# Generated deterministically by seda-macro-lef-normalizer-v1; recipe orfs-ng45-fakeram-metal3-coupledl2-pg-v1.
VERSION 5.8 ;
BUSBITCHARS "[]" ;
DIVIDERCHAR "/" ;

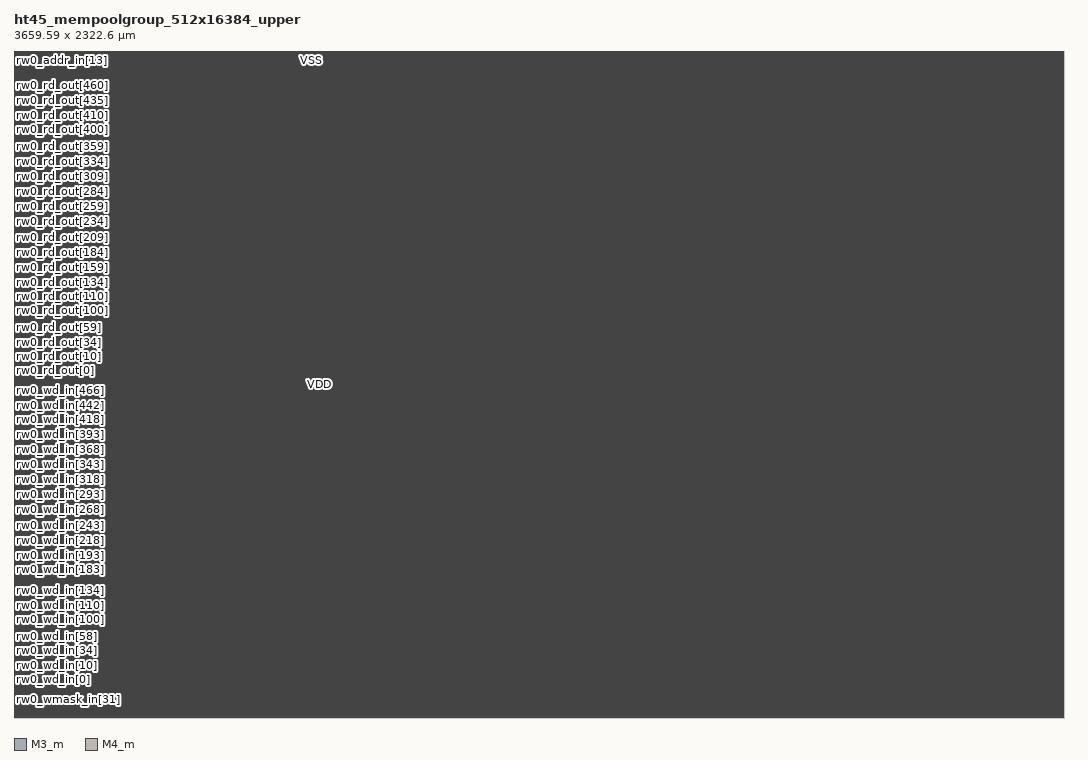
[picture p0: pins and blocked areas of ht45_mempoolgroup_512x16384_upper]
MACRO ht45_mempoolgroup_512x16384_upper
  FOREIGN ht45_mempoolgroup_512x16384_upper 0 0 ;
  CLASS COVER ;
  ORIGIN 0 0 ;
  SIZE 3659.59 BY 2322.6 ;
  SYMMETRY X Y R90 ;
  PIN rw0_wmask_in[0]
    DIRECTION INPUT ;
    USE SIGNAL ;
    SHAPE ABUTMENT ;
    PORT
      LAYER M3_m ;
      RECT 0 0.035 0.07 0.105 ;
    END
  END rw0_wmask_in[0]
  PIN rw0_wmask_in[1]
    DIRECTION INPUT ;
    USE SIGNAL ;
    SHAPE ABUTMENT ;
    PORT
      LAYER M3_m ;
      RECT 0 2.135 0.07 2.205 ;
    END
  END rw0_wmask_in[1]
  PIN rw0_wmask_in[2]
    DIRECTION INPUT ;
    USE SIGNAL ;
    SHAPE ABUTMENT ;
    PORT
      LAYER M3_m ;
      RECT 0 4.235 0.07 4.305 ;
    END
  END rw0_wmask_in[2]
  PIN rw0_wmask_in[3]
    DIRECTION INPUT ;
    USE SIGNAL ;
    SHAPE ABUTMENT ;
    PORT
      LAYER M3_m ;
      RECT 0 6.335 0.07 6.405 ;
    END
  END rw0_wmask_in[3]
  PIN rw0_wmask_in[4]
    DIRECTION INPUT ;
    USE SIGNAL ;
    SHAPE ABUTMENT ;
    PORT
      LAYER M3_m ;
      RECT 0 8.435 0.07 8.505 ;
    END
  END rw0_wmask_in[4]
  PIN rw0_wmask_in[5]
    DIRECTION INPUT ;
    USE SIGNAL ;
    SHAPE ABUTMENT ;
    PORT
      LAYER M3_m ;
      RECT 0 10.535 0.07 10.605 ;
    END
  END rw0_wmask_in[5]
  PIN rw0_wmask_in[6]
    DIRECTION INPUT ;
    USE SIGNAL ;
    SHAPE ABUTMENT ;
    PORT
      LAYER M3_m ;
      RECT 0 12.635 0.07 12.705 ;
    END
  END rw0_wmask_in[6]
  PIN rw0_wmask_in[7]
    DIRECTION INPUT ;
    USE SIGNAL ;
    SHAPE ABUTMENT ;
    PORT
      LAYER M3_m ;
      RECT 0 14.735 0.07 14.805 ;
    END
  END rw0_wmask_in[7]
  PIN rw0_wmask_in[8]
    DIRECTION INPUT ;
    USE SIGNAL ;
    SHAPE ABUTMENT ;
    PORT
      LAYER M3_m ;
      RECT 0 16.835 0.07 16.905 ;
    END
  END rw0_wmask_in[8]
  PIN rw0_wmask_in[9]
    DIRECTION INPUT ;
    USE SIGNAL ;
    SHAPE ABUTMENT ;
    PORT
      LAYER M3_m ;
      RECT 0 18.935 0.07 19.005 ;
    END
  END rw0_wmask_in[9]
  PIN rw0_wmask_in[10]
    DIRECTION INPUT ;
    USE SIGNAL ;
    SHAPE ABUTMENT ;
    PORT
      LAYER M3_m ;
      RECT 0 21.035 0.07 21.105 ;
    END
  END rw0_wmask_in[10]
  PIN rw0_wmask_in[11]
    DIRECTION INPUT ;
    USE SIGNAL ;
    SHAPE ABUTMENT ;
    PORT
      LAYER M3_m ;
      RECT 0 23.135 0.07 23.205 ;
    END
  END rw0_wmask_in[11]
  PIN rw0_wmask_in[12]
    DIRECTION INPUT ;
    USE SIGNAL ;
    SHAPE ABUTMENT ;
    PORT
      LAYER M3_m ;
      RECT 0 25.235 0.07 25.305 ;
    END
  END rw0_wmask_in[12]
  PIN rw0_wmask_in[13]
    DIRECTION INPUT ;
    USE SIGNAL ;
    SHAPE ABUTMENT ;
    PORT
      LAYER M3_m ;
      RECT 0 27.335 0.07 27.405 ;
    END
  END rw0_wmask_in[13]
  PIN rw0_wmask_in[14]
    DIRECTION INPUT ;
    USE SIGNAL ;
    SHAPE ABUTMENT ;
    PORT
      LAYER M3_m ;
      RECT 0 29.435 0.07 29.505 ;
    END
  END rw0_wmask_in[14]
  PIN rw0_wmask_in[15]
    DIRECTION INPUT ;
    USE SIGNAL ;
    SHAPE ABUTMENT ;
    PORT
      LAYER M3_m ;
      RECT 0 31.535 0.07 31.605 ;
    END
  END rw0_wmask_in[15]
  PIN rw0_wmask_in[16]
    DIRECTION INPUT ;
    USE SIGNAL ;
    SHAPE ABUTMENT ;
    PORT
      LAYER M3_m ;
      RECT 0 33.635 0.07 33.705 ;
    END
  END rw0_wmask_in[16]
  PIN rw0_wmask_in[17]
    DIRECTION INPUT ;
    USE SIGNAL ;
    SHAPE ABUTMENT ;
    PORT
      LAYER M3_m ;
      RECT 0 35.735 0.07 35.805 ;
    END
  END rw0_wmask_in[17]
  PIN rw0_wmask_in[18]
    DIRECTION INPUT ;
    USE SIGNAL ;
    SHAPE ABUTMENT ;
    PORT
      LAYER M3_m ;
      RECT 0 37.835 0.07 37.905 ;
    END
  END rw0_wmask_in[18]
  PIN rw0_wmask_in[19]
    DIRECTION INPUT ;
    USE SIGNAL ;
    SHAPE ABUTMENT ;
    PORT
      LAYER M3_m ;
      RECT 0 39.935 0.07 40.005 ;
    END
  END rw0_wmask_in[19]
  PIN rw0_wmask_in[20]
    DIRECTION INPUT ;
    USE SIGNAL ;
    SHAPE ABUTMENT ;
    PORT
      LAYER M3_m ;
      RECT 0 42.035 0.07 42.105 ;
    END
  END rw0_wmask_in[20]
  PIN rw0_wmask_in[21]
    DIRECTION INPUT ;
    USE SIGNAL ;
    SHAPE ABUTMENT ;
    PORT
      LAYER M3_m ;
      RECT 0 44.135 0.07 44.205 ;
    END
  END rw0_wmask_in[21]
  PIN rw0_wmask_in[22]
    DIRECTION INPUT ;
    USE SIGNAL ;
    SHAPE ABUTMENT ;
    PORT
      LAYER M3_m ;
      RECT 0 46.235 0.07 46.305 ;
    END
  END rw0_wmask_in[22]
  PIN rw0_wmask_in[23]
    DIRECTION INPUT ;
    USE SIGNAL ;
    SHAPE ABUTMENT ;
    PORT
      LAYER M3_m ;
      RECT 0 48.335 0.07 48.405 ;
    END
  END rw0_wmask_in[23]
  PIN rw0_wmask_in[24]
    DIRECTION INPUT ;
    USE SIGNAL ;
    SHAPE ABUTMENT ;
    PORT
      LAYER M3_m ;
      RECT 0 50.435 0.07 50.505 ;
    END
  END rw0_wmask_in[24]
  PIN rw0_wmask_in[25]
    DIRECTION INPUT ;
    USE SIGNAL ;
    SHAPE ABUTMENT ;
    PORT
      LAYER M3_m ;
      RECT 0 52.535 0.07 52.605 ;
    END
  END rw0_wmask_in[25]
  PIN rw0_wmask_in[26]
    DIRECTION INPUT ;
    USE SIGNAL ;
    SHAPE ABUTMENT ;
    PORT
      LAYER M3_m ;
      RECT 0 54.635 0.07 54.705 ;
    END
  END rw0_wmask_in[26]
  PIN rw0_wmask_in[27]
    DIRECTION INPUT ;
    USE SIGNAL ;
    SHAPE ABUTMENT ;
    PORT
      LAYER M3_m ;
      RECT 0 56.735 0.07 56.805 ;
    END
  END rw0_wmask_in[27]
  PIN rw0_wmask_in[28]
    DIRECTION INPUT ;
    USE SIGNAL ;
    SHAPE ABUTMENT ;
    PORT
      LAYER M3_m ;
      RECT 0 58.835 0.07 58.905 ;
    END
  END rw0_wmask_in[28]
  PIN rw0_wmask_in[29]
    DIRECTION INPUT ;
    USE SIGNAL ;
    SHAPE ABUTMENT ;
    PORT
      LAYER M3_m ;
      RECT 0 60.935 0.07 61.005 ;
    END
  END rw0_wmask_in[29]
  PIN rw0_wmask_in[30]
    DIRECTION INPUT ;
    USE SIGNAL ;
    SHAPE ABUTMENT ;
    PORT
      LAYER M3_m ;
      RECT 0 63.035 0.07 63.105 ;
    END
  END rw0_wmask_in[30]
  PIN rw0_wmask_in[31]
    DIRECTION INPUT ;
    USE SIGNAL ;
    SHAPE ABUTMENT ;
    PORT
      LAYER M3_m ;
      RECT 0 65.135 0.07 65.205 ;
    END
  END rw0_wmask_in[31]
  PIN rw0_wmask_in[32]
    DIRECTION INPUT ;
    USE SIGNAL ;
    SHAPE ABUTMENT ;
    PORT
      LAYER M3_m ;
      RECT 0 67.235 0.07 67.305 ;
    END
  END rw0_wmask_in[32]
  PIN rw0_wmask_in[33]
    DIRECTION INPUT ;
    USE SIGNAL ;
    SHAPE ABUTMENT ;
    PORT
      LAYER M3_m ;
      RECT 0 69.335 0.07 69.405 ;
    END
  END rw0_wmask_in[33]
  PIN rw0_wmask_in[34]
    DIRECTION INPUT ;
    USE SIGNAL ;
    SHAPE ABUTMENT ;
    PORT
      LAYER M3_m ;
      RECT 0 71.435 0.07 71.505 ;
    END
  END rw0_wmask_in[34]
  PIN rw0_wmask_in[35]
    DIRECTION INPUT ;
    USE SIGNAL ;
    SHAPE ABUTMENT ;
    PORT
      LAYER M3_m ;
      RECT 0 73.535 0.07 73.605 ;
    END
  END rw0_wmask_in[35]
  PIN rw0_wmask_in[36]
    DIRECTION INPUT ;
    USE SIGNAL ;
    SHAPE ABUTMENT ;
    PORT
      LAYER M3_m ;
      RECT 0 75.635 0.07 75.705 ;
    END
  END rw0_wmask_in[36]
  PIN rw0_wmask_in[37]
    DIRECTION INPUT ;
    USE SIGNAL ;
    SHAPE ABUTMENT ;
    PORT
      LAYER M3_m ;
      RECT 0 77.735 0.07 77.805 ;
    END
  END rw0_wmask_in[37]
  PIN rw0_wmask_in[38]
    DIRECTION INPUT ;
    USE SIGNAL ;
    SHAPE ABUTMENT ;
    PORT
      LAYER M3_m ;
      RECT 0 79.835 0.07 79.905 ;
    END
  END rw0_wmask_in[38]
  PIN rw0_wmask_in[39]
    DIRECTION INPUT ;
    USE SIGNAL ;
    SHAPE ABUTMENT ;
    PORT
      LAYER M3_m ;
      RECT 0 81.935 0.07 82.005 ;
    END
  END rw0_wmask_in[39]
  PIN rw0_wmask_in[40]
    DIRECTION INPUT ;
    USE SIGNAL ;
    SHAPE ABUTMENT ;
    PORT
      LAYER M3_m ;
      RECT 0 84.035 0.07 84.105 ;
    END
  END rw0_wmask_in[40]
  PIN rw0_wmask_in[41]
    DIRECTION INPUT ;
    USE SIGNAL ;
    SHAPE ABUTMENT ;
    PORT
      LAYER M3_m ;
      RECT 0 86.135 0.07 86.205 ;
    END
  END rw0_wmask_in[41]
  PIN rw0_wmask_in[42]
    DIRECTION INPUT ;
    USE SIGNAL ;
    SHAPE ABUTMENT ;
    PORT
      LAYER M3_m ;
      RECT 0 88.235 0.07 88.305 ;
    END
  END rw0_wmask_in[42]
  PIN rw0_wmask_in[43]
    DIRECTION INPUT ;
    USE SIGNAL ;
    SHAPE ABUTMENT ;
    PORT
      LAYER M3_m ;
      RECT 0 90.335 0.07 90.405 ;
    END
  END rw0_wmask_in[43]
  PIN rw0_wmask_in[44]
    DIRECTION INPUT ;
    USE SIGNAL ;
    SHAPE ABUTMENT ;
    PORT
      LAYER M3_m ;
      RECT 0 92.435 0.07 92.505 ;
    END
  END rw0_wmask_in[44]
  PIN rw0_wmask_in[45]
    DIRECTION INPUT ;
    USE SIGNAL ;
    SHAPE ABUTMENT ;
    PORT
      LAYER M3_m ;
      RECT 0 94.535 0.07 94.605 ;
    END
  END rw0_wmask_in[45]
  PIN rw0_wmask_in[46]
    DIRECTION INPUT ;
    USE SIGNAL ;
    SHAPE ABUTMENT ;
    PORT
      LAYER M3_m ;
      RECT 0 96.635 0.07 96.705 ;
    END
  END rw0_wmask_in[46]
  PIN rw0_wmask_in[47]
    DIRECTION INPUT ;
    USE SIGNAL ;
    SHAPE ABUTMENT ;
    PORT
      LAYER M3_m ;
      RECT 0 98.735 0.07 98.805 ;
    END
  END rw0_wmask_in[47]
  PIN rw0_wmask_in[48]
    DIRECTION INPUT ;
    USE SIGNAL ;
    SHAPE ABUTMENT ;
    PORT
      LAYER M3_m ;
      RECT 0 100.835 0.07 100.905 ;
    END
  END rw0_wmask_in[48]
  PIN rw0_wmask_in[49]
    DIRECTION INPUT ;
    USE SIGNAL ;
    SHAPE ABUTMENT ;
    PORT
      LAYER M3_m ;
      RECT 0 102.935 0.07 103.005 ;
    END
  END rw0_wmask_in[49]
  PIN rw0_wmask_in[50]
    DIRECTION INPUT ;
    USE SIGNAL ;
    SHAPE ABUTMENT ;
    PORT
      LAYER M3_m ;
      RECT 0 105.035 0.07 105.105 ;
    END
  END rw0_wmask_in[50]
  PIN rw0_wmask_in[51]
    DIRECTION INPUT ;
    USE SIGNAL ;
    SHAPE ABUTMENT ;
    PORT
      LAYER M3_m ;
      RECT 0 107.135 0.07 107.205 ;
    END
  END rw0_wmask_in[51]
  PIN rw0_wmask_in[52]
    DIRECTION INPUT ;
    USE SIGNAL ;
    SHAPE ABUTMENT ;
    PORT
      LAYER M3_m ;
      RECT 0 109.235 0.07 109.305 ;
    END
  END rw0_wmask_in[52]
  PIN rw0_wmask_in[53]
    DIRECTION INPUT ;
    USE SIGNAL ;
    SHAPE ABUTMENT ;
    PORT
      LAYER M3_m ;
      RECT 0 111.335 0.07 111.405 ;
    END
  END rw0_wmask_in[53]
  PIN rw0_wmask_in[54]
    DIRECTION INPUT ;
    USE SIGNAL ;
    SHAPE ABUTMENT ;
    PORT
      LAYER M3_m ;
      RECT 0 113.435 0.07 113.505 ;
    END
  END rw0_wmask_in[54]
  PIN rw0_wmask_in[55]
    DIRECTION INPUT ;
    USE SIGNAL ;
    SHAPE ABUTMENT ;
    PORT
      LAYER M3_m ;
      RECT 0 115.535 0.07 115.605 ;
    END
  END rw0_wmask_in[55]
  PIN rw0_wmask_in[56]
    DIRECTION INPUT ;
    USE SIGNAL ;
    SHAPE ABUTMENT ;
    PORT
      LAYER M3_m ;
      RECT 0 117.635 0.07 117.705 ;
    END
  END rw0_wmask_in[56]
  PIN rw0_wmask_in[57]
    DIRECTION INPUT ;
    USE SIGNAL ;
    SHAPE ABUTMENT ;
    PORT
      LAYER M3_m ;
      RECT 0 119.735 0.07 119.805 ;
    END
  END rw0_wmask_in[57]
  PIN rw0_wmask_in[58]
    DIRECTION INPUT ;
    USE SIGNAL ;
    SHAPE ABUTMENT ;
    PORT
      LAYER M3_m ;
      RECT 0 121.835 0.07 121.905 ;
    END
  END rw0_wmask_in[58]
  PIN rw0_wmask_in[59]
    DIRECTION INPUT ;
    USE SIGNAL ;
    SHAPE ABUTMENT ;
    PORT
      LAYER M3_m ;
      RECT 0 123.935 0.07 124.005 ;
    END
  END rw0_wmask_in[59]
  PIN rw0_wmask_in[60]
    DIRECTION INPUT ;
    USE SIGNAL ;
    SHAPE ABUTMENT ;
    PORT
      LAYER M3_m ;
      RECT 0 126.035 0.07 126.105 ;
    END
  END rw0_wmask_in[60]
  PIN rw0_wmask_in[61]
    DIRECTION INPUT ;
    USE SIGNAL ;
    SHAPE ABUTMENT ;
    PORT
      LAYER M3_m ;
      RECT 0 128.135 0.07 128.205 ;
    END
  END rw0_wmask_in[61]
  PIN rw0_wmask_in[62]
    DIRECTION INPUT ;
    USE SIGNAL ;
    SHAPE ABUTMENT ;
    PORT
      LAYER M3_m ;
      RECT 0 130.235 0.07 130.305 ;
    END
  END rw0_wmask_in[62]
  PIN rw0_wmask_in[63]
    DIRECTION INPUT ;
    USE SIGNAL ;
    SHAPE ABUTMENT ;
    PORT
      LAYER M3_m ;
      RECT 0 132.335 0.07 132.405 ;
    END
  END rw0_wmask_in[63]
  PIN rw0_wd_in[0]
    DIRECTION INPUT ;
    USE SIGNAL ;
    SHAPE ABUTMENT ;
    PORT
      LAYER M3_m ;
      RECT 0 134.435 0.07 134.505 ;
    END
  END rw0_wd_in[0]
  PIN rw0_wd_in[1]
    DIRECTION INPUT ;
    USE SIGNAL ;
    SHAPE ABUTMENT ;
    PORT
      LAYER M3_m ;
      RECT 0 136.535 0.07 136.605 ;
    END
  END rw0_wd_in[1]
  PIN rw0_wd_in[2]
    DIRECTION INPUT ;
    USE SIGNAL ;
    SHAPE ABUTMENT ;
    PORT
      LAYER M3_m ;
      RECT 0 138.635 0.07 138.705 ;
    END
  END rw0_wd_in[2]
  PIN rw0_wd_in[3]
    DIRECTION INPUT ;
    USE SIGNAL ;
    SHAPE ABUTMENT ;
    PORT
      LAYER M3_m ;
      RECT 0 140.735 0.07 140.805 ;
    END
  END rw0_wd_in[3]
  PIN rw0_wd_in[4]
    DIRECTION INPUT ;
    USE SIGNAL ;
    SHAPE ABUTMENT ;
    PORT
      LAYER M3_m ;
      RECT 0 142.835 0.07 142.905 ;
    END
  END rw0_wd_in[4]
  PIN rw0_wd_in[5]
    DIRECTION INPUT ;
    USE SIGNAL ;
    SHAPE ABUTMENT ;
    PORT
      LAYER M3_m ;
      RECT 0 144.935 0.07 145.005 ;
    END
  END rw0_wd_in[5]
  PIN rw0_wd_in[6]
    DIRECTION INPUT ;
    USE SIGNAL ;
    SHAPE ABUTMENT ;
    PORT
      LAYER M3_m ;
      RECT 0 147.035 0.07 147.105 ;
    END
  END rw0_wd_in[6]
  PIN rw0_wd_in[7]
    DIRECTION INPUT ;
    USE SIGNAL ;
    SHAPE ABUTMENT ;
    PORT
      LAYER M3_m ;
      RECT 0 149.135 0.07 149.205 ;
    END
  END rw0_wd_in[7]
  PIN rw0_wd_in[8]
    DIRECTION INPUT ;
    USE SIGNAL ;
    SHAPE ABUTMENT ;
    PORT
      LAYER M3_m ;
      RECT 0 151.235 0.07 151.305 ;
    END
  END rw0_wd_in[8]
  PIN rw0_wd_in[9]
    DIRECTION INPUT ;
    USE SIGNAL ;
    SHAPE ABUTMENT ;
    PORT
      LAYER M3_m ;
      RECT 0 153.335 0.07 153.405 ;
    END
  END rw0_wd_in[9]
  PIN rw0_wd_in[10]
    DIRECTION INPUT ;
    USE SIGNAL ;
    SHAPE ABUTMENT ;
    PORT
      LAYER M3_m ;
      RECT 0 155.435 0.07 155.505 ;
    END
  END rw0_wd_in[10]
  PIN rw0_wd_in[11]
    DIRECTION INPUT ;
    USE SIGNAL ;
    SHAPE ABUTMENT ;
    PORT
      LAYER M3_m ;
      RECT 0 157.535 0.07 157.605 ;
    END
  END rw0_wd_in[11]
  PIN rw0_wd_in[12]
    DIRECTION INPUT ;
    USE SIGNAL ;
    SHAPE ABUTMENT ;
    PORT
      LAYER M3_m ;
      RECT 0 159.635 0.07 159.705 ;
    END
  END rw0_wd_in[12]
  PIN rw0_wd_in[13]
    DIRECTION INPUT ;
    USE SIGNAL ;
    SHAPE ABUTMENT ;
    PORT
      LAYER M3_m ;
      RECT 0 161.735 0.07 161.805 ;
    END
  END rw0_wd_in[13]
  PIN rw0_wd_in[14]
    DIRECTION INPUT ;
    USE SIGNAL ;
    SHAPE ABUTMENT ;
    PORT
      LAYER M3_m ;
      RECT 0 163.835 0.07 163.905 ;
    END
  END rw0_wd_in[14]
  PIN rw0_wd_in[15]
    DIRECTION INPUT ;
    USE SIGNAL ;
    SHAPE ABUTMENT ;
    PORT
      LAYER M3_m ;
      RECT 0 165.935 0.07 166.005 ;
    END
  END rw0_wd_in[15]
  PIN rw0_wd_in[16]
    DIRECTION INPUT ;
    USE SIGNAL ;
    SHAPE ABUTMENT ;
    PORT
      LAYER M3_m ;
      RECT 0 168.035 0.07 168.105 ;
    END
  END rw0_wd_in[16]
  PIN rw0_wd_in[17]
    DIRECTION INPUT ;
    USE SIGNAL ;
    SHAPE ABUTMENT ;
    PORT
      LAYER M3_m ;
      RECT 0 170.135 0.07 170.205 ;
    END
  END rw0_wd_in[17]
  PIN rw0_wd_in[18]
    DIRECTION INPUT ;
    USE SIGNAL ;
    SHAPE ABUTMENT ;
    PORT
      LAYER M3_m ;
      RECT 0 172.235 0.07 172.305 ;
    END
  END rw0_wd_in[18]
  PIN rw0_wd_in[19]
    DIRECTION INPUT ;
    USE SIGNAL ;
    SHAPE ABUTMENT ;
    PORT
      LAYER M3_m ;
      RECT 0 174.335 0.07 174.405 ;
    END
  END rw0_wd_in[19]
  PIN rw0_wd_in[20]
    DIRECTION INPUT ;
    USE SIGNAL ;
    SHAPE ABUTMENT ;
    PORT
      LAYER M3_m ;
      RECT 0 176.435 0.07 176.505 ;
    END
  END rw0_wd_in[20]
  PIN rw0_wd_in[21]
    DIRECTION INPUT ;
    USE SIGNAL ;
    SHAPE ABUTMENT ;
    PORT
      LAYER M3_m ;
      RECT 0 178.535 0.07 178.605 ;
    END
  END rw0_wd_in[21]
  PIN rw0_wd_in[22]
    DIRECTION INPUT ;
    USE SIGNAL ;
    SHAPE ABUTMENT ;
    PORT
      LAYER M3_m ;
      RECT 0 180.635 0.07 180.705 ;
    END
  END rw0_wd_in[22]
  PIN rw0_wd_in[23]
    DIRECTION INPUT ;
    USE SIGNAL ;
    SHAPE ABUTMENT ;
    PORT
      LAYER M3_m ;
      RECT 0 182.735 0.07 182.805 ;
    END
  END rw0_wd_in[23]
  PIN rw0_wd_in[24]
    DIRECTION INPUT ;
    USE SIGNAL ;
    SHAPE ABUTMENT ;
    PORT
      LAYER M3_m ;
      RECT 0 184.835 0.07 184.905 ;
    END
  END rw0_wd_in[24]
  PIN rw0_wd_in[25]
    DIRECTION INPUT ;
    USE SIGNAL ;
    SHAPE ABUTMENT ;
    PORT
      LAYER M3_m ;
      RECT 0 186.935 0.07 187.005 ;
    END
  END rw0_wd_in[25]
  PIN rw0_wd_in[26]
    DIRECTION INPUT ;
    USE SIGNAL ;
    SHAPE ABUTMENT ;
    PORT
      LAYER M3_m ;
      RECT 0 189.035 0.07 189.105 ;
    END
  END rw0_wd_in[26]
  PIN rw0_wd_in[27]
    DIRECTION INPUT ;
    USE SIGNAL ;
    SHAPE ABUTMENT ;
    PORT
      LAYER M3_m ;
      RECT 0 191.135 0.07 191.205 ;
    END
  END rw0_wd_in[27]
  PIN rw0_wd_in[28]
    DIRECTION INPUT ;
    USE SIGNAL ;
    SHAPE ABUTMENT ;
    PORT
      LAYER M3_m ;
      RECT 0 193.235 0.07 193.305 ;
    END
  END rw0_wd_in[28]
  PIN rw0_wd_in[29]
    DIRECTION INPUT ;
    USE SIGNAL ;
    SHAPE ABUTMENT ;
    PORT
      LAYER M3_m ;
      RECT 0 195.335 0.07 195.405 ;
    END
  END rw0_wd_in[29]
  PIN rw0_wd_in[30]
    DIRECTION INPUT ;
    USE SIGNAL ;
    SHAPE ABUTMENT ;
    PORT
      LAYER M3_m ;
      RECT 0 197.435 0.07 197.505 ;
    END
  END rw0_wd_in[30]
  PIN rw0_wd_in[31]
    DIRECTION INPUT ;
    USE SIGNAL ;
    SHAPE ABUTMENT ;
    PORT
      LAYER M3_m ;
      RECT 0 199.535 0.07 199.605 ;
    END
  END rw0_wd_in[31]
  PIN rw0_wd_in[32]
    DIRECTION INPUT ;
    USE SIGNAL ;
    SHAPE ABUTMENT ;
    PORT
      LAYER M3_m ;
      RECT 0 201.635 0.07 201.705 ;
    END
  END rw0_wd_in[32]
  PIN rw0_wd_in[33]
    DIRECTION INPUT ;
    USE SIGNAL ;
    SHAPE ABUTMENT ;
    PORT
      LAYER M3_m ;
      RECT 0 203.735 0.07 203.805 ;
    END
  END rw0_wd_in[33]
  PIN rw0_wd_in[34]
    DIRECTION INPUT ;
    USE SIGNAL ;
    SHAPE ABUTMENT ;
    PORT
      LAYER M3_m ;
      RECT 0 205.835 0.07 205.905 ;
    END
  END rw0_wd_in[34]
  PIN rw0_wd_in[35]
    DIRECTION INPUT ;
    USE SIGNAL ;
    SHAPE ABUTMENT ;
    PORT
      LAYER M3_m ;
      RECT 0 207.935 0.07 208.005 ;
    END
  END rw0_wd_in[35]
  PIN rw0_wd_in[36]
    DIRECTION INPUT ;
    USE SIGNAL ;
    SHAPE ABUTMENT ;
    PORT
      LAYER M3_m ;
      RECT 0 210.035 0.07 210.105 ;
    END
  END rw0_wd_in[36]
  PIN rw0_wd_in[37]
    DIRECTION INPUT ;
    USE SIGNAL ;
    SHAPE ABUTMENT ;
    PORT
      LAYER M3_m ;
      RECT 0 212.135 0.07 212.205 ;
    END
  END rw0_wd_in[37]
  PIN rw0_wd_in[38]
    DIRECTION INPUT ;
    USE SIGNAL ;
    SHAPE ABUTMENT ;
    PORT
      LAYER M3_m ;
      RECT 0 214.235 0.07 214.305 ;
    END
  END rw0_wd_in[38]
  PIN rw0_wd_in[39]
    DIRECTION INPUT ;
    USE SIGNAL ;
    SHAPE ABUTMENT ;
    PORT
      LAYER M3_m ;
      RECT 0 216.335 0.07 216.405 ;
    END
  END rw0_wd_in[39]
  PIN rw0_wd_in[40]
    DIRECTION INPUT ;
    USE SIGNAL ;
    SHAPE ABUTMENT ;
    PORT
      LAYER M3_m ;
      RECT 0 218.435 0.07 218.505 ;
    END
  END rw0_wd_in[40]
  PIN rw0_wd_in[41]
    DIRECTION INPUT ;
    USE SIGNAL ;
    SHAPE ABUTMENT ;
    PORT
      LAYER M3_m ;
      RECT 0 220.535 0.07 220.605 ;
    END
  END rw0_wd_in[41]
  PIN rw0_wd_in[42]
    DIRECTION INPUT ;
    USE SIGNAL ;
    SHAPE ABUTMENT ;
    PORT
      LAYER M3_m ;
      RECT 0 222.635 0.07 222.705 ;
    END
  END rw0_wd_in[42]
  PIN rw0_wd_in[43]
    DIRECTION INPUT ;
    USE SIGNAL ;
    SHAPE ABUTMENT ;
    PORT
      LAYER M3_m ;
      RECT 0 224.735 0.07 224.805 ;
    END
  END rw0_wd_in[43]
  PIN rw0_wd_in[44]
    DIRECTION INPUT ;
    USE SIGNAL ;
    SHAPE ABUTMENT ;
    PORT
      LAYER M3_m ;
      RECT 0 226.835 0.07 226.905 ;
    END
  END rw0_wd_in[44]
  PIN rw0_wd_in[45]
    DIRECTION INPUT ;
    USE SIGNAL ;
    SHAPE ABUTMENT ;
    PORT
      LAYER M3_m ;
      RECT 0 228.935 0.07 229.005 ;
    END
  END rw0_wd_in[45]
  PIN rw0_wd_in[46]
    DIRECTION INPUT ;
    USE SIGNAL ;
    SHAPE ABUTMENT ;
    PORT
      LAYER M3_m ;
      RECT 0 231.035 0.07 231.105 ;
    END
  END rw0_wd_in[46]
  PIN rw0_wd_in[47]
    DIRECTION INPUT ;
    USE SIGNAL ;
    SHAPE ABUTMENT ;
    PORT
      LAYER M3_m ;
      RECT 0 233.135 0.07 233.205 ;
    END
  END rw0_wd_in[47]
  PIN rw0_wd_in[48]
    DIRECTION INPUT ;
    USE SIGNAL ;
    SHAPE ABUTMENT ;
    PORT
      LAYER M3_m ;
      RECT 0 235.235 0.07 235.305 ;
    END
  END rw0_wd_in[48]
  PIN rw0_wd_in[49]
    DIRECTION INPUT ;
    USE SIGNAL ;
    SHAPE ABUTMENT ;
    PORT
      LAYER M3_m ;
      RECT 0 237.335 0.07 237.405 ;
    END
  END rw0_wd_in[49]
  PIN rw0_wd_in[50]
    DIRECTION INPUT ;
    USE SIGNAL ;
    SHAPE ABUTMENT ;
    PORT
      LAYER M3_m ;
      RECT 0 239.435 0.07 239.505 ;
    END
  END rw0_wd_in[50]
  PIN rw0_wd_in[51]
    DIRECTION INPUT ;
    USE SIGNAL ;
    SHAPE ABUTMENT ;
    PORT
      LAYER M3_m ;
      RECT 0 241.535 0.07 241.605 ;
    END
  END rw0_wd_in[51]
  PIN rw0_wd_in[52]
    DIRECTION INPUT ;
    USE SIGNAL ;
    SHAPE ABUTMENT ;
    PORT
      LAYER M3_m ;
      RECT 0 243.635 0.07 243.705 ;
    END
  END rw0_wd_in[52]
  PIN rw0_wd_in[53]
    DIRECTION INPUT ;
    USE SIGNAL ;
    SHAPE ABUTMENT ;
    PORT
      LAYER M3_m ;
      RECT 0 245.735 0.07 245.805 ;
    END
  END rw0_wd_in[53]
  PIN rw0_wd_in[54]
    DIRECTION INPUT ;
    USE SIGNAL ;
    SHAPE ABUTMENT ;
    PORT
      LAYER M3_m ;
      RECT 0 247.835 0.07 247.905 ;
    END
  END rw0_wd_in[54]
  PIN rw0_wd_in[55]
    DIRECTION INPUT ;
    USE SIGNAL ;
    SHAPE ABUTMENT ;
    PORT
      LAYER M3_m ;
      RECT 0 249.935 0.07 250.005 ;
    END
  END rw0_wd_in[55]
  PIN rw0_wd_in[56]
    DIRECTION INPUT ;
    USE SIGNAL ;
    SHAPE ABUTMENT ;
    PORT
      LAYER M3_m ;
      RECT 0 252.035 0.07 252.105 ;
    END
  END rw0_wd_in[56]
  PIN rw0_wd_in[57]
    DIRECTION INPUT ;
    USE SIGNAL ;
    SHAPE ABUTMENT ;
    PORT
      LAYER M3_m ;
      RECT 0 254.135 0.07 254.205 ;
    END
  END rw0_wd_in[57]
  PIN rw0_wd_in[58]
    DIRECTION INPUT ;
    USE SIGNAL ;
    SHAPE ABUTMENT ;
    PORT
      LAYER M3_m ;
      RECT 0 256.235 0.07 256.305 ;
    END
  END rw0_wd_in[58]
  PIN rw0_wd_in[59]
    DIRECTION INPUT ;
    USE SIGNAL ;
    SHAPE ABUTMENT ;
    PORT
      LAYER M3_m ;
      RECT 0 258.335 0.07 258.405 ;
    END
  END rw0_wd_in[59]
  PIN rw0_wd_in[60]
    DIRECTION INPUT ;
    USE SIGNAL ;
    SHAPE ABUTMENT ;
    PORT
      LAYER M3_m ;
      RECT 0 260.435 0.07 260.505 ;
    END
  END rw0_wd_in[60]
  PIN rw0_wd_in[61]
    DIRECTION INPUT ;
    USE SIGNAL ;
    SHAPE ABUTMENT ;
    PORT
      LAYER M3_m ;
      RECT 0 262.535 0.07 262.605 ;
    END
  END rw0_wd_in[61]
  PIN rw0_wd_in[62]
    DIRECTION INPUT ;
    USE SIGNAL ;
    SHAPE ABUTMENT ;
    PORT
      LAYER M3_m ;
      RECT 0 264.635 0.07 264.705 ;
    END
  END rw0_wd_in[62]
  PIN rw0_wd_in[63]
    DIRECTION INPUT ;
    USE SIGNAL ;
    SHAPE ABUTMENT ;
    PORT
      LAYER M3_m ;
      RECT 0 266.735 0.07 266.805 ;
    END
  END rw0_wd_in[63]
  PIN rw0_wd_in[64]
    DIRECTION INPUT ;
    USE SIGNAL ;
    SHAPE ABUTMENT ;
    PORT
      LAYER M3_m ;
      RECT 0 268.835 0.07 268.905 ;
    END
  END rw0_wd_in[64]
  PIN rw0_wd_in[65]
    DIRECTION INPUT ;
    USE SIGNAL ;
    SHAPE ABUTMENT ;
    PORT
      LAYER M3_m ;
      RECT 0 270.935 0.07 271.005 ;
    END
  END rw0_wd_in[65]
  PIN rw0_wd_in[66]
    DIRECTION INPUT ;
    USE SIGNAL ;
    SHAPE ABUTMENT ;
    PORT
      LAYER M3_m ;
      RECT 0 273.035 0.07 273.105 ;
    END
  END rw0_wd_in[66]
  PIN rw0_wd_in[67]
    DIRECTION INPUT ;
    USE SIGNAL ;
    SHAPE ABUTMENT ;
    PORT
      LAYER M3_m ;
      RECT 0 275.135 0.07 275.205 ;
    END
  END rw0_wd_in[67]
  PIN rw0_wd_in[68]
    DIRECTION INPUT ;
    USE SIGNAL ;
    SHAPE ABUTMENT ;
    PORT
      LAYER M3_m ;
      RECT 0 277.235 0.07 277.305 ;
    END
  END rw0_wd_in[68]
  PIN rw0_wd_in[69]
    DIRECTION INPUT ;
    USE SIGNAL ;
    SHAPE ABUTMENT ;
    PORT
      LAYER M3_m ;
      RECT 0 279.335 0.07 279.405 ;
    END
  END rw0_wd_in[69]
  PIN rw0_wd_in[70]
    DIRECTION INPUT ;
    USE SIGNAL ;
    SHAPE ABUTMENT ;
    PORT
      LAYER M3_m ;
      RECT 0 281.435 0.07 281.505 ;
    END
  END rw0_wd_in[70]
  PIN rw0_wd_in[71]
    DIRECTION INPUT ;
    USE SIGNAL ;
    SHAPE ABUTMENT ;
    PORT
      LAYER M3_m ;
      RECT 0 283.535 0.07 283.605 ;
    END
  END rw0_wd_in[71]
  PIN rw0_wd_in[72]
    DIRECTION INPUT ;
    USE SIGNAL ;
    SHAPE ABUTMENT ;
    PORT
      LAYER M3_m ;
      RECT 0 285.635 0.07 285.705 ;
    END
  END rw0_wd_in[72]
  PIN rw0_wd_in[73]
    DIRECTION INPUT ;
    USE SIGNAL ;
    SHAPE ABUTMENT ;
    PORT
      LAYER M3_m ;
      RECT 0 287.735 0.07 287.805 ;
    END
  END rw0_wd_in[73]
  PIN rw0_wd_in[74]
    DIRECTION INPUT ;
    USE SIGNAL ;
    SHAPE ABUTMENT ;
    PORT
      LAYER M3_m ;
      RECT 0 289.835 0.07 289.905 ;
    END
  END rw0_wd_in[74]
  PIN rw0_wd_in[75]
    DIRECTION INPUT ;
    USE SIGNAL ;
    SHAPE ABUTMENT ;
    PORT
      LAYER M3_m ;
      RECT 0 291.935 0.07 292.005 ;
    END
  END rw0_wd_in[75]
  PIN rw0_wd_in[76]
    DIRECTION INPUT ;
    USE SIGNAL ;
    SHAPE ABUTMENT ;
    PORT
      LAYER M3_m ;
      RECT 0 294.035 0.07 294.105 ;
    END
  END rw0_wd_in[76]
  PIN rw0_wd_in[77]
    DIRECTION INPUT ;
    USE SIGNAL ;
    SHAPE ABUTMENT ;
    PORT
      LAYER M3_m ;
      RECT 0 296.135 0.07 296.205 ;
    END
  END rw0_wd_in[77]
  PIN rw0_wd_in[78]
    DIRECTION INPUT ;
    USE SIGNAL ;
    SHAPE ABUTMENT ;
    PORT
      LAYER M3_m ;
      RECT 0 298.235 0.07 298.305 ;
    END
  END rw0_wd_in[78]
  PIN rw0_wd_in[79]
    DIRECTION INPUT ;
    USE SIGNAL ;
    SHAPE ABUTMENT ;
    PORT
      LAYER M3_m ;
      RECT 0 300.335 0.07 300.405 ;
    END
  END rw0_wd_in[79]
  PIN rw0_wd_in[80]
    DIRECTION INPUT ;
    USE SIGNAL ;
    SHAPE ABUTMENT ;
    PORT
      LAYER M3_m ;
      RECT 0 302.435 0.07 302.505 ;
    END
  END rw0_wd_in[80]
  PIN rw0_wd_in[81]
    DIRECTION INPUT ;
    USE SIGNAL ;
    SHAPE ABUTMENT ;
    PORT
      LAYER M3_m ;
      RECT 0 304.535 0.07 304.605 ;
    END
  END rw0_wd_in[81]
  PIN rw0_wd_in[82]
    DIRECTION INPUT ;
    USE SIGNAL ;
    SHAPE ABUTMENT ;
    PORT
      LAYER M3_m ;
      RECT 0 306.635 0.07 306.705 ;
    END
  END rw0_wd_in[82]
  PIN rw0_wd_in[83]
    DIRECTION INPUT ;
    USE SIGNAL ;
    SHAPE ABUTMENT ;
    PORT
      LAYER M3_m ;
      RECT 0 308.735 0.07 308.805 ;
    END
  END rw0_wd_in[83]
  PIN rw0_wd_in[84]
    DIRECTION INPUT ;
    USE SIGNAL ;
    SHAPE ABUTMENT ;
    PORT
      LAYER M3_m ;
      RECT 0 310.835 0.07 310.905 ;
    END
  END rw0_wd_in[84]
  PIN rw0_wd_in[85]
    DIRECTION INPUT ;
    USE SIGNAL ;
    SHAPE ABUTMENT ;
    PORT
      LAYER M3_m ;
      RECT 0 312.935 0.07 313.005 ;
    END
  END rw0_wd_in[85]
  PIN rw0_wd_in[86]
    DIRECTION INPUT ;
    USE SIGNAL ;
    SHAPE ABUTMENT ;
    PORT
      LAYER M3_m ;
      RECT 0 315.035 0.07 315.105 ;
    END
  END rw0_wd_in[86]
  PIN rw0_wd_in[87]
    DIRECTION INPUT ;
    USE SIGNAL ;
    SHAPE ABUTMENT ;
    PORT
      LAYER M3_m ;
      RECT 0 317.135 0.07 317.205 ;
    END
  END rw0_wd_in[87]
  PIN rw0_wd_in[88]
    DIRECTION INPUT ;
    USE SIGNAL ;
    SHAPE ABUTMENT ;
    PORT
      LAYER M3_m ;
      RECT 0 319.235 0.07 319.305 ;
    END
  END rw0_wd_in[88]
  PIN rw0_wd_in[89]
    DIRECTION INPUT ;
    USE SIGNAL ;
    SHAPE ABUTMENT ;
    PORT
      LAYER M3_m ;
      RECT 0 321.335 0.07 321.405 ;
    END
  END rw0_wd_in[89]
  PIN rw0_wd_in[90]
    DIRECTION INPUT ;
    USE SIGNAL ;
    SHAPE ABUTMENT ;
    PORT
      LAYER M3_m ;
      RECT 0 323.435 0.07 323.505 ;
    END
  END rw0_wd_in[90]
  PIN rw0_wd_in[91]
    DIRECTION INPUT ;
    USE SIGNAL ;
    SHAPE ABUTMENT ;
    PORT
      LAYER M3_m ;
      RECT 0 325.535 0.07 325.605 ;
    END
  END rw0_wd_in[91]
  PIN rw0_wd_in[92]
    DIRECTION INPUT ;
    USE SIGNAL ;
    SHAPE ABUTMENT ;
    PORT
      LAYER M3_m ;
      RECT 0 327.635 0.07 327.705 ;
    END
  END rw0_wd_in[92]
  PIN rw0_wd_in[93]
    DIRECTION INPUT ;
    USE SIGNAL ;
    SHAPE ABUTMENT ;
    PORT
      LAYER M3_m ;
      RECT 0 329.735 0.07 329.805 ;
    END
  END rw0_wd_in[93]
  PIN rw0_wd_in[94]
    DIRECTION INPUT ;
    USE SIGNAL ;
    SHAPE ABUTMENT ;
    PORT
      LAYER M3_m ;
      RECT 0 331.835 0.07 331.905 ;
    END
  END rw0_wd_in[94]
  PIN rw0_wd_in[95]
    DIRECTION INPUT ;
    USE SIGNAL ;
    SHAPE ABUTMENT ;
    PORT
      LAYER M3_m ;
      RECT 0 333.935 0.07 334.005 ;
    END
  END rw0_wd_in[95]
  PIN rw0_wd_in[96]
    DIRECTION INPUT ;
    USE SIGNAL ;
    SHAPE ABUTMENT ;
    PORT
      LAYER M3_m ;
      RECT 0 336.035 0.07 336.105 ;
    END
  END rw0_wd_in[96]
  PIN rw0_wd_in[97]
    DIRECTION INPUT ;
    USE SIGNAL ;
    SHAPE ABUTMENT ;
    PORT
      LAYER M3_m ;
      RECT 0 338.135 0.07 338.205 ;
    END
  END rw0_wd_in[97]
  PIN rw0_wd_in[98]
    DIRECTION INPUT ;
    USE SIGNAL ;
    SHAPE ABUTMENT ;
    PORT
      LAYER M3_m ;
      RECT 0 340.235 0.07 340.305 ;
    END
  END rw0_wd_in[98]
  PIN rw0_wd_in[99]
    DIRECTION INPUT ;
    USE SIGNAL ;
    SHAPE ABUTMENT ;
    PORT
      LAYER M3_m ;
      RECT 0 342.335 0.07 342.405 ;
    END
  END rw0_wd_in[99]
  PIN rw0_wd_in[100]
    DIRECTION INPUT ;
    USE SIGNAL ;
    SHAPE ABUTMENT ;
    PORT
      LAYER M3_m ;
      RECT 0 344.435 0.07 344.505 ;
    END
  END rw0_wd_in[100]
  PIN rw0_wd_in[101]
    DIRECTION INPUT ;
    USE SIGNAL ;
    SHAPE ABUTMENT ;
    PORT
      LAYER M3_m ;
      RECT 0 346.535 0.07 346.605 ;
    END
  END rw0_wd_in[101]
  PIN rw0_wd_in[102]
    DIRECTION INPUT ;
    USE SIGNAL ;
    SHAPE ABUTMENT ;
    PORT
      LAYER M3_m ;
      RECT 0 348.635 0.07 348.705 ;
    END
  END rw0_wd_in[102]
  PIN rw0_wd_in[103]
    DIRECTION INPUT ;
    USE SIGNAL ;
    SHAPE ABUTMENT ;
    PORT
      LAYER M3_m ;
      RECT 0 350.735 0.07 350.805 ;
    END
  END rw0_wd_in[103]
  PIN rw0_wd_in[104]
    DIRECTION INPUT ;
    USE SIGNAL ;
    SHAPE ABUTMENT ;
    PORT
      LAYER M3_m ;
      RECT 0 352.835 0.07 352.905 ;
    END
  END rw0_wd_in[104]
  PIN rw0_wd_in[105]
    DIRECTION INPUT ;
    USE SIGNAL ;
    SHAPE ABUTMENT ;
    PORT
      LAYER M3_m ;
      RECT 0 354.935 0.07 355.005 ;
    END
  END rw0_wd_in[105]
  PIN rw0_wd_in[106]
    DIRECTION INPUT ;
    USE SIGNAL ;
    SHAPE ABUTMENT ;
    PORT
      LAYER M3_m ;
      RECT 0 357.035 0.07 357.105 ;
    END
  END rw0_wd_in[106]
  PIN rw0_wd_in[107]
    DIRECTION INPUT ;
    USE SIGNAL ;
    SHAPE ABUTMENT ;
    PORT
      LAYER M3_m ;
      RECT 0 359.135 0.07 359.205 ;
    END
  END rw0_wd_in[107]
  PIN rw0_wd_in[108]
    DIRECTION INPUT ;
    USE SIGNAL ;
    SHAPE ABUTMENT ;
    PORT
      LAYER M3_m ;
      RECT 0 361.235 0.07 361.305 ;
    END
  END rw0_wd_in[108]
  PIN rw0_wd_in[109]
    DIRECTION INPUT ;
    USE SIGNAL ;
    SHAPE ABUTMENT ;
    PORT
      LAYER M3_m ;
      RECT 0 363.335 0.07 363.405 ;
    END
  END rw0_wd_in[109]
  PIN rw0_wd_in[110]
    DIRECTION INPUT ;
    USE SIGNAL ;
    SHAPE ABUTMENT ;
    PORT
      LAYER M3_m ;
      RECT 0 365.435 0.07 365.505 ;
    END
  END rw0_wd_in[110]
  PIN rw0_wd_in[111]
    DIRECTION INPUT ;
    USE SIGNAL ;
    SHAPE ABUTMENT ;
    PORT
      LAYER M3_m ;
      RECT 0 367.535 0.07 367.605 ;
    END
  END rw0_wd_in[111]
  PIN rw0_wd_in[112]
    DIRECTION INPUT ;
    USE SIGNAL ;
    SHAPE ABUTMENT ;
    PORT
      LAYER M3_m ;
      RECT 0 369.635 0.07 369.705 ;
    END
  END rw0_wd_in[112]
  PIN rw0_wd_in[113]
    DIRECTION INPUT ;
    USE SIGNAL ;
    SHAPE ABUTMENT ;
    PORT
      LAYER M3_m ;
      RECT 0 371.735 0.07 371.805 ;
    END
  END rw0_wd_in[113]
  PIN rw0_wd_in[114]
    DIRECTION INPUT ;
    USE SIGNAL ;
    SHAPE ABUTMENT ;
    PORT
      LAYER M3_m ;
      RECT 0 373.835 0.07 373.905 ;
    END
  END rw0_wd_in[114]
  PIN rw0_wd_in[115]
    DIRECTION INPUT ;
    USE SIGNAL ;
    SHAPE ABUTMENT ;
    PORT
      LAYER M3_m ;
      RECT 0 375.935 0.07 376.005 ;
    END
  END rw0_wd_in[115]
  PIN rw0_wd_in[116]
    DIRECTION INPUT ;
    USE SIGNAL ;
    SHAPE ABUTMENT ;
    PORT
      LAYER M3_m ;
      RECT 0 378.035 0.07 378.105 ;
    END
  END rw0_wd_in[116]
  PIN rw0_wd_in[117]
    DIRECTION INPUT ;
    USE SIGNAL ;
    SHAPE ABUTMENT ;
    PORT
      LAYER M3_m ;
      RECT 0 380.135 0.07 380.205 ;
    END
  END rw0_wd_in[117]
  PIN rw0_wd_in[118]
    DIRECTION INPUT ;
    USE SIGNAL ;
    SHAPE ABUTMENT ;
    PORT
      LAYER M3_m ;
      RECT 0 382.235 0.07 382.305 ;
    END
  END rw0_wd_in[118]
  PIN rw0_wd_in[119]
    DIRECTION INPUT ;
    USE SIGNAL ;
    SHAPE ABUTMENT ;
    PORT
      LAYER M3_m ;
      RECT 0 384.335 0.07 384.405 ;
    END
  END rw0_wd_in[119]
  PIN rw0_wd_in[120]
    DIRECTION INPUT ;
    USE SIGNAL ;
    SHAPE ABUTMENT ;
    PORT
      LAYER M3_m ;
      RECT 0 386.435 0.07 386.505 ;
    END
  END rw0_wd_in[120]
  PIN rw0_wd_in[121]
    DIRECTION INPUT ;
    USE SIGNAL ;
    SHAPE ABUTMENT ;
    PORT
      LAYER M3_m ;
      RECT 0 388.535 0.07 388.605 ;
    END
  END rw0_wd_in[121]
  PIN rw0_wd_in[122]
    DIRECTION INPUT ;
    USE SIGNAL ;
    SHAPE ABUTMENT ;
    PORT
      LAYER M3_m ;
      RECT 0 390.635 0.07 390.705 ;
    END
  END rw0_wd_in[122]
  PIN rw0_wd_in[123]
    DIRECTION INPUT ;
    USE SIGNAL ;
    SHAPE ABUTMENT ;
    PORT
      LAYER M3_m ;
      RECT 0 392.735 0.07 392.805 ;
    END
  END rw0_wd_in[123]
  PIN rw0_wd_in[124]
    DIRECTION INPUT ;
    USE SIGNAL ;
    SHAPE ABUTMENT ;
    PORT
      LAYER M3_m ;
      RECT 0 394.835 0.07 394.905 ;
    END
  END rw0_wd_in[124]
  PIN rw0_wd_in[125]
    DIRECTION INPUT ;
    USE SIGNAL ;
    SHAPE ABUTMENT ;
    PORT
      LAYER M3_m ;
      RECT 0 396.935 0.07 397.005 ;
    END
  END rw0_wd_in[125]
  PIN rw0_wd_in[126]
    DIRECTION INPUT ;
    USE SIGNAL ;
    SHAPE ABUTMENT ;
    PORT
      LAYER M3_m ;
      RECT 0 399.035 0.07 399.105 ;
    END
  END rw0_wd_in[126]
  PIN rw0_wd_in[127]
    DIRECTION INPUT ;
    USE SIGNAL ;
    SHAPE ABUTMENT ;
    PORT
      LAYER M3_m ;
      RECT 0 401.135 0.07 401.205 ;
    END
  END rw0_wd_in[127]
  PIN rw0_wd_in[128]
    DIRECTION INPUT ;
    USE SIGNAL ;
    SHAPE ABUTMENT ;
    PORT
      LAYER M3_m ;
      RECT 0 403.235 0.07 403.305 ;
    END
  END rw0_wd_in[128]
  PIN rw0_wd_in[129]
    DIRECTION INPUT ;
    USE SIGNAL ;
    SHAPE ABUTMENT ;
    PORT
      LAYER M3_m ;
      RECT 0 405.335 0.07 405.405 ;
    END
  END rw0_wd_in[129]
  PIN rw0_wd_in[130]
    DIRECTION INPUT ;
    USE SIGNAL ;
    SHAPE ABUTMENT ;
    PORT
      LAYER M3_m ;
      RECT 0 407.435 0.07 407.505 ;
    END
  END rw0_wd_in[130]
  PIN rw0_wd_in[131]
    DIRECTION INPUT ;
    USE SIGNAL ;
    SHAPE ABUTMENT ;
    PORT
      LAYER M3_m ;
      RECT 0 409.535 0.07 409.605 ;
    END
  END rw0_wd_in[131]
  PIN rw0_wd_in[132]
    DIRECTION INPUT ;
    USE SIGNAL ;
    SHAPE ABUTMENT ;
    PORT
      LAYER M3_m ;
      RECT 0 411.635 0.07 411.705 ;
    END
  END rw0_wd_in[132]
  PIN rw0_wd_in[133]
    DIRECTION INPUT ;
    USE SIGNAL ;
    SHAPE ABUTMENT ;
    PORT
      LAYER M3_m ;
      RECT 0 413.735 0.07 413.805 ;
    END
  END rw0_wd_in[133]
  PIN rw0_wd_in[134]
    DIRECTION INPUT ;
    USE SIGNAL ;
    SHAPE ABUTMENT ;
    PORT
      LAYER M3_m ;
      RECT 0 415.835 0.07 415.905 ;
    END
  END rw0_wd_in[134]
  PIN rw0_wd_in[135]
    DIRECTION INPUT ;
    USE SIGNAL ;
    SHAPE ABUTMENT ;
    PORT
      LAYER M3_m ;
      RECT 0 417.935 0.07 418.005 ;
    END
  END rw0_wd_in[135]
  PIN rw0_wd_in[136]
    DIRECTION INPUT ;
    USE SIGNAL ;
    SHAPE ABUTMENT ;
    PORT
      LAYER M3_m ;
      RECT 0 420.035 0.07 420.105 ;
    END
  END rw0_wd_in[136]
  PIN rw0_wd_in[137]
    DIRECTION INPUT ;
    USE SIGNAL ;
    SHAPE ABUTMENT ;
    PORT
      LAYER M3_m ;
      RECT 0 422.135 0.07 422.205 ;
    END
  END rw0_wd_in[137]
  PIN rw0_wd_in[138]
    DIRECTION INPUT ;
    USE SIGNAL ;
    SHAPE ABUTMENT ;
    PORT
      LAYER M3_m ;
      RECT 0 424.235 0.07 424.305 ;
    END
  END rw0_wd_in[138]
  PIN rw0_wd_in[139]
    DIRECTION INPUT ;
    USE SIGNAL ;
    SHAPE ABUTMENT ;
    PORT
      LAYER M3_m ;
      RECT 0 426.335 0.07 426.405 ;
    END
  END rw0_wd_in[139]
  PIN rw0_wd_in[140]
    DIRECTION INPUT ;
    USE SIGNAL ;
    SHAPE ABUTMENT ;
    PORT
      LAYER M3_m ;
      RECT 0 428.435 0.07 428.505 ;
    END
  END rw0_wd_in[140]
  PIN rw0_wd_in[141]
    DIRECTION INPUT ;
    USE SIGNAL ;
    SHAPE ABUTMENT ;
    PORT
      LAYER M3_m ;
      RECT 0 430.535 0.07 430.605 ;
    END
  END rw0_wd_in[141]
  PIN rw0_wd_in[142]
    DIRECTION INPUT ;
    USE SIGNAL ;
    SHAPE ABUTMENT ;
    PORT
      LAYER M3_m ;
      RECT 0 432.635 0.07 432.705 ;
    END
  END rw0_wd_in[142]
  PIN rw0_wd_in[143]
    DIRECTION INPUT ;
    USE SIGNAL ;
    SHAPE ABUTMENT ;
    PORT
      LAYER M3_m ;
      RECT 0 434.735 0.07 434.805 ;
    END
  END rw0_wd_in[143]
  PIN rw0_wd_in[144]
    DIRECTION INPUT ;
    USE SIGNAL ;
    SHAPE ABUTMENT ;
    PORT
      LAYER M3_m ;
      RECT 0 436.835 0.07 436.905 ;
    END
  END rw0_wd_in[144]
  PIN rw0_wd_in[145]
    DIRECTION INPUT ;
    USE SIGNAL ;
    SHAPE ABUTMENT ;
    PORT
      LAYER M3_m ;
      RECT 0 438.935 0.07 439.005 ;
    END
  END rw0_wd_in[145]
  PIN rw0_wd_in[146]
    DIRECTION INPUT ;
    USE SIGNAL ;
    SHAPE ABUTMENT ;
    PORT
      LAYER M3_m ;
      RECT 0 441.035 0.07 441.105 ;
    END
  END rw0_wd_in[146]
  PIN rw0_wd_in[147]
    DIRECTION INPUT ;
    USE SIGNAL ;
    SHAPE ABUTMENT ;
    PORT
      LAYER M3_m ;
      RECT 0 443.135 0.07 443.205 ;
    END
  END rw0_wd_in[147]
  PIN rw0_wd_in[148]
    DIRECTION INPUT ;
    USE SIGNAL ;
    SHAPE ABUTMENT ;
    PORT
      LAYER M3_m ;
      RECT 0 445.235 0.07 445.305 ;
    END
  END rw0_wd_in[148]
  PIN rw0_wd_in[149]
    DIRECTION INPUT ;
    USE SIGNAL ;
    SHAPE ABUTMENT ;
    PORT
      LAYER M3_m ;
      RECT 0 447.335 0.07 447.405 ;
    END
  END rw0_wd_in[149]
  PIN rw0_wd_in[150]
    DIRECTION INPUT ;
    USE SIGNAL ;
    SHAPE ABUTMENT ;
    PORT
      LAYER M3_m ;
      RECT 0 449.435 0.07 449.505 ;
    END
  END rw0_wd_in[150]
  PIN rw0_wd_in[151]
    DIRECTION INPUT ;
    USE SIGNAL ;
    SHAPE ABUTMENT ;
    PORT
      LAYER M3_m ;
      RECT 0 451.535 0.07 451.605 ;
    END
  END rw0_wd_in[151]
  PIN rw0_wd_in[152]
    DIRECTION INPUT ;
    USE SIGNAL ;
    SHAPE ABUTMENT ;
    PORT
      LAYER M3_m ;
      RECT 0 453.635 0.07 453.705 ;
    END
  END rw0_wd_in[152]
  PIN rw0_wd_in[153]
    DIRECTION INPUT ;
    USE SIGNAL ;
    SHAPE ABUTMENT ;
    PORT
      LAYER M3_m ;
      RECT 0 455.735 0.07 455.805 ;
    END
  END rw0_wd_in[153]
  PIN rw0_wd_in[154]
    DIRECTION INPUT ;
    USE SIGNAL ;
    SHAPE ABUTMENT ;
    PORT
      LAYER M3_m ;
      RECT 0 457.835 0.07 457.905 ;
    END
  END rw0_wd_in[154]
  PIN rw0_wd_in[155]
    DIRECTION INPUT ;
    USE SIGNAL ;
    SHAPE ABUTMENT ;
    PORT
      LAYER M3_m ;
      RECT 0 459.935 0.07 460.005 ;
    END
  END rw0_wd_in[155]
  PIN rw0_wd_in[156]
    DIRECTION INPUT ;
    USE SIGNAL ;
    SHAPE ABUTMENT ;
    PORT
      LAYER M3_m ;
      RECT 0 462.035 0.07 462.105 ;
    END
  END rw0_wd_in[156]
  PIN rw0_wd_in[157]
    DIRECTION INPUT ;
    USE SIGNAL ;
    SHAPE ABUTMENT ;
    PORT
      LAYER M3_m ;
      RECT 0 464.135 0.07 464.205 ;
    END
  END rw0_wd_in[157]
  PIN rw0_wd_in[158]
    DIRECTION INPUT ;
    USE SIGNAL ;
    SHAPE ABUTMENT ;
    PORT
      LAYER M3_m ;
      RECT 0 466.235 0.07 466.305 ;
    END
  END rw0_wd_in[158]
  PIN rw0_wd_in[159]
    DIRECTION INPUT ;
    USE SIGNAL ;
    SHAPE ABUTMENT ;
    PORT
      LAYER M3_m ;
      RECT 0 468.335 0.07 468.405 ;
    END
  END rw0_wd_in[159]
  PIN rw0_wd_in[160]
    DIRECTION INPUT ;
    USE SIGNAL ;
    SHAPE ABUTMENT ;
    PORT
      LAYER M3_m ;
      RECT 0 470.435 0.07 470.505 ;
    END
  END rw0_wd_in[160]
  PIN rw0_wd_in[161]
    DIRECTION INPUT ;
    USE SIGNAL ;
    SHAPE ABUTMENT ;
    PORT
      LAYER M3_m ;
      RECT 0 472.535 0.07 472.605 ;
    END
  END rw0_wd_in[161]
  PIN rw0_wd_in[162]
    DIRECTION INPUT ;
    USE SIGNAL ;
    SHAPE ABUTMENT ;
    PORT
      LAYER M3_m ;
      RECT 0 474.635 0.07 474.705 ;
    END
  END rw0_wd_in[162]
  PIN rw0_wd_in[163]
    DIRECTION INPUT ;
    USE SIGNAL ;
    SHAPE ABUTMENT ;
    PORT
      LAYER M3_m ;
      RECT 0 476.735 0.07 476.805 ;
    END
  END rw0_wd_in[163]
  PIN rw0_wd_in[164]
    DIRECTION INPUT ;
    USE SIGNAL ;
    SHAPE ABUTMENT ;
    PORT
      LAYER M3_m ;
      RECT 0 478.835 0.07 478.905 ;
    END
  END rw0_wd_in[164]
  PIN rw0_wd_in[165]
    DIRECTION INPUT ;
    USE SIGNAL ;
    SHAPE ABUTMENT ;
    PORT
      LAYER M3_m ;
      RECT 0 480.935 0.07 481.005 ;
    END
  END rw0_wd_in[165]
  PIN rw0_wd_in[166]
    DIRECTION INPUT ;
    USE SIGNAL ;
    SHAPE ABUTMENT ;
    PORT
      LAYER M3_m ;
      RECT 0 483.035 0.07 483.105 ;
    END
  END rw0_wd_in[166]
  PIN rw0_wd_in[167]
    DIRECTION INPUT ;
    USE SIGNAL ;
    SHAPE ABUTMENT ;
    PORT
      LAYER M3_m ;
      RECT 0 485.135 0.07 485.205 ;
    END
  END rw0_wd_in[167]
  PIN rw0_wd_in[168]
    DIRECTION INPUT ;
    USE SIGNAL ;
    SHAPE ABUTMENT ;
    PORT
      LAYER M3_m ;
      RECT 0 487.235 0.07 487.305 ;
    END
  END rw0_wd_in[168]
  PIN rw0_wd_in[169]
    DIRECTION INPUT ;
    USE SIGNAL ;
    SHAPE ABUTMENT ;
    PORT
      LAYER M3_m ;
      RECT 0 489.335 0.07 489.405 ;
    END
  END rw0_wd_in[169]
  PIN rw0_wd_in[170]
    DIRECTION INPUT ;
    USE SIGNAL ;
    SHAPE ABUTMENT ;
    PORT
      LAYER M3_m ;
      RECT 0 491.435 0.07 491.505 ;
    END
  END rw0_wd_in[170]
  PIN rw0_wd_in[171]
    DIRECTION INPUT ;
    USE SIGNAL ;
    SHAPE ABUTMENT ;
    PORT
      LAYER M3_m ;
      RECT 0 493.535 0.07 493.605 ;
    END
  END rw0_wd_in[171]
  PIN rw0_wd_in[172]
    DIRECTION INPUT ;
    USE SIGNAL ;
    SHAPE ABUTMENT ;
    PORT
      LAYER M3_m ;
      RECT 0 495.635 0.07 495.705 ;
    END
  END rw0_wd_in[172]
  PIN rw0_wd_in[173]
    DIRECTION INPUT ;
    USE SIGNAL ;
    SHAPE ABUTMENT ;
    PORT
      LAYER M3_m ;
      RECT 0 497.735 0.07 497.805 ;
    END
  END rw0_wd_in[173]
  PIN rw0_wd_in[174]
    DIRECTION INPUT ;
    USE SIGNAL ;
    SHAPE ABUTMENT ;
    PORT
      LAYER M3_m ;
      RECT 0 499.835 0.07 499.905 ;
    END
  END rw0_wd_in[174]
  PIN rw0_wd_in[175]
    DIRECTION INPUT ;
    USE SIGNAL ;
    SHAPE ABUTMENT ;
    PORT
      LAYER M3_m ;
      RECT 0 501.935 0.07 502.005 ;
    END
  END rw0_wd_in[175]
  PIN rw0_wd_in[176]
    DIRECTION INPUT ;
    USE SIGNAL ;
    SHAPE ABUTMENT ;
    PORT
      LAYER M3_m ;
      RECT 0 504.035 0.07 504.105 ;
    END
  END rw0_wd_in[176]
  PIN rw0_wd_in[177]
    DIRECTION INPUT ;
    USE SIGNAL ;
    SHAPE ABUTMENT ;
    PORT
      LAYER M3_m ;
      RECT 0 506.135 0.07 506.205 ;
    END
  END rw0_wd_in[177]
  PIN rw0_wd_in[178]
    DIRECTION INPUT ;
    USE SIGNAL ;
    SHAPE ABUTMENT ;
    PORT
      LAYER M3_m ;
      RECT 0 508.235 0.07 508.305 ;
    END
  END rw0_wd_in[178]
  PIN rw0_wd_in[179]
    DIRECTION INPUT ;
    USE SIGNAL ;
    SHAPE ABUTMENT ;
    PORT
      LAYER M3_m ;
      RECT 0 510.335 0.07 510.405 ;
    END
  END rw0_wd_in[179]
  PIN rw0_wd_in[180]
    DIRECTION INPUT ;
    USE SIGNAL ;
    SHAPE ABUTMENT ;
    PORT
      LAYER M3_m ;
      RECT 0 512.435 0.07 512.505 ;
    END
  END rw0_wd_in[180]
  PIN rw0_wd_in[181]
    DIRECTION INPUT ;
    USE SIGNAL ;
    SHAPE ABUTMENT ;
    PORT
      LAYER M3_m ;
      RECT 0 514.535 0.07 514.605 ;
    END
  END rw0_wd_in[181]
  PIN rw0_wd_in[182]
    DIRECTION INPUT ;
    USE SIGNAL ;
    SHAPE ABUTMENT ;
    PORT
      LAYER M3_m ;
      RECT 0 516.635 0.07 516.705 ;
    END
  END rw0_wd_in[182]
  PIN rw0_wd_in[183]
    DIRECTION INPUT ;
    USE SIGNAL ;
    SHAPE ABUTMENT ;
    PORT
      LAYER M3_m ;
      RECT 0 518.735 0.07 518.805 ;
    END
  END rw0_wd_in[183]
  PIN rw0_wd_in[184]
    DIRECTION INPUT ;
    USE SIGNAL ;
    SHAPE ABUTMENT ;
    PORT
      LAYER M3_m ;
      RECT 0 520.835 0.07 520.905 ;
    END
  END rw0_wd_in[184]
  PIN rw0_wd_in[185]
    DIRECTION INPUT ;
    USE SIGNAL ;
    SHAPE ABUTMENT ;
    PORT
      LAYER M3_m ;
      RECT 0 522.935 0.07 523.005 ;
    END
  END rw0_wd_in[185]
  PIN rw0_wd_in[186]
    DIRECTION INPUT ;
    USE SIGNAL ;
    SHAPE ABUTMENT ;
    PORT
      LAYER M3_m ;
      RECT 0 525.035 0.07 525.105 ;
    END
  END rw0_wd_in[186]
  PIN rw0_wd_in[187]
    DIRECTION INPUT ;
    USE SIGNAL ;
    SHAPE ABUTMENT ;
    PORT
      LAYER M3_m ;
      RECT 0 527.135 0.07 527.205 ;
    END
  END rw0_wd_in[187]
  PIN rw0_wd_in[188]
    DIRECTION INPUT ;
    USE SIGNAL ;
    SHAPE ABUTMENT ;
    PORT
      LAYER M3_m ;
      RECT 0 529.235 0.07 529.305 ;
    END
  END rw0_wd_in[188]
  PIN rw0_wd_in[189]
    DIRECTION INPUT ;
    USE SIGNAL ;
    SHAPE ABUTMENT ;
    PORT
      LAYER M3_m ;
      RECT 0 531.335 0.07 531.405 ;
    END
  END rw0_wd_in[189]
  PIN rw0_wd_in[190]
    DIRECTION INPUT ;
    USE SIGNAL ;
    SHAPE ABUTMENT ;
    PORT
      LAYER M3_m ;
      RECT 0 533.435 0.07 533.505 ;
    END
  END rw0_wd_in[190]
  PIN rw0_wd_in[191]
    DIRECTION INPUT ;
    USE SIGNAL ;
    SHAPE ABUTMENT ;
    PORT
      LAYER M3_m ;
      RECT 0 535.535 0.07 535.605 ;
    END
  END rw0_wd_in[191]
  PIN rw0_wd_in[192]
    DIRECTION INPUT ;
    USE SIGNAL ;
    SHAPE ABUTMENT ;
    PORT
      LAYER M3_m ;
      RECT 0 537.635 0.07 537.705 ;
    END
  END rw0_wd_in[192]
  PIN rw0_wd_in[193]
    DIRECTION INPUT ;
    USE SIGNAL ;
    SHAPE ABUTMENT ;
    PORT
      LAYER M3_m ;
      RECT 0 539.735 0.07 539.805 ;
    END
  END rw0_wd_in[193]
  PIN rw0_wd_in[194]
    DIRECTION INPUT ;
    USE SIGNAL ;
    SHAPE ABUTMENT ;
    PORT
      LAYER M3_m ;
      RECT 0 541.835 0.07 541.905 ;
    END
  END rw0_wd_in[194]
  PIN rw0_wd_in[195]
    DIRECTION INPUT ;
    USE SIGNAL ;
    SHAPE ABUTMENT ;
    PORT
      LAYER M3_m ;
      RECT 0 543.935 0.07 544.005 ;
    END
  END rw0_wd_in[195]
  PIN rw0_wd_in[196]
    DIRECTION INPUT ;
    USE SIGNAL ;
    SHAPE ABUTMENT ;
    PORT
      LAYER M3_m ;
      RECT 0 546.035 0.07 546.105 ;
    END
  END rw0_wd_in[196]
  PIN rw0_wd_in[197]
    DIRECTION INPUT ;
    USE SIGNAL ;
    SHAPE ABUTMENT ;
    PORT
      LAYER M3_m ;
      RECT 0 548.135 0.07 548.205 ;
    END
  END rw0_wd_in[197]
  PIN rw0_wd_in[198]
    DIRECTION INPUT ;
    USE SIGNAL ;
    SHAPE ABUTMENT ;
    PORT
      LAYER M3_m ;
      RECT 0 550.235 0.07 550.305 ;
    END
  END rw0_wd_in[198]
  PIN rw0_wd_in[199]
    DIRECTION INPUT ;
    USE SIGNAL ;
    SHAPE ABUTMENT ;
    PORT
      LAYER M3_m ;
      RECT 0 552.335 0.07 552.405 ;
    END
  END rw0_wd_in[199]
  PIN rw0_wd_in[200]
    DIRECTION INPUT ;
    USE SIGNAL ;
    SHAPE ABUTMENT ;
    PORT
      LAYER M3_m ;
      RECT 0 554.435 0.07 554.505 ;
    END
  END rw0_wd_in[200]
  PIN rw0_wd_in[201]
    DIRECTION INPUT ;
    USE SIGNAL ;
    SHAPE ABUTMENT ;
    PORT
      LAYER M3_m ;
      RECT 0 556.535 0.07 556.605 ;
    END
  END rw0_wd_in[201]
  PIN rw0_wd_in[202]
    DIRECTION INPUT ;
    USE SIGNAL ;
    SHAPE ABUTMENT ;
    PORT
      LAYER M3_m ;
      RECT 0 558.635 0.07 558.705 ;
    END
  END rw0_wd_in[202]
  PIN rw0_wd_in[203]
    DIRECTION INPUT ;
    USE SIGNAL ;
    SHAPE ABUTMENT ;
    PORT
      LAYER M3_m ;
      RECT 0 560.735 0.07 560.805 ;
    END
  END rw0_wd_in[203]
  PIN rw0_wd_in[204]
    DIRECTION INPUT ;
    USE SIGNAL ;
    SHAPE ABUTMENT ;
    PORT
      LAYER M3_m ;
      RECT 0 562.835 0.07 562.905 ;
    END
  END rw0_wd_in[204]
  PIN rw0_wd_in[205]
    DIRECTION INPUT ;
    USE SIGNAL ;
    SHAPE ABUTMENT ;
    PORT
      LAYER M3_m ;
      RECT 0 564.935 0.07 565.005 ;
    END
  END rw0_wd_in[205]
  PIN rw0_wd_in[206]
    DIRECTION INPUT ;
    USE SIGNAL ;
    SHAPE ABUTMENT ;
    PORT
      LAYER M3_m ;
      RECT 0 567.035 0.07 567.105 ;
    END
  END rw0_wd_in[206]
  PIN rw0_wd_in[207]
    DIRECTION INPUT ;
    USE SIGNAL ;
    SHAPE ABUTMENT ;
    PORT
      LAYER M3_m ;
      RECT 0 569.135 0.07 569.205 ;
    END
  END rw0_wd_in[207]
  PIN rw0_wd_in[208]
    DIRECTION INPUT ;
    USE SIGNAL ;
    SHAPE ABUTMENT ;
    PORT
      LAYER M3_m ;
      RECT 0 571.235 0.07 571.305 ;
    END
  END rw0_wd_in[208]
  PIN rw0_wd_in[209]
    DIRECTION INPUT ;
    USE SIGNAL ;
    SHAPE ABUTMENT ;
    PORT
      LAYER M3_m ;
      RECT 0 573.335 0.07 573.405 ;
    END
  END rw0_wd_in[209]
  PIN rw0_wd_in[210]
    DIRECTION INPUT ;
    USE SIGNAL ;
    SHAPE ABUTMENT ;
    PORT
      LAYER M3_m ;
      RECT 0 575.435 0.07 575.505 ;
    END
  END rw0_wd_in[210]
  PIN rw0_wd_in[211]
    DIRECTION INPUT ;
    USE SIGNAL ;
    SHAPE ABUTMENT ;
    PORT
      LAYER M3_m ;
      RECT 0 577.535 0.07 577.605 ;
    END
  END rw0_wd_in[211]
  PIN rw0_wd_in[212]
    DIRECTION INPUT ;
    USE SIGNAL ;
    SHAPE ABUTMENT ;
    PORT
      LAYER M3_m ;
      RECT 0 579.635 0.07 579.705 ;
    END
  END rw0_wd_in[212]
  PIN rw0_wd_in[213]
    DIRECTION INPUT ;
    USE SIGNAL ;
    SHAPE ABUTMENT ;
    PORT
      LAYER M3_m ;
      RECT 0 581.735 0.07 581.805 ;
    END
  END rw0_wd_in[213]
  PIN rw0_wd_in[214]
    DIRECTION INPUT ;
    USE SIGNAL ;
    SHAPE ABUTMENT ;
    PORT
      LAYER M3_m ;
      RECT 0 583.835 0.07 583.905 ;
    END
  END rw0_wd_in[214]
  PIN rw0_wd_in[215]
    DIRECTION INPUT ;
    USE SIGNAL ;
    SHAPE ABUTMENT ;
    PORT
      LAYER M3_m ;
      RECT 0 585.935 0.07 586.005 ;
    END
  END rw0_wd_in[215]
  PIN rw0_wd_in[216]
    DIRECTION INPUT ;
    USE SIGNAL ;
    SHAPE ABUTMENT ;
    PORT
      LAYER M3_m ;
      RECT 0 588.035 0.07 588.105 ;
    END
  END rw0_wd_in[216]
  PIN rw0_wd_in[217]
    DIRECTION INPUT ;
    USE SIGNAL ;
    SHAPE ABUTMENT ;
    PORT
      LAYER M3_m ;
      RECT 0 590.135 0.07 590.205 ;
    END
  END rw0_wd_in[217]
  PIN rw0_wd_in[218]
    DIRECTION INPUT ;
    USE SIGNAL ;
    SHAPE ABUTMENT ;
    PORT
      LAYER M3_m ;
      RECT 0 592.235 0.07 592.305 ;
    END
  END rw0_wd_in[218]
  PIN rw0_wd_in[219]
    DIRECTION INPUT ;
    USE SIGNAL ;
    SHAPE ABUTMENT ;
    PORT
      LAYER M3_m ;
      RECT 0 594.335 0.07 594.405 ;
    END
  END rw0_wd_in[219]
  PIN rw0_wd_in[220]
    DIRECTION INPUT ;
    USE SIGNAL ;
    SHAPE ABUTMENT ;
    PORT
      LAYER M3_m ;
      RECT 0 596.435 0.07 596.505 ;
    END
  END rw0_wd_in[220]
  PIN rw0_wd_in[221]
    DIRECTION INPUT ;
    USE SIGNAL ;
    SHAPE ABUTMENT ;
    PORT
      LAYER M3_m ;
      RECT 0 598.535 0.07 598.605 ;
    END
  END rw0_wd_in[221]
  PIN rw0_wd_in[222]
    DIRECTION INPUT ;
    USE SIGNAL ;
    SHAPE ABUTMENT ;
    PORT
      LAYER M3_m ;
      RECT 0 600.635 0.07 600.705 ;
    END
  END rw0_wd_in[222]
  PIN rw0_wd_in[223]
    DIRECTION INPUT ;
    USE SIGNAL ;
    SHAPE ABUTMENT ;
    PORT
      LAYER M3_m ;
      RECT 0 602.735 0.07 602.805 ;
    END
  END rw0_wd_in[223]
  PIN rw0_wd_in[224]
    DIRECTION INPUT ;
    USE SIGNAL ;
    SHAPE ABUTMENT ;
    PORT
      LAYER M3_m ;
      RECT 0 604.835 0.07 604.905 ;
    END
  END rw0_wd_in[224]
  PIN rw0_wd_in[225]
    DIRECTION INPUT ;
    USE SIGNAL ;
    SHAPE ABUTMENT ;
    PORT
      LAYER M3_m ;
      RECT 0 606.935 0.07 607.005 ;
    END
  END rw0_wd_in[225]
  PIN rw0_wd_in[226]
    DIRECTION INPUT ;
    USE SIGNAL ;
    SHAPE ABUTMENT ;
    PORT
      LAYER M3_m ;
      RECT 0 609.035 0.07 609.105 ;
    END
  END rw0_wd_in[226]
  PIN rw0_wd_in[227]
    DIRECTION INPUT ;
    USE SIGNAL ;
    SHAPE ABUTMENT ;
    PORT
      LAYER M3_m ;
      RECT 0 611.135 0.07 611.205 ;
    END
  END rw0_wd_in[227]
  PIN rw0_wd_in[228]
    DIRECTION INPUT ;
    USE SIGNAL ;
    SHAPE ABUTMENT ;
    PORT
      LAYER M3_m ;
      RECT 0 613.235 0.07 613.305 ;
    END
  END rw0_wd_in[228]
  PIN rw0_wd_in[229]
    DIRECTION INPUT ;
    USE SIGNAL ;
    SHAPE ABUTMENT ;
    PORT
      LAYER M3_m ;
      RECT 0 615.335 0.07 615.405 ;
    END
  END rw0_wd_in[229]
  PIN rw0_wd_in[230]
    DIRECTION INPUT ;
    USE SIGNAL ;
    SHAPE ABUTMENT ;
    PORT
      LAYER M3_m ;
      RECT 0 617.435 0.07 617.505 ;
    END
  END rw0_wd_in[230]
  PIN rw0_wd_in[231]
    DIRECTION INPUT ;
    USE SIGNAL ;
    SHAPE ABUTMENT ;
    PORT
      LAYER M3_m ;
      RECT 0 619.535 0.07 619.605 ;
    END
  END rw0_wd_in[231]
  PIN rw0_wd_in[232]
    DIRECTION INPUT ;
    USE SIGNAL ;
    SHAPE ABUTMENT ;
    PORT
      LAYER M3_m ;
      RECT 0 621.635 0.07 621.705 ;
    END
  END rw0_wd_in[232]
  PIN rw0_wd_in[233]
    DIRECTION INPUT ;
    USE SIGNAL ;
    SHAPE ABUTMENT ;
    PORT
      LAYER M3_m ;
      RECT 0 623.735 0.07 623.805 ;
    END
  END rw0_wd_in[233]
  PIN rw0_wd_in[234]
    DIRECTION INPUT ;
    USE SIGNAL ;
    SHAPE ABUTMENT ;
    PORT
      LAYER M3_m ;
      RECT 0 625.835 0.07 625.905 ;
    END
  END rw0_wd_in[234]
  PIN rw0_wd_in[235]
    DIRECTION INPUT ;
    USE SIGNAL ;
    SHAPE ABUTMENT ;
    PORT
      LAYER M3_m ;
      RECT 0 627.935 0.07 628.005 ;
    END
  END rw0_wd_in[235]
  PIN rw0_wd_in[236]
    DIRECTION INPUT ;
    USE SIGNAL ;
    SHAPE ABUTMENT ;
    PORT
      LAYER M3_m ;
      RECT 0 630.035 0.07 630.105 ;
    END
  END rw0_wd_in[236]
  PIN rw0_wd_in[237]
    DIRECTION INPUT ;
    USE SIGNAL ;
    SHAPE ABUTMENT ;
    PORT
      LAYER M3_m ;
      RECT 0 632.135 0.07 632.205 ;
    END
  END rw0_wd_in[237]
  PIN rw0_wd_in[238]
    DIRECTION INPUT ;
    USE SIGNAL ;
    SHAPE ABUTMENT ;
    PORT
      LAYER M3_m ;
      RECT 0 634.235 0.07 634.305 ;
    END
  END rw0_wd_in[238]
  PIN rw0_wd_in[239]
    DIRECTION INPUT ;
    USE SIGNAL ;
    SHAPE ABUTMENT ;
    PORT
      LAYER M3_m ;
      RECT 0 636.335 0.07 636.405 ;
    END
  END rw0_wd_in[239]
  PIN rw0_wd_in[240]
    DIRECTION INPUT ;
    USE SIGNAL ;
    SHAPE ABUTMENT ;
    PORT
      LAYER M3_m ;
      RECT 0 638.435 0.07 638.505 ;
    END
  END rw0_wd_in[240]
  PIN rw0_wd_in[241]
    DIRECTION INPUT ;
    USE SIGNAL ;
    SHAPE ABUTMENT ;
    PORT
      LAYER M3_m ;
      RECT 0 640.535 0.07 640.605 ;
    END
  END rw0_wd_in[241]
  PIN rw0_wd_in[242]
    DIRECTION INPUT ;
    USE SIGNAL ;
    SHAPE ABUTMENT ;
    PORT
      LAYER M3_m ;
      RECT 0 642.635 0.07 642.705 ;
    END
  END rw0_wd_in[242]
  PIN rw0_wd_in[243]
    DIRECTION INPUT ;
    USE SIGNAL ;
    SHAPE ABUTMENT ;
    PORT
      LAYER M3_m ;
      RECT 0 644.735 0.07 644.805 ;
    END
  END rw0_wd_in[243]
  PIN rw0_wd_in[244]
    DIRECTION INPUT ;
    USE SIGNAL ;
    SHAPE ABUTMENT ;
    PORT
      LAYER M3_m ;
      RECT 0 646.835 0.07 646.905 ;
    END
  END rw0_wd_in[244]
  PIN rw0_wd_in[245]
    DIRECTION INPUT ;
    USE SIGNAL ;
    SHAPE ABUTMENT ;
    PORT
      LAYER M3_m ;
      RECT 0 648.935 0.07 649.005 ;
    END
  END rw0_wd_in[245]
  PIN rw0_wd_in[246]
    DIRECTION INPUT ;
    USE SIGNAL ;
    SHAPE ABUTMENT ;
    PORT
      LAYER M3_m ;
      RECT 0 651.035 0.07 651.105 ;
    END
  END rw0_wd_in[246]
  PIN rw0_wd_in[247]
    DIRECTION INPUT ;
    USE SIGNAL ;
    SHAPE ABUTMENT ;
    PORT
      LAYER M3_m ;
      RECT 0 653.135 0.07 653.205 ;
    END
  END rw0_wd_in[247]
  PIN rw0_wd_in[248]
    DIRECTION INPUT ;
    USE SIGNAL ;
    SHAPE ABUTMENT ;
    PORT
      LAYER M3_m ;
      RECT 0 655.235 0.07 655.305 ;
    END
  END rw0_wd_in[248]
  PIN rw0_wd_in[249]
    DIRECTION INPUT ;
    USE SIGNAL ;
    SHAPE ABUTMENT ;
    PORT
      LAYER M3_m ;
      RECT 0 657.335 0.07 657.405 ;
    END
  END rw0_wd_in[249]
  PIN rw0_wd_in[250]
    DIRECTION INPUT ;
    USE SIGNAL ;
    SHAPE ABUTMENT ;
    PORT
      LAYER M3_m ;
      RECT 0 659.435 0.07 659.505 ;
    END
  END rw0_wd_in[250]
  PIN rw0_wd_in[251]
    DIRECTION INPUT ;
    USE SIGNAL ;
    SHAPE ABUTMENT ;
    PORT
      LAYER M3_m ;
      RECT 0 661.535 0.07 661.605 ;
    END
  END rw0_wd_in[251]
  PIN rw0_wd_in[252]
    DIRECTION INPUT ;
    USE SIGNAL ;
    SHAPE ABUTMENT ;
    PORT
      LAYER M3_m ;
      RECT 0 663.635 0.07 663.705 ;
    END
  END rw0_wd_in[252]
  PIN rw0_wd_in[253]
    DIRECTION INPUT ;
    USE SIGNAL ;
    SHAPE ABUTMENT ;
    PORT
      LAYER M3_m ;
      RECT 0 665.735 0.07 665.805 ;
    END
  END rw0_wd_in[253]
  PIN rw0_wd_in[254]
    DIRECTION INPUT ;
    USE SIGNAL ;
    SHAPE ABUTMENT ;
    PORT
      LAYER M3_m ;
      RECT 0 667.835 0.07 667.905 ;
    END
  END rw0_wd_in[254]
  PIN rw0_wd_in[255]
    DIRECTION INPUT ;
    USE SIGNAL ;
    SHAPE ABUTMENT ;
    PORT
      LAYER M3_m ;
      RECT 0 669.935 0.07 670.005 ;
    END
  END rw0_wd_in[255]
  PIN rw0_wd_in[256]
    DIRECTION INPUT ;
    USE SIGNAL ;
    SHAPE ABUTMENT ;
    PORT
      LAYER M3_m ;
      RECT 0 672.035 0.07 672.105 ;
    END
  END rw0_wd_in[256]
  PIN rw0_wd_in[257]
    DIRECTION INPUT ;
    USE SIGNAL ;
    SHAPE ABUTMENT ;
    PORT
      LAYER M3_m ;
      RECT 0 674.135 0.07 674.205 ;
    END
  END rw0_wd_in[257]
  PIN rw0_wd_in[258]
    DIRECTION INPUT ;
    USE SIGNAL ;
    SHAPE ABUTMENT ;
    PORT
      LAYER M3_m ;
      RECT 0 676.235 0.07 676.305 ;
    END
  END rw0_wd_in[258]
  PIN rw0_wd_in[259]
    DIRECTION INPUT ;
    USE SIGNAL ;
    SHAPE ABUTMENT ;
    PORT
      LAYER M3_m ;
      RECT 0 678.335 0.07 678.405 ;
    END
  END rw0_wd_in[259]
  PIN rw0_wd_in[260]
    DIRECTION INPUT ;
    USE SIGNAL ;
    SHAPE ABUTMENT ;
    PORT
      LAYER M3_m ;
      RECT 0 680.435 0.07 680.505 ;
    END
  END rw0_wd_in[260]
  PIN rw0_wd_in[261]
    DIRECTION INPUT ;
    USE SIGNAL ;
    SHAPE ABUTMENT ;
    PORT
      LAYER M3_m ;
      RECT 0 682.535 0.07 682.605 ;
    END
  END rw0_wd_in[261]
  PIN rw0_wd_in[262]
    DIRECTION INPUT ;
    USE SIGNAL ;
    SHAPE ABUTMENT ;
    PORT
      LAYER M3_m ;
      RECT 0 684.635 0.07 684.705 ;
    END
  END rw0_wd_in[262]
  PIN rw0_wd_in[263]
    DIRECTION INPUT ;
    USE SIGNAL ;
    SHAPE ABUTMENT ;
    PORT
      LAYER M3_m ;
      RECT 0 686.735 0.07 686.805 ;
    END
  END rw0_wd_in[263]
  PIN rw0_wd_in[264]
    DIRECTION INPUT ;
    USE SIGNAL ;
    SHAPE ABUTMENT ;
    PORT
      LAYER M3_m ;
      RECT 0 688.835 0.07 688.905 ;
    END
  END rw0_wd_in[264]
  PIN rw0_wd_in[265]
    DIRECTION INPUT ;
    USE SIGNAL ;
    SHAPE ABUTMENT ;
    PORT
      LAYER M3_m ;
      RECT 0 690.935 0.07 691.005 ;
    END
  END rw0_wd_in[265]
  PIN rw0_wd_in[266]
    DIRECTION INPUT ;
    USE SIGNAL ;
    SHAPE ABUTMENT ;
    PORT
      LAYER M3_m ;
      RECT 0 693.035 0.07 693.105 ;
    END
  END rw0_wd_in[266]
  PIN rw0_wd_in[267]
    DIRECTION INPUT ;
    USE SIGNAL ;
    SHAPE ABUTMENT ;
    PORT
      LAYER M3_m ;
      RECT 0 695.135 0.07 695.205 ;
    END
  END rw0_wd_in[267]
  PIN rw0_wd_in[268]
    DIRECTION INPUT ;
    USE SIGNAL ;
    SHAPE ABUTMENT ;
    PORT
      LAYER M3_m ;
      RECT 0 697.235 0.07 697.305 ;
    END
  END rw0_wd_in[268]
  PIN rw0_wd_in[269]
    DIRECTION INPUT ;
    USE SIGNAL ;
    SHAPE ABUTMENT ;
    PORT
      LAYER M3_m ;
      RECT 0 699.335 0.07 699.405 ;
    END
  END rw0_wd_in[269]
  PIN rw0_wd_in[270]
    DIRECTION INPUT ;
    USE SIGNAL ;
    SHAPE ABUTMENT ;
    PORT
      LAYER M3_m ;
      RECT 0 701.435 0.07 701.505 ;
    END
  END rw0_wd_in[270]
  PIN rw0_wd_in[271]
    DIRECTION INPUT ;
    USE SIGNAL ;
    SHAPE ABUTMENT ;
    PORT
      LAYER M3_m ;
      RECT 0 703.535 0.07 703.605 ;
    END
  END rw0_wd_in[271]
  PIN rw0_wd_in[272]
    DIRECTION INPUT ;
    USE SIGNAL ;
    SHAPE ABUTMENT ;
    PORT
      LAYER M3_m ;
      RECT 0 705.635 0.07 705.705 ;
    END
  END rw0_wd_in[272]
  PIN rw0_wd_in[273]
    DIRECTION INPUT ;
    USE SIGNAL ;
    SHAPE ABUTMENT ;
    PORT
      LAYER M3_m ;
      RECT 0 707.735 0.07 707.805 ;
    END
  END rw0_wd_in[273]
  PIN rw0_wd_in[274]
    DIRECTION INPUT ;
    USE SIGNAL ;
    SHAPE ABUTMENT ;
    PORT
      LAYER M3_m ;
      RECT 0 709.835 0.07 709.905 ;
    END
  END rw0_wd_in[274]
  PIN rw0_wd_in[275]
    DIRECTION INPUT ;
    USE SIGNAL ;
    SHAPE ABUTMENT ;
    PORT
      LAYER M3_m ;
      RECT 0 711.935 0.07 712.005 ;
    END
  END rw0_wd_in[275]
  PIN rw0_wd_in[276]
    DIRECTION INPUT ;
    USE SIGNAL ;
    SHAPE ABUTMENT ;
    PORT
      LAYER M3_m ;
      RECT 0 714.035 0.07 714.105 ;
    END
  END rw0_wd_in[276]
  PIN rw0_wd_in[277]
    DIRECTION INPUT ;
    USE SIGNAL ;
    SHAPE ABUTMENT ;
    PORT
      LAYER M3_m ;
      RECT 0 716.135 0.07 716.205 ;
    END
  END rw0_wd_in[277]
  PIN rw0_wd_in[278]
    DIRECTION INPUT ;
    USE SIGNAL ;
    SHAPE ABUTMENT ;
    PORT
      LAYER M3_m ;
      RECT 0 718.235 0.07 718.305 ;
    END
  END rw0_wd_in[278]
  PIN rw0_wd_in[279]
    DIRECTION INPUT ;
    USE SIGNAL ;
    SHAPE ABUTMENT ;
    PORT
      LAYER M3_m ;
      RECT 0 720.335 0.07 720.405 ;
    END
  END rw0_wd_in[279]
  PIN rw0_wd_in[280]
    DIRECTION INPUT ;
    USE SIGNAL ;
    SHAPE ABUTMENT ;
    PORT
      LAYER M3_m ;
      RECT 0 722.435 0.07 722.505 ;
    END
  END rw0_wd_in[280]
  PIN rw0_wd_in[281]
    DIRECTION INPUT ;
    USE SIGNAL ;
    SHAPE ABUTMENT ;
    PORT
      LAYER M3_m ;
      RECT 0 724.535 0.07 724.605 ;
    END
  END rw0_wd_in[281]
  PIN rw0_wd_in[282]
    DIRECTION INPUT ;
    USE SIGNAL ;
    SHAPE ABUTMENT ;
    PORT
      LAYER M3_m ;
      RECT 0 726.635 0.07 726.705 ;
    END
  END rw0_wd_in[282]
  PIN rw0_wd_in[283]
    DIRECTION INPUT ;
    USE SIGNAL ;
    SHAPE ABUTMENT ;
    PORT
      LAYER M3_m ;
      RECT 0 728.735 0.07 728.805 ;
    END
  END rw0_wd_in[283]
  PIN rw0_wd_in[284]
    DIRECTION INPUT ;
    USE SIGNAL ;
    SHAPE ABUTMENT ;
    PORT
      LAYER M3_m ;
      RECT 0 730.835 0.07 730.905 ;
    END
  END rw0_wd_in[284]
  PIN rw0_wd_in[285]
    DIRECTION INPUT ;
    USE SIGNAL ;
    SHAPE ABUTMENT ;
    PORT
      LAYER M3_m ;
      RECT 0 732.935 0.07 733.005 ;
    END
  END rw0_wd_in[285]
  PIN rw0_wd_in[286]
    DIRECTION INPUT ;
    USE SIGNAL ;
    SHAPE ABUTMENT ;
    PORT
      LAYER M3_m ;
      RECT 0 735.035 0.07 735.105 ;
    END
  END rw0_wd_in[286]
  PIN rw0_wd_in[287]
    DIRECTION INPUT ;
    USE SIGNAL ;
    SHAPE ABUTMENT ;
    PORT
      LAYER M3_m ;
      RECT 0 737.135 0.07 737.205 ;
    END
  END rw0_wd_in[287]
  PIN rw0_wd_in[288]
    DIRECTION INPUT ;
    USE SIGNAL ;
    SHAPE ABUTMENT ;
    PORT
      LAYER M3_m ;
      RECT 0 739.235 0.07 739.305 ;
    END
  END rw0_wd_in[288]
  PIN rw0_wd_in[289]
    DIRECTION INPUT ;
    USE SIGNAL ;
    SHAPE ABUTMENT ;
    PORT
      LAYER M3_m ;
      RECT 0 741.335 0.07 741.405 ;
    END
  END rw0_wd_in[289]
  PIN rw0_wd_in[290]
    DIRECTION INPUT ;
    USE SIGNAL ;
    SHAPE ABUTMENT ;
    PORT
      LAYER M3_m ;
      RECT 0 743.435 0.07 743.505 ;
    END
  END rw0_wd_in[290]
  PIN rw0_wd_in[291]
    DIRECTION INPUT ;
    USE SIGNAL ;
    SHAPE ABUTMENT ;
    PORT
      LAYER M3_m ;
      RECT 0 745.535 0.07 745.605 ;
    END
  END rw0_wd_in[291]
  PIN rw0_wd_in[292]
    DIRECTION INPUT ;
    USE SIGNAL ;
    SHAPE ABUTMENT ;
    PORT
      LAYER M3_m ;
      RECT 0 747.635 0.07 747.705 ;
    END
  END rw0_wd_in[292]
  PIN rw0_wd_in[293]
    DIRECTION INPUT ;
    USE SIGNAL ;
    SHAPE ABUTMENT ;
    PORT
      LAYER M3_m ;
      RECT 0 749.735 0.07 749.805 ;
    END
  END rw0_wd_in[293]
  PIN rw0_wd_in[294]
    DIRECTION INPUT ;
    USE SIGNAL ;
    SHAPE ABUTMENT ;
    PORT
      LAYER M3_m ;
      RECT 0 751.835 0.07 751.905 ;
    END
  END rw0_wd_in[294]
  PIN rw0_wd_in[295]
    DIRECTION INPUT ;
    USE SIGNAL ;
    SHAPE ABUTMENT ;
    PORT
      LAYER M3_m ;
      RECT 0 753.935 0.07 754.005 ;
    END
  END rw0_wd_in[295]
  PIN rw0_wd_in[296]
    DIRECTION INPUT ;
    USE SIGNAL ;
    SHAPE ABUTMENT ;
    PORT
      LAYER M3_m ;
      RECT 0 756.035 0.07 756.105 ;
    END
  END rw0_wd_in[296]
  PIN rw0_wd_in[297]
    DIRECTION INPUT ;
    USE SIGNAL ;
    SHAPE ABUTMENT ;
    PORT
      LAYER M3_m ;
      RECT 0 758.135 0.07 758.205 ;
    END
  END rw0_wd_in[297]
  PIN rw0_wd_in[298]
    DIRECTION INPUT ;
    USE SIGNAL ;
    SHAPE ABUTMENT ;
    PORT
      LAYER M3_m ;
      RECT 0 760.235 0.07 760.305 ;
    END
  END rw0_wd_in[298]
  PIN rw0_wd_in[299]
    DIRECTION INPUT ;
    USE SIGNAL ;
    SHAPE ABUTMENT ;
    PORT
      LAYER M3_m ;
      RECT 0 762.335 0.07 762.405 ;
    END
  END rw0_wd_in[299]
  PIN rw0_wd_in[300]
    DIRECTION INPUT ;
    USE SIGNAL ;
    SHAPE ABUTMENT ;
    PORT
      LAYER M3_m ;
      RECT 0 764.435 0.07 764.505 ;
    END
  END rw0_wd_in[300]
  PIN rw0_wd_in[301]
    DIRECTION INPUT ;
    USE SIGNAL ;
    SHAPE ABUTMENT ;
    PORT
      LAYER M3_m ;
      RECT 0 766.535 0.07 766.605 ;
    END
  END rw0_wd_in[301]
  PIN rw0_wd_in[302]
    DIRECTION INPUT ;
    USE SIGNAL ;
    SHAPE ABUTMENT ;
    PORT
      LAYER M3_m ;
      RECT 0 768.635 0.07 768.705 ;
    END
  END rw0_wd_in[302]
  PIN rw0_wd_in[303]
    DIRECTION INPUT ;
    USE SIGNAL ;
    SHAPE ABUTMENT ;
    PORT
      LAYER M3_m ;
      RECT 0 770.735 0.07 770.805 ;
    END
  END rw0_wd_in[303]
  PIN rw0_wd_in[304]
    DIRECTION INPUT ;
    USE SIGNAL ;
    SHAPE ABUTMENT ;
    PORT
      LAYER M3_m ;
      RECT 0 772.835 0.07 772.905 ;
    END
  END rw0_wd_in[304]
  PIN rw0_wd_in[305]
    DIRECTION INPUT ;
    USE SIGNAL ;
    SHAPE ABUTMENT ;
    PORT
      LAYER M3_m ;
      RECT 0 774.935 0.07 775.005 ;
    END
  END rw0_wd_in[305]
  PIN rw0_wd_in[306]
    DIRECTION INPUT ;
    USE SIGNAL ;
    SHAPE ABUTMENT ;
    PORT
      LAYER M3_m ;
      RECT 0 777.035 0.07 777.105 ;
    END
  END rw0_wd_in[306]
  PIN rw0_wd_in[307]
    DIRECTION INPUT ;
    USE SIGNAL ;
    SHAPE ABUTMENT ;
    PORT
      LAYER M3_m ;
      RECT 0 779.135 0.07 779.205 ;
    END
  END rw0_wd_in[307]
  PIN rw0_wd_in[308]
    DIRECTION INPUT ;
    USE SIGNAL ;
    SHAPE ABUTMENT ;
    PORT
      LAYER M3_m ;
      RECT 0 781.235 0.07 781.305 ;
    END
  END rw0_wd_in[308]
  PIN rw0_wd_in[309]
    DIRECTION INPUT ;
    USE SIGNAL ;
    SHAPE ABUTMENT ;
    PORT
      LAYER M3_m ;
      RECT 0 783.335 0.07 783.405 ;
    END
  END rw0_wd_in[309]
  PIN rw0_wd_in[310]
    DIRECTION INPUT ;
    USE SIGNAL ;
    SHAPE ABUTMENT ;
    PORT
      LAYER M3_m ;
      RECT 0 785.435 0.07 785.505 ;
    END
  END rw0_wd_in[310]
  PIN rw0_wd_in[311]
    DIRECTION INPUT ;
    USE SIGNAL ;
    SHAPE ABUTMENT ;
    PORT
      LAYER M3_m ;
      RECT 0 787.535 0.07 787.605 ;
    END
  END rw0_wd_in[311]
  PIN rw0_wd_in[312]
    DIRECTION INPUT ;
    USE SIGNAL ;
    SHAPE ABUTMENT ;
    PORT
      LAYER M3_m ;
      RECT 0 789.635 0.07 789.705 ;
    END
  END rw0_wd_in[312]
  PIN rw0_wd_in[313]
    DIRECTION INPUT ;
    USE SIGNAL ;
    SHAPE ABUTMENT ;
    PORT
      LAYER M3_m ;
      RECT 0 791.735 0.07 791.805 ;
    END
  END rw0_wd_in[313]
  PIN rw0_wd_in[314]
    DIRECTION INPUT ;
    USE SIGNAL ;
    SHAPE ABUTMENT ;
    PORT
      LAYER M3_m ;
      RECT 0 793.835 0.07 793.905 ;
    END
  END rw0_wd_in[314]
  PIN rw0_wd_in[315]
    DIRECTION INPUT ;
    USE SIGNAL ;
    SHAPE ABUTMENT ;
    PORT
      LAYER M3_m ;
      RECT 0 795.935 0.07 796.005 ;
    END
  END rw0_wd_in[315]
  PIN rw0_wd_in[316]
    DIRECTION INPUT ;
    USE SIGNAL ;
    SHAPE ABUTMENT ;
    PORT
      LAYER M3_m ;
      RECT 0 798.035 0.07 798.105 ;
    END
  END rw0_wd_in[316]
  PIN rw0_wd_in[317]
    DIRECTION INPUT ;
    USE SIGNAL ;
    SHAPE ABUTMENT ;
    PORT
      LAYER M3_m ;
      RECT 0 800.135 0.07 800.205 ;
    END
  END rw0_wd_in[317]
  PIN rw0_wd_in[318]
    DIRECTION INPUT ;
    USE SIGNAL ;
    SHAPE ABUTMENT ;
    PORT
      LAYER M3_m ;
      RECT 0 802.235 0.07 802.305 ;
    END
  END rw0_wd_in[318]
  PIN rw0_wd_in[319]
    DIRECTION INPUT ;
    USE SIGNAL ;
    SHAPE ABUTMENT ;
    PORT
      LAYER M3_m ;
      RECT 0 804.335 0.07 804.405 ;
    END
  END rw0_wd_in[319]
  PIN rw0_wd_in[320]
    DIRECTION INPUT ;
    USE SIGNAL ;
    SHAPE ABUTMENT ;
    PORT
      LAYER M3_m ;
      RECT 0 806.435 0.07 806.505 ;
    END
  END rw0_wd_in[320]
  PIN rw0_wd_in[321]
    DIRECTION INPUT ;
    USE SIGNAL ;
    SHAPE ABUTMENT ;
    PORT
      LAYER M3_m ;
      RECT 0 808.535 0.07 808.605 ;
    END
  END rw0_wd_in[321]
  PIN rw0_wd_in[322]
    DIRECTION INPUT ;
    USE SIGNAL ;
    SHAPE ABUTMENT ;
    PORT
      LAYER M3_m ;
      RECT 0 810.635 0.07 810.705 ;
    END
  END rw0_wd_in[322]
  PIN rw0_wd_in[323]
    DIRECTION INPUT ;
    USE SIGNAL ;
    SHAPE ABUTMENT ;
    PORT
      LAYER M3_m ;
      RECT 0 812.735 0.07 812.805 ;
    END
  END rw0_wd_in[323]
  PIN rw0_wd_in[324]
    DIRECTION INPUT ;
    USE SIGNAL ;
    SHAPE ABUTMENT ;
    PORT
      LAYER M3_m ;
      RECT 0 814.835 0.07 814.905 ;
    END
  END rw0_wd_in[324]
  PIN rw0_wd_in[325]
    DIRECTION INPUT ;
    USE SIGNAL ;
    SHAPE ABUTMENT ;
    PORT
      LAYER M3_m ;
      RECT 0 816.935 0.07 817.005 ;
    END
  END rw0_wd_in[325]
  PIN rw0_wd_in[326]
    DIRECTION INPUT ;
    USE SIGNAL ;
    SHAPE ABUTMENT ;
    PORT
      LAYER M3_m ;
      RECT 0 819.035 0.07 819.105 ;
    END
  END rw0_wd_in[326]
  PIN rw0_wd_in[327]
    DIRECTION INPUT ;
    USE SIGNAL ;
    SHAPE ABUTMENT ;
    PORT
      LAYER M3_m ;
      RECT 0 821.135 0.07 821.205 ;
    END
  END rw0_wd_in[327]
  PIN rw0_wd_in[328]
    DIRECTION INPUT ;
    USE SIGNAL ;
    SHAPE ABUTMENT ;
    PORT
      LAYER M3_m ;
      RECT 0 823.235 0.07 823.305 ;
    END
  END rw0_wd_in[328]
  PIN rw0_wd_in[329]
    DIRECTION INPUT ;
    USE SIGNAL ;
    SHAPE ABUTMENT ;
    PORT
      LAYER M3_m ;
      RECT 0 825.335 0.07 825.405 ;
    END
  END rw0_wd_in[329]
  PIN rw0_wd_in[330]
    DIRECTION INPUT ;
    USE SIGNAL ;
    SHAPE ABUTMENT ;
    PORT
      LAYER M3_m ;
      RECT 0 827.435 0.07 827.505 ;
    END
  END rw0_wd_in[330]
  PIN rw0_wd_in[331]
    DIRECTION INPUT ;
    USE SIGNAL ;
    SHAPE ABUTMENT ;
    PORT
      LAYER M3_m ;
      RECT 0 829.535 0.07 829.605 ;
    END
  END rw0_wd_in[331]
  PIN rw0_wd_in[332]
    DIRECTION INPUT ;
    USE SIGNAL ;
    SHAPE ABUTMENT ;
    PORT
      LAYER M3_m ;
      RECT 0 831.635 0.07 831.705 ;
    END
  END rw0_wd_in[332]
  PIN rw0_wd_in[333]
    DIRECTION INPUT ;
    USE SIGNAL ;
    SHAPE ABUTMENT ;
    PORT
      LAYER M3_m ;
      RECT 0 833.735 0.07 833.805 ;
    END
  END rw0_wd_in[333]
  PIN rw0_wd_in[334]
    DIRECTION INPUT ;
    USE SIGNAL ;
    SHAPE ABUTMENT ;
    PORT
      LAYER M3_m ;
      RECT 0 835.835 0.07 835.905 ;
    END
  END rw0_wd_in[334]
  PIN rw0_wd_in[335]
    DIRECTION INPUT ;
    USE SIGNAL ;
    SHAPE ABUTMENT ;
    PORT
      LAYER M3_m ;
      RECT 0 837.935 0.07 838.005 ;
    END
  END rw0_wd_in[335]
  PIN rw0_wd_in[336]
    DIRECTION INPUT ;
    USE SIGNAL ;
    SHAPE ABUTMENT ;
    PORT
      LAYER M3_m ;
      RECT 0 840.035 0.07 840.105 ;
    END
  END rw0_wd_in[336]
  PIN rw0_wd_in[337]
    DIRECTION INPUT ;
    USE SIGNAL ;
    SHAPE ABUTMENT ;
    PORT
      LAYER M3_m ;
      RECT 0 842.135 0.07 842.205 ;
    END
  END rw0_wd_in[337]
  PIN rw0_wd_in[338]
    DIRECTION INPUT ;
    USE SIGNAL ;
    SHAPE ABUTMENT ;
    PORT
      LAYER M3_m ;
      RECT 0 844.235 0.07 844.305 ;
    END
  END rw0_wd_in[338]
  PIN rw0_wd_in[339]
    DIRECTION INPUT ;
    USE SIGNAL ;
    SHAPE ABUTMENT ;
    PORT
      LAYER M3_m ;
      RECT 0 846.335 0.07 846.405 ;
    END
  END rw0_wd_in[339]
  PIN rw0_wd_in[340]
    DIRECTION INPUT ;
    USE SIGNAL ;
    SHAPE ABUTMENT ;
    PORT
      LAYER M3_m ;
      RECT 0 848.435 0.07 848.505 ;
    END
  END rw0_wd_in[340]
  PIN rw0_wd_in[341]
    DIRECTION INPUT ;
    USE SIGNAL ;
    SHAPE ABUTMENT ;
    PORT
      LAYER M3_m ;
      RECT 0 850.535 0.07 850.605 ;
    END
  END rw0_wd_in[341]
  PIN rw0_wd_in[342]
    DIRECTION INPUT ;
    USE SIGNAL ;
    SHAPE ABUTMENT ;
    PORT
      LAYER M3_m ;
      RECT 0 852.635 0.07 852.705 ;
    END
  END rw0_wd_in[342]
  PIN rw0_wd_in[343]
    DIRECTION INPUT ;
    USE SIGNAL ;
    SHAPE ABUTMENT ;
    PORT
      LAYER M3_m ;
      RECT 0 854.735 0.07 854.805 ;
    END
  END rw0_wd_in[343]
  PIN rw0_wd_in[344]
    DIRECTION INPUT ;
    USE SIGNAL ;
    SHAPE ABUTMENT ;
    PORT
      LAYER M3_m ;
      RECT 0 856.835 0.07 856.905 ;
    END
  END rw0_wd_in[344]
  PIN rw0_wd_in[345]
    DIRECTION INPUT ;
    USE SIGNAL ;
    SHAPE ABUTMENT ;
    PORT
      LAYER M3_m ;
      RECT 0 858.935 0.07 859.005 ;
    END
  END rw0_wd_in[345]
  PIN rw0_wd_in[346]
    DIRECTION INPUT ;
    USE SIGNAL ;
    SHAPE ABUTMENT ;
    PORT
      LAYER M3_m ;
      RECT 0 861.035 0.07 861.105 ;
    END
  END rw0_wd_in[346]
  PIN rw0_wd_in[347]
    DIRECTION INPUT ;
    USE SIGNAL ;
    SHAPE ABUTMENT ;
    PORT
      LAYER M3_m ;
      RECT 0 863.135 0.07 863.205 ;
    END
  END rw0_wd_in[347]
  PIN rw0_wd_in[348]
    DIRECTION INPUT ;
    USE SIGNAL ;
    SHAPE ABUTMENT ;
    PORT
      LAYER M3_m ;
      RECT 0 865.235 0.07 865.305 ;
    END
  END rw0_wd_in[348]
  PIN rw0_wd_in[349]
    DIRECTION INPUT ;
    USE SIGNAL ;
    SHAPE ABUTMENT ;
    PORT
      LAYER M3_m ;
      RECT 0 867.335 0.07 867.405 ;
    END
  END rw0_wd_in[349]
  PIN rw0_wd_in[350]
    DIRECTION INPUT ;
    USE SIGNAL ;
    SHAPE ABUTMENT ;
    PORT
      LAYER M3_m ;
      RECT 0 869.435 0.07 869.505 ;
    END
  END rw0_wd_in[350]
  PIN rw0_wd_in[351]
    DIRECTION INPUT ;
    USE SIGNAL ;
    SHAPE ABUTMENT ;
    PORT
      LAYER M3_m ;
      RECT 0 871.535 0.07 871.605 ;
    END
  END rw0_wd_in[351]
  PIN rw0_wd_in[352]
    DIRECTION INPUT ;
    USE SIGNAL ;
    SHAPE ABUTMENT ;
    PORT
      LAYER M3_m ;
      RECT 0 873.635 0.07 873.705 ;
    END
  END rw0_wd_in[352]
  PIN rw0_wd_in[353]
    DIRECTION INPUT ;
    USE SIGNAL ;
    SHAPE ABUTMENT ;
    PORT
      LAYER M3_m ;
      RECT 0 875.735 0.07 875.805 ;
    END
  END rw0_wd_in[353]
  PIN rw0_wd_in[354]
    DIRECTION INPUT ;
    USE SIGNAL ;
    SHAPE ABUTMENT ;
    PORT
      LAYER M3_m ;
      RECT 0 877.835 0.07 877.905 ;
    END
  END rw0_wd_in[354]
  PIN rw0_wd_in[355]
    DIRECTION INPUT ;
    USE SIGNAL ;
    SHAPE ABUTMENT ;
    PORT
      LAYER M3_m ;
      RECT 0 879.935 0.07 880.005 ;
    END
  END rw0_wd_in[355]
  PIN rw0_wd_in[356]
    DIRECTION INPUT ;
    USE SIGNAL ;
    SHAPE ABUTMENT ;
    PORT
      LAYER M3_m ;
      RECT 0 882.035 0.07 882.105 ;
    END
  END rw0_wd_in[356]
  PIN rw0_wd_in[357]
    DIRECTION INPUT ;
    USE SIGNAL ;
    SHAPE ABUTMENT ;
    PORT
      LAYER M3_m ;
      RECT 0 884.135 0.07 884.205 ;
    END
  END rw0_wd_in[357]
  PIN rw0_wd_in[358]
    DIRECTION INPUT ;
    USE SIGNAL ;
    SHAPE ABUTMENT ;
    PORT
      LAYER M3_m ;
      RECT 0 886.235 0.07 886.305 ;
    END
  END rw0_wd_in[358]
  PIN rw0_wd_in[359]
    DIRECTION INPUT ;
    USE SIGNAL ;
    SHAPE ABUTMENT ;
    PORT
      LAYER M3_m ;
      RECT 0 888.335 0.07 888.405 ;
    END
  END rw0_wd_in[359]
  PIN rw0_wd_in[360]
    DIRECTION INPUT ;
    USE SIGNAL ;
    SHAPE ABUTMENT ;
    PORT
      LAYER M3_m ;
      RECT 0 890.435 0.07 890.505 ;
    END
  END rw0_wd_in[360]
  PIN rw0_wd_in[361]
    DIRECTION INPUT ;
    USE SIGNAL ;
    SHAPE ABUTMENT ;
    PORT
      LAYER M3_m ;
      RECT 0 892.535 0.07 892.605 ;
    END
  END rw0_wd_in[361]
  PIN rw0_wd_in[362]
    DIRECTION INPUT ;
    USE SIGNAL ;
    SHAPE ABUTMENT ;
    PORT
      LAYER M3_m ;
      RECT 0 894.635 0.07 894.705 ;
    END
  END rw0_wd_in[362]
  PIN rw0_wd_in[363]
    DIRECTION INPUT ;
    USE SIGNAL ;
    SHAPE ABUTMENT ;
    PORT
      LAYER M3_m ;
      RECT 0 896.735 0.07 896.805 ;
    END
  END rw0_wd_in[363]
  PIN rw0_wd_in[364]
    DIRECTION INPUT ;
    USE SIGNAL ;
    SHAPE ABUTMENT ;
    PORT
      LAYER M3_m ;
      RECT 0 898.835 0.07 898.905 ;
    END
  END rw0_wd_in[364]
  PIN rw0_wd_in[365]
    DIRECTION INPUT ;
    USE SIGNAL ;
    SHAPE ABUTMENT ;
    PORT
      LAYER M3_m ;
      RECT 0 900.935 0.07 901.005 ;
    END
  END rw0_wd_in[365]
  PIN rw0_wd_in[366]
    DIRECTION INPUT ;
    USE SIGNAL ;
    SHAPE ABUTMENT ;
    PORT
      LAYER M3_m ;
      RECT 0 903.035 0.07 903.105 ;
    END
  END rw0_wd_in[366]
  PIN rw0_wd_in[367]
    DIRECTION INPUT ;
    USE SIGNAL ;
    SHAPE ABUTMENT ;
    PORT
      LAYER M3_m ;
      RECT 0 905.135 0.07 905.205 ;
    END
  END rw0_wd_in[367]
  PIN rw0_wd_in[368]
    DIRECTION INPUT ;
    USE SIGNAL ;
    SHAPE ABUTMENT ;
    PORT
      LAYER M3_m ;
      RECT 0 907.235 0.07 907.305 ;
    END
  END rw0_wd_in[368]
  PIN rw0_wd_in[369]
    DIRECTION INPUT ;
    USE SIGNAL ;
    SHAPE ABUTMENT ;
    PORT
      LAYER M3_m ;
      RECT 0 909.335 0.07 909.405 ;
    END
  END rw0_wd_in[369]
  PIN rw0_wd_in[370]
    DIRECTION INPUT ;
    USE SIGNAL ;
    SHAPE ABUTMENT ;
    PORT
      LAYER M3_m ;
      RECT 0 911.435 0.07 911.505 ;
    END
  END rw0_wd_in[370]
  PIN rw0_wd_in[371]
    DIRECTION INPUT ;
    USE SIGNAL ;
    SHAPE ABUTMENT ;
    PORT
      LAYER M3_m ;
      RECT 0 913.535 0.07 913.605 ;
    END
  END rw0_wd_in[371]
  PIN rw0_wd_in[372]
    DIRECTION INPUT ;
    USE SIGNAL ;
    SHAPE ABUTMENT ;
    PORT
      LAYER M3_m ;
      RECT 0 915.635 0.07 915.705 ;
    END
  END rw0_wd_in[372]
  PIN rw0_wd_in[373]
    DIRECTION INPUT ;
    USE SIGNAL ;
    SHAPE ABUTMENT ;
    PORT
      LAYER M3_m ;
      RECT 0 917.735 0.07 917.805 ;
    END
  END rw0_wd_in[373]
  PIN rw0_wd_in[374]
    DIRECTION INPUT ;
    USE SIGNAL ;
    SHAPE ABUTMENT ;
    PORT
      LAYER M3_m ;
      RECT 0 919.835 0.07 919.905 ;
    END
  END rw0_wd_in[374]
  PIN rw0_wd_in[375]
    DIRECTION INPUT ;
    USE SIGNAL ;
    SHAPE ABUTMENT ;
    PORT
      LAYER M3_m ;
      RECT 0 921.935 0.07 922.005 ;
    END
  END rw0_wd_in[375]
  PIN rw0_wd_in[376]
    DIRECTION INPUT ;
    USE SIGNAL ;
    SHAPE ABUTMENT ;
    PORT
      LAYER M3_m ;
      RECT 0 924.035 0.07 924.105 ;
    END
  END rw0_wd_in[376]
  PIN rw0_wd_in[377]
    DIRECTION INPUT ;
    USE SIGNAL ;
    SHAPE ABUTMENT ;
    PORT
      LAYER M3_m ;
      RECT 0 926.135 0.07 926.205 ;
    END
  END rw0_wd_in[377]
  PIN rw0_wd_in[378]
    DIRECTION INPUT ;
    USE SIGNAL ;
    SHAPE ABUTMENT ;
    PORT
      LAYER M3_m ;
      RECT 0 928.235 0.07 928.305 ;
    END
  END rw0_wd_in[378]
  PIN rw0_wd_in[379]
    DIRECTION INPUT ;
    USE SIGNAL ;
    SHAPE ABUTMENT ;
    PORT
      LAYER M3_m ;
      RECT 0 930.335 0.07 930.405 ;
    END
  END rw0_wd_in[379]
  PIN rw0_wd_in[380]
    DIRECTION INPUT ;
    USE SIGNAL ;
    SHAPE ABUTMENT ;
    PORT
      LAYER M3_m ;
      RECT 0 932.435 0.07 932.505 ;
    END
  END rw0_wd_in[380]
  PIN rw0_wd_in[381]
    DIRECTION INPUT ;
    USE SIGNAL ;
    SHAPE ABUTMENT ;
    PORT
      LAYER M3_m ;
      RECT 0 934.535 0.07 934.605 ;
    END
  END rw0_wd_in[381]
  PIN rw0_wd_in[382]
    DIRECTION INPUT ;
    USE SIGNAL ;
    SHAPE ABUTMENT ;
    PORT
      LAYER M3_m ;
      RECT 0 936.635 0.07 936.705 ;
    END
  END rw0_wd_in[382]
  PIN rw0_wd_in[383]
    DIRECTION INPUT ;
    USE SIGNAL ;
    SHAPE ABUTMENT ;
    PORT
      LAYER M3_m ;
      RECT 0 938.735 0.07 938.805 ;
    END
  END rw0_wd_in[383]
  PIN rw0_wd_in[384]
    DIRECTION INPUT ;
    USE SIGNAL ;
    SHAPE ABUTMENT ;
    PORT
      LAYER M3_m ;
      RECT 0 940.835 0.07 940.905 ;
    END
  END rw0_wd_in[384]
  PIN rw0_wd_in[385]
    DIRECTION INPUT ;
    USE SIGNAL ;
    SHAPE ABUTMENT ;
    PORT
      LAYER M3_m ;
      RECT 0 942.935 0.07 943.005 ;
    END
  END rw0_wd_in[385]
  PIN rw0_wd_in[386]
    DIRECTION INPUT ;
    USE SIGNAL ;
    SHAPE ABUTMENT ;
    PORT
      LAYER M3_m ;
      RECT 0 945.035 0.07 945.105 ;
    END
  END rw0_wd_in[386]
  PIN rw0_wd_in[387]
    DIRECTION INPUT ;
    USE SIGNAL ;
    SHAPE ABUTMENT ;
    PORT
      LAYER M3_m ;
      RECT 0 947.135 0.07 947.205 ;
    END
  END rw0_wd_in[387]
  PIN rw0_wd_in[388]
    DIRECTION INPUT ;
    USE SIGNAL ;
    SHAPE ABUTMENT ;
    PORT
      LAYER M3_m ;
      RECT 0 949.235 0.07 949.305 ;
    END
  END rw0_wd_in[388]
  PIN rw0_wd_in[389]
    DIRECTION INPUT ;
    USE SIGNAL ;
    SHAPE ABUTMENT ;
    PORT
      LAYER M3_m ;
      RECT 0 951.335 0.07 951.405 ;
    END
  END rw0_wd_in[389]
  PIN rw0_wd_in[390]
    DIRECTION INPUT ;
    USE SIGNAL ;
    SHAPE ABUTMENT ;
    PORT
      LAYER M3_m ;
      RECT 0 953.435 0.07 953.505 ;
    END
  END rw0_wd_in[390]
  PIN rw0_wd_in[391]
    DIRECTION INPUT ;
    USE SIGNAL ;
    SHAPE ABUTMENT ;
    PORT
      LAYER M3_m ;
      RECT 0 955.535 0.07 955.605 ;
    END
  END rw0_wd_in[391]
  PIN rw0_wd_in[392]
    DIRECTION INPUT ;
    USE SIGNAL ;
    SHAPE ABUTMENT ;
    PORT
      LAYER M3_m ;
      RECT 0 957.635 0.07 957.705 ;
    END
  END rw0_wd_in[392]
  PIN rw0_wd_in[393]
    DIRECTION INPUT ;
    USE SIGNAL ;
    SHAPE ABUTMENT ;
    PORT
      LAYER M3_m ;
      RECT 0 959.735 0.07 959.805 ;
    END
  END rw0_wd_in[393]
  PIN rw0_wd_in[394]
    DIRECTION INPUT ;
    USE SIGNAL ;
    SHAPE ABUTMENT ;
    PORT
      LAYER M3_m ;
      RECT 0 961.835 0.07 961.905 ;
    END
  END rw0_wd_in[394]
  PIN rw0_wd_in[395]
    DIRECTION INPUT ;
    USE SIGNAL ;
    SHAPE ABUTMENT ;
    PORT
      LAYER M3_m ;
      RECT 0 963.935 0.07 964.005 ;
    END
  END rw0_wd_in[395]
  PIN rw0_wd_in[396]
    DIRECTION INPUT ;
    USE SIGNAL ;
    SHAPE ABUTMENT ;
    PORT
      LAYER M3_m ;
      RECT 0 966.035 0.07 966.105 ;
    END
  END rw0_wd_in[396]
  PIN rw0_wd_in[397]
    DIRECTION INPUT ;
    USE SIGNAL ;
    SHAPE ABUTMENT ;
    PORT
      LAYER M3_m ;
      RECT 0 968.135 0.07 968.205 ;
    END
  END rw0_wd_in[397]
  PIN rw0_wd_in[398]
    DIRECTION INPUT ;
    USE SIGNAL ;
    SHAPE ABUTMENT ;
    PORT
      LAYER M3_m ;
      RECT 0 970.235 0.07 970.305 ;
    END
  END rw0_wd_in[398]
  PIN rw0_wd_in[399]
    DIRECTION INPUT ;
    USE SIGNAL ;
    SHAPE ABUTMENT ;
    PORT
      LAYER M3_m ;
      RECT 0 972.335 0.07 972.405 ;
    END
  END rw0_wd_in[399]
  PIN rw0_wd_in[400]
    DIRECTION INPUT ;
    USE SIGNAL ;
    SHAPE ABUTMENT ;
    PORT
      LAYER M3_m ;
      RECT 0 974.435 0.07 974.505 ;
    END
  END rw0_wd_in[400]
  PIN rw0_wd_in[401]
    DIRECTION INPUT ;
    USE SIGNAL ;
    SHAPE ABUTMENT ;
    PORT
      LAYER M3_m ;
      RECT 0 976.535 0.07 976.605 ;
    END
  END rw0_wd_in[401]
  PIN rw0_wd_in[402]
    DIRECTION INPUT ;
    USE SIGNAL ;
    SHAPE ABUTMENT ;
    PORT
      LAYER M3_m ;
      RECT 0 978.635 0.07 978.705 ;
    END
  END rw0_wd_in[402]
  PIN rw0_wd_in[403]
    DIRECTION INPUT ;
    USE SIGNAL ;
    SHAPE ABUTMENT ;
    PORT
      LAYER M3_m ;
      RECT 0 980.735 0.07 980.805 ;
    END
  END rw0_wd_in[403]
  PIN rw0_wd_in[404]
    DIRECTION INPUT ;
    USE SIGNAL ;
    SHAPE ABUTMENT ;
    PORT
      LAYER M3_m ;
      RECT 0 982.835 0.07 982.905 ;
    END
  END rw0_wd_in[404]
  PIN rw0_wd_in[405]
    DIRECTION INPUT ;
    USE SIGNAL ;
    SHAPE ABUTMENT ;
    PORT
      LAYER M3_m ;
      RECT 0 984.935 0.07 985.005 ;
    END
  END rw0_wd_in[405]
  PIN rw0_wd_in[406]
    DIRECTION INPUT ;
    USE SIGNAL ;
    SHAPE ABUTMENT ;
    PORT
      LAYER M3_m ;
      RECT 0 987.035 0.07 987.105 ;
    END
  END rw0_wd_in[406]
  PIN rw0_wd_in[407]
    DIRECTION INPUT ;
    USE SIGNAL ;
    SHAPE ABUTMENT ;
    PORT
      LAYER M3_m ;
      RECT 0 989.135 0.07 989.205 ;
    END
  END rw0_wd_in[407]
  PIN rw0_wd_in[408]
    DIRECTION INPUT ;
    USE SIGNAL ;
    SHAPE ABUTMENT ;
    PORT
      LAYER M3_m ;
      RECT 0 991.235 0.07 991.305 ;
    END
  END rw0_wd_in[408]
  PIN rw0_wd_in[409]
    DIRECTION INPUT ;
    USE SIGNAL ;
    SHAPE ABUTMENT ;
    PORT
      LAYER M3_m ;
      RECT 0 993.335 0.07 993.405 ;
    END
  END rw0_wd_in[409]
  PIN rw0_wd_in[410]
    DIRECTION INPUT ;
    USE SIGNAL ;
    SHAPE ABUTMENT ;
    PORT
      LAYER M3_m ;
      RECT 0 995.435 0.07 995.505 ;
    END
  END rw0_wd_in[410]
  PIN rw0_wd_in[411]
    DIRECTION INPUT ;
    USE SIGNAL ;
    SHAPE ABUTMENT ;
    PORT
      LAYER M3_m ;
      RECT 0 997.535 0.07 997.605 ;
    END
  END rw0_wd_in[411]
  PIN rw0_wd_in[412]
    DIRECTION INPUT ;
    USE SIGNAL ;
    SHAPE ABUTMENT ;
    PORT
      LAYER M3_m ;
      RECT 0 999.635 0.07 999.705 ;
    END
  END rw0_wd_in[412]
  PIN rw0_wd_in[413]
    DIRECTION INPUT ;
    USE SIGNAL ;
    SHAPE ABUTMENT ;
    PORT
      LAYER M3_m ;
      RECT 0 1001.735 0.07 1001.805 ;
    END
  END rw0_wd_in[413]
  PIN rw0_wd_in[414]
    DIRECTION INPUT ;
    USE SIGNAL ;
    SHAPE ABUTMENT ;
    PORT
      LAYER M3_m ;
      RECT 0 1003.835 0.07 1003.905 ;
    END
  END rw0_wd_in[414]
  PIN rw0_wd_in[415]
    DIRECTION INPUT ;
    USE SIGNAL ;
    SHAPE ABUTMENT ;
    PORT
      LAYER M3_m ;
      RECT 0 1005.935 0.07 1006.005 ;
    END
  END rw0_wd_in[415]
  PIN rw0_wd_in[416]
    DIRECTION INPUT ;
    USE SIGNAL ;
    SHAPE ABUTMENT ;
    PORT
      LAYER M3_m ;
      RECT 0 1008.035 0.07 1008.105 ;
    END
  END rw0_wd_in[416]
  PIN rw0_wd_in[417]
    DIRECTION INPUT ;
    USE SIGNAL ;
    SHAPE ABUTMENT ;
    PORT
      LAYER M3_m ;
      RECT 0 1010.135 0.07 1010.205 ;
    END
  END rw0_wd_in[417]
  PIN rw0_wd_in[418]
    DIRECTION INPUT ;
    USE SIGNAL ;
    SHAPE ABUTMENT ;
    PORT
      LAYER M3_m ;
      RECT 0 1012.235 0.07 1012.305 ;
    END
  END rw0_wd_in[418]
  PIN rw0_wd_in[419]
    DIRECTION INPUT ;
    USE SIGNAL ;
    SHAPE ABUTMENT ;
    PORT
      LAYER M3_m ;
      RECT 0 1014.335 0.07 1014.405 ;
    END
  END rw0_wd_in[419]
  PIN rw0_wd_in[420]
    DIRECTION INPUT ;
    USE SIGNAL ;
    SHAPE ABUTMENT ;
    PORT
      LAYER M3_m ;
      RECT 0 1016.435 0.07 1016.505 ;
    END
  END rw0_wd_in[420]
  PIN rw0_wd_in[421]
    DIRECTION INPUT ;
    USE SIGNAL ;
    SHAPE ABUTMENT ;
    PORT
      LAYER M3_m ;
      RECT 0 1018.535 0.07 1018.605 ;
    END
  END rw0_wd_in[421]
  PIN rw0_wd_in[422]
    DIRECTION INPUT ;
    USE SIGNAL ;
    SHAPE ABUTMENT ;
    PORT
      LAYER M3_m ;
      RECT 0 1020.635 0.07 1020.705 ;
    END
  END rw0_wd_in[422]
  PIN rw0_wd_in[423]
    DIRECTION INPUT ;
    USE SIGNAL ;
    SHAPE ABUTMENT ;
    PORT
      LAYER M3_m ;
      RECT 0 1022.735 0.07 1022.805 ;
    END
  END rw0_wd_in[423]
  PIN rw0_wd_in[424]
    DIRECTION INPUT ;
    USE SIGNAL ;
    SHAPE ABUTMENT ;
    PORT
      LAYER M3_m ;
      RECT 0 1024.835 0.07 1024.905 ;
    END
  END rw0_wd_in[424]
  PIN rw0_wd_in[425]
    DIRECTION INPUT ;
    USE SIGNAL ;
    SHAPE ABUTMENT ;
    PORT
      LAYER M3_m ;
      RECT 0 1026.935 0.07 1027.005 ;
    END
  END rw0_wd_in[425]
  PIN rw0_wd_in[426]
    DIRECTION INPUT ;
    USE SIGNAL ;
    SHAPE ABUTMENT ;
    PORT
      LAYER M3_m ;
      RECT 0 1029.035 0.07 1029.105 ;
    END
  END rw0_wd_in[426]
  PIN rw0_wd_in[427]
    DIRECTION INPUT ;
    USE SIGNAL ;
    SHAPE ABUTMENT ;
    PORT
      LAYER M3_m ;
      RECT 0 1031.135 0.07 1031.205 ;
    END
  END rw0_wd_in[427]
  PIN rw0_wd_in[428]
    DIRECTION INPUT ;
    USE SIGNAL ;
    SHAPE ABUTMENT ;
    PORT
      LAYER M3_m ;
      RECT 0 1033.235 0.07 1033.305 ;
    END
  END rw0_wd_in[428]
  PIN rw0_wd_in[429]
    DIRECTION INPUT ;
    USE SIGNAL ;
    SHAPE ABUTMENT ;
    PORT
      LAYER M3_m ;
      RECT 0 1035.335 0.07 1035.405 ;
    END
  END rw0_wd_in[429]
  PIN rw0_wd_in[430]
    DIRECTION INPUT ;
    USE SIGNAL ;
    SHAPE ABUTMENT ;
    PORT
      LAYER M3_m ;
      RECT 0 1037.435 0.07 1037.505 ;
    END
  END rw0_wd_in[430]
  PIN rw0_wd_in[431]
    DIRECTION INPUT ;
    USE SIGNAL ;
    SHAPE ABUTMENT ;
    PORT
      LAYER M3_m ;
      RECT 0 1039.535 0.07 1039.605 ;
    END
  END rw0_wd_in[431]
  PIN rw0_wd_in[432]
    DIRECTION INPUT ;
    USE SIGNAL ;
    SHAPE ABUTMENT ;
    PORT
      LAYER M3_m ;
      RECT 0 1041.635 0.07 1041.705 ;
    END
  END rw0_wd_in[432]
  PIN rw0_wd_in[433]
    DIRECTION INPUT ;
    USE SIGNAL ;
    SHAPE ABUTMENT ;
    PORT
      LAYER M3_m ;
      RECT 0 1043.735 0.07 1043.805 ;
    END
  END rw0_wd_in[433]
  PIN rw0_wd_in[434]
    DIRECTION INPUT ;
    USE SIGNAL ;
    SHAPE ABUTMENT ;
    PORT
      LAYER M3_m ;
      RECT 0 1045.835 0.07 1045.905 ;
    END
  END rw0_wd_in[434]
  PIN rw0_wd_in[435]
    DIRECTION INPUT ;
    USE SIGNAL ;
    SHAPE ABUTMENT ;
    PORT
      LAYER M3_m ;
      RECT 0 1047.935 0.07 1048.005 ;
    END
  END rw0_wd_in[435]
  PIN rw0_wd_in[436]
    DIRECTION INPUT ;
    USE SIGNAL ;
    SHAPE ABUTMENT ;
    PORT
      LAYER M3_m ;
      RECT 0 1050.035 0.07 1050.105 ;
    END
  END rw0_wd_in[436]
  PIN rw0_wd_in[437]
    DIRECTION INPUT ;
    USE SIGNAL ;
    SHAPE ABUTMENT ;
    PORT
      LAYER M3_m ;
      RECT 0 1052.135 0.07 1052.205 ;
    END
  END rw0_wd_in[437]
  PIN rw0_wd_in[438]
    DIRECTION INPUT ;
    USE SIGNAL ;
    SHAPE ABUTMENT ;
    PORT
      LAYER M3_m ;
      RECT 0 1054.235 0.07 1054.305 ;
    END
  END rw0_wd_in[438]
  PIN rw0_wd_in[439]
    DIRECTION INPUT ;
    USE SIGNAL ;
    SHAPE ABUTMENT ;
    PORT
      LAYER M3_m ;
      RECT 0 1056.335 0.07 1056.405 ;
    END
  END rw0_wd_in[439]
  PIN rw0_wd_in[440]
    DIRECTION INPUT ;
    USE SIGNAL ;
    SHAPE ABUTMENT ;
    PORT
      LAYER M3_m ;
      RECT 0 1058.435 0.07 1058.505 ;
    END
  END rw0_wd_in[440]
  PIN rw0_wd_in[441]
    DIRECTION INPUT ;
    USE SIGNAL ;
    SHAPE ABUTMENT ;
    PORT
      LAYER M3_m ;
      RECT 0 1060.535 0.07 1060.605 ;
    END
  END rw0_wd_in[441]
  PIN rw0_wd_in[442]
    DIRECTION INPUT ;
    USE SIGNAL ;
    SHAPE ABUTMENT ;
    PORT
      LAYER M3_m ;
      RECT 0 1062.635 0.07 1062.705 ;
    END
  END rw0_wd_in[442]
  PIN rw0_wd_in[443]
    DIRECTION INPUT ;
    USE SIGNAL ;
    SHAPE ABUTMENT ;
    PORT
      LAYER M3_m ;
      RECT 0 1064.735 0.07 1064.805 ;
    END
  END rw0_wd_in[443]
  PIN rw0_wd_in[444]
    DIRECTION INPUT ;
    USE SIGNAL ;
    SHAPE ABUTMENT ;
    PORT
      LAYER M3_m ;
      RECT 0 1066.835 0.07 1066.905 ;
    END
  END rw0_wd_in[444]
  PIN rw0_wd_in[445]
    DIRECTION INPUT ;
    USE SIGNAL ;
    SHAPE ABUTMENT ;
    PORT
      LAYER M3_m ;
      RECT 0 1068.935 0.07 1069.005 ;
    END
  END rw0_wd_in[445]
  PIN rw0_wd_in[446]
    DIRECTION INPUT ;
    USE SIGNAL ;
    SHAPE ABUTMENT ;
    PORT
      LAYER M3_m ;
      RECT 0 1071.035 0.07 1071.105 ;
    END
  END rw0_wd_in[446]
  PIN rw0_wd_in[447]
    DIRECTION INPUT ;
    USE SIGNAL ;
    SHAPE ABUTMENT ;
    PORT
      LAYER M3_m ;
      RECT 0 1073.135 0.07 1073.205 ;
    END
  END rw0_wd_in[447]
  PIN rw0_wd_in[448]
    DIRECTION INPUT ;
    USE SIGNAL ;
    SHAPE ABUTMENT ;
    PORT
      LAYER M3_m ;
      RECT 0 1075.235 0.07 1075.305 ;
    END
  END rw0_wd_in[448]
  PIN rw0_wd_in[449]
    DIRECTION INPUT ;
    USE SIGNAL ;
    SHAPE ABUTMENT ;
    PORT
      LAYER M3_m ;
      RECT 0 1077.335 0.07 1077.405 ;
    END
  END rw0_wd_in[449]
  PIN rw0_wd_in[450]
    DIRECTION INPUT ;
    USE SIGNAL ;
    SHAPE ABUTMENT ;
    PORT
      LAYER M3_m ;
      RECT 0 1079.435 0.07 1079.505 ;
    END
  END rw0_wd_in[450]
  PIN rw0_wd_in[451]
    DIRECTION INPUT ;
    USE SIGNAL ;
    SHAPE ABUTMENT ;
    PORT
      LAYER M3_m ;
      RECT 0 1081.535 0.07 1081.605 ;
    END
  END rw0_wd_in[451]
  PIN rw0_wd_in[452]
    DIRECTION INPUT ;
    USE SIGNAL ;
    SHAPE ABUTMENT ;
    PORT
      LAYER M3_m ;
      RECT 0 1083.635 0.07 1083.705 ;
    END
  END rw0_wd_in[452]
  PIN rw0_wd_in[453]
    DIRECTION INPUT ;
    USE SIGNAL ;
    SHAPE ABUTMENT ;
    PORT
      LAYER M3_m ;
      RECT 0 1085.735 0.07 1085.805 ;
    END
  END rw0_wd_in[453]
  PIN rw0_wd_in[454]
    DIRECTION INPUT ;
    USE SIGNAL ;
    SHAPE ABUTMENT ;
    PORT
      LAYER M3_m ;
      RECT 0 1087.835 0.07 1087.905 ;
    END
  END rw0_wd_in[454]
  PIN rw0_wd_in[455]
    DIRECTION INPUT ;
    USE SIGNAL ;
    SHAPE ABUTMENT ;
    PORT
      LAYER M3_m ;
      RECT 0 1089.935 0.07 1090.005 ;
    END
  END rw0_wd_in[455]
  PIN rw0_wd_in[456]
    DIRECTION INPUT ;
    USE SIGNAL ;
    SHAPE ABUTMENT ;
    PORT
      LAYER M3_m ;
      RECT 0 1092.035 0.07 1092.105 ;
    END
  END rw0_wd_in[456]
  PIN rw0_wd_in[457]
    DIRECTION INPUT ;
    USE SIGNAL ;
    SHAPE ABUTMENT ;
    PORT
      LAYER M3_m ;
      RECT 0 1094.135 0.07 1094.205 ;
    END
  END rw0_wd_in[457]
  PIN rw0_wd_in[458]
    DIRECTION INPUT ;
    USE SIGNAL ;
    SHAPE ABUTMENT ;
    PORT
      LAYER M3_m ;
      RECT 0 1096.235 0.07 1096.305 ;
    END
  END rw0_wd_in[458]
  PIN rw0_wd_in[459]
    DIRECTION INPUT ;
    USE SIGNAL ;
    SHAPE ABUTMENT ;
    PORT
      LAYER M3_m ;
      RECT 0 1098.335 0.07 1098.405 ;
    END
  END rw0_wd_in[459]
  PIN rw0_wd_in[460]
    DIRECTION INPUT ;
    USE SIGNAL ;
    SHAPE ABUTMENT ;
    PORT
      LAYER M3_m ;
      RECT 0 1100.435 0.07 1100.505 ;
    END
  END rw0_wd_in[460]
  PIN rw0_wd_in[461]
    DIRECTION INPUT ;
    USE SIGNAL ;
    SHAPE ABUTMENT ;
    PORT
      LAYER M3_m ;
      RECT 0 1102.535 0.07 1102.605 ;
    END
  END rw0_wd_in[461]
  PIN rw0_wd_in[462]
    DIRECTION INPUT ;
    USE SIGNAL ;
    SHAPE ABUTMENT ;
    PORT
      LAYER M3_m ;
      RECT 0 1104.635 0.07 1104.705 ;
    END
  END rw0_wd_in[462]
  PIN rw0_wd_in[463]
    DIRECTION INPUT ;
    USE SIGNAL ;
    SHAPE ABUTMENT ;
    PORT
      LAYER M3_m ;
      RECT 0 1106.735 0.07 1106.805 ;
    END
  END rw0_wd_in[463]
  PIN rw0_wd_in[464]
    DIRECTION INPUT ;
    USE SIGNAL ;
    SHAPE ABUTMENT ;
    PORT
      LAYER M3_m ;
      RECT 0 1108.835 0.07 1108.905 ;
    END
  END rw0_wd_in[464]
  PIN rw0_wd_in[465]
    DIRECTION INPUT ;
    USE SIGNAL ;
    SHAPE ABUTMENT ;
    PORT
      LAYER M3_m ;
      RECT 0 1110.935 0.07 1111.005 ;
    END
  END rw0_wd_in[465]
  PIN rw0_wd_in[466]
    DIRECTION INPUT ;
    USE SIGNAL ;
    SHAPE ABUTMENT ;
    PORT
      LAYER M3_m ;
      RECT 0 1113.035 0.07 1113.105 ;
    END
  END rw0_wd_in[466]
  PIN rw0_wd_in[467]
    DIRECTION INPUT ;
    USE SIGNAL ;
    SHAPE ABUTMENT ;
    PORT
      LAYER M3_m ;
      RECT 0 1115.135 0.07 1115.205 ;
    END
  END rw0_wd_in[467]
  PIN rw0_wd_in[468]
    DIRECTION INPUT ;
    USE SIGNAL ;
    SHAPE ABUTMENT ;
    PORT
      LAYER M3_m ;
      RECT 0 1117.235 0.07 1117.305 ;
    END
  END rw0_wd_in[468]
  PIN rw0_wd_in[469]
    DIRECTION INPUT ;
    USE SIGNAL ;
    SHAPE ABUTMENT ;
    PORT
      LAYER M3_m ;
      RECT 0 1119.335 0.07 1119.405 ;
    END
  END rw0_wd_in[469]
  PIN rw0_wd_in[470]
    DIRECTION INPUT ;
    USE SIGNAL ;
    SHAPE ABUTMENT ;
    PORT
      LAYER M3_m ;
      RECT 0 1121.435 0.07 1121.505 ;
    END
  END rw0_wd_in[470]
  PIN rw0_wd_in[471]
    DIRECTION INPUT ;
    USE SIGNAL ;
    SHAPE ABUTMENT ;
    PORT
      LAYER M3_m ;
      RECT 0 1123.535 0.07 1123.605 ;
    END
  END rw0_wd_in[471]
  PIN rw0_wd_in[472]
    DIRECTION INPUT ;
    USE SIGNAL ;
    SHAPE ABUTMENT ;
    PORT
      LAYER M3_m ;
      RECT 0 1125.635 0.07 1125.705 ;
    END
  END rw0_wd_in[472]
  PIN rw0_wd_in[473]
    DIRECTION INPUT ;
    USE SIGNAL ;
    SHAPE ABUTMENT ;
    PORT
      LAYER M3_m ;
      RECT 0 1127.735 0.07 1127.805 ;
    END
  END rw0_wd_in[473]
  PIN rw0_wd_in[474]
    DIRECTION INPUT ;
    USE SIGNAL ;
    SHAPE ABUTMENT ;
    PORT
      LAYER M3_m ;
      RECT 0 1129.835 0.07 1129.905 ;
    END
  END rw0_wd_in[474]
  PIN rw0_wd_in[475]
    DIRECTION INPUT ;
    USE SIGNAL ;
    SHAPE ABUTMENT ;
    PORT
      LAYER M3_m ;
      RECT 0 1131.935 0.07 1132.005 ;
    END
  END rw0_wd_in[475]
  PIN rw0_wd_in[476]
    DIRECTION INPUT ;
    USE SIGNAL ;
    SHAPE ABUTMENT ;
    PORT
      LAYER M3_m ;
      RECT 0 1134.035 0.07 1134.105 ;
    END
  END rw0_wd_in[476]
  PIN rw0_wd_in[477]
    DIRECTION INPUT ;
    USE SIGNAL ;
    SHAPE ABUTMENT ;
    PORT
      LAYER M3_m ;
      RECT 0 1136.135 0.07 1136.205 ;
    END
  END rw0_wd_in[477]
  PIN rw0_wd_in[478]
    DIRECTION INPUT ;
    USE SIGNAL ;
    SHAPE ABUTMENT ;
    PORT
      LAYER M3_m ;
      RECT 0 1138.235 0.07 1138.305 ;
    END
  END rw0_wd_in[478]
  PIN rw0_wd_in[479]
    DIRECTION INPUT ;
    USE SIGNAL ;
    SHAPE ABUTMENT ;
    PORT
      LAYER M3_m ;
      RECT 0 1140.335 0.07 1140.405 ;
    END
  END rw0_wd_in[479]
  PIN rw0_wd_in[480]
    DIRECTION INPUT ;
    USE SIGNAL ;
    SHAPE ABUTMENT ;
    PORT
      LAYER M3_m ;
      RECT 0 1142.435 0.07 1142.505 ;
    END
  END rw0_wd_in[480]
  PIN rw0_wd_in[481]
    DIRECTION INPUT ;
    USE SIGNAL ;
    SHAPE ABUTMENT ;
    PORT
      LAYER M3_m ;
      RECT 0 1144.535 0.07 1144.605 ;
    END
  END rw0_wd_in[481]
  PIN rw0_wd_in[482]
    DIRECTION INPUT ;
    USE SIGNAL ;
    SHAPE ABUTMENT ;
    PORT
      LAYER M3_m ;
      RECT 0 1146.635 0.07 1146.705 ;
    END
  END rw0_wd_in[482]
  PIN rw0_wd_in[483]
    DIRECTION INPUT ;
    USE SIGNAL ;
    SHAPE ABUTMENT ;
    PORT
      LAYER M3_m ;
      RECT 0 1148.735 0.07 1148.805 ;
    END
  END rw0_wd_in[483]
  PIN rw0_wd_in[484]
    DIRECTION INPUT ;
    USE SIGNAL ;
    SHAPE ABUTMENT ;
    PORT
      LAYER M3_m ;
      RECT 0 1150.835 0.07 1150.905 ;
    END
  END rw0_wd_in[484]
  PIN rw0_wd_in[485]
    DIRECTION INPUT ;
    USE SIGNAL ;
    SHAPE ABUTMENT ;
    PORT
      LAYER M3_m ;
      RECT 0 1152.935 0.07 1153.005 ;
    END
  END rw0_wd_in[485]
  PIN rw0_wd_in[486]
    DIRECTION INPUT ;
    USE SIGNAL ;
    SHAPE ABUTMENT ;
    PORT
      LAYER M3_m ;
      RECT 0 1155.035 0.07 1155.105 ;
    END
  END rw0_wd_in[486]
  PIN rw0_wd_in[487]
    DIRECTION INPUT ;
    USE SIGNAL ;
    SHAPE ABUTMENT ;
    PORT
      LAYER M3_m ;
      RECT 0 1157.135 0.07 1157.205 ;
    END
  END rw0_wd_in[487]
  PIN rw0_wd_in[488]
    DIRECTION INPUT ;
    USE SIGNAL ;
    SHAPE ABUTMENT ;
    PORT
      LAYER M3_m ;
      RECT 0 1159.235 0.07 1159.305 ;
    END
  END rw0_wd_in[488]
  PIN rw0_wd_in[489]
    DIRECTION INPUT ;
    USE SIGNAL ;
    SHAPE ABUTMENT ;
    PORT
      LAYER M3_m ;
      RECT 0 1161.335 0.07 1161.405 ;
    END
  END rw0_wd_in[489]
  PIN rw0_wd_in[490]
    DIRECTION INPUT ;
    USE SIGNAL ;
    SHAPE ABUTMENT ;
    PORT
      LAYER M3_m ;
      RECT 0 1163.435 0.07 1163.505 ;
    END
  END rw0_wd_in[490]
  PIN rw0_wd_in[491]
    DIRECTION INPUT ;
    USE SIGNAL ;
    SHAPE ABUTMENT ;
    PORT
      LAYER M3_m ;
      RECT 0 1165.535 0.07 1165.605 ;
    END
  END rw0_wd_in[491]
  PIN rw0_wd_in[492]
    DIRECTION INPUT ;
    USE SIGNAL ;
    SHAPE ABUTMENT ;
    PORT
      LAYER M3_m ;
      RECT 0 1167.635 0.07 1167.705 ;
    END
  END rw0_wd_in[492]
  PIN rw0_wd_in[493]
    DIRECTION INPUT ;
    USE SIGNAL ;
    SHAPE ABUTMENT ;
    PORT
      LAYER M3_m ;
      RECT 0 1169.735 0.07 1169.805 ;
    END
  END rw0_wd_in[493]
  PIN rw0_wd_in[494]
    DIRECTION INPUT ;
    USE SIGNAL ;
    SHAPE ABUTMENT ;
    PORT
      LAYER M3_m ;
      RECT 0 1171.835 0.07 1171.905 ;
    END
  END rw0_wd_in[494]
  PIN rw0_wd_in[495]
    DIRECTION INPUT ;
    USE SIGNAL ;
    SHAPE ABUTMENT ;
    PORT
      LAYER M3_m ;
      RECT 0 1173.935 0.07 1174.005 ;
    END
  END rw0_wd_in[495]
  PIN rw0_wd_in[496]
    DIRECTION INPUT ;
    USE SIGNAL ;
    SHAPE ABUTMENT ;
    PORT
      LAYER M3_m ;
      RECT 0 1176.035 0.07 1176.105 ;
    END
  END rw0_wd_in[496]
  PIN rw0_wd_in[497]
    DIRECTION INPUT ;
    USE SIGNAL ;
    SHAPE ABUTMENT ;
    PORT
      LAYER M3_m ;
      RECT 0 1178.135 0.07 1178.205 ;
    END
  END rw0_wd_in[497]
  PIN rw0_wd_in[498]
    DIRECTION INPUT ;
    USE SIGNAL ;
    SHAPE ABUTMENT ;
    PORT
      LAYER M3_m ;
      RECT 0 1180.235 0.07 1180.305 ;
    END
  END rw0_wd_in[498]
  PIN rw0_wd_in[499]
    DIRECTION INPUT ;
    USE SIGNAL ;
    SHAPE ABUTMENT ;
    PORT
      LAYER M3_m ;
      RECT 0 1182.335 0.07 1182.405 ;
    END
  END rw0_wd_in[499]
  PIN rw0_wd_in[500]
    DIRECTION INPUT ;
    USE SIGNAL ;
    SHAPE ABUTMENT ;
    PORT
      LAYER M3_m ;
      RECT 0 1184.435 0.07 1184.505 ;
    END
  END rw0_wd_in[500]
  PIN rw0_wd_in[501]
    DIRECTION INPUT ;
    USE SIGNAL ;
    SHAPE ABUTMENT ;
    PORT
      LAYER M3_m ;
      RECT 0 1186.535 0.07 1186.605 ;
    END
  END rw0_wd_in[501]
  PIN rw0_wd_in[502]
    DIRECTION INPUT ;
    USE SIGNAL ;
    SHAPE ABUTMENT ;
    PORT
      LAYER M3_m ;
      RECT 0 1188.635 0.07 1188.705 ;
    END
  END rw0_wd_in[502]
  PIN rw0_wd_in[503]
    DIRECTION INPUT ;
    USE SIGNAL ;
    SHAPE ABUTMENT ;
    PORT
      LAYER M3_m ;
      RECT 0 1190.735 0.07 1190.805 ;
    END
  END rw0_wd_in[503]
  PIN rw0_wd_in[504]
    DIRECTION INPUT ;
    USE SIGNAL ;
    SHAPE ABUTMENT ;
    PORT
      LAYER M3_m ;
      RECT 0 1192.835 0.07 1192.905 ;
    END
  END rw0_wd_in[504]
  PIN rw0_wd_in[505]
    DIRECTION INPUT ;
    USE SIGNAL ;
    SHAPE ABUTMENT ;
    PORT
      LAYER M3_m ;
      RECT 0 1194.935 0.07 1195.005 ;
    END
  END rw0_wd_in[505]
  PIN rw0_wd_in[506]
    DIRECTION INPUT ;
    USE SIGNAL ;
    SHAPE ABUTMENT ;
    PORT
      LAYER M3_m ;
      RECT 0 1197.035 0.07 1197.105 ;
    END
  END rw0_wd_in[506]
  PIN rw0_wd_in[507]
    DIRECTION INPUT ;
    USE SIGNAL ;
    SHAPE ABUTMENT ;
    PORT
      LAYER M3_m ;
      RECT 0 1199.135 0.07 1199.205 ;
    END
  END rw0_wd_in[507]
  PIN rw0_wd_in[508]
    DIRECTION INPUT ;
    USE SIGNAL ;
    SHAPE ABUTMENT ;
    PORT
      LAYER M3_m ;
      RECT 0 1201.235 0.07 1201.305 ;
    END
  END rw0_wd_in[508]
  PIN rw0_wd_in[509]
    DIRECTION INPUT ;
    USE SIGNAL ;
    SHAPE ABUTMENT ;
    PORT
      LAYER M3_m ;
      RECT 0 1203.335 0.07 1203.405 ;
    END
  END rw0_wd_in[509]
  PIN rw0_wd_in[510]
    DIRECTION INPUT ;
    USE SIGNAL ;
    SHAPE ABUTMENT ;
    PORT
      LAYER M3_m ;
      RECT 0 1205.435 0.07 1205.505 ;
    END
  END rw0_wd_in[510]
  PIN rw0_wd_in[511]
    DIRECTION INPUT ;
    USE SIGNAL ;
    SHAPE ABUTMENT ;
    PORT
      LAYER M3_m ;
      RECT 0 1207.535 0.07 1207.605 ;
    END
  END rw0_wd_in[511]
  PIN rw0_rd_out[0]
    DIRECTION OUTPUT ;
    USE SIGNAL ;
    SHAPE ABUTMENT ;
    PORT
      LAYER M3_m ;
      RECT 0 1209.635 0.07 1209.705 ;
    END
  END rw0_rd_out[0]
  PIN rw0_rd_out[1]
    DIRECTION OUTPUT ;
    USE SIGNAL ;
    SHAPE ABUTMENT ;
    PORT
      LAYER M3_m ;
      RECT 0 1211.735 0.07 1211.805 ;
    END
  END rw0_rd_out[1]
  PIN rw0_rd_out[2]
    DIRECTION OUTPUT ;
    USE SIGNAL ;
    SHAPE ABUTMENT ;
    PORT
      LAYER M3_m ;
      RECT 0 1213.835 0.07 1213.905 ;
    END
  END rw0_rd_out[2]
  PIN rw0_rd_out[3]
    DIRECTION OUTPUT ;
    USE SIGNAL ;
    SHAPE ABUTMENT ;
    PORT
      LAYER M3_m ;
      RECT 0 1215.935 0.07 1216.005 ;
    END
  END rw0_rd_out[3]
  PIN rw0_rd_out[4]
    DIRECTION OUTPUT ;
    USE SIGNAL ;
    SHAPE ABUTMENT ;
    PORT
      LAYER M3_m ;
      RECT 0 1218.035 0.07 1218.105 ;
    END
  END rw0_rd_out[4]
  PIN rw0_rd_out[5]
    DIRECTION OUTPUT ;
    USE SIGNAL ;
    SHAPE ABUTMENT ;
    PORT
      LAYER M3_m ;
      RECT 0 1220.135 0.07 1220.205 ;
    END
  END rw0_rd_out[5]
  PIN rw0_rd_out[6]
    DIRECTION OUTPUT ;
    USE SIGNAL ;
    SHAPE ABUTMENT ;
    PORT
      LAYER M3_m ;
      RECT 0 1222.235 0.07 1222.305 ;
    END
  END rw0_rd_out[6]
  PIN rw0_rd_out[7]
    DIRECTION OUTPUT ;
    USE SIGNAL ;
    SHAPE ABUTMENT ;
    PORT
      LAYER M3_m ;
      RECT 0 1224.335 0.07 1224.405 ;
    END
  END rw0_rd_out[7]
  PIN rw0_rd_out[8]
    DIRECTION OUTPUT ;
    USE SIGNAL ;
    SHAPE ABUTMENT ;
    PORT
      LAYER M3_m ;
      RECT 0 1226.435 0.07 1226.505 ;
    END
  END rw0_rd_out[8]
  PIN rw0_rd_out[9]
    DIRECTION OUTPUT ;
    USE SIGNAL ;
    SHAPE ABUTMENT ;
    PORT
      LAYER M3_m ;
      RECT 0 1228.535 0.07 1228.605 ;
    END
  END rw0_rd_out[9]
  PIN rw0_rd_out[10]
    DIRECTION OUTPUT ;
    USE SIGNAL ;
    SHAPE ABUTMENT ;
    PORT
      LAYER M3_m ;
      RECT 0 1230.635 0.07 1230.705 ;
    END
  END rw0_rd_out[10]
  PIN rw0_rd_out[11]
    DIRECTION OUTPUT ;
    USE SIGNAL ;
    SHAPE ABUTMENT ;
    PORT
      LAYER M3_m ;
      RECT 0 1232.735 0.07 1232.805 ;
    END
  END rw0_rd_out[11]
  PIN rw0_rd_out[12]
    DIRECTION OUTPUT ;
    USE SIGNAL ;
    SHAPE ABUTMENT ;
    PORT
      LAYER M3_m ;
      RECT 0 1234.835 0.07 1234.905 ;
    END
  END rw0_rd_out[12]
  PIN rw0_rd_out[13]
    DIRECTION OUTPUT ;
    USE SIGNAL ;
    SHAPE ABUTMENT ;
    PORT
      LAYER M3_m ;
      RECT 0 1236.935 0.07 1237.005 ;
    END
  END rw0_rd_out[13]
  PIN rw0_rd_out[14]
    DIRECTION OUTPUT ;
    USE SIGNAL ;
    SHAPE ABUTMENT ;
    PORT
      LAYER M3_m ;
      RECT 0 1239.035 0.07 1239.105 ;
    END
  END rw0_rd_out[14]
  PIN rw0_rd_out[15]
    DIRECTION OUTPUT ;
    USE SIGNAL ;
    SHAPE ABUTMENT ;
    PORT
      LAYER M3_m ;
      RECT 0 1241.135 0.07 1241.205 ;
    END
  END rw0_rd_out[15]
  PIN rw0_rd_out[16]
    DIRECTION OUTPUT ;
    USE SIGNAL ;
    SHAPE ABUTMENT ;
    PORT
      LAYER M3_m ;
      RECT 0 1243.235 0.07 1243.305 ;
    END
  END rw0_rd_out[16]
  PIN rw0_rd_out[17]
    DIRECTION OUTPUT ;
    USE SIGNAL ;
    SHAPE ABUTMENT ;
    PORT
      LAYER M3_m ;
      RECT 0 1245.335 0.07 1245.405 ;
    END
  END rw0_rd_out[17]
  PIN rw0_rd_out[18]
    DIRECTION OUTPUT ;
    USE SIGNAL ;
    SHAPE ABUTMENT ;
    PORT
      LAYER M3_m ;
      RECT 0 1247.435 0.07 1247.505 ;
    END
  END rw0_rd_out[18]
  PIN rw0_rd_out[19]
    DIRECTION OUTPUT ;
    USE SIGNAL ;
    SHAPE ABUTMENT ;
    PORT
      LAYER M3_m ;
      RECT 0 1249.535 0.07 1249.605 ;
    END
  END rw0_rd_out[19]
  PIN rw0_rd_out[20]
    DIRECTION OUTPUT ;
    USE SIGNAL ;
    SHAPE ABUTMENT ;
    PORT
      LAYER M3_m ;
      RECT 0 1251.635 0.07 1251.705 ;
    END
  END rw0_rd_out[20]
  PIN rw0_rd_out[21]
    DIRECTION OUTPUT ;
    USE SIGNAL ;
    SHAPE ABUTMENT ;
    PORT
      LAYER M3_m ;
      RECT 0 1253.735 0.07 1253.805 ;
    END
  END rw0_rd_out[21]
  PIN rw0_rd_out[22]
    DIRECTION OUTPUT ;
    USE SIGNAL ;
    SHAPE ABUTMENT ;
    PORT
      LAYER M3_m ;
      RECT 0 1255.835 0.07 1255.905 ;
    END
  END rw0_rd_out[22]
  PIN rw0_rd_out[23]
    DIRECTION OUTPUT ;
    USE SIGNAL ;
    SHAPE ABUTMENT ;
    PORT
      LAYER M3_m ;
      RECT 0 1257.935 0.07 1258.005 ;
    END
  END rw0_rd_out[23]
  PIN rw0_rd_out[24]
    DIRECTION OUTPUT ;
    USE SIGNAL ;
    SHAPE ABUTMENT ;
    PORT
      LAYER M3_m ;
      RECT 0 1260.035 0.07 1260.105 ;
    END
  END rw0_rd_out[24]
  PIN rw0_rd_out[25]
    DIRECTION OUTPUT ;
    USE SIGNAL ;
    SHAPE ABUTMENT ;
    PORT
      LAYER M3_m ;
      RECT 0 1262.135 0.07 1262.205 ;
    END
  END rw0_rd_out[25]
  PIN rw0_rd_out[26]
    DIRECTION OUTPUT ;
    USE SIGNAL ;
    SHAPE ABUTMENT ;
    PORT
      LAYER M3_m ;
      RECT 0 1264.235 0.07 1264.305 ;
    END
  END rw0_rd_out[26]
  PIN rw0_rd_out[27]
    DIRECTION OUTPUT ;
    USE SIGNAL ;
    SHAPE ABUTMENT ;
    PORT
      LAYER M3_m ;
      RECT 0 1266.335 0.07 1266.405 ;
    END
  END rw0_rd_out[27]
  PIN rw0_rd_out[28]
    DIRECTION OUTPUT ;
    USE SIGNAL ;
    SHAPE ABUTMENT ;
    PORT
      LAYER M3_m ;
      RECT 0 1268.435 0.07 1268.505 ;
    END
  END rw0_rd_out[28]
  PIN rw0_rd_out[29]
    DIRECTION OUTPUT ;
    USE SIGNAL ;
    SHAPE ABUTMENT ;
    PORT
      LAYER M3_m ;
      RECT 0 1270.535 0.07 1270.605 ;
    END
  END rw0_rd_out[29]
  PIN rw0_rd_out[30]
    DIRECTION OUTPUT ;
    USE SIGNAL ;
    SHAPE ABUTMENT ;
    PORT
      LAYER M3_m ;
      RECT 0 1272.635 0.07 1272.705 ;
    END
  END rw0_rd_out[30]
  PIN rw0_rd_out[31]
    DIRECTION OUTPUT ;
    USE SIGNAL ;
    SHAPE ABUTMENT ;
    PORT
      LAYER M3_m ;
      RECT 0 1274.735 0.07 1274.805 ;
    END
  END rw0_rd_out[31]
  PIN rw0_rd_out[32]
    DIRECTION OUTPUT ;
    USE SIGNAL ;
    SHAPE ABUTMENT ;
    PORT
      LAYER M3_m ;
      RECT 0 1276.835 0.07 1276.905 ;
    END
  END rw0_rd_out[32]
  PIN rw0_rd_out[33]
    DIRECTION OUTPUT ;
    USE SIGNAL ;
    SHAPE ABUTMENT ;
    PORT
      LAYER M3_m ;
      RECT 0 1278.935 0.07 1279.005 ;
    END
  END rw0_rd_out[33]
  PIN rw0_rd_out[34]
    DIRECTION OUTPUT ;
    USE SIGNAL ;
    SHAPE ABUTMENT ;
    PORT
      LAYER M3_m ;
      RECT 0 1281.035 0.07 1281.105 ;
    END
  END rw0_rd_out[34]
  PIN rw0_rd_out[35]
    DIRECTION OUTPUT ;
    USE SIGNAL ;
    SHAPE ABUTMENT ;
    PORT
      LAYER M3_m ;
      RECT 0 1283.135 0.07 1283.205 ;
    END
  END rw0_rd_out[35]
  PIN rw0_rd_out[36]
    DIRECTION OUTPUT ;
    USE SIGNAL ;
    SHAPE ABUTMENT ;
    PORT
      LAYER M3_m ;
      RECT 0 1285.235 0.07 1285.305 ;
    END
  END rw0_rd_out[36]
  PIN rw0_rd_out[37]
    DIRECTION OUTPUT ;
    USE SIGNAL ;
    SHAPE ABUTMENT ;
    PORT
      LAYER M3_m ;
      RECT 0 1287.335 0.07 1287.405 ;
    END
  END rw0_rd_out[37]
  PIN rw0_rd_out[38]
    DIRECTION OUTPUT ;
    USE SIGNAL ;
    SHAPE ABUTMENT ;
    PORT
      LAYER M3_m ;
      RECT 0 1289.435 0.07 1289.505 ;
    END
  END rw0_rd_out[38]
  PIN rw0_rd_out[39]
    DIRECTION OUTPUT ;
    USE SIGNAL ;
    SHAPE ABUTMENT ;
    PORT
      LAYER M3_m ;
      RECT 0 1291.535 0.07 1291.605 ;
    END
  END rw0_rd_out[39]
  PIN rw0_rd_out[40]
    DIRECTION OUTPUT ;
    USE SIGNAL ;
    SHAPE ABUTMENT ;
    PORT
      LAYER M3_m ;
      RECT 0 1293.635 0.07 1293.705 ;
    END
  END rw0_rd_out[40]
  PIN rw0_rd_out[41]
    DIRECTION OUTPUT ;
    USE SIGNAL ;
    SHAPE ABUTMENT ;
    PORT
      LAYER M3_m ;
      RECT 0 1295.735 0.07 1295.805 ;
    END
  END rw0_rd_out[41]
  PIN rw0_rd_out[42]
    DIRECTION OUTPUT ;
    USE SIGNAL ;
    SHAPE ABUTMENT ;
    PORT
      LAYER M3_m ;
      RECT 0 1297.835 0.07 1297.905 ;
    END
  END rw0_rd_out[42]
  PIN rw0_rd_out[43]
    DIRECTION OUTPUT ;
    USE SIGNAL ;
    SHAPE ABUTMENT ;
    PORT
      LAYER M3_m ;
      RECT 0 1299.935 0.07 1300.005 ;
    END
  END rw0_rd_out[43]
  PIN rw0_rd_out[44]
    DIRECTION OUTPUT ;
    USE SIGNAL ;
    SHAPE ABUTMENT ;
    PORT
      LAYER M3_m ;
      RECT 0 1302.035 0.07 1302.105 ;
    END
  END rw0_rd_out[44]
  PIN rw0_rd_out[45]
    DIRECTION OUTPUT ;
    USE SIGNAL ;
    SHAPE ABUTMENT ;
    PORT
      LAYER M3_m ;
      RECT 0 1304.135 0.07 1304.205 ;
    END
  END rw0_rd_out[45]
  PIN rw0_rd_out[46]
    DIRECTION OUTPUT ;
    USE SIGNAL ;
    SHAPE ABUTMENT ;
    PORT
      LAYER M3_m ;
      RECT 0 1306.235 0.07 1306.305 ;
    END
  END rw0_rd_out[46]
  PIN rw0_rd_out[47]
    DIRECTION OUTPUT ;
    USE SIGNAL ;
    SHAPE ABUTMENT ;
    PORT
      LAYER M3_m ;
      RECT 0 1308.335 0.07 1308.405 ;
    END
  END rw0_rd_out[47]
  PIN rw0_rd_out[48]
    DIRECTION OUTPUT ;
    USE SIGNAL ;
    SHAPE ABUTMENT ;
    PORT
      LAYER M3_m ;
      RECT 0 1310.435 0.07 1310.505 ;
    END
  END rw0_rd_out[48]
  PIN rw0_rd_out[49]
    DIRECTION OUTPUT ;
    USE SIGNAL ;
    SHAPE ABUTMENT ;
    PORT
      LAYER M3_m ;
      RECT 0 1312.535 0.07 1312.605 ;
    END
  END rw0_rd_out[49]
  PIN rw0_rd_out[50]
    DIRECTION OUTPUT ;
    USE SIGNAL ;
    SHAPE ABUTMENT ;
    PORT
      LAYER M3_m ;
      RECT 0 1314.635 0.07 1314.705 ;
    END
  END rw0_rd_out[50]
  PIN rw0_rd_out[51]
    DIRECTION OUTPUT ;
    USE SIGNAL ;
    SHAPE ABUTMENT ;
    PORT
      LAYER M3_m ;
      RECT 0 1316.735 0.07 1316.805 ;
    END
  END rw0_rd_out[51]
  PIN rw0_rd_out[52]
    DIRECTION OUTPUT ;
    USE SIGNAL ;
    SHAPE ABUTMENT ;
    PORT
      LAYER M3_m ;
      RECT 0 1318.835 0.07 1318.905 ;
    END
  END rw0_rd_out[52]
  PIN rw0_rd_out[53]
    DIRECTION OUTPUT ;
    USE SIGNAL ;
    SHAPE ABUTMENT ;
    PORT
      LAYER M3_m ;
      RECT 0 1320.935 0.07 1321.005 ;
    END
  END rw0_rd_out[53]
  PIN rw0_rd_out[54]
    DIRECTION OUTPUT ;
    USE SIGNAL ;
    SHAPE ABUTMENT ;
    PORT
      LAYER M3_m ;
      RECT 0 1323.035 0.07 1323.105 ;
    END
  END rw0_rd_out[54]
  PIN rw0_rd_out[55]
    DIRECTION OUTPUT ;
    USE SIGNAL ;
    SHAPE ABUTMENT ;
    PORT
      LAYER M3_m ;
      RECT 0 1325.135 0.07 1325.205 ;
    END
  END rw0_rd_out[55]
  PIN rw0_rd_out[56]
    DIRECTION OUTPUT ;
    USE SIGNAL ;
    SHAPE ABUTMENT ;
    PORT
      LAYER M3_m ;
      RECT 0 1327.235 0.07 1327.305 ;
    END
  END rw0_rd_out[56]
  PIN rw0_rd_out[57]
    DIRECTION OUTPUT ;
    USE SIGNAL ;
    SHAPE ABUTMENT ;
    PORT
      LAYER M3_m ;
      RECT 0 1329.335 0.07 1329.405 ;
    END
  END rw0_rd_out[57]
  PIN rw0_rd_out[58]
    DIRECTION OUTPUT ;
    USE SIGNAL ;
    SHAPE ABUTMENT ;
    PORT
      LAYER M3_m ;
      RECT 0 1331.435 0.07 1331.505 ;
    END
  END rw0_rd_out[58]
  PIN rw0_rd_out[59]
    DIRECTION OUTPUT ;
    USE SIGNAL ;
    SHAPE ABUTMENT ;
    PORT
      LAYER M3_m ;
      RECT 0 1333.535 0.07 1333.605 ;
    END
  END rw0_rd_out[59]
  PIN rw0_rd_out[60]
    DIRECTION OUTPUT ;
    USE SIGNAL ;
    SHAPE ABUTMENT ;
    PORT
      LAYER M3_m ;
      RECT 0 1335.635 0.07 1335.705 ;
    END
  END rw0_rd_out[60]
  PIN rw0_rd_out[61]
    DIRECTION OUTPUT ;
    USE SIGNAL ;
    SHAPE ABUTMENT ;
    PORT
      LAYER M3_m ;
      RECT 0 1337.735 0.07 1337.805 ;
    END
  END rw0_rd_out[61]
  PIN rw0_rd_out[62]
    DIRECTION OUTPUT ;
    USE SIGNAL ;
    SHAPE ABUTMENT ;
    PORT
      LAYER M3_m ;
      RECT 0 1339.835 0.07 1339.905 ;
    END
  END rw0_rd_out[62]
  PIN rw0_rd_out[63]
    DIRECTION OUTPUT ;
    USE SIGNAL ;
    SHAPE ABUTMENT ;
    PORT
      LAYER M3_m ;
      RECT 0 1341.935 0.07 1342.005 ;
    END
  END rw0_rd_out[63]
  PIN rw0_rd_out[64]
    DIRECTION OUTPUT ;
    USE SIGNAL ;
    SHAPE ABUTMENT ;
    PORT
      LAYER M3_m ;
      RECT 0 1344.035 0.07 1344.105 ;
    END
  END rw0_rd_out[64]
  PIN rw0_rd_out[65]
    DIRECTION OUTPUT ;
    USE SIGNAL ;
    SHAPE ABUTMENT ;
    PORT
      LAYER M3_m ;
      RECT 0 1346.135 0.07 1346.205 ;
    END
  END rw0_rd_out[65]
  PIN rw0_rd_out[66]
    DIRECTION OUTPUT ;
    USE SIGNAL ;
    SHAPE ABUTMENT ;
    PORT
      LAYER M3_m ;
      RECT 0 1348.235 0.07 1348.305 ;
    END
  END rw0_rd_out[66]
  PIN rw0_rd_out[67]
    DIRECTION OUTPUT ;
    USE SIGNAL ;
    SHAPE ABUTMENT ;
    PORT
      LAYER M3_m ;
      RECT 0 1350.335 0.07 1350.405 ;
    END
  END rw0_rd_out[67]
  PIN rw0_rd_out[68]
    DIRECTION OUTPUT ;
    USE SIGNAL ;
    SHAPE ABUTMENT ;
    PORT
      LAYER M3_m ;
      RECT 0 1352.435 0.07 1352.505 ;
    END
  END rw0_rd_out[68]
  PIN rw0_rd_out[69]
    DIRECTION OUTPUT ;
    USE SIGNAL ;
    SHAPE ABUTMENT ;
    PORT
      LAYER M3_m ;
      RECT 0 1354.535 0.07 1354.605 ;
    END
  END rw0_rd_out[69]
  PIN rw0_rd_out[70]
    DIRECTION OUTPUT ;
    USE SIGNAL ;
    SHAPE ABUTMENT ;
    PORT
      LAYER M3_m ;
      RECT 0 1356.635 0.07 1356.705 ;
    END
  END rw0_rd_out[70]
  PIN rw0_rd_out[71]
    DIRECTION OUTPUT ;
    USE SIGNAL ;
    SHAPE ABUTMENT ;
    PORT
      LAYER M3_m ;
      RECT 0 1358.735 0.07 1358.805 ;
    END
  END rw0_rd_out[71]
  PIN rw0_rd_out[72]
    DIRECTION OUTPUT ;
    USE SIGNAL ;
    SHAPE ABUTMENT ;
    PORT
      LAYER M3_m ;
      RECT 0 1360.835 0.07 1360.905 ;
    END
  END rw0_rd_out[72]
  PIN rw0_rd_out[73]
    DIRECTION OUTPUT ;
    USE SIGNAL ;
    SHAPE ABUTMENT ;
    PORT
      LAYER M3_m ;
      RECT 0 1362.935 0.07 1363.005 ;
    END
  END rw0_rd_out[73]
  PIN rw0_rd_out[74]
    DIRECTION OUTPUT ;
    USE SIGNAL ;
    SHAPE ABUTMENT ;
    PORT
      LAYER M3_m ;
      RECT 0 1365.035 0.07 1365.105 ;
    END
  END rw0_rd_out[74]
  PIN rw0_rd_out[75]
    DIRECTION OUTPUT ;
    USE SIGNAL ;
    SHAPE ABUTMENT ;
    PORT
      LAYER M3_m ;
      RECT 0 1367.135 0.07 1367.205 ;
    END
  END rw0_rd_out[75]
  PIN rw0_rd_out[76]
    DIRECTION OUTPUT ;
    USE SIGNAL ;
    SHAPE ABUTMENT ;
    PORT
      LAYER M3_m ;
      RECT 0 1369.235 0.07 1369.305 ;
    END
  END rw0_rd_out[76]
  PIN rw0_rd_out[77]
    DIRECTION OUTPUT ;
    USE SIGNAL ;
    SHAPE ABUTMENT ;
    PORT
      LAYER M3_m ;
      RECT 0 1371.335 0.07 1371.405 ;
    END
  END rw0_rd_out[77]
  PIN rw0_rd_out[78]
    DIRECTION OUTPUT ;
    USE SIGNAL ;
    SHAPE ABUTMENT ;
    PORT
      LAYER M3_m ;
      RECT 0 1373.435 0.07 1373.505 ;
    END
  END rw0_rd_out[78]
  PIN rw0_rd_out[79]
    DIRECTION OUTPUT ;
    USE SIGNAL ;
    SHAPE ABUTMENT ;
    PORT
      LAYER M3_m ;
      RECT 0 1375.535 0.07 1375.605 ;
    END
  END rw0_rd_out[79]
  PIN rw0_rd_out[80]
    DIRECTION OUTPUT ;
    USE SIGNAL ;
    SHAPE ABUTMENT ;
    PORT
      LAYER M3_m ;
      RECT 0 1377.635 0.07 1377.705 ;
    END
  END rw0_rd_out[80]
  PIN rw0_rd_out[81]
    DIRECTION OUTPUT ;
    USE SIGNAL ;
    SHAPE ABUTMENT ;
    PORT
      LAYER M3_m ;
      RECT 0 1379.735 0.07 1379.805 ;
    END
  END rw0_rd_out[81]
  PIN rw0_rd_out[82]
    DIRECTION OUTPUT ;
    USE SIGNAL ;
    SHAPE ABUTMENT ;
    PORT
      LAYER M3_m ;
      RECT 0 1381.835 0.07 1381.905 ;
    END
  END rw0_rd_out[82]
  PIN rw0_rd_out[83]
    DIRECTION OUTPUT ;
    USE SIGNAL ;
    SHAPE ABUTMENT ;
    PORT
      LAYER M3_m ;
      RECT 0 1383.935 0.07 1384.005 ;
    END
  END rw0_rd_out[83]
  PIN rw0_rd_out[84]
    DIRECTION OUTPUT ;
    USE SIGNAL ;
    SHAPE ABUTMENT ;
    PORT
      LAYER M3_m ;
      RECT 0 1386.035 0.07 1386.105 ;
    END
  END rw0_rd_out[84]
  PIN rw0_rd_out[85]
    DIRECTION OUTPUT ;
    USE SIGNAL ;
    SHAPE ABUTMENT ;
    PORT
      LAYER M3_m ;
      RECT 0 1388.135 0.07 1388.205 ;
    END
  END rw0_rd_out[85]
  PIN rw0_rd_out[86]
    DIRECTION OUTPUT ;
    USE SIGNAL ;
    SHAPE ABUTMENT ;
    PORT
      LAYER M3_m ;
      RECT 0 1390.235 0.07 1390.305 ;
    END
  END rw0_rd_out[86]
  PIN rw0_rd_out[87]
    DIRECTION OUTPUT ;
    USE SIGNAL ;
    SHAPE ABUTMENT ;
    PORT
      LAYER M3_m ;
      RECT 0 1392.335 0.07 1392.405 ;
    END
  END rw0_rd_out[87]
  PIN rw0_rd_out[88]
    DIRECTION OUTPUT ;
    USE SIGNAL ;
    SHAPE ABUTMENT ;
    PORT
      LAYER M3_m ;
      RECT 0 1394.435 0.07 1394.505 ;
    END
  END rw0_rd_out[88]
  PIN rw0_rd_out[89]
    DIRECTION OUTPUT ;
    USE SIGNAL ;
    SHAPE ABUTMENT ;
    PORT
      LAYER M3_m ;
      RECT 0 1396.535 0.07 1396.605 ;
    END
  END rw0_rd_out[89]
  PIN rw0_rd_out[90]
    DIRECTION OUTPUT ;
    USE SIGNAL ;
    SHAPE ABUTMENT ;
    PORT
      LAYER M3_m ;
      RECT 0 1398.635 0.07 1398.705 ;
    END
  END rw0_rd_out[90]
  PIN rw0_rd_out[91]
    DIRECTION OUTPUT ;
    USE SIGNAL ;
    SHAPE ABUTMENT ;
    PORT
      LAYER M3_m ;
      RECT 0 1400.735 0.07 1400.805 ;
    END
  END rw0_rd_out[91]
  PIN rw0_rd_out[92]
    DIRECTION OUTPUT ;
    USE SIGNAL ;
    SHAPE ABUTMENT ;
    PORT
      LAYER M3_m ;
      RECT 0 1402.835 0.07 1402.905 ;
    END
  END rw0_rd_out[92]
  PIN rw0_rd_out[93]
    DIRECTION OUTPUT ;
    USE SIGNAL ;
    SHAPE ABUTMENT ;
    PORT
      LAYER M3_m ;
      RECT 0 1404.935 0.07 1405.005 ;
    END
  END rw0_rd_out[93]
  PIN rw0_rd_out[94]
    DIRECTION OUTPUT ;
    USE SIGNAL ;
    SHAPE ABUTMENT ;
    PORT
      LAYER M3_m ;
      RECT 0 1407.035 0.07 1407.105 ;
    END
  END rw0_rd_out[94]
  PIN rw0_rd_out[95]
    DIRECTION OUTPUT ;
    USE SIGNAL ;
    SHAPE ABUTMENT ;
    PORT
      LAYER M3_m ;
      RECT 0 1409.135 0.07 1409.205 ;
    END
  END rw0_rd_out[95]
  PIN rw0_rd_out[96]
    DIRECTION OUTPUT ;
    USE SIGNAL ;
    SHAPE ABUTMENT ;
    PORT
      LAYER M3_m ;
      RECT 0 1411.235 0.07 1411.305 ;
    END
  END rw0_rd_out[96]
  PIN rw0_rd_out[97]
    DIRECTION OUTPUT ;
    USE SIGNAL ;
    SHAPE ABUTMENT ;
    PORT
      LAYER M3_m ;
      RECT 0 1413.335 0.07 1413.405 ;
    END
  END rw0_rd_out[97]
  PIN rw0_rd_out[98]
    DIRECTION OUTPUT ;
    USE SIGNAL ;
    SHAPE ABUTMENT ;
    PORT
      LAYER M3_m ;
      RECT 0 1415.435 0.07 1415.505 ;
    END
  END rw0_rd_out[98]
  PIN rw0_rd_out[99]
    DIRECTION OUTPUT ;
    USE SIGNAL ;
    SHAPE ABUTMENT ;
    PORT
      LAYER M3_m ;
      RECT 0 1417.535 0.07 1417.605 ;
    END
  END rw0_rd_out[99]
  PIN rw0_rd_out[100]
    DIRECTION OUTPUT ;
    USE SIGNAL ;
    SHAPE ABUTMENT ;
    PORT
      LAYER M3_m ;
      RECT 0 1419.635 0.07 1419.705 ;
    END
  END rw0_rd_out[100]
  PIN rw0_rd_out[101]
    DIRECTION OUTPUT ;
    USE SIGNAL ;
    SHAPE ABUTMENT ;
    PORT
      LAYER M3_m ;
      RECT 0 1421.735 0.07 1421.805 ;
    END
  END rw0_rd_out[101]
  PIN rw0_rd_out[102]
    DIRECTION OUTPUT ;
    USE SIGNAL ;
    SHAPE ABUTMENT ;
    PORT
      LAYER M3_m ;
      RECT 0 1423.835 0.07 1423.905 ;
    END
  END rw0_rd_out[102]
  PIN rw0_rd_out[103]
    DIRECTION OUTPUT ;
    USE SIGNAL ;
    SHAPE ABUTMENT ;
    PORT
      LAYER M3_m ;
      RECT 0 1425.935 0.07 1426.005 ;
    END
  END rw0_rd_out[103]
  PIN rw0_rd_out[104]
    DIRECTION OUTPUT ;
    USE SIGNAL ;
    SHAPE ABUTMENT ;
    PORT
      LAYER M3_m ;
      RECT 0 1428.035 0.07 1428.105 ;
    END
  END rw0_rd_out[104]
  PIN rw0_rd_out[105]
    DIRECTION OUTPUT ;
    USE SIGNAL ;
    SHAPE ABUTMENT ;
    PORT
      LAYER M3_m ;
      RECT 0 1430.135 0.07 1430.205 ;
    END
  END rw0_rd_out[105]
  PIN rw0_rd_out[106]
    DIRECTION OUTPUT ;
    USE SIGNAL ;
    SHAPE ABUTMENT ;
    PORT
      LAYER M3_m ;
      RECT 0 1432.235 0.07 1432.305 ;
    END
  END rw0_rd_out[106]
  PIN rw0_rd_out[107]
    DIRECTION OUTPUT ;
    USE SIGNAL ;
    SHAPE ABUTMENT ;
    PORT
      LAYER M3_m ;
      RECT 0 1434.335 0.07 1434.405 ;
    END
  END rw0_rd_out[107]
  PIN rw0_rd_out[108]
    DIRECTION OUTPUT ;
    USE SIGNAL ;
    SHAPE ABUTMENT ;
    PORT
      LAYER M3_m ;
      RECT 0 1436.435 0.07 1436.505 ;
    END
  END rw0_rd_out[108]
  PIN rw0_rd_out[109]
    DIRECTION OUTPUT ;
    USE SIGNAL ;
    SHAPE ABUTMENT ;
    PORT
      LAYER M3_m ;
      RECT 0 1438.535 0.07 1438.605 ;
    END
  END rw0_rd_out[109]
  PIN rw0_rd_out[110]
    DIRECTION OUTPUT ;
    USE SIGNAL ;
    SHAPE ABUTMENT ;
    PORT
      LAYER M3_m ;
      RECT 0 1440.635 0.07 1440.705 ;
    END
  END rw0_rd_out[110]
  PIN rw0_rd_out[111]
    DIRECTION OUTPUT ;
    USE SIGNAL ;
    SHAPE ABUTMENT ;
    PORT
      LAYER M3_m ;
      RECT 0 1442.735 0.07 1442.805 ;
    END
  END rw0_rd_out[111]
  PIN rw0_rd_out[112]
    DIRECTION OUTPUT ;
    USE SIGNAL ;
    SHAPE ABUTMENT ;
    PORT
      LAYER M3_m ;
      RECT 0 1444.835 0.07 1444.905 ;
    END
  END rw0_rd_out[112]
  PIN rw0_rd_out[113]
    DIRECTION OUTPUT ;
    USE SIGNAL ;
    SHAPE ABUTMENT ;
    PORT
      LAYER M3_m ;
      RECT 0 1446.935 0.07 1447.005 ;
    END
  END rw0_rd_out[113]
  PIN rw0_rd_out[114]
    DIRECTION OUTPUT ;
    USE SIGNAL ;
    SHAPE ABUTMENT ;
    PORT
      LAYER M3_m ;
      RECT 0 1449.035 0.07 1449.105 ;
    END
  END rw0_rd_out[114]
  PIN rw0_rd_out[115]
    DIRECTION OUTPUT ;
    USE SIGNAL ;
    SHAPE ABUTMENT ;
    PORT
      LAYER M3_m ;
      RECT 0 1451.135 0.07 1451.205 ;
    END
  END rw0_rd_out[115]
  PIN rw0_rd_out[116]
    DIRECTION OUTPUT ;
    USE SIGNAL ;
    SHAPE ABUTMENT ;
    PORT
      LAYER M3_m ;
      RECT 0 1453.235 0.07 1453.305 ;
    END
  END rw0_rd_out[116]
  PIN rw0_rd_out[117]
    DIRECTION OUTPUT ;
    USE SIGNAL ;
    SHAPE ABUTMENT ;
    PORT
      LAYER M3_m ;
      RECT 0 1455.335 0.07 1455.405 ;
    END
  END rw0_rd_out[117]
  PIN rw0_rd_out[118]
    DIRECTION OUTPUT ;
    USE SIGNAL ;
    SHAPE ABUTMENT ;
    PORT
      LAYER M3_m ;
      RECT 0 1457.435 0.07 1457.505 ;
    END
  END rw0_rd_out[118]
  PIN rw0_rd_out[119]
    DIRECTION OUTPUT ;
    USE SIGNAL ;
    SHAPE ABUTMENT ;
    PORT
      LAYER M3_m ;
      RECT 0 1459.535 0.07 1459.605 ;
    END
  END rw0_rd_out[119]
  PIN rw0_rd_out[120]
    DIRECTION OUTPUT ;
    USE SIGNAL ;
    SHAPE ABUTMENT ;
    PORT
      LAYER M3_m ;
      RECT 0 1461.635 0.07 1461.705 ;
    END
  END rw0_rd_out[120]
  PIN rw0_rd_out[121]
    DIRECTION OUTPUT ;
    USE SIGNAL ;
    SHAPE ABUTMENT ;
    PORT
      LAYER M3_m ;
      RECT 0 1463.735 0.07 1463.805 ;
    END
  END rw0_rd_out[121]
  PIN rw0_rd_out[122]
    DIRECTION OUTPUT ;
    USE SIGNAL ;
    SHAPE ABUTMENT ;
    PORT
      LAYER M3_m ;
      RECT 0 1465.835 0.07 1465.905 ;
    END
  END rw0_rd_out[122]
  PIN rw0_rd_out[123]
    DIRECTION OUTPUT ;
    USE SIGNAL ;
    SHAPE ABUTMENT ;
    PORT
      LAYER M3_m ;
      RECT 0 1467.935 0.07 1468.005 ;
    END
  END rw0_rd_out[123]
  PIN rw0_rd_out[124]
    DIRECTION OUTPUT ;
    USE SIGNAL ;
    SHAPE ABUTMENT ;
    PORT
      LAYER M3_m ;
      RECT 0 1470.035 0.07 1470.105 ;
    END
  END rw0_rd_out[124]
  PIN rw0_rd_out[125]
    DIRECTION OUTPUT ;
    USE SIGNAL ;
    SHAPE ABUTMENT ;
    PORT
      LAYER M3_m ;
      RECT 0 1472.135 0.07 1472.205 ;
    END
  END rw0_rd_out[125]
  PIN rw0_rd_out[126]
    DIRECTION OUTPUT ;
    USE SIGNAL ;
    SHAPE ABUTMENT ;
    PORT
      LAYER M3_m ;
      RECT 0 1474.235 0.07 1474.305 ;
    END
  END rw0_rd_out[126]
  PIN rw0_rd_out[127]
    DIRECTION OUTPUT ;
    USE SIGNAL ;
    SHAPE ABUTMENT ;
    PORT
      LAYER M3_m ;
      RECT 0 1476.335 0.07 1476.405 ;
    END
  END rw0_rd_out[127]
  PIN rw0_rd_out[128]
    DIRECTION OUTPUT ;
    USE SIGNAL ;
    SHAPE ABUTMENT ;
    PORT
      LAYER M3_m ;
      RECT 0 1478.435 0.07 1478.505 ;
    END
  END rw0_rd_out[128]
  PIN rw0_rd_out[129]
    DIRECTION OUTPUT ;
    USE SIGNAL ;
    SHAPE ABUTMENT ;
    PORT
      LAYER M3_m ;
      RECT 0 1480.535 0.07 1480.605 ;
    END
  END rw0_rd_out[129]
  PIN rw0_rd_out[130]
    DIRECTION OUTPUT ;
    USE SIGNAL ;
    SHAPE ABUTMENT ;
    PORT
      LAYER M3_m ;
      RECT 0 1482.635 0.07 1482.705 ;
    END
  END rw0_rd_out[130]
  PIN rw0_rd_out[131]
    DIRECTION OUTPUT ;
    USE SIGNAL ;
    SHAPE ABUTMENT ;
    PORT
      LAYER M3_m ;
      RECT 0 1484.735 0.07 1484.805 ;
    END
  END rw0_rd_out[131]
  PIN rw0_rd_out[132]
    DIRECTION OUTPUT ;
    USE SIGNAL ;
    SHAPE ABUTMENT ;
    PORT
      LAYER M3_m ;
      RECT 0 1486.835 0.07 1486.905 ;
    END
  END rw0_rd_out[132]
  PIN rw0_rd_out[133]
    DIRECTION OUTPUT ;
    USE SIGNAL ;
    SHAPE ABUTMENT ;
    PORT
      LAYER M3_m ;
      RECT 0 1488.935 0.07 1489.005 ;
    END
  END rw0_rd_out[133]
  PIN rw0_rd_out[134]
    DIRECTION OUTPUT ;
    USE SIGNAL ;
    SHAPE ABUTMENT ;
    PORT
      LAYER M3_m ;
      RECT 0 1491.035 0.07 1491.105 ;
    END
  END rw0_rd_out[134]
  PIN rw0_rd_out[135]
    DIRECTION OUTPUT ;
    USE SIGNAL ;
    SHAPE ABUTMENT ;
    PORT
      LAYER M3_m ;
      RECT 0 1493.135 0.07 1493.205 ;
    END
  END rw0_rd_out[135]
  PIN rw0_rd_out[136]
    DIRECTION OUTPUT ;
    USE SIGNAL ;
    SHAPE ABUTMENT ;
    PORT
      LAYER M3_m ;
      RECT 0 1495.235 0.07 1495.305 ;
    END
  END rw0_rd_out[136]
  PIN rw0_rd_out[137]
    DIRECTION OUTPUT ;
    USE SIGNAL ;
    SHAPE ABUTMENT ;
    PORT
      LAYER M3_m ;
      RECT 0 1497.335 0.07 1497.405 ;
    END
  END rw0_rd_out[137]
  PIN rw0_rd_out[138]
    DIRECTION OUTPUT ;
    USE SIGNAL ;
    SHAPE ABUTMENT ;
    PORT
      LAYER M3_m ;
      RECT 0 1499.435 0.07 1499.505 ;
    END
  END rw0_rd_out[138]
  PIN rw0_rd_out[139]
    DIRECTION OUTPUT ;
    USE SIGNAL ;
    SHAPE ABUTMENT ;
    PORT
      LAYER M3_m ;
      RECT 0 1501.535 0.07 1501.605 ;
    END
  END rw0_rd_out[139]
  PIN rw0_rd_out[140]
    DIRECTION OUTPUT ;
    USE SIGNAL ;
    SHAPE ABUTMENT ;
    PORT
      LAYER M3_m ;
      RECT 0 1503.635 0.07 1503.705 ;
    END
  END rw0_rd_out[140]
  PIN rw0_rd_out[141]
    DIRECTION OUTPUT ;
    USE SIGNAL ;
    SHAPE ABUTMENT ;
    PORT
      LAYER M3_m ;
      RECT 0 1505.735 0.07 1505.805 ;
    END
  END rw0_rd_out[141]
  PIN rw0_rd_out[142]
    DIRECTION OUTPUT ;
    USE SIGNAL ;
    SHAPE ABUTMENT ;
    PORT
      LAYER M3_m ;
      RECT 0 1507.835 0.07 1507.905 ;
    END
  END rw0_rd_out[142]
  PIN rw0_rd_out[143]
    DIRECTION OUTPUT ;
    USE SIGNAL ;
    SHAPE ABUTMENT ;
    PORT
      LAYER M3_m ;
      RECT 0 1509.935 0.07 1510.005 ;
    END
  END rw0_rd_out[143]
  PIN rw0_rd_out[144]
    DIRECTION OUTPUT ;
    USE SIGNAL ;
    SHAPE ABUTMENT ;
    PORT
      LAYER M3_m ;
      RECT 0 1512.035 0.07 1512.105 ;
    END
  END rw0_rd_out[144]
  PIN rw0_rd_out[145]
    DIRECTION OUTPUT ;
    USE SIGNAL ;
    SHAPE ABUTMENT ;
    PORT
      LAYER M3_m ;
      RECT 0 1514.135 0.07 1514.205 ;
    END
  END rw0_rd_out[145]
  PIN rw0_rd_out[146]
    DIRECTION OUTPUT ;
    USE SIGNAL ;
    SHAPE ABUTMENT ;
    PORT
      LAYER M3_m ;
      RECT 0 1516.235 0.07 1516.305 ;
    END
  END rw0_rd_out[146]
  PIN rw0_rd_out[147]
    DIRECTION OUTPUT ;
    USE SIGNAL ;
    SHAPE ABUTMENT ;
    PORT
      LAYER M3_m ;
      RECT 0 1518.335 0.07 1518.405 ;
    END
  END rw0_rd_out[147]
  PIN rw0_rd_out[148]
    DIRECTION OUTPUT ;
    USE SIGNAL ;
    SHAPE ABUTMENT ;
    PORT
      LAYER M3_m ;
      RECT 0 1520.435 0.07 1520.505 ;
    END
  END rw0_rd_out[148]
  PIN rw0_rd_out[149]
    DIRECTION OUTPUT ;
    USE SIGNAL ;
    SHAPE ABUTMENT ;
    PORT
      LAYER M3_m ;
      RECT 0 1522.535 0.07 1522.605 ;
    END
  END rw0_rd_out[149]
  PIN rw0_rd_out[150]
    DIRECTION OUTPUT ;
    USE SIGNAL ;
    SHAPE ABUTMENT ;
    PORT
      LAYER M3_m ;
      RECT 0 1524.635 0.07 1524.705 ;
    END
  END rw0_rd_out[150]
  PIN rw0_rd_out[151]
    DIRECTION OUTPUT ;
    USE SIGNAL ;
    SHAPE ABUTMENT ;
    PORT
      LAYER M3_m ;
      RECT 0 1526.735 0.07 1526.805 ;
    END
  END rw0_rd_out[151]
  PIN rw0_rd_out[152]
    DIRECTION OUTPUT ;
    USE SIGNAL ;
    SHAPE ABUTMENT ;
    PORT
      LAYER M3_m ;
      RECT 0 1528.835 0.07 1528.905 ;
    END
  END rw0_rd_out[152]
  PIN rw0_rd_out[153]
    DIRECTION OUTPUT ;
    USE SIGNAL ;
    SHAPE ABUTMENT ;
    PORT
      LAYER M3_m ;
      RECT 0 1530.935 0.07 1531.005 ;
    END
  END rw0_rd_out[153]
  PIN rw0_rd_out[154]
    DIRECTION OUTPUT ;
    USE SIGNAL ;
    SHAPE ABUTMENT ;
    PORT
      LAYER M3_m ;
      RECT 0 1533.035 0.07 1533.105 ;
    END
  END rw0_rd_out[154]
  PIN rw0_rd_out[155]
    DIRECTION OUTPUT ;
    USE SIGNAL ;
    SHAPE ABUTMENT ;
    PORT
      LAYER M3_m ;
      RECT 0 1535.135 0.07 1535.205 ;
    END
  END rw0_rd_out[155]
  PIN rw0_rd_out[156]
    DIRECTION OUTPUT ;
    USE SIGNAL ;
    SHAPE ABUTMENT ;
    PORT
      LAYER M3_m ;
      RECT 0 1537.235 0.07 1537.305 ;
    END
  END rw0_rd_out[156]
  PIN rw0_rd_out[157]
    DIRECTION OUTPUT ;
    USE SIGNAL ;
    SHAPE ABUTMENT ;
    PORT
      LAYER M3_m ;
      RECT 0 1539.335 0.07 1539.405 ;
    END
  END rw0_rd_out[157]
  PIN rw0_rd_out[158]
    DIRECTION OUTPUT ;
    USE SIGNAL ;
    SHAPE ABUTMENT ;
    PORT
      LAYER M3_m ;
      RECT 0 1541.435 0.07 1541.505 ;
    END
  END rw0_rd_out[158]
  PIN rw0_rd_out[159]
    DIRECTION OUTPUT ;
    USE SIGNAL ;
    SHAPE ABUTMENT ;
    PORT
      LAYER M3_m ;
      RECT 0 1543.535 0.07 1543.605 ;
    END
  END rw0_rd_out[159]
  PIN rw0_rd_out[160]
    DIRECTION OUTPUT ;
    USE SIGNAL ;
    SHAPE ABUTMENT ;
    PORT
      LAYER M3_m ;
      RECT 0 1545.635 0.07 1545.705 ;
    END
  END rw0_rd_out[160]
  PIN rw0_rd_out[161]
    DIRECTION OUTPUT ;
    USE SIGNAL ;
    SHAPE ABUTMENT ;
    PORT
      LAYER M3_m ;
      RECT 0 1547.735 0.07 1547.805 ;
    END
  END rw0_rd_out[161]
  PIN rw0_rd_out[162]
    DIRECTION OUTPUT ;
    USE SIGNAL ;
    SHAPE ABUTMENT ;
    PORT
      LAYER M3_m ;
      RECT 0 1549.835 0.07 1549.905 ;
    END
  END rw0_rd_out[162]
  PIN rw0_rd_out[163]
    DIRECTION OUTPUT ;
    USE SIGNAL ;
    SHAPE ABUTMENT ;
    PORT
      LAYER M3_m ;
      RECT 0 1551.935 0.07 1552.005 ;
    END
  END rw0_rd_out[163]
  PIN rw0_rd_out[164]
    DIRECTION OUTPUT ;
    USE SIGNAL ;
    SHAPE ABUTMENT ;
    PORT
      LAYER M3_m ;
      RECT 0 1554.035 0.07 1554.105 ;
    END
  END rw0_rd_out[164]
  PIN rw0_rd_out[165]
    DIRECTION OUTPUT ;
    USE SIGNAL ;
    SHAPE ABUTMENT ;
    PORT
      LAYER M3_m ;
      RECT 0 1556.135 0.07 1556.205 ;
    END
  END rw0_rd_out[165]
  PIN rw0_rd_out[166]
    DIRECTION OUTPUT ;
    USE SIGNAL ;
    SHAPE ABUTMENT ;
    PORT
      LAYER M3_m ;
      RECT 0 1558.235 0.07 1558.305 ;
    END
  END rw0_rd_out[166]
  PIN rw0_rd_out[167]
    DIRECTION OUTPUT ;
    USE SIGNAL ;
    SHAPE ABUTMENT ;
    PORT
      LAYER M3_m ;
      RECT 0 1560.335 0.07 1560.405 ;
    END
  END rw0_rd_out[167]
  PIN rw0_rd_out[168]
    DIRECTION OUTPUT ;
    USE SIGNAL ;
    SHAPE ABUTMENT ;
    PORT
      LAYER M3_m ;
      RECT 0 1562.435 0.07 1562.505 ;
    END
  END rw0_rd_out[168]
  PIN rw0_rd_out[169]
    DIRECTION OUTPUT ;
    USE SIGNAL ;
    SHAPE ABUTMENT ;
    PORT
      LAYER M3_m ;
      RECT 0 1564.535 0.07 1564.605 ;
    END
  END rw0_rd_out[169]
  PIN rw0_rd_out[170]
    DIRECTION OUTPUT ;
    USE SIGNAL ;
    SHAPE ABUTMENT ;
    PORT
      LAYER M3_m ;
      RECT 0 1566.635 0.07 1566.705 ;
    END
  END rw0_rd_out[170]
  PIN rw0_rd_out[171]
    DIRECTION OUTPUT ;
    USE SIGNAL ;
    SHAPE ABUTMENT ;
    PORT
      LAYER M3_m ;
      RECT 0 1568.735 0.07 1568.805 ;
    END
  END rw0_rd_out[171]
  PIN rw0_rd_out[172]
    DIRECTION OUTPUT ;
    USE SIGNAL ;
    SHAPE ABUTMENT ;
    PORT
      LAYER M3_m ;
      RECT 0 1570.835 0.07 1570.905 ;
    END
  END rw0_rd_out[172]
  PIN rw0_rd_out[173]
    DIRECTION OUTPUT ;
    USE SIGNAL ;
    SHAPE ABUTMENT ;
    PORT
      LAYER M3_m ;
      RECT 0 1572.935 0.07 1573.005 ;
    END
  END rw0_rd_out[173]
  PIN rw0_rd_out[174]
    DIRECTION OUTPUT ;
    USE SIGNAL ;
    SHAPE ABUTMENT ;
    PORT
      LAYER M3_m ;
      RECT 0 1575.035 0.07 1575.105 ;
    END
  END rw0_rd_out[174]
  PIN rw0_rd_out[175]
    DIRECTION OUTPUT ;
    USE SIGNAL ;
    SHAPE ABUTMENT ;
    PORT
      LAYER M3_m ;
      RECT 0 1577.135 0.07 1577.205 ;
    END
  END rw0_rd_out[175]
  PIN rw0_rd_out[176]
    DIRECTION OUTPUT ;
    USE SIGNAL ;
    SHAPE ABUTMENT ;
    PORT
      LAYER M3_m ;
      RECT 0 1579.235 0.07 1579.305 ;
    END
  END rw0_rd_out[176]
  PIN rw0_rd_out[177]
    DIRECTION OUTPUT ;
    USE SIGNAL ;
    SHAPE ABUTMENT ;
    PORT
      LAYER M3_m ;
      RECT 0 1581.335 0.07 1581.405 ;
    END
  END rw0_rd_out[177]
  PIN rw0_rd_out[178]
    DIRECTION OUTPUT ;
    USE SIGNAL ;
    SHAPE ABUTMENT ;
    PORT
      LAYER M3_m ;
      RECT 0 1583.435 0.07 1583.505 ;
    END
  END rw0_rd_out[178]
  PIN rw0_rd_out[179]
    DIRECTION OUTPUT ;
    USE SIGNAL ;
    SHAPE ABUTMENT ;
    PORT
      LAYER M3_m ;
      RECT 0 1585.535 0.07 1585.605 ;
    END
  END rw0_rd_out[179]
  PIN rw0_rd_out[180]
    DIRECTION OUTPUT ;
    USE SIGNAL ;
    SHAPE ABUTMENT ;
    PORT
      LAYER M3_m ;
      RECT 0 1587.635 0.07 1587.705 ;
    END
  END rw0_rd_out[180]
  PIN rw0_rd_out[181]
    DIRECTION OUTPUT ;
    USE SIGNAL ;
    SHAPE ABUTMENT ;
    PORT
      LAYER M3_m ;
      RECT 0 1589.735 0.07 1589.805 ;
    END
  END rw0_rd_out[181]
  PIN rw0_rd_out[182]
    DIRECTION OUTPUT ;
    USE SIGNAL ;
    SHAPE ABUTMENT ;
    PORT
      LAYER M3_m ;
      RECT 0 1591.835 0.07 1591.905 ;
    END
  END rw0_rd_out[182]
  PIN rw0_rd_out[183]
    DIRECTION OUTPUT ;
    USE SIGNAL ;
    SHAPE ABUTMENT ;
    PORT
      LAYER M3_m ;
      RECT 0 1593.935 0.07 1594.005 ;
    END
  END rw0_rd_out[183]
  PIN rw0_rd_out[184]
    DIRECTION OUTPUT ;
    USE SIGNAL ;
    SHAPE ABUTMENT ;
    PORT
      LAYER M3_m ;
      RECT 0 1596.035 0.07 1596.105 ;
    END
  END rw0_rd_out[184]
  PIN rw0_rd_out[185]
    DIRECTION OUTPUT ;
    USE SIGNAL ;
    SHAPE ABUTMENT ;
    PORT
      LAYER M3_m ;
      RECT 0 1598.135 0.07 1598.205 ;
    END
  END rw0_rd_out[185]
  PIN rw0_rd_out[186]
    DIRECTION OUTPUT ;
    USE SIGNAL ;
    SHAPE ABUTMENT ;
    PORT
      LAYER M3_m ;
      RECT 0 1600.235 0.07 1600.305 ;
    END
  END rw0_rd_out[186]
  PIN rw0_rd_out[187]
    DIRECTION OUTPUT ;
    USE SIGNAL ;
    SHAPE ABUTMENT ;
    PORT
      LAYER M3_m ;
      RECT 0 1602.335 0.07 1602.405 ;
    END
  END rw0_rd_out[187]
  PIN rw0_rd_out[188]
    DIRECTION OUTPUT ;
    USE SIGNAL ;
    SHAPE ABUTMENT ;
    PORT
      LAYER M3_m ;
      RECT 0 1604.435 0.07 1604.505 ;
    END
  END rw0_rd_out[188]
  PIN rw0_rd_out[189]
    DIRECTION OUTPUT ;
    USE SIGNAL ;
    SHAPE ABUTMENT ;
    PORT
      LAYER M3_m ;
      RECT 0 1606.535 0.07 1606.605 ;
    END
  END rw0_rd_out[189]
  PIN rw0_rd_out[190]
    DIRECTION OUTPUT ;
    USE SIGNAL ;
    SHAPE ABUTMENT ;
    PORT
      LAYER M3_m ;
      RECT 0 1608.635 0.07 1608.705 ;
    END
  END rw0_rd_out[190]
  PIN rw0_rd_out[191]
    DIRECTION OUTPUT ;
    USE SIGNAL ;
    SHAPE ABUTMENT ;
    PORT
      LAYER M3_m ;
      RECT 0 1610.735 0.07 1610.805 ;
    END
  END rw0_rd_out[191]
  PIN rw0_rd_out[192]
    DIRECTION OUTPUT ;
    USE SIGNAL ;
    SHAPE ABUTMENT ;
    PORT
      LAYER M3_m ;
      RECT 0 1612.835 0.07 1612.905 ;
    END
  END rw0_rd_out[192]
  PIN rw0_rd_out[193]
    DIRECTION OUTPUT ;
    USE SIGNAL ;
    SHAPE ABUTMENT ;
    PORT
      LAYER M3_m ;
      RECT 0 1614.935 0.07 1615.005 ;
    END
  END rw0_rd_out[193]
  PIN rw0_rd_out[194]
    DIRECTION OUTPUT ;
    USE SIGNAL ;
    SHAPE ABUTMENT ;
    PORT
      LAYER M3_m ;
      RECT 0 1617.035 0.07 1617.105 ;
    END
  END rw0_rd_out[194]
  PIN rw0_rd_out[195]
    DIRECTION OUTPUT ;
    USE SIGNAL ;
    SHAPE ABUTMENT ;
    PORT
      LAYER M3_m ;
      RECT 0 1619.135 0.07 1619.205 ;
    END
  END rw0_rd_out[195]
  PIN rw0_rd_out[196]
    DIRECTION OUTPUT ;
    USE SIGNAL ;
    SHAPE ABUTMENT ;
    PORT
      LAYER M3_m ;
      RECT 0 1621.235 0.07 1621.305 ;
    END
  END rw0_rd_out[196]
  PIN rw0_rd_out[197]
    DIRECTION OUTPUT ;
    USE SIGNAL ;
    SHAPE ABUTMENT ;
    PORT
      LAYER M3_m ;
      RECT 0 1623.335 0.07 1623.405 ;
    END
  END rw0_rd_out[197]
  PIN rw0_rd_out[198]
    DIRECTION OUTPUT ;
    USE SIGNAL ;
    SHAPE ABUTMENT ;
    PORT
      LAYER M3_m ;
      RECT 0 1625.435 0.07 1625.505 ;
    END
  END rw0_rd_out[198]
  PIN rw0_rd_out[199]
    DIRECTION OUTPUT ;
    USE SIGNAL ;
    SHAPE ABUTMENT ;
    PORT
      LAYER M3_m ;
      RECT 0 1627.535 0.07 1627.605 ;
    END
  END rw0_rd_out[199]
  PIN rw0_rd_out[200]
    DIRECTION OUTPUT ;
    USE SIGNAL ;
    SHAPE ABUTMENT ;
    PORT
      LAYER M3_m ;
      RECT 0 1629.635 0.07 1629.705 ;
    END
  END rw0_rd_out[200]
  PIN rw0_rd_out[201]
    DIRECTION OUTPUT ;
    USE SIGNAL ;
    SHAPE ABUTMENT ;
    PORT
      LAYER M3_m ;
      RECT 0 1631.735 0.07 1631.805 ;
    END
  END rw0_rd_out[201]
  PIN rw0_rd_out[202]
    DIRECTION OUTPUT ;
    USE SIGNAL ;
    SHAPE ABUTMENT ;
    PORT
      LAYER M3_m ;
      RECT 0 1633.835 0.07 1633.905 ;
    END
  END rw0_rd_out[202]
  PIN rw0_rd_out[203]
    DIRECTION OUTPUT ;
    USE SIGNAL ;
    SHAPE ABUTMENT ;
    PORT
      LAYER M3_m ;
      RECT 0 1635.935 0.07 1636.005 ;
    END
  END rw0_rd_out[203]
  PIN rw0_rd_out[204]
    DIRECTION OUTPUT ;
    USE SIGNAL ;
    SHAPE ABUTMENT ;
    PORT
      LAYER M3_m ;
      RECT 0 1638.035 0.07 1638.105 ;
    END
  END rw0_rd_out[204]
  PIN rw0_rd_out[205]
    DIRECTION OUTPUT ;
    USE SIGNAL ;
    SHAPE ABUTMENT ;
    PORT
      LAYER M3_m ;
      RECT 0 1640.135 0.07 1640.205 ;
    END
  END rw0_rd_out[205]
  PIN rw0_rd_out[206]
    DIRECTION OUTPUT ;
    USE SIGNAL ;
    SHAPE ABUTMENT ;
    PORT
      LAYER M3_m ;
      RECT 0 1642.235 0.07 1642.305 ;
    END
  END rw0_rd_out[206]
  PIN rw0_rd_out[207]
    DIRECTION OUTPUT ;
    USE SIGNAL ;
    SHAPE ABUTMENT ;
    PORT
      LAYER M3_m ;
      RECT 0 1644.335 0.07 1644.405 ;
    END
  END rw0_rd_out[207]
  PIN rw0_rd_out[208]
    DIRECTION OUTPUT ;
    USE SIGNAL ;
    SHAPE ABUTMENT ;
    PORT
      LAYER M3_m ;
      RECT 0 1646.435 0.07 1646.505 ;
    END
  END rw0_rd_out[208]
  PIN rw0_rd_out[209]
    DIRECTION OUTPUT ;
    USE SIGNAL ;
    SHAPE ABUTMENT ;
    PORT
      LAYER M3_m ;
      RECT 0 1648.535 0.07 1648.605 ;
    END
  END rw0_rd_out[209]
  PIN rw0_rd_out[210]
    DIRECTION OUTPUT ;
    USE SIGNAL ;
    SHAPE ABUTMENT ;
    PORT
      LAYER M3_m ;
      RECT 0 1650.635 0.07 1650.705 ;
    END
  END rw0_rd_out[210]
  PIN rw0_rd_out[211]
    DIRECTION OUTPUT ;
    USE SIGNAL ;
    SHAPE ABUTMENT ;
    PORT
      LAYER M3_m ;
      RECT 0 1652.735 0.07 1652.805 ;
    END
  END rw0_rd_out[211]
  PIN rw0_rd_out[212]
    DIRECTION OUTPUT ;
    USE SIGNAL ;
    SHAPE ABUTMENT ;
    PORT
      LAYER M3_m ;
      RECT 0 1654.835 0.07 1654.905 ;
    END
  END rw0_rd_out[212]
  PIN rw0_rd_out[213]
    DIRECTION OUTPUT ;
    USE SIGNAL ;
    SHAPE ABUTMENT ;
    PORT
      LAYER M3_m ;
      RECT 0 1656.935 0.07 1657.005 ;
    END
  END rw0_rd_out[213]
  PIN rw0_rd_out[214]
    DIRECTION OUTPUT ;
    USE SIGNAL ;
    SHAPE ABUTMENT ;
    PORT
      LAYER M3_m ;
      RECT 0 1659.035 0.07 1659.105 ;
    END
  END rw0_rd_out[214]
  PIN rw0_rd_out[215]
    DIRECTION OUTPUT ;
    USE SIGNAL ;
    SHAPE ABUTMENT ;
    PORT
      LAYER M3_m ;
      RECT 0 1661.135 0.07 1661.205 ;
    END
  END rw0_rd_out[215]
  PIN rw0_rd_out[216]
    DIRECTION OUTPUT ;
    USE SIGNAL ;
    SHAPE ABUTMENT ;
    PORT
      LAYER M3_m ;
      RECT 0 1663.235 0.07 1663.305 ;
    END
  END rw0_rd_out[216]
  PIN rw0_rd_out[217]
    DIRECTION OUTPUT ;
    USE SIGNAL ;
    SHAPE ABUTMENT ;
    PORT
      LAYER M3_m ;
      RECT 0 1665.335 0.07 1665.405 ;
    END
  END rw0_rd_out[217]
  PIN rw0_rd_out[218]
    DIRECTION OUTPUT ;
    USE SIGNAL ;
    SHAPE ABUTMENT ;
    PORT
      LAYER M3_m ;
      RECT 0 1667.435 0.07 1667.505 ;
    END
  END rw0_rd_out[218]
  PIN rw0_rd_out[219]
    DIRECTION OUTPUT ;
    USE SIGNAL ;
    SHAPE ABUTMENT ;
    PORT
      LAYER M3_m ;
      RECT 0 1669.535 0.07 1669.605 ;
    END
  END rw0_rd_out[219]
  PIN rw0_rd_out[220]
    DIRECTION OUTPUT ;
    USE SIGNAL ;
    SHAPE ABUTMENT ;
    PORT
      LAYER M3_m ;
      RECT 0 1671.635 0.07 1671.705 ;
    END
  END rw0_rd_out[220]
  PIN rw0_rd_out[221]
    DIRECTION OUTPUT ;
    USE SIGNAL ;
    SHAPE ABUTMENT ;
    PORT
      LAYER M3_m ;
      RECT 0 1673.735 0.07 1673.805 ;
    END
  END rw0_rd_out[221]
  PIN rw0_rd_out[222]
    DIRECTION OUTPUT ;
    USE SIGNAL ;
    SHAPE ABUTMENT ;
    PORT
      LAYER M3_m ;
      RECT 0 1675.835 0.07 1675.905 ;
    END
  END rw0_rd_out[222]
  PIN rw0_rd_out[223]
    DIRECTION OUTPUT ;
    USE SIGNAL ;
    SHAPE ABUTMENT ;
    PORT
      LAYER M3_m ;
      RECT 0 1677.935 0.07 1678.005 ;
    END
  END rw0_rd_out[223]
  PIN rw0_rd_out[224]
    DIRECTION OUTPUT ;
    USE SIGNAL ;
    SHAPE ABUTMENT ;
    PORT
      LAYER M3_m ;
      RECT 0 1680.035 0.07 1680.105 ;
    END
  END rw0_rd_out[224]
  PIN rw0_rd_out[225]
    DIRECTION OUTPUT ;
    USE SIGNAL ;
    SHAPE ABUTMENT ;
    PORT
      LAYER M3_m ;
      RECT 0 1682.135 0.07 1682.205 ;
    END
  END rw0_rd_out[225]
  PIN rw0_rd_out[226]
    DIRECTION OUTPUT ;
    USE SIGNAL ;
    SHAPE ABUTMENT ;
    PORT
      LAYER M3_m ;
      RECT 0 1684.235 0.07 1684.305 ;
    END
  END rw0_rd_out[226]
  PIN rw0_rd_out[227]
    DIRECTION OUTPUT ;
    USE SIGNAL ;
    SHAPE ABUTMENT ;
    PORT
      LAYER M3_m ;
      RECT 0 1686.335 0.07 1686.405 ;
    END
  END rw0_rd_out[227]
  PIN rw0_rd_out[228]
    DIRECTION OUTPUT ;
    USE SIGNAL ;
    SHAPE ABUTMENT ;
    PORT
      LAYER M3_m ;
      RECT 0 1688.435 0.07 1688.505 ;
    END
  END rw0_rd_out[228]
  PIN rw0_rd_out[229]
    DIRECTION OUTPUT ;
    USE SIGNAL ;
    SHAPE ABUTMENT ;
    PORT
      LAYER M3_m ;
      RECT 0 1690.535 0.07 1690.605 ;
    END
  END rw0_rd_out[229]
  PIN rw0_rd_out[230]
    DIRECTION OUTPUT ;
    USE SIGNAL ;
    SHAPE ABUTMENT ;
    PORT
      LAYER M3_m ;
      RECT 0 1692.635 0.07 1692.705 ;
    END
  END rw0_rd_out[230]
  PIN rw0_rd_out[231]
    DIRECTION OUTPUT ;
    USE SIGNAL ;
    SHAPE ABUTMENT ;
    PORT
      LAYER M3_m ;
      RECT 0 1694.735 0.07 1694.805 ;
    END
  END rw0_rd_out[231]
  PIN rw0_rd_out[232]
    DIRECTION OUTPUT ;
    USE SIGNAL ;
    SHAPE ABUTMENT ;
    PORT
      LAYER M3_m ;
      RECT 0 1696.835 0.07 1696.905 ;
    END
  END rw0_rd_out[232]
  PIN rw0_rd_out[233]
    DIRECTION OUTPUT ;
    USE SIGNAL ;
    SHAPE ABUTMENT ;
    PORT
      LAYER M3_m ;
      RECT 0 1698.935 0.07 1699.005 ;
    END
  END rw0_rd_out[233]
  PIN rw0_rd_out[234]
    DIRECTION OUTPUT ;
    USE SIGNAL ;
    SHAPE ABUTMENT ;
    PORT
      LAYER M3_m ;
      RECT 0 1701.035 0.07 1701.105 ;
    END
  END rw0_rd_out[234]
  PIN rw0_rd_out[235]
    DIRECTION OUTPUT ;
    USE SIGNAL ;
    SHAPE ABUTMENT ;
    PORT
      LAYER M3_m ;
      RECT 0 1703.135 0.07 1703.205 ;
    END
  END rw0_rd_out[235]
  PIN rw0_rd_out[236]
    DIRECTION OUTPUT ;
    USE SIGNAL ;
    SHAPE ABUTMENT ;
    PORT
      LAYER M3_m ;
      RECT 0 1705.235 0.07 1705.305 ;
    END
  END rw0_rd_out[236]
  PIN rw0_rd_out[237]
    DIRECTION OUTPUT ;
    USE SIGNAL ;
    SHAPE ABUTMENT ;
    PORT
      LAYER M3_m ;
      RECT 0 1707.335 0.07 1707.405 ;
    END
  END rw0_rd_out[237]
  PIN rw0_rd_out[238]
    DIRECTION OUTPUT ;
    USE SIGNAL ;
    SHAPE ABUTMENT ;
    PORT
      LAYER M3_m ;
      RECT 0 1709.435 0.07 1709.505 ;
    END
  END rw0_rd_out[238]
  PIN rw0_rd_out[239]
    DIRECTION OUTPUT ;
    USE SIGNAL ;
    SHAPE ABUTMENT ;
    PORT
      LAYER M3_m ;
      RECT 0 1711.535 0.07 1711.605 ;
    END
  END rw0_rd_out[239]
  PIN rw0_rd_out[240]
    DIRECTION OUTPUT ;
    USE SIGNAL ;
    SHAPE ABUTMENT ;
    PORT
      LAYER M3_m ;
      RECT 0 1713.635 0.07 1713.705 ;
    END
  END rw0_rd_out[240]
  PIN rw0_rd_out[241]
    DIRECTION OUTPUT ;
    USE SIGNAL ;
    SHAPE ABUTMENT ;
    PORT
      LAYER M3_m ;
      RECT 0 1715.735 0.07 1715.805 ;
    END
  END rw0_rd_out[241]
  PIN rw0_rd_out[242]
    DIRECTION OUTPUT ;
    USE SIGNAL ;
    SHAPE ABUTMENT ;
    PORT
      LAYER M3_m ;
      RECT 0 1717.835 0.07 1717.905 ;
    END
  END rw0_rd_out[242]
  PIN rw0_rd_out[243]
    DIRECTION OUTPUT ;
    USE SIGNAL ;
    SHAPE ABUTMENT ;
    PORT
      LAYER M3_m ;
      RECT 0 1719.935 0.07 1720.005 ;
    END
  END rw0_rd_out[243]
  PIN rw0_rd_out[244]
    DIRECTION OUTPUT ;
    USE SIGNAL ;
    SHAPE ABUTMENT ;
    PORT
      LAYER M3_m ;
      RECT 0 1722.035 0.07 1722.105 ;
    END
  END rw0_rd_out[244]
  PIN rw0_rd_out[245]
    DIRECTION OUTPUT ;
    USE SIGNAL ;
    SHAPE ABUTMENT ;
    PORT
      LAYER M3_m ;
      RECT 0 1724.135 0.07 1724.205 ;
    END
  END rw0_rd_out[245]
  PIN rw0_rd_out[246]
    DIRECTION OUTPUT ;
    USE SIGNAL ;
    SHAPE ABUTMENT ;
    PORT
      LAYER M3_m ;
      RECT 0 1726.235 0.07 1726.305 ;
    END
  END rw0_rd_out[246]
  PIN rw0_rd_out[247]
    DIRECTION OUTPUT ;
    USE SIGNAL ;
    SHAPE ABUTMENT ;
    PORT
      LAYER M3_m ;
      RECT 0 1728.335 0.07 1728.405 ;
    END
  END rw0_rd_out[247]
  PIN rw0_rd_out[248]
    DIRECTION OUTPUT ;
    USE SIGNAL ;
    SHAPE ABUTMENT ;
    PORT
      LAYER M3_m ;
      RECT 0 1730.435 0.07 1730.505 ;
    END
  END rw0_rd_out[248]
  PIN rw0_rd_out[249]
    DIRECTION OUTPUT ;
    USE SIGNAL ;
    SHAPE ABUTMENT ;
    PORT
      LAYER M3_m ;
      RECT 0 1732.535 0.07 1732.605 ;
    END
  END rw0_rd_out[249]
  PIN rw0_rd_out[250]
    DIRECTION OUTPUT ;
    USE SIGNAL ;
    SHAPE ABUTMENT ;
    PORT
      LAYER M3_m ;
      RECT 0 1734.635 0.07 1734.705 ;
    END
  END rw0_rd_out[250]
  PIN rw0_rd_out[251]
    DIRECTION OUTPUT ;
    USE SIGNAL ;
    SHAPE ABUTMENT ;
    PORT
      LAYER M3_m ;
      RECT 0 1736.735 0.07 1736.805 ;
    END
  END rw0_rd_out[251]
  PIN rw0_rd_out[252]
    DIRECTION OUTPUT ;
    USE SIGNAL ;
    SHAPE ABUTMENT ;
    PORT
      LAYER M3_m ;
      RECT 0 1738.835 0.07 1738.905 ;
    END
  END rw0_rd_out[252]
  PIN rw0_rd_out[253]
    DIRECTION OUTPUT ;
    USE SIGNAL ;
    SHAPE ABUTMENT ;
    PORT
      LAYER M3_m ;
      RECT 0 1740.935 0.07 1741.005 ;
    END
  END rw0_rd_out[253]
  PIN rw0_rd_out[254]
    DIRECTION OUTPUT ;
    USE SIGNAL ;
    SHAPE ABUTMENT ;
    PORT
      LAYER M3_m ;
      RECT 0 1743.035 0.07 1743.105 ;
    END
  END rw0_rd_out[254]
  PIN rw0_rd_out[255]
    DIRECTION OUTPUT ;
    USE SIGNAL ;
    SHAPE ABUTMENT ;
    PORT
      LAYER M3_m ;
      RECT 0 1745.135 0.07 1745.205 ;
    END
  END rw0_rd_out[255]
  PIN rw0_rd_out[256]
    DIRECTION OUTPUT ;
    USE SIGNAL ;
    SHAPE ABUTMENT ;
    PORT
      LAYER M3_m ;
      RECT 0 1747.235 0.07 1747.305 ;
    END
  END rw0_rd_out[256]
  PIN rw0_rd_out[257]
    DIRECTION OUTPUT ;
    USE SIGNAL ;
    SHAPE ABUTMENT ;
    PORT
      LAYER M3_m ;
      RECT 0 1749.335 0.07 1749.405 ;
    END
  END rw0_rd_out[257]
  PIN rw0_rd_out[258]
    DIRECTION OUTPUT ;
    USE SIGNAL ;
    SHAPE ABUTMENT ;
    PORT
      LAYER M3_m ;
      RECT 0 1751.435 0.07 1751.505 ;
    END
  END rw0_rd_out[258]
  PIN rw0_rd_out[259]
    DIRECTION OUTPUT ;
    USE SIGNAL ;
    SHAPE ABUTMENT ;
    PORT
      LAYER M3_m ;
      RECT 0 1753.535 0.07 1753.605 ;
    END
  END rw0_rd_out[259]
  PIN rw0_rd_out[260]
    DIRECTION OUTPUT ;
    USE SIGNAL ;
    SHAPE ABUTMENT ;
    PORT
      LAYER M3_m ;
      RECT 0 1755.635 0.07 1755.705 ;
    END
  END rw0_rd_out[260]
  PIN rw0_rd_out[261]
    DIRECTION OUTPUT ;
    USE SIGNAL ;
    SHAPE ABUTMENT ;
    PORT
      LAYER M3_m ;
      RECT 0 1757.735 0.07 1757.805 ;
    END
  END rw0_rd_out[261]
  PIN rw0_rd_out[262]
    DIRECTION OUTPUT ;
    USE SIGNAL ;
    SHAPE ABUTMENT ;
    PORT
      LAYER M3_m ;
      RECT 0 1759.835 0.07 1759.905 ;
    END
  END rw0_rd_out[262]
  PIN rw0_rd_out[263]
    DIRECTION OUTPUT ;
    USE SIGNAL ;
    SHAPE ABUTMENT ;
    PORT
      LAYER M3_m ;
      RECT 0 1761.935 0.07 1762.005 ;
    END
  END rw0_rd_out[263]
  PIN rw0_rd_out[264]
    DIRECTION OUTPUT ;
    USE SIGNAL ;
    SHAPE ABUTMENT ;
    PORT
      LAYER M3_m ;
      RECT 0 1764.035 0.07 1764.105 ;
    END
  END rw0_rd_out[264]
  PIN rw0_rd_out[265]
    DIRECTION OUTPUT ;
    USE SIGNAL ;
    SHAPE ABUTMENT ;
    PORT
      LAYER M3_m ;
      RECT 0 1766.135 0.07 1766.205 ;
    END
  END rw0_rd_out[265]
  PIN rw0_rd_out[266]
    DIRECTION OUTPUT ;
    USE SIGNAL ;
    SHAPE ABUTMENT ;
    PORT
      LAYER M3_m ;
      RECT 0 1768.235 0.07 1768.305 ;
    END
  END rw0_rd_out[266]
  PIN rw0_rd_out[267]
    DIRECTION OUTPUT ;
    USE SIGNAL ;
    SHAPE ABUTMENT ;
    PORT
      LAYER M3_m ;
      RECT 0 1770.335 0.07 1770.405 ;
    END
  END rw0_rd_out[267]
  PIN rw0_rd_out[268]
    DIRECTION OUTPUT ;
    USE SIGNAL ;
    SHAPE ABUTMENT ;
    PORT
      LAYER M3_m ;
      RECT 0 1772.435 0.07 1772.505 ;
    END
  END rw0_rd_out[268]
  PIN rw0_rd_out[269]
    DIRECTION OUTPUT ;
    USE SIGNAL ;
    SHAPE ABUTMENT ;
    PORT
      LAYER M3_m ;
      RECT 0 1774.535 0.07 1774.605 ;
    END
  END rw0_rd_out[269]
  PIN rw0_rd_out[270]
    DIRECTION OUTPUT ;
    USE SIGNAL ;
    SHAPE ABUTMENT ;
    PORT
      LAYER M3_m ;
      RECT 0 1776.635 0.07 1776.705 ;
    END
  END rw0_rd_out[270]
  PIN rw0_rd_out[271]
    DIRECTION OUTPUT ;
    USE SIGNAL ;
    SHAPE ABUTMENT ;
    PORT
      LAYER M3_m ;
      RECT 0 1778.735 0.07 1778.805 ;
    END
  END rw0_rd_out[271]
  PIN rw0_rd_out[272]
    DIRECTION OUTPUT ;
    USE SIGNAL ;
    SHAPE ABUTMENT ;
    PORT
      LAYER M3_m ;
      RECT 0 1780.835 0.07 1780.905 ;
    END
  END rw0_rd_out[272]
  PIN rw0_rd_out[273]
    DIRECTION OUTPUT ;
    USE SIGNAL ;
    SHAPE ABUTMENT ;
    PORT
      LAYER M3_m ;
      RECT 0 1782.935 0.07 1783.005 ;
    END
  END rw0_rd_out[273]
  PIN rw0_rd_out[274]
    DIRECTION OUTPUT ;
    USE SIGNAL ;
    SHAPE ABUTMENT ;
    PORT
      LAYER M3_m ;
      RECT 0 1785.035 0.07 1785.105 ;
    END
  END rw0_rd_out[274]
  PIN rw0_rd_out[275]
    DIRECTION OUTPUT ;
    USE SIGNAL ;
    SHAPE ABUTMENT ;
    PORT
      LAYER M3_m ;
      RECT 0 1787.135 0.07 1787.205 ;
    END
  END rw0_rd_out[275]
  PIN rw0_rd_out[276]
    DIRECTION OUTPUT ;
    USE SIGNAL ;
    SHAPE ABUTMENT ;
    PORT
      LAYER M3_m ;
      RECT 0 1789.235 0.07 1789.305 ;
    END
  END rw0_rd_out[276]
  PIN rw0_rd_out[277]
    DIRECTION OUTPUT ;
    USE SIGNAL ;
    SHAPE ABUTMENT ;
    PORT
      LAYER M3_m ;
      RECT 0 1791.335 0.07 1791.405 ;
    END
  END rw0_rd_out[277]
  PIN rw0_rd_out[278]
    DIRECTION OUTPUT ;
    USE SIGNAL ;
    SHAPE ABUTMENT ;
    PORT
      LAYER M3_m ;
      RECT 0 1793.435 0.07 1793.505 ;
    END
  END rw0_rd_out[278]
  PIN rw0_rd_out[279]
    DIRECTION OUTPUT ;
    USE SIGNAL ;
    SHAPE ABUTMENT ;
    PORT
      LAYER M3_m ;
      RECT 0 1795.535 0.07 1795.605 ;
    END
  END rw0_rd_out[279]
  PIN rw0_rd_out[280]
    DIRECTION OUTPUT ;
    USE SIGNAL ;
    SHAPE ABUTMENT ;
    PORT
      LAYER M3_m ;
      RECT 0 1797.635 0.07 1797.705 ;
    END
  END rw0_rd_out[280]
  PIN rw0_rd_out[281]
    DIRECTION OUTPUT ;
    USE SIGNAL ;
    SHAPE ABUTMENT ;
    PORT
      LAYER M3_m ;
      RECT 0 1799.735 0.07 1799.805 ;
    END
  END rw0_rd_out[281]
  PIN rw0_rd_out[282]
    DIRECTION OUTPUT ;
    USE SIGNAL ;
    SHAPE ABUTMENT ;
    PORT
      LAYER M3_m ;
      RECT 0 1801.835 0.07 1801.905 ;
    END
  END rw0_rd_out[282]
  PIN rw0_rd_out[283]
    DIRECTION OUTPUT ;
    USE SIGNAL ;
    SHAPE ABUTMENT ;
    PORT
      LAYER M3_m ;
      RECT 0 1803.935 0.07 1804.005 ;
    END
  END rw0_rd_out[283]
  PIN rw0_rd_out[284]
    DIRECTION OUTPUT ;
    USE SIGNAL ;
    SHAPE ABUTMENT ;
    PORT
      LAYER M3_m ;
      RECT 0 1806.035 0.07 1806.105 ;
    END
  END rw0_rd_out[284]
  PIN rw0_rd_out[285]
    DIRECTION OUTPUT ;
    USE SIGNAL ;
    SHAPE ABUTMENT ;
    PORT
      LAYER M3_m ;
      RECT 0 1808.135 0.07 1808.205 ;
    END
  END rw0_rd_out[285]
  PIN rw0_rd_out[286]
    DIRECTION OUTPUT ;
    USE SIGNAL ;
    SHAPE ABUTMENT ;
    PORT
      LAYER M3_m ;
      RECT 0 1810.235 0.07 1810.305 ;
    END
  END rw0_rd_out[286]
  PIN rw0_rd_out[287]
    DIRECTION OUTPUT ;
    USE SIGNAL ;
    SHAPE ABUTMENT ;
    PORT
      LAYER M3_m ;
      RECT 0 1812.335 0.07 1812.405 ;
    END
  END rw0_rd_out[287]
  PIN rw0_rd_out[288]
    DIRECTION OUTPUT ;
    USE SIGNAL ;
    SHAPE ABUTMENT ;
    PORT
      LAYER M3_m ;
      RECT 0 1814.435 0.07 1814.505 ;
    END
  END rw0_rd_out[288]
  PIN rw0_rd_out[289]
    DIRECTION OUTPUT ;
    USE SIGNAL ;
    SHAPE ABUTMENT ;
    PORT
      LAYER M3_m ;
      RECT 0 1816.535 0.07 1816.605 ;
    END
  END rw0_rd_out[289]
  PIN rw0_rd_out[290]
    DIRECTION OUTPUT ;
    USE SIGNAL ;
    SHAPE ABUTMENT ;
    PORT
      LAYER M3_m ;
      RECT 0 1818.635 0.07 1818.705 ;
    END
  END rw0_rd_out[290]
  PIN rw0_rd_out[291]
    DIRECTION OUTPUT ;
    USE SIGNAL ;
    SHAPE ABUTMENT ;
    PORT
      LAYER M3_m ;
      RECT 0 1820.735 0.07 1820.805 ;
    END
  END rw0_rd_out[291]
  PIN rw0_rd_out[292]
    DIRECTION OUTPUT ;
    USE SIGNAL ;
    SHAPE ABUTMENT ;
    PORT
      LAYER M3_m ;
      RECT 0 1822.835 0.07 1822.905 ;
    END
  END rw0_rd_out[292]
  PIN rw0_rd_out[293]
    DIRECTION OUTPUT ;
    USE SIGNAL ;
    SHAPE ABUTMENT ;
    PORT
      LAYER M3_m ;
      RECT 0 1824.935 0.07 1825.005 ;
    END
  END rw0_rd_out[293]
  PIN rw0_rd_out[294]
    DIRECTION OUTPUT ;
    USE SIGNAL ;
    SHAPE ABUTMENT ;
    PORT
      LAYER M3_m ;
      RECT 0 1827.035 0.07 1827.105 ;
    END
  END rw0_rd_out[294]
  PIN rw0_rd_out[295]
    DIRECTION OUTPUT ;
    USE SIGNAL ;
    SHAPE ABUTMENT ;
    PORT
      LAYER M3_m ;
      RECT 0 1829.135 0.07 1829.205 ;
    END
  END rw0_rd_out[295]
  PIN rw0_rd_out[296]
    DIRECTION OUTPUT ;
    USE SIGNAL ;
    SHAPE ABUTMENT ;
    PORT
      LAYER M3_m ;
      RECT 0 1831.235 0.07 1831.305 ;
    END
  END rw0_rd_out[296]
  PIN rw0_rd_out[297]
    DIRECTION OUTPUT ;
    USE SIGNAL ;
    SHAPE ABUTMENT ;
    PORT
      LAYER M3_m ;
      RECT 0 1833.335 0.07 1833.405 ;
    END
  END rw0_rd_out[297]
  PIN rw0_rd_out[298]
    DIRECTION OUTPUT ;
    USE SIGNAL ;
    SHAPE ABUTMENT ;
    PORT
      LAYER M3_m ;
      RECT 0 1835.435 0.07 1835.505 ;
    END
  END rw0_rd_out[298]
  PIN rw0_rd_out[299]
    DIRECTION OUTPUT ;
    USE SIGNAL ;
    SHAPE ABUTMENT ;
    PORT
      LAYER M3_m ;
      RECT 0 1837.535 0.07 1837.605 ;
    END
  END rw0_rd_out[299]
  PIN rw0_rd_out[300]
    DIRECTION OUTPUT ;
    USE SIGNAL ;
    SHAPE ABUTMENT ;
    PORT
      LAYER M3_m ;
      RECT 0 1839.635 0.07 1839.705 ;
    END
  END rw0_rd_out[300]
  PIN rw0_rd_out[301]
    DIRECTION OUTPUT ;
    USE SIGNAL ;
    SHAPE ABUTMENT ;
    PORT
      LAYER M3_m ;
      RECT 0 1841.735 0.07 1841.805 ;
    END
  END rw0_rd_out[301]
  PIN rw0_rd_out[302]
    DIRECTION OUTPUT ;
    USE SIGNAL ;
    SHAPE ABUTMENT ;
    PORT
      LAYER M3_m ;
      RECT 0 1843.835 0.07 1843.905 ;
    END
  END rw0_rd_out[302]
  PIN rw0_rd_out[303]
    DIRECTION OUTPUT ;
    USE SIGNAL ;
    SHAPE ABUTMENT ;
    PORT
      LAYER M3_m ;
      RECT 0 1845.935 0.07 1846.005 ;
    END
  END rw0_rd_out[303]
  PIN rw0_rd_out[304]
    DIRECTION OUTPUT ;
    USE SIGNAL ;
    SHAPE ABUTMENT ;
    PORT
      LAYER M3_m ;
      RECT 0 1848.035 0.07 1848.105 ;
    END
  END rw0_rd_out[304]
  PIN rw0_rd_out[305]
    DIRECTION OUTPUT ;
    USE SIGNAL ;
    SHAPE ABUTMENT ;
    PORT
      LAYER M3_m ;
      RECT 0 1850.135 0.07 1850.205 ;
    END
  END rw0_rd_out[305]
  PIN rw0_rd_out[306]
    DIRECTION OUTPUT ;
    USE SIGNAL ;
    SHAPE ABUTMENT ;
    PORT
      LAYER M3_m ;
      RECT 0 1852.235 0.07 1852.305 ;
    END
  END rw0_rd_out[306]
  PIN rw0_rd_out[307]
    DIRECTION OUTPUT ;
    USE SIGNAL ;
    SHAPE ABUTMENT ;
    PORT
      LAYER M3_m ;
      RECT 0 1854.335 0.07 1854.405 ;
    END
  END rw0_rd_out[307]
  PIN rw0_rd_out[308]
    DIRECTION OUTPUT ;
    USE SIGNAL ;
    SHAPE ABUTMENT ;
    PORT
      LAYER M3_m ;
      RECT 0 1856.435 0.07 1856.505 ;
    END
  END rw0_rd_out[308]
  PIN rw0_rd_out[309]
    DIRECTION OUTPUT ;
    USE SIGNAL ;
    SHAPE ABUTMENT ;
    PORT
      LAYER M3_m ;
      RECT 0 1858.535 0.07 1858.605 ;
    END
  END rw0_rd_out[309]
  PIN rw0_rd_out[310]
    DIRECTION OUTPUT ;
    USE SIGNAL ;
    SHAPE ABUTMENT ;
    PORT
      LAYER M3_m ;
      RECT 0 1860.635 0.07 1860.705 ;
    END
  END rw0_rd_out[310]
  PIN rw0_rd_out[311]
    DIRECTION OUTPUT ;
    USE SIGNAL ;
    SHAPE ABUTMENT ;
    PORT
      LAYER M3_m ;
      RECT 0 1862.735 0.07 1862.805 ;
    END
  END rw0_rd_out[311]
  PIN rw0_rd_out[312]
    DIRECTION OUTPUT ;
    USE SIGNAL ;
    SHAPE ABUTMENT ;
    PORT
      LAYER M3_m ;
      RECT 0 1864.835 0.07 1864.905 ;
    END
  END rw0_rd_out[312]
  PIN rw0_rd_out[313]
    DIRECTION OUTPUT ;
    USE SIGNAL ;
    SHAPE ABUTMENT ;
    PORT
      LAYER M3_m ;
      RECT 0 1866.935 0.07 1867.005 ;
    END
  END rw0_rd_out[313]
  PIN rw0_rd_out[314]
    DIRECTION OUTPUT ;
    USE SIGNAL ;
    SHAPE ABUTMENT ;
    PORT
      LAYER M3_m ;
      RECT 0 1869.035 0.07 1869.105 ;
    END
  END rw0_rd_out[314]
  PIN rw0_rd_out[315]
    DIRECTION OUTPUT ;
    USE SIGNAL ;
    SHAPE ABUTMENT ;
    PORT
      LAYER M3_m ;
      RECT 0 1871.135 0.07 1871.205 ;
    END
  END rw0_rd_out[315]
  PIN rw0_rd_out[316]
    DIRECTION OUTPUT ;
    USE SIGNAL ;
    SHAPE ABUTMENT ;
    PORT
      LAYER M3_m ;
      RECT 0 1873.235 0.07 1873.305 ;
    END
  END rw0_rd_out[316]
  PIN rw0_rd_out[317]
    DIRECTION OUTPUT ;
    USE SIGNAL ;
    SHAPE ABUTMENT ;
    PORT
      LAYER M3_m ;
      RECT 0 1875.335 0.07 1875.405 ;
    END
  END rw0_rd_out[317]
  PIN rw0_rd_out[318]
    DIRECTION OUTPUT ;
    USE SIGNAL ;
    SHAPE ABUTMENT ;
    PORT
      LAYER M3_m ;
      RECT 0 1877.435 0.07 1877.505 ;
    END
  END rw0_rd_out[318]
  PIN rw0_rd_out[319]
    DIRECTION OUTPUT ;
    USE SIGNAL ;
    SHAPE ABUTMENT ;
    PORT
      LAYER M3_m ;
      RECT 0 1879.535 0.07 1879.605 ;
    END
  END rw0_rd_out[319]
  PIN rw0_rd_out[320]
    DIRECTION OUTPUT ;
    USE SIGNAL ;
    SHAPE ABUTMENT ;
    PORT
      LAYER M3_m ;
      RECT 0 1881.635 0.07 1881.705 ;
    END
  END rw0_rd_out[320]
  PIN rw0_rd_out[321]
    DIRECTION OUTPUT ;
    USE SIGNAL ;
    SHAPE ABUTMENT ;
    PORT
      LAYER M3_m ;
      RECT 0 1883.735 0.07 1883.805 ;
    END
  END rw0_rd_out[321]
  PIN rw0_rd_out[322]
    DIRECTION OUTPUT ;
    USE SIGNAL ;
    SHAPE ABUTMENT ;
    PORT
      LAYER M3_m ;
      RECT 0 1885.835 0.07 1885.905 ;
    END
  END rw0_rd_out[322]
  PIN rw0_rd_out[323]
    DIRECTION OUTPUT ;
    USE SIGNAL ;
    SHAPE ABUTMENT ;
    PORT
      LAYER M3_m ;
      RECT 0 1887.935 0.07 1888.005 ;
    END
  END rw0_rd_out[323]
  PIN rw0_rd_out[324]
    DIRECTION OUTPUT ;
    USE SIGNAL ;
    SHAPE ABUTMENT ;
    PORT
      LAYER M3_m ;
      RECT 0 1890.035 0.07 1890.105 ;
    END
  END rw0_rd_out[324]
  PIN rw0_rd_out[325]
    DIRECTION OUTPUT ;
    USE SIGNAL ;
    SHAPE ABUTMENT ;
    PORT
      LAYER M3_m ;
      RECT 0 1892.135 0.07 1892.205 ;
    END
  END rw0_rd_out[325]
  PIN rw0_rd_out[326]
    DIRECTION OUTPUT ;
    USE SIGNAL ;
    SHAPE ABUTMENT ;
    PORT
      LAYER M3_m ;
      RECT 0 1894.235 0.07 1894.305 ;
    END
  END rw0_rd_out[326]
  PIN rw0_rd_out[327]
    DIRECTION OUTPUT ;
    USE SIGNAL ;
    SHAPE ABUTMENT ;
    PORT
      LAYER M3_m ;
      RECT 0 1896.335 0.07 1896.405 ;
    END
  END rw0_rd_out[327]
  PIN rw0_rd_out[328]
    DIRECTION OUTPUT ;
    USE SIGNAL ;
    SHAPE ABUTMENT ;
    PORT
      LAYER M3_m ;
      RECT 0 1898.435 0.07 1898.505 ;
    END
  END rw0_rd_out[328]
  PIN rw0_rd_out[329]
    DIRECTION OUTPUT ;
    USE SIGNAL ;
    SHAPE ABUTMENT ;
    PORT
      LAYER M3_m ;
      RECT 0 1900.535 0.07 1900.605 ;
    END
  END rw0_rd_out[329]
  PIN rw0_rd_out[330]
    DIRECTION OUTPUT ;
    USE SIGNAL ;
    SHAPE ABUTMENT ;
    PORT
      LAYER M3_m ;
      RECT 0 1902.635 0.07 1902.705 ;
    END
  END rw0_rd_out[330]
  PIN rw0_rd_out[331]
    DIRECTION OUTPUT ;
    USE SIGNAL ;
    SHAPE ABUTMENT ;
    PORT
      LAYER M3_m ;
      RECT 0 1904.735 0.07 1904.805 ;
    END
  END rw0_rd_out[331]
  PIN rw0_rd_out[332]
    DIRECTION OUTPUT ;
    USE SIGNAL ;
    SHAPE ABUTMENT ;
    PORT
      LAYER M3_m ;
      RECT 0 1906.835 0.07 1906.905 ;
    END
  END rw0_rd_out[332]
  PIN rw0_rd_out[333]
    DIRECTION OUTPUT ;
    USE SIGNAL ;
    SHAPE ABUTMENT ;
    PORT
      LAYER M3_m ;
      RECT 0 1908.935 0.07 1909.005 ;
    END
  END rw0_rd_out[333]
  PIN rw0_rd_out[334]
    DIRECTION OUTPUT ;
    USE SIGNAL ;
    SHAPE ABUTMENT ;
    PORT
      LAYER M3_m ;
      RECT 0 1911.035 0.07 1911.105 ;
    END
  END rw0_rd_out[334]
  PIN rw0_rd_out[335]
    DIRECTION OUTPUT ;
    USE SIGNAL ;
    SHAPE ABUTMENT ;
    PORT
      LAYER M3_m ;
      RECT 0 1913.135 0.07 1913.205 ;
    END
  END rw0_rd_out[335]
  PIN rw0_rd_out[336]
    DIRECTION OUTPUT ;
    USE SIGNAL ;
    SHAPE ABUTMENT ;
    PORT
      LAYER M3_m ;
      RECT 0 1915.235 0.07 1915.305 ;
    END
  END rw0_rd_out[336]
  PIN rw0_rd_out[337]
    DIRECTION OUTPUT ;
    USE SIGNAL ;
    SHAPE ABUTMENT ;
    PORT
      LAYER M3_m ;
      RECT 0 1917.335 0.07 1917.405 ;
    END
  END rw0_rd_out[337]
  PIN rw0_rd_out[338]
    DIRECTION OUTPUT ;
    USE SIGNAL ;
    SHAPE ABUTMENT ;
    PORT
      LAYER M3_m ;
      RECT 0 1919.435 0.07 1919.505 ;
    END
  END rw0_rd_out[338]
  PIN rw0_rd_out[339]
    DIRECTION OUTPUT ;
    USE SIGNAL ;
    SHAPE ABUTMENT ;
    PORT
      LAYER M3_m ;
      RECT 0 1921.535 0.07 1921.605 ;
    END
  END rw0_rd_out[339]
  PIN rw0_rd_out[340]
    DIRECTION OUTPUT ;
    USE SIGNAL ;
    SHAPE ABUTMENT ;
    PORT
      LAYER M3_m ;
      RECT 0 1923.635 0.07 1923.705 ;
    END
  END rw0_rd_out[340]
  PIN rw0_rd_out[341]
    DIRECTION OUTPUT ;
    USE SIGNAL ;
    SHAPE ABUTMENT ;
    PORT
      LAYER M3_m ;
      RECT 0 1925.735 0.07 1925.805 ;
    END
  END rw0_rd_out[341]
  PIN rw0_rd_out[342]
    DIRECTION OUTPUT ;
    USE SIGNAL ;
    SHAPE ABUTMENT ;
    PORT
      LAYER M3_m ;
      RECT 0 1927.835 0.07 1927.905 ;
    END
  END rw0_rd_out[342]
  PIN rw0_rd_out[343]
    DIRECTION OUTPUT ;
    USE SIGNAL ;
    SHAPE ABUTMENT ;
    PORT
      LAYER M3_m ;
      RECT 0 1929.935 0.07 1930.005 ;
    END
  END rw0_rd_out[343]
  PIN rw0_rd_out[344]
    DIRECTION OUTPUT ;
    USE SIGNAL ;
    SHAPE ABUTMENT ;
    PORT
      LAYER M3_m ;
      RECT 0 1932.035 0.07 1932.105 ;
    END
  END rw0_rd_out[344]
  PIN rw0_rd_out[345]
    DIRECTION OUTPUT ;
    USE SIGNAL ;
    SHAPE ABUTMENT ;
    PORT
      LAYER M3_m ;
      RECT 0 1934.135 0.07 1934.205 ;
    END
  END rw0_rd_out[345]
  PIN rw0_rd_out[346]
    DIRECTION OUTPUT ;
    USE SIGNAL ;
    SHAPE ABUTMENT ;
    PORT
      LAYER M3_m ;
      RECT 0 1936.235 0.07 1936.305 ;
    END
  END rw0_rd_out[346]
  PIN rw0_rd_out[347]
    DIRECTION OUTPUT ;
    USE SIGNAL ;
    SHAPE ABUTMENT ;
    PORT
      LAYER M3_m ;
      RECT 0 1938.335 0.07 1938.405 ;
    END
  END rw0_rd_out[347]
  PIN rw0_rd_out[348]
    DIRECTION OUTPUT ;
    USE SIGNAL ;
    SHAPE ABUTMENT ;
    PORT
      LAYER M3_m ;
      RECT 0 1940.435 0.07 1940.505 ;
    END
  END rw0_rd_out[348]
  PIN rw0_rd_out[349]
    DIRECTION OUTPUT ;
    USE SIGNAL ;
    SHAPE ABUTMENT ;
    PORT
      LAYER M3_m ;
      RECT 0 1942.535 0.07 1942.605 ;
    END
  END rw0_rd_out[349]
  PIN rw0_rd_out[350]
    DIRECTION OUTPUT ;
    USE SIGNAL ;
    SHAPE ABUTMENT ;
    PORT
      LAYER M3_m ;
      RECT 0 1944.635 0.07 1944.705 ;
    END
  END rw0_rd_out[350]
  PIN rw0_rd_out[351]
    DIRECTION OUTPUT ;
    USE SIGNAL ;
    SHAPE ABUTMENT ;
    PORT
      LAYER M3_m ;
      RECT 0 1946.735 0.07 1946.805 ;
    END
  END rw0_rd_out[351]
  PIN rw0_rd_out[352]
    DIRECTION OUTPUT ;
    USE SIGNAL ;
    SHAPE ABUTMENT ;
    PORT
      LAYER M3_m ;
      RECT 0 1948.835 0.07 1948.905 ;
    END
  END rw0_rd_out[352]
  PIN rw0_rd_out[353]
    DIRECTION OUTPUT ;
    USE SIGNAL ;
    SHAPE ABUTMENT ;
    PORT
      LAYER M3_m ;
      RECT 0 1950.935 0.07 1951.005 ;
    END
  END rw0_rd_out[353]
  PIN rw0_rd_out[354]
    DIRECTION OUTPUT ;
    USE SIGNAL ;
    SHAPE ABUTMENT ;
    PORT
      LAYER M3_m ;
      RECT 0 1953.035 0.07 1953.105 ;
    END
  END rw0_rd_out[354]
  PIN rw0_rd_out[355]
    DIRECTION OUTPUT ;
    USE SIGNAL ;
    SHAPE ABUTMENT ;
    PORT
      LAYER M3_m ;
      RECT 0 1955.135 0.07 1955.205 ;
    END
  END rw0_rd_out[355]
  PIN rw0_rd_out[356]
    DIRECTION OUTPUT ;
    USE SIGNAL ;
    SHAPE ABUTMENT ;
    PORT
      LAYER M3_m ;
      RECT 0 1957.235 0.07 1957.305 ;
    END
  END rw0_rd_out[356]
  PIN rw0_rd_out[357]
    DIRECTION OUTPUT ;
    USE SIGNAL ;
    SHAPE ABUTMENT ;
    PORT
      LAYER M3_m ;
      RECT 0 1959.335 0.07 1959.405 ;
    END
  END rw0_rd_out[357]
  PIN rw0_rd_out[358]
    DIRECTION OUTPUT ;
    USE SIGNAL ;
    SHAPE ABUTMENT ;
    PORT
      LAYER M3_m ;
      RECT 0 1961.435 0.07 1961.505 ;
    END
  END rw0_rd_out[358]
  PIN rw0_rd_out[359]
    DIRECTION OUTPUT ;
    USE SIGNAL ;
    SHAPE ABUTMENT ;
    PORT
      LAYER M3_m ;
      RECT 0 1963.535 0.07 1963.605 ;
    END
  END rw0_rd_out[359]
  PIN rw0_rd_out[360]
    DIRECTION OUTPUT ;
    USE SIGNAL ;
    SHAPE ABUTMENT ;
    PORT
      LAYER M3_m ;
      RECT 0 1965.635 0.07 1965.705 ;
    END
  END rw0_rd_out[360]
  PIN rw0_rd_out[361]
    DIRECTION OUTPUT ;
    USE SIGNAL ;
    SHAPE ABUTMENT ;
    PORT
      LAYER M3_m ;
      RECT 0 1967.735 0.07 1967.805 ;
    END
  END rw0_rd_out[361]
  PIN rw0_rd_out[362]
    DIRECTION OUTPUT ;
    USE SIGNAL ;
    SHAPE ABUTMENT ;
    PORT
      LAYER M3_m ;
      RECT 0 1969.835 0.07 1969.905 ;
    END
  END rw0_rd_out[362]
  PIN rw0_rd_out[363]
    DIRECTION OUTPUT ;
    USE SIGNAL ;
    SHAPE ABUTMENT ;
    PORT
      LAYER M3_m ;
      RECT 0 1971.935 0.07 1972.005 ;
    END
  END rw0_rd_out[363]
  PIN rw0_rd_out[364]
    DIRECTION OUTPUT ;
    USE SIGNAL ;
    SHAPE ABUTMENT ;
    PORT
      LAYER M3_m ;
      RECT 0 1974.035 0.07 1974.105 ;
    END
  END rw0_rd_out[364]
  PIN rw0_rd_out[365]
    DIRECTION OUTPUT ;
    USE SIGNAL ;
    SHAPE ABUTMENT ;
    PORT
      LAYER M3_m ;
      RECT 0 1976.135 0.07 1976.205 ;
    END
  END rw0_rd_out[365]
  PIN rw0_rd_out[366]
    DIRECTION OUTPUT ;
    USE SIGNAL ;
    SHAPE ABUTMENT ;
    PORT
      LAYER M3_m ;
      RECT 0 1978.235 0.07 1978.305 ;
    END
  END rw0_rd_out[366]
  PIN rw0_rd_out[367]
    DIRECTION OUTPUT ;
    USE SIGNAL ;
    SHAPE ABUTMENT ;
    PORT
      LAYER M3_m ;
      RECT 0 1980.335 0.07 1980.405 ;
    END
  END rw0_rd_out[367]
  PIN rw0_rd_out[368]
    DIRECTION OUTPUT ;
    USE SIGNAL ;
    SHAPE ABUTMENT ;
    PORT
      LAYER M3_m ;
      RECT 0 1982.435 0.07 1982.505 ;
    END
  END rw0_rd_out[368]
  PIN rw0_rd_out[369]
    DIRECTION OUTPUT ;
    USE SIGNAL ;
    SHAPE ABUTMENT ;
    PORT
      LAYER M3_m ;
      RECT 0 1984.535 0.07 1984.605 ;
    END
  END rw0_rd_out[369]
  PIN rw0_rd_out[370]
    DIRECTION OUTPUT ;
    USE SIGNAL ;
    SHAPE ABUTMENT ;
    PORT
      LAYER M3_m ;
      RECT 0 1986.635 0.07 1986.705 ;
    END
  END rw0_rd_out[370]
  PIN rw0_rd_out[371]
    DIRECTION OUTPUT ;
    USE SIGNAL ;
    SHAPE ABUTMENT ;
    PORT
      LAYER M3_m ;
      RECT 0 1988.735 0.07 1988.805 ;
    END
  END rw0_rd_out[371]
  PIN rw0_rd_out[372]
    DIRECTION OUTPUT ;
    USE SIGNAL ;
    SHAPE ABUTMENT ;
    PORT
      LAYER M3_m ;
      RECT 0 1990.835 0.07 1990.905 ;
    END
  END rw0_rd_out[372]
  PIN rw0_rd_out[373]
    DIRECTION OUTPUT ;
    USE SIGNAL ;
    SHAPE ABUTMENT ;
    PORT
      LAYER M3_m ;
      RECT 0 1992.935 0.07 1993.005 ;
    END
  END rw0_rd_out[373]
  PIN rw0_rd_out[374]
    DIRECTION OUTPUT ;
    USE SIGNAL ;
    SHAPE ABUTMENT ;
    PORT
      LAYER M3_m ;
      RECT 0 1995.035 0.07 1995.105 ;
    END
  END rw0_rd_out[374]
  PIN rw0_rd_out[375]
    DIRECTION OUTPUT ;
    USE SIGNAL ;
    SHAPE ABUTMENT ;
    PORT
      LAYER M3_m ;
      RECT 0 1997.135 0.07 1997.205 ;
    END
  END rw0_rd_out[375]
  PIN rw0_rd_out[376]
    DIRECTION OUTPUT ;
    USE SIGNAL ;
    SHAPE ABUTMENT ;
    PORT
      LAYER M3_m ;
      RECT 0 1999.235 0.07 1999.305 ;
    END
  END rw0_rd_out[376]
  PIN rw0_rd_out[377]
    DIRECTION OUTPUT ;
    USE SIGNAL ;
    SHAPE ABUTMENT ;
    PORT
      LAYER M3_m ;
      RECT 0 2001.335 0.07 2001.405 ;
    END
  END rw0_rd_out[377]
  PIN rw0_rd_out[378]
    DIRECTION OUTPUT ;
    USE SIGNAL ;
    SHAPE ABUTMENT ;
    PORT
      LAYER M3_m ;
      RECT 0 2003.435 0.07 2003.505 ;
    END
  END rw0_rd_out[378]
  PIN rw0_rd_out[379]
    DIRECTION OUTPUT ;
    USE SIGNAL ;
    SHAPE ABUTMENT ;
    PORT
      LAYER M3_m ;
      RECT 0 2005.535 0.07 2005.605 ;
    END
  END rw0_rd_out[379]
  PIN rw0_rd_out[380]
    DIRECTION OUTPUT ;
    USE SIGNAL ;
    SHAPE ABUTMENT ;
    PORT
      LAYER M3_m ;
      RECT 0 2007.635 0.07 2007.705 ;
    END
  END rw0_rd_out[380]
  PIN rw0_rd_out[381]
    DIRECTION OUTPUT ;
    USE SIGNAL ;
    SHAPE ABUTMENT ;
    PORT
      LAYER M3_m ;
      RECT 0 2009.735 0.07 2009.805 ;
    END
  END rw0_rd_out[381]
  PIN rw0_rd_out[382]
    DIRECTION OUTPUT ;
    USE SIGNAL ;
    SHAPE ABUTMENT ;
    PORT
      LAYER M3_m ;
      RECT 0 2011.835 0.07 2011.905 ;
    END
  END rw0_rd_out[382]
  PIN rw0_rd_out[383]
    DIRECTION OUTPUT ;
    USE SIGNAL ;
    SHAPE ABUTMENT ;
    PORT
      LAYER M3_m ;
      RECT 0 2013.935 0.07 2014.005 ;
    END
  END rw0_rd_out[383]
  PIN rw0_rd_out[384]
    DIRECTION OUTPUT ;
    USE SIGNAL ;
    SHAPE ABUTMENT ;
    PORT
      LAYER M3_m ;
      RECT 0 2016.035 0.07 2016.105 ;
    END
  END rw0_rd_out[384]
  PIN rw0_rd_out[385]
    DIRECTION OUTPUT ;
    USE SIGNAL ;
    SHAPE ABUTMENT ;
    PORT
      LAYER M3_m ;
      RECT 0 2018.135 0.07 2018.205 ;
    END
  END rw0_rd_out[385]
  PIN rw0_rd_out[386]
    DIRECTION OUTPUT ;
    USE SIGNAL ;
    SHAPE ABUTMENT ;
    PORT
      LAYER M3_m ;
      RECT 0 2020.235 0.07 2020.305 ;
    END
  END rw0_rd_out[386]
  PIN rw0_rd_out[387]
    DIRECTION OUTPUT ;
    USE SIGNAL ;
    SHAPE ABUTMENT ;
    PORT
      LAYER M3_m ;
      RECT 0 2022.335 0.07 2022.405 ;
    END
  END rw0_rd_out[387]
  PIN rw0_rd_out[388]
    DIRECTION OUTPUT ;
    USE SIGNAL ;
    SHAPE ABUTMENT ;
    PORT
      LAYER M3_m ;
      RECT 0 2024.435 0.07 2024.505 ;
    END
  END rw0_rd_out[388]
  PIN rw0_rd_out[389]
    DIRECTION OUTPUT ;
    USE SIGNAL ;
    SHAPE ABUTMENT ;
    PORT
      LAYER M3_m ;
      RECT 0 2026.535 0.07 2026.605 ;
    END
  END rw0_rd_out[389]
  PIN rw0_rd_out[390]
    DIRECTION OUTPUT ;
    USE SIGNAL ;
    SHAPE ABUTMENT ;
    PORT
      LAYER M3_m ;
      RECT 0 2028.635 0.07 2028.705 ;
    END
  END rw0_rd_out[390]
  PIN rw0_rd_out[391]
    DIRECTION OUTPUT ;
    USE SIGNAL ;
    SHAPE ABUTMENT ;
    PORT
      LAYER M3_m ;
      RECT 0 2030.735 0.07 2030.805 ;
    END
  END rw0_rd_out[391]
  PIN rw0_rd_out[392]
    DIRECTION OUTPUT ;
    USE SIGNAL ;
    SHAPE ABUTMENT ;
    PORT
      LAYER M3_m ;
      RECT 0 2032.835 0.07 2032.905 ;
    END
  END rw0_rd_out[392]
  PIN rw0_rd_out[393]
    DIRECTION OUTPUT ;
    USE SIGNAL ;
    SHAPE ABUTMENT ;
    PORT
      LAYER M3_m ;
      RECT 0 2034.935 0.07 2035.005 ;
    END
  END rw0_rd_out[393]
  PIN rw0_rd_out[394]
    DIRECTION OUTPUT ;
    USE SIGNAL ;
    SHAPE ABUTMENT ;
    PORT
      LAYER M3_m ;
      RECT 0 2037.035 0.07 2037.105 ;
    END
  END rw0_rd_out[394]
  PIN rw0_rd_out[395]
    DIRECTION OUTPUT ;
    USE SIGNAL ;
    SHAPE ABUTMENT ;
    PORT
      LAYER M3_m ;
      RECT 0 2039.135 0.07 2039.205 ;
    END
  END rw0_rd_out[395]
  PIN rw0_rd_out[396]
    DIRECTION OUTPUT ;
    USE SIGNAL ;
    SHAPE ABUTMENT ;
    PORT
      LAYER M3_m ;
      RECT 0 2041.235 0.07 2041.305 ;
    END
  END rw0_rd_out[396]
  PIN rw0_rd_out[397]
    DIRECTION OUTPUT ;
    USE SIGNAL ;
    SHAPE ABUTMENT ;
    PORT
      LAYER M3_m ;
      RECT 0 2043.335 0.07 2043.405 ;
    END
  END rw0_rd_out[397]
  PIN rw0_rd_out[398]
    DIRECTION OUTPUT ;
    USE SIGNAL ;
    SHAPE ABUTMENT ;
    PORT
      LAYER M3_m ;
      RECT 0 2045.435 0.07 2045.505 ;
    END
  END rw0_rd_out[398]
  PIN rw0_rd_out[399]
    DIRECTION OUTPUT ;
    USE SIGNAL ;
    SHAPE ABUTMENT ;
    PORT
      LAYER M3_m ;
      RECT 0 2047.535 0.07 2047.605 ;
    END
  END rw0_rd_out[399]
  PIN rw0_rd_out[400]
    DIRECTION OUTPUT ;
    USE SIGNAL ;
    SHAPE ABUTMENT ;
    PORT
      LAYER M3_m ;
      RECT 0 2049.635 0.07 2049.705 ;
    END
  END rw0_rd_out[400]
  PIN rw0_rd_out[401]
    DIRECTION OUTPUT ;
    USE SIGNAL ;
    SHAPE ABUTMENT ;
    PORT
      LAYER M3_m ;
      RECT 0 2051.735 0.07 2051.805 ;
    END
  END rw0_rd_out[401]
  PIN rw0_rd_out[402]
    DIRECTION OUTPUT ;
    USE SIGNAL ;
    SHAPE ABUTMENT ;
    PORT
      LAYER M3_m ;
      RECT 0 2053.835 0.07 2053.905 ;
    END
  END rw0_rd_out[402]
  PIN rw0_rd_out[403]
    DIRECTION OUTPUT ;
    USE SIGNAL ;
    SHAPE ABUTMENT ;
    PORT
      LAYER M3_m ;
      RECT 0 2055.935 0.07 2056.005 ;
    END
  END rw0_rd_out[403]
  PIN rw0_rd_out[404]
    DIRECTION OUTPUT ;
    USE SIGNAL ;
    SHAPE ABUTMENT ;
    PORT
      LAYER M3_m ;
      RECT 0 2058.035 0.07 2058.105 ;
    END
  END rw0_rd_out[404]
  PIN rw0_rd_out[405]
    DIRECTION OUTPUT ;
    USE SIGNAL ;
    SHAPE ABUTMENT ;
    PORT
      LAYER M3_m ;
      RECT 0 2060.135 0.07 2060.205 ;
    END
  END rw0_rd_out[405]
  PIN rw0_rd_out[406]
    DIRECTION OUTPUT ;
    USE SIGNAL ;
    SHAPE ABUTMENT ;
    PORT
      LAYER M3_m ;
      RECT 0 2062.235 0.07 2062.305 ;
    END
  END rw0_rd_out[406]
  PIN rw0_rd_out[407]
    DIRECTION OUTPUT ;
    USE SIGNAL ;
    SHAPE ABUTMENT ;
    PORT
      LAYER M3_m ;
      RECT 0 2064.335 0.07 2064.405 ;
    END
  END rw0_rd_out[407]
  PIN rw0_rd_out[408]
    DIRECTION OUTPUT ;
    USE SIGNAL ;
    SHAPE ABUTMENT ;
    PORT
      LAYER M3_m ;
      RECT 0 2066.435 0.07 2066.505 ;
    END
  END rw0_rd_out[408]
  PIN rw0_rd_out[409]
    DIRECTION OUTPUT ;
    USE SIGNAL ;
    SHAPE ABUTMENT ;
    PORT
      LAYER M3_m ;
      RECT 0 2068.535 0.07 2068.605 ;
    END
  END rw0_rd_out[409]
  PIN rw0_rd_out[410]
    DIRECTION OUTPUT ;
    USE SIGNAL ;
    SHAPE ABUTMENT ;
    PORT
      LAYER M3_m ;
      RECT 0 2070.635 0.07 2070.705 ;
    END
  END rw0_rd_out[410]
  PIN rw0_rd_out[411]
    DIRECTION OUTPUT ;
    USE SIGNAL ;
    SHAPE ABUTMENT ;
    PORT
      LAYER M3_m ;
      RECT 0 2072.735 0.07 2072.805 ;
    END
  END rw0_rd_out[411]
  PIN rw0_rd_out[412]
    DIRECTION OUTPUT ;
    USE SIGNAL ;
    SHAPE ABUTMENT ;
    PORT
      LAYER M3_m ;
      RECT 0 2074.835 0.07 2074.905 ;
    END
  END rw0_rd_out[412]
  PIN rw0_rd_out[413]
    DIRECTION OUTPUT ;
    USE SIGNAL ;
    SHAPE ABUTMENT ;
    PORT
      LAYER M3_m ;
      RECT 0 2076.935 0.07 2077.005 ;
    END
  END rw0_rd_out[413]
  PIN rw0_rd_out[414]
    DIRECTION OUTPUT ;
    USE SIGNAL ;
    SHAPE ABUTMENT ;
    PORT
      LAYER M3_m ;
      RECT 0 2079.035 0.07 2079.105 ;
    END
  END rw0_rd_out[414]
  PIN rw0_rd_out[415]
    DIRECTION OUTPUT ;
    USE SIGNAL ;
    SHAPE ABUTMENT ;
    PORT
      LAYER M3_m ;
      RECT 0 2081.135 0.07 2081.205 ;
    END
  END rw0_rd_out[415]
  PIN rw0_rd_out[416]
    DIRECTION OUTPUT ;
    USE SIGNAL ;
    SHAPE ABUTMENT ;
    PORT
      LAYER M3_m ;
      RECT 0 2083.235 0.07 2083.305 ;
    END
  END rw0_rd_out[416]
  PIN rw0_rd_out[417]
    DIRECTION OUTPUT ;
    USE SIGNAL ;
    SHAPE ABUTMENT ;
    PORT
      LAYER M3_m ;
      RECT 0 2085.335 0.07 2085.405 ;
    END
  END rw0_rd_out[417]
  PIN rw0_rd_out[418]
    DIRECTION OUTPUT ;
    USE SIGNAL ;
    SHAPE ABUTMENT ;
    PORT
      LAYER M3_m ;
      RECT 0 2087.435 0.07 2087.505 ;
    END
  END rw0_rd_out[418]
  PIN rw0_rd_out[419]
    DIRECTION OUTPUT ;
    USE SIGNAL ;
    SHAPE ABUTMENT ;
    PORT
      LAYER M3_m ;
      RECT 0 2089.535 0.07 2089.605 ;
    END
  END rw0_rd_out[419]
  PIN rw0_rd_out[420]
    DIRECTION OUTPUT ;
    USE SIGNAL ;
    SHAPE ABUTMENT ;
    PORT
      LAYER M3_m ;
      RECT 0 2091.635 0.07 2091.705 ;
    END
  END rw0_rd_out[420]
  PIN rw0_rd_out[421]
    DIRECTION OUTPUT ;
    USE SIGNAL ;
    SHAPE ABUTMENT ;
    PORT
      LAYER M3_m ;
      RECT 0 2093.735 0.07 2093.805 ;
    END
  END rw0_rd_out[421]
  PIN rw0_rd_out[422]
    DIRECTION OUTPUT ;
    USE SIGNAL ;
    SHAPE ABUTMENT ;
    PORT
      LAYER M3_m ;
      RECT 0 2095.835 0.07 2095.905 ;
    END
  END rw0_rd_out[422]
  PIN rw0_rd_out[423]
    DIRECTION OUTPUT ;
    USE SIGNAL ;
    SHAPE ABUTMENT ;
    PORT
      LAYER M3_m ;
      RECT 0 2097.935 0.07 2098.005 ;
    END
  END rw0_rd_out[423]
  PIN rw0_rd_out[424]
    DIRECTION OUTPUT ;
    USE SIGNAL ;
    SHAPE ABUTMENT ;
    PORT
      LAYER M3_m ;
      RECT 0 2100.035 0.07 2100.105 ;
    END
  END rw0_rd_out[424]
  PIN rw0_rd_out[425]
    DIRECTION OUTPUT ;
    USE SIGNAL ;
    SHAPE ABUTMENT ;
    PORT
      LAYER M3_m ;
      RECT 0 2102.135 0.07 2102.205 ;
    END
  END rw0_rd_out[425]
  PIN rw0_rd_out[426]
    DIRECTION OUTPUT ;
    USE SIGNAL ;
    SHAPE ABUTMENT ;
    PORT
      LAYER M3_m ;
      RECT 0 2104.235 0.07 2104.305 ;
    END
  END rw0_rd_out[426]
  PIN rw0_rd_out[427]
    DIRECTION OUTPUT ;
    USE SIGNAL ;
    SHAPE ABUTMENT ;
    PORT
      LAYER M3_m ;
      RECT 0 2106.335 0.07 2106.405 ;
    END
  END rw0_rd_out[427]
  PIN rw0_rd_out[428]
    DIRECTION OUTPUT ;
    USE SIGNAL ;
    SHAPE ABUTMENT ;
    PORT
      LAYER M3_m ;
      RECT 0 2108.435 0.07 2108.505 ;
    END
  END rw0_rd_out[428]
  PIN rw0_rd_out[429]
    DIRECTION OUTPUT ;
    USE SIGNAL ;
    SHAPE ABUTMENT ;
    PORT
      LAYER M3_m ;
      RECT 0 2110.535 0.07 2110.605 ;
    END
  END rw0_rd_out[429]
  PIN rw0_rd_out[430]
    DIRECTION OUTPUT ;
    USE SIGNAL ;
    SHAPE ABUTMENT ;
    PORT
      LAYER M3_m ;
      RECT 0 2112.635 0.07 2112.705 ;
    END
  END rw0_rd_out[430]
  PIN rw0_rd_out[431]
    DIRECTION OUTPUT ;
    USE SIGNAL ;
    SHAPE ABUTMENT ;
    PORT
      LAYER M3_m ;
      RECT 0 2114.735 0.07 2114.805 ;
    END
  END rw0_rd_out[431]
  PIN rw0_rd_out[432]
    DIRECTION OUTPUT ;
    USE SIGNAL ;
    SHAPE ABUTMENT ;
    PORT
      LAYER M3_m ;
      RECT 0 2116.835 0.07 2116.905 ;
    END
  END rw0_rd_out[432]
  PIN rw0_rd_out[433]
    DIRECTION OUTPUT ;
    USE SIGNAL ;
    SHAPE ABUTMENT ;
    PORT
      LAYER M3_m ;
      RECT 0 2118.935 0.07 2119.005 ;
    END
  END rw0_rd_out[433]
  PIN rw0_rd_out[434]
    DIRECTION OUTPUT ;
    USE SIGNAL ;
    SHAPE ABUTMENT ;
    PORT
      LAYER M3_m ;
      RECT 0 2121.035 0.07 2121.105 ;
    END
  END rw0_rd_out[434]
  PIN rw0_rd_out[435]
    DIRECTION OUTPUT ;
    USE SIGNAL ;
    SHAPE ABUTMENT ;
    PORT
      LAYER M3_m ;
      RECT 0 2123.135 0.07 2123.205 ;
    END
  END rw0_rd_out[435]
  PIN rw0_rd_out[436]
    DIRECTION OUTPUT ;
    USE SIGNAL ;
    SHAPE ABUTMENT ;
    PORT
      LAYER M3_m ;
      RECT 0 2125.235 0.07 2125.305 ;
    END
  END rw0_rd_out[436]
  PIN rw0_rd_out[437]
    DIRECTION OUTPUT ;
    USE SIGNAL ;
    SHAPE ABUTMENT ;
    PORT
      LAYER M3_m ;
      RECT 0 2127.335 0.07 2127.405 ;
    END
  END rw0_rd_out[437]
  PIN rw0_rd_out[438]
    DIRECTION OUTPUT ;
    USE SIGNAL ;
    SHAPE ABUTMENT ;
    PORT
      LAYER M3_m ;
      RECT 0 2129.435 0.07 2129.505 ;
    END
  END rw0_rd_out[438]
  PIN rw0_rd_out[439]
    DIRECTION OUTPUT ;
    USE SIGNAL ;
    SHAPE ABUTMENT ;
    PORT
      LAYER M3_m ;
      RECT 0 2131.535 0.07 2131.605 ;
    END
  END rw0_rd_out[439]
  PIN rw0_rd_out[440]
    DIRECTION OUTPUT ;
    USE SIGNAL ;
    SHAPE ABUTMENT ;
    PORT
      LAYER M3_m ;
      RECT 0 2133.635 0.07 2133.705 ;
    END
  END rw0_rd_out[440]
  PIN rw0_rd_out[441]
    DIRECTION OUTPUT ;
    USE SIGNAL ;
    SHAPE ABUTMENT ;
    PORT
      LAYER M3_m ;
      RECT 0 2135.735 0.07 2135.805 ;
    END
  END rw0_rd_out[441]
  PIN rw0_rd_out[442]
    DIRECTION OUTPUT ;
    USE SIGNAL ;
    SHAPE ABUTMENT ;
    PORT
      LAYER M3_m ;
      RECT 0 2137.835 0.07 2137.905 ;
    END
  END rw0_rd_out[442]
  PIN rw0_rd_out[443]
    DIRECTION OUTPUT ;
    USE SIGNAL ;
    SHAPE ABUTMENT ;
    PORT
      LAYER M3_m ;
      RECT 0 2139.935 0.07 2140.005 ;
    END
  END rw0_rd_out[443]
  PIN rw0_rd_out[444]
    DIRECTION OUTPUT ;
    USE SIGNAL ;
    SHAPE ABUTMENT ;
    PORT
      LAYER M3_m ;
      RECT 0 2142.035 0.07 2142.105 ;
    END
  END rw0_rd_out[444]
  PIN rw0_rd_out[445]
    DIRECTION OUTPUT ;
    USE SIGNAL ;
    SHAPE ABUTMENT ;
    PORT
      LAYER M3_m ;
      RECT 0 2144.135 0.07 2144.205 ;
    END
  END rw0_rd_out[445]
  PIN rw0_rd_out[446]
    DIRECTION OUTPUT ;
    USE SIGNAL ;
    SHAPE ABUTMENT ;
    PORT
      LAYER M3_m ;
      RECT 0 2146.235 0.07 2146.305 ;
    END
  END rw0_rd_out[446]
  PIN rw0_rd_out[447]
    DIRECTION OUTPUT ;
    USE SIGNAL ;
    SHAPE ABUTMENT ;
    PORT
      LAYER M3_m ;
      RECT 0 2148.335 0.07 2148.405 ;
    END
  END rw0_rd_out[447]
  PIN rw0_rd_out[448]
    DIRECTION OUTPUT ;
    USE SIGNAL ;
    SHAPE ABUTMENT ;
    PORT
      LAYER M3_m ;
      RECT 0 2150.435 0.07 2150.505 ;
    END
  END rw0_rd_out[448]
  PIN rw0_rd_out[449]
    DIRECTION OUTPUT ;
    USE SIGNAL ;
    SHAPE ABUTMENT ;
    PORT
      LAYER M3_m ;
      RECT 0 2152.535 0.07 2152.605 ;
    END
  END rw0_rd_out[449]
  PIN rw0_rd_out[450]
    DIRECTION OUTPUT ;
    USE SIGNAL ;
    SHAPE ABUTMENT ;
    PORT
      LAYER M3_m ;
      RECT 0 2154.635 0.07 2154.705 ;
    END
  END rw0_rd_out[450]
  PIN rw0_rd_out[451]
    DIRECTION OUTPUT ;
    USE SIGNAL ;
    SHAPE ABUTMENT ;
    PORT
      LAYER M3_m ;
      RECT 0 2156.735 0.07 2156.805 ;
    END
  END rw0_rd_out[451]
  PIN rw0_rd_out[452]
    DIRECTION OUTPUT ;
    USE SIGNAL ;
    SHAPE ABUTMENT ;
    PORT
      LAYER M3_m ;
      RECT 0 2158.835 0.07 2158.905 ;
    END
  END rw0_rd_out[452]
  PIN rw0_rd_out[453]
    DIRECTION OUTPUT ;
    USE SIGNAL ;
    SHAPE ABUTMENT ;
    PORT
      LAYER M3_m ;
      RECT 0 2160.935 0.07 2161.005 ;
    END
  END rw0_rd_out[453]
  PIN rw0_rd_out[454]
    DIRECTION OUTPUT ;
    USE SIGNAL ;
    SHAPE ABUTMENT ;
    PORT
      LAYER M3_m ;
      RECT 0 2163.035 0.07 2163.105 ;
    END
  END rw0_rd_out[454]
  PIN rw0_rd_out[455]
    DIRECTION OUTPUT ;
    USE SIGNAL ;
    SHAPE ABUTMENT ;
    PORT
      LAYER M3_m ;
      RECT 0 2165.135 0.07 2165.205 ;
    END
  END rw0_rd_out[455]
  PIN rw0_rd_out[456]
    DIRECTION OUTPUT ;
    USE SIGNAL ;
    SHAPE ABUTMENT ;
    PORT
      LAYER M3_m ;
      RECT 0 2167.235 0.07 2167.305 ;
    END
  END rw0_rd_out[456]
  PIN rw0_rd_out[457]
    DIRECTION OUTPUT ;
    USE SIGNAL ;
    SHAPE ABUTMENT ;
    PORT
      LAYER M3_m ;
      RECT 0 2169.335 0.07 2169.405 ;
    END
  END rw0_rd_out[457]
  PIN rw0_rd_out[458]
    DIRECTION OUTPUT ;
    USE SIGNAL ;
    SHAPE ABUTMENT ;
    PORT
      LAYER M3_m ;
      RECT 0 2171.435 0.07 2171.505 ;
    END
  END rw0_rd_out[458]
  PIN rw0_rd_out[459]
    DIRECTION OUTPUT ;
    USE SIGNAL ;
    SHAPE ABUTMENT ;
    PORT
      LAYER M3_m ;
      RECT 0 2173.535 0.07 2173.605 ;
    END
  END rw0_rd_out[459]
  PIN rw0_rd_out[460]
    DIRECTION OUTPUT ;
    USE SIGNAL ;
    SHAPE ABUTMENT ;
    PORT
      LAYER M3_m ;
      RECT 0 2175.635 0.07 2175.705 ;
    END
  END rw0_rd_out[460]
  PIN rw0_rd_out[461]
    DIRECTION OUTPUT ;
    USE SIGNAL ;
    SHAPE ABUTMENT ;
    PORT
      LAYER M3_m ;
      RECT 0 2177.735 0.07 2177.805 ;
    END
  END rw0_rd_out[461]
  PIN rw0_rd_out[462]
    DIRECTION OUTPUT ;
    USE SIGNAL ;
    SHAPE ABUTMENT ;
    PORT
      LAYER M3_m ;
      RECT 0 2179.835 0.07 2179.905 ;
    END
  END rw0_rd_out[462]
  PIN rw0_rd_out[463]
    DIRECTION OUTPUT ;
    USE SIGNAL ;
    SHAPE ABUTMENT ;
    PORT
      LAYER M3_m ;
      RECT 0 2181.935 0.07 2182.005 ;
    END
  END rw0_rd_out[463]
  PIN rw0_rd_out[464]
    DIRECTION OUTPUT ;
    USE SIGNAL ;
    SHAPE ABUTMENT ;
    PORT
      LAYER M3_m ;
      RECT 0 2184.035 0.07 2184.105 ;
    END
  END rw0_rd_out[464]
  PIN rw0_rd_out[465]
    DIRECTION OUTPUT ;
    USE SIGNAL ;
    SHAPE ABUTMENT ;
    PORT
      LAYER M3_m ;
      RECT 0 2186.135 0.07 2186.205 ;
    END
  END rw0_rd_out[465]
  PIN rw0_rd_out[466]
    DIRECTION OUTPUT ;
    USE SIGNAL ;
    SHAPE ABUTMENT ;
    PORT
      LAYER M3_m ;
      RECT 0 2188.235 0.07 2188.305 ;
    END
  END rw0_rd_out[466]
  PIN rw0_rd_out[467]
    DIRECTION OUTPUT ;
    USE SIGNAL ;
    SHAPE ABUTMENT ;
    PORT
      LAYER M3_m ;
      RECT 0 2190.335 0.07 2190.405 ;
    END
  END rw0_rd_out[467]
  PIN rw0_rd_out[468]
    DIRECTION OUTPUT ;
    USE SIGNAL ;
    SHAPE ABUTMENT ;
    PORT
      LAYER M3_m ;
      RECT 0 2192.435 0.07 2192.505 ;
    END
  END rw0_rd_out[468]
  PIN rw0_rd_out[469]
    DIRECTION OUTPUT ;
    USE SIGNAL ;
    SHAPE ABUTMENT ;
    PORT
      LAYER M3_m ;
      RECT 0 2194.535 0.07 2194.605 ;
    END
  END rw0_rd_out[469]
  PIN rw0_rd_out[470]
    DIRECTION OUTPUT ;
    USE SIGNAL ;
    SHAPE ABUTMENT ;
    PORT
      LAYER M3_m ;
      RECT 0 2196.635 0.07 2196.705 ;
    END
  END rw0_rd_out[470]
  PIN rw0_rd_out[471]
    DIRECTION OUTPUT ;
    USE SIGNAL ;
    SHAPE ABUTMENT ;
    PORT
      LAYER M3_m ;
      RECT 0 2198.735 0.07 2198.805 ;
    END
  END rw0_rd_out[471]
  PIN rw0_rd_out[472]
    DIRECTION OUTPUT ;
    USE SIGNAL ;
    SHAPE ABUTMENT ;
    PORT
      LAYER M3_m ;
      RECT 0 2200.835 0.07 2200.905 ;
    END
  END rw0_rd_out[472]
  PIN rw0_rd_out[473]
    DIRECTION OUTPUT ;
    USE SIGNAL ;
    SHAPE ABUTMENT ;
    PORT
      LAYER M3_m ;
      RECT 0 2202.935 0.07 2203.005 ;
    END
  END rw0_rd_out[473]
  PIN rw0_rd_out[474]
    DIRECTION OUTPUT ;
    USE SIGNAL ;
    SHAPE ABUTMENT ;
    PORT
      LAYER M3_m ;
      RECT 0 2205.035 0.07 2205.105 ;
    END
  END rw0_rd_out[474]
  PIN rw0_rd_out[475]
    DIRECTION OUTPUT ;
    USE SIGNAL ;
    SHAPE ABUTMENT ;
    PORT
      LAYER M3_m ;
      RECT 0 2207.135 0.07 2207.205 ;
    END
  END rw0_rd_out[475]
  PIN rw0_rd_out[476]
    DIRECTION OUTPUT ;
    USE SIGNAL ;
    SHAPE ABUTMENT ;
    PORT
      LAYER M3_m ;
      RECT 0 2209.235 0.07 2209.305 ;
    END
  END rw0_rd_out[476]
  PIN rw0_rd_out[477]
    DIRECTION OUTPUT ;
    USE SIGNAL ;
    SHAPE ABUTMENT ;
    PORT
      LAYER M3_m ;
      RECT 0 2211.335 0.07 2211.405 ;
    END
  END rw0_rd_out[477]
  PIN rw0_rd_out[478]
    DIRECTION OUTPUT ;
    USE SIGNAL ;
    SHAPE ABUTMENT ;
    PORT
      LAYER M3_m ;
      RECT 0 2213.435 0.07 2213.505 ;
    END
  END rw0_rd_out[478]
  PIN rw0_rd_out[479]
    DIRECTION OUTPUT ;
    USE SIGNAL ;
    SHAPE ABUTMENT ;
    PORT
      LAYER M3_m ;
      RECT 0 2215.535 0.07 2215.605 ;
    END
  END rw0_rd_out[479]
  PIN rw0_rd_out[480]
    DIRECTION OUTPUT ;
    USE SIGNAL ;
    SHAPE ABUTMENT ;
    PORT
      LAYER M3_m ;
      RECT 0 2217.635 0.07 2217.705 ;
    END
  END rw0_rd_out[480]
  PIN rw0_rd_out[481]
    DIRECTION OUTPUT ;
    USE SIGNAL ;
    SHAPE ABUTMENT ;
    PORT
      LAYER M3_m ;
      RECT 0 2219.735 0.07 2219.805 ;
    END
  END rw0_rd_out[481]
  PIN rw0_rd_out[482]
    DIRECTION OUTPUT ;
    USE SIGNAL ;
    SHAPE ABUTMENT ;
    PORT
      LAYER M3_m ;
      RECT 0 2221.835 0.07 2221.905 ;
    END
  END rw0_rd_out[482]
  PIN rw0_rd_out[483]
    DIRECTION OUTPUT ;
    USE SIGNAL ;
    SHAPE ABUTMENT ;
    PORT
      LAYER M3_m ;
      RECT 0 2223.935 0.07 2224.005 ;
    END
  END rw0_rd_out[483]
  PIN rw0_rd_out[484]
    DIRECTION OUTPUT ;
    USE SIGNAL ;
    SHAPE ABUTMENT ;
    PORT
      LAYER M3_m ;
      RECT 0 2226.035 0.07 2226.105 ;
    END
  END rw0_rd_out[484]
  PIN rw0_rd_out[485]
    DIRECTION OUTPUT ;
    USE SIGNAL ;
    SHAPE ABUTMENT ;
    PORT
      LAYER M3_m ;
      RECT 0 2228.135 0.07 2228.205 ;
    END
  END rw0_rd_out[485]
  PIN rw0_rd_out[486]
    DIRECTION OUTPUT ;
    USE SIGNAL ;
    SHAPE ABUTMENT ;
    PORT
      LAYER M3_m ;
      RECT 0 2230.235 0.07 2230.305 ;
    END
  END rw0_rd_out[486]
  PIN rw0_rd_out[487]
    DIRECTION OUTPUT ;
    USE SIGNAL ;
    SHAPE ABUTMENT ;
    PORT
      LAYER M3_m ;
      RECT 0 2232.335 0.07 2232.405 ;
    END
  END rw0_rd_out[487]
  PIN rw0_rd_out[488]
    DIRECTION OUTPUT ;
    USE SIGNAL ;
    SHAPE ABUTMENT ;
    PORT
      LAYER M3_m ;
      RECT 0 2234.435 0.07 2234.505 ;
    END
  END rw0_rd_out[488]
  PIN rw0_rd_out[489]
    DIRECTION OUTPUT ;
    USE SIGNAL ;
    SHAPE ABUTMENT ;
    PORT
      LAYER M3_m ;
      RECT 0 2236.535 0.07 2236.605 ;
    END
  END rw0_rd_out[489]
  PIN rw0_rd_out[490]
    DIRECTION OUTPUT ;
    USE SIGNAL ;
    SHAPE ABUTMENT ;
    PORT
      LAYER M3_m ;
      RECT 0 2238.635 0.07 2238.705 ;
    END
  END rw0_rd_out[490]
  PIN rw0_rd_out[491]
    DIRECTION OUTPUT ;
    USE SIGNAL ;
    SHAPE ABUTMENT ;
    PORT
      LAYER M3_m ;
      RECT 0 2240.735 0.07 2240.805 ;
    END
  END rw0_rd_out[491]
  PIN rw0_rd_out[492]
    DIRECTION OUTPUT ;
    USE SIGNAL ;
    SHAPE ABUTMENT ;
    PORT
      LAYER M3_m ;
      RECT 0 2242.835 0.07 2242.905 ;
    END
  END rw0_rd_out[492]
  PIN rw0_rd_out[493]
    DIRECTION OUTPUT ;
    USE SIGNAL ;
    SHAPE ABUTMENT ;
    PORT
      LAYER M3_m ;
      RECT 0 2244.935 0.07 2245.005 ;
    END
  END rw0_rd_out[493]
  PIN rw0_rd_out[494]
    DIRECTION OUTPUT ;
    USE SIGNAL ;
    SHAPE ABUTMENT ;
    PORT
      LAYER M3_m ;
      RECT 0 2247.035 0.07 2247.105 ;
    END
  END rw0_rd_out[494]
  PIN rw0_rd_out[495]
    DIRECTION OUTPUT ;
    USE SIGNAL ;
    SHAPE ABUTMENT ;
    PORT
      LAYER M3_m ;
      RECT 0 2249.135 0.07 2249.205 ;
    END
  END rw0_rd_out[495]
  PIN rw0_rd_out[496]
    DIRECTION OUTPUT ;
    USE SIGNAL ;
    SHAPE ABUTMENT ;
    PORT
      LAYER M3_m ;
      RECT 0 2251.235 0.07 2251.305 ;
    END
  END rw0_rd_out[496]
  PIN rw0_rd_out[497]
    DIRECTION OUTPUT ;
    USE SIGNAL ;
    SHAPE ABUTMENT ;
    PORT
      LAYER M3_m ;
      RECT 0 2253.335 0.07 2253.405 ;
    END
  END rw0_rd_out[497]
  PIN rw0_rd_out[498]
    DIRECTION OUTPUT ;
    USE SIGNAL ;
    SHAPE ABUTMENT ;
    PORT
      LAYER M3_m ;
      RECT 0 2255.435 0.07 2255.505 ;
    END
  END rw0_rd_out[498]
  PIN rw0_rd_out[499]
    DIRECTION OUTPUT ;
    USE SIGNAL ;
    SHAPE ABUTMENT ;
    PORT
      LAYER M3_m ;
      RECT 0 2257.535 0.07 2257.605 ;
    END
  END rw0_rd_out[499]
  PIN rw0_rd_out[500]
    DIRECTION OUTPUT ;
    USE SIGNAL ;
    SHAPE ABUTMENT ;
    PORT
      LAYER M3_m ;
      RECT 0 2259.635 0.07 2259.705 ;
    END
  END rw0_rd_out[500]
  PIN rw0_rd_out[501]
    DIRECTION OUTPUT ;
    USE SIGNAL ;
    SHAPE ABUTMENT ;
    PORT
      LAYER M3_m ;
      RECT 0 2261.735 0.07 2261.805 ;
    END
  END rw0_rd_out[501]
  PIN rw0_rd_out[502]
    DIRECTION OUTPUT ;
    USE SIGNAL ;
    SHAPE ABUTMENT ;
    PORT
      LAYER M3_m ;
      RECT 0 2263.835 0.07 2263.905 ;
    END
  END rw0_rd_out[502]
  PIN rw0_rd_out[503]
    DIRECTION OUTPUT ;
    USE SIGNAL ;
    SHAPE ABUTMENT ;
    PORT
      LAYER M3_m ;
      RECT 0 2265.935 0.07 2266.005 ;
    END
  END rw0_rd_out[503]
  PIN rw0_rd_out[504]
    DIRECTION OUTPUT ;
    USE SIGNAL ;
    SHAPE ABUTMENT ;
    PORT
      LAYER M3_m ;
      RECT 0 2268.035 0.07 2268.105 ;
    END
  END rw0_rd_out[504]
  PIN rw0_rd_out[505]
    DIRECTION OUTPUT ;
    USE SIGNAL ;
    SHAPE ABUTMENT ;
    PORT
      LAYER M3_m ;
      RECT 0 2270.135 0.07 2270.205 ;
    END
  END rw0_rd_out[505]
  PIN rw0_rd_out[506]
    DIRECTION OUTPUT ;
    USE SIGNAL ;
    SHAPE ABUTMENT ;
    PORT
      LAYER M3_m ;
      RECT 0 2272.235 0.07 2272.305 ;
    END
  END rw0_rd_out[506]
  PIN rw0_rd_out[507]
    DIRECTION OUTPUT ;
    USE SIGNAL ;
    SHAPE ABUTMENT ;
    PORT
      LAYER M3_m ;
      RECT 0 2274.335 0.07 2274.405 ;
    END
  END rw0_rd_out[507]
  PIN rw0_rd_out[508]
    DIRECTION OUTPUT ;
    USE SIGNAL ;
    SHAPE ABUTMENT ;
    PORT
      LAYER M3_m ;
      RECT 0 2276.435 0.07 2276.505 ;
    END
  END rw0_rd_out[508]
  PIN rw0_rd_out[509]
    DIRECTION OUTPUT ;
    USE SIGNAL ;
    SHAPE ABUTMENT ;
    PORT
      LAYER M3_m ;
      RECT 0 2278.535 0.07 2278.605 ;
    END
  END rw0_rd_out[509]
  PIN rw0_rd_out[510]
    DIRECTION OUTPUT ;
    USE SIGNAL ;
    SHAPE ABUTMENT ;
    PORT
      LAYER M3_m ;
      RECT 0 2280.635 0.07 2280.705 ;
    END
  END rw0_rd_out[510]
  PIN rw0_rd_out[511]
    DIRECTION OUTPUT ;
    USE SIGNAL ;
    SHAPE ABUTMENT ;
    PORT
      LAYER M3_m ;
      RECT 0 2282.735 0.07 2282.805 ;
    END
  END rw0_rd_out[511]
  PIN rw0_addr_in[0]
    DIRECTION INPUT ;
    USE SIGNAL ;
    SHAPE ABUTMENT ;
    PORT
      LAYER M3_m ;
      RECT 0 2284.835 0.07 2284.905 ;
    END
  END rw0_addr_in[0]
  PIN rw0_addr_in[1]
    DIRECTION INPUT ;
    USE SIGNAL ;
    SHAPE ABUTMENT ;
    PORT
      LAYER M3_m ;
      RECT 0 2286.935 0.07 2287.005 ;
    END
  END rw0_addr_in[1]
  PIN rw0_addr_in[2]
    DIRECTION INPUT ;
    USE SIGNAL ;
    SHAPE ABUTMENT ;
    PORT
      LAYER M3_m ;
      RECT 0 2289.035 0.07 2289.105 ;
    END
  END rw0_addr_in[2]
  PIN rw0_addr_in[3]
    DIRECTION INPUT ;
    USE SIGNAL ;
    SHAPE ABUTMENT ;
    PORT
      LAYER M3_m ;
      RECT 0 2291.135 0.07 2291.205 ;
    END
  END rw0_addr_in[3]
  PIN rw0_addr_in[4]
    DIRECTION INPUT ;
    USE SIGNAL ;
    SHAPE ABUTMENT ;
    PORT
      LAYER M3_m ;
      RECT 0 2293.235 0.07 2293.305 ;
    END
  END rw0_addr_in[4]
  PIN rw0_addr_in[5]
    DIRECTION INPUT ;
    USE SIGNAL ;
    SHAPE ABUTMENT ;
    PORT
      LAYER M3_m ;
      RECT 0 2295.335 0.07 2295.405 ;
    END
  END rw0_addr_in[5]
  PIN rw0_addr_in[6]
    DIRECTION INPUT ;
    USE SIGNAL ;
    SHAPE ABUTMENT ;
    PORT
      LAYER M3_m ;
      RECT 0 2297.435 0.07 2297.505 ;
    END
  END rw0_addr_in[6]
  PIN rw0_addr_in[7]
    DIRECTION INPUT ;
    USE SIGNAL ;
    SHAPE ABUTMENT ;
    PORT
      LAYER M3_m ;
      RECT 0 2299.535 0.07 2299.605 ;
    END
  END rw0_addr_in[7]
  PIN rw0_addr_in[8]
    DIRECTION INPUT ;
    USE SIGNAL ;
    SHAPE ABUTMENT ;
    PORT
      LAYER M3_m ;
      RECT 0 2301.635 0.07 2301.705 ;
    END
  END rw0_addr_in[8]
  PIN rw0_addr_in[9]
    DIRECTION INPUT ;
    USE SIGNAL ;
    SHAPE ABUTMENT ;
    PORT
      LAYER M3_m ;
      RECT 0 2303.735 0.07 2303.805 ;
    END
  END rw0_addr_in[9]
  PIN rw0_addr_in[10]
    DIRECTION INPUT ;
    USE SIGNAL ;
    SHAPE ABUTMENT ;
    PORT
      LAYER M3_m ;
      RECT 0 2305.835 0.07 2305.905 ;
    END
  END rw0_addr_in[10]
  PIN rw0_addr_in[11]
    DIRECTION INPUT ;
    USE SIGNAL ;
    SHAPE ABUTMENT ;
    PORT
      LAYER M3_m ;
      RECT 0 2307.935 0.07 2308.005 ;
    END
  END rw0_addr_in[11]
  PIN rw0_addr_in[12]
    DIRECTION INPUT ;
    USE SIGNAL ;
    SHAPE ABUTMENT ;
    PORT
      LAYER M3_m ;
      RECT 0 2310.035 0.07 2310.105 ;
    END
  END rw0_addr_in[12]
  PIN rw0_addr_in[13]
    DIRECTION INPUT ;
    USE SIGNAL ;
    SHAPE ABUTMENT ;
    PORT
      LAYER M3_m ;
      RECT 0 2312.135 0.07 2312.205 ;
    END
  END rw0_addr_in[13]
  PIN rw0_we_in
    DIRECTION INPUT ;
    USE SIGNAL ;
    SHAPE ABUTMENT ;
    PORT
      LAYER M3_m ;
      RECT 0 2314.235 0.07 2314.305 ;
    END
  END rw0_we_in
  PIN rw0_ce_in
    DIRECTION INPUT ;
    USE SIGNAL ;
    SHAPE ABUTMENT ;
    PORT
      LAYER M3_m ;
      RECT 0 2316.335 0.07 2316.405 ;
    END
  END rw0_ce_in
  PIN rw0_clk
    DIRECTION INPUT ;
    USE SIGNAL ;
    SHAPE ABUTMENT ;
    PORT
      LAYER M3_m ;
      RECT 0 2318.435 0.07 2318.505 ;
    END
  END rw0_clk
  PIN VSS
    DIRECTION INOUT ;
    USE GROUND ;
    PORT
      LAYER M4_m ;
      RECT 1 0.84 1.28 2321.76 ;
      RECT 3.24 0.84 3.52 2321.76 ;
      RECT 5.48 0.84 5.76 2321.76 ;
      RECT 7.72 0.84 8 2321.76 ;
      RECT 9.96 0.84 10.24 2321.76 ;
      RECT 12.2 0.84 12.48 2321.76 ;
      RECT 14.44 0.84 14.72 2321.76 ;
      RECT 16.68 0.84 16.96 2321.76 ;
      RECT 18.92 0.84 19.2 2321.76 ;
      RECT 21.16 0.84 21.44 2321.76 ;
      RECT 23.4 0.84 23.68 2321.76 ;
      RECT 25.64 0.84 25.92 2321.76 ;
      RECT 27.88 0.84 28.16 2321.76 ;
      RECT 30.12 0.84 30.4 2321.76 ;
      RECT 32.36 0.84 32.64 2321.76 ;
      RECT 34.6 0.84 34.88 2321.76 ;
      RECT 36.84 0.84 37.12 2321.76 ;
      RECT 39.08 0.84 39.36 2321.76 ;
      RECT 41.32 0.84 41.6 2321.76 ;
      RECT 43.56 0.84 43.84 2321.76 ;
      RECT 45.8 0.84 46.08 2321.76 ;
      RECT 48.04 0.84 48.32 2321.76 ;
      RECT 50.28 0.84 50.56 2321.76 ;
      RECT 52.52 0.84 52.8 2321.76 ;
      RECT 54.76 0.84 55.04 2321.76 ;
      RECT 57 0.84 57.28 2321.76 ;
      RECT 59.24 0.84 59.52 2321.76 ;
      RECT 61.48 0.84 61.76 2321.76 ;
      RECT 63.72 0.84 64 2321.76 ;
      RECT 65.96 0.84 66.24 2321.76 ;
      RECT 68.2 0.84 68.48 2321.76 ;
      RECT 70.44 0.84 70.72 2321.76 ;
      RECT 72.68 0.84 72.96 2321.76 ;
      RECT 74.92 0.84 75.2 2321.76 ;
      RECT 77.16 0.84 77.44 2321.76 ;
      RECT 79.4 0.84 79.68 2321.76 ;
      RECT 81.64 0.84 81.92 2321.76 ;
      RECT 83.88 0.84 84.16 2321.76 ;
      RECT 86.12 0.84 86.4 2321.76 ;
      RECT 88.36 0.84 88.64 2321.76 ;
      RECT 90.6 0.84 90.88 2321.76 ;
      RECT 92.84 0.84 93.12 2321.76 ;
      RECT 95.08 0.84 95.36 2321.76 ;
      RECT 97.32 0.84 97.6 2321.76 ;
      RECT 99.56 0.84 99.84 2321.76 ;
      RECT 101.8 0.84 102.08 2321.76 ;
      RECT 104.04 0.84 104.32 2321.76 ;
      RECT 106.28 0.84 106.56 2321.76 ;
      RECT 108.52 0.84 108.8 2321.76 ;
      RECT 110.76 0.84 111.04 2321.76 ;
      RECT 113 0.84 113.28 2321.76 ;
      RECT 115.24 0.84 115.52 2321.76 ;
      RECT 117.48 0.84 117.76 2321.76 ;
      RECT 119.72 0.84 120 2321.76 ;
      RECT 121.96 0.84 122.24 2321.76 ;
      RECT 124.2 0.84 124.48 2321.76 ;
      RECT 126.44 0.84 126.72 2321.76 ;
      RECT 128.68 0.84 128.96 2321.76 ;
      RECT 130.92 0.84 131.2 2321.76 ;
      RECT 133.16 0.84 133.44 2321.76 ;
      RECT 135.4 0.84 135.68 2321.76 ;
      RECT 137.64 0.84 137.92 2321.76 ;
      RECT 139.88 0.84 140.16 2321.76 ;
      RECT 142.12 0.84 142.4 2321.76 ;
      RECT 144.36 0.84 144.64 2321.76 ;
      RECT 146.6 0.84 146.88 2321.76 ;
      RECT 148.84 0.84 149.12 2321.76 ;
      RECT 151.08 0.84 151.36 2321.76 ;
      RECT 153.32 0.84 153.6 2321.76 ;
      RECT 155.56 0.84 155.84 2321.76 ;
      RECT 157.8 0.84 158.08 2321.76 ;
      RECT 160.04 0.84 160.32 2321.76 ;
      RECT 162.28 0.84 162.56 2321.76 ;
      RECT 164.52 0.84 164.8 2321.76 ;
      RECT 166.76 0.84 167.04 2321.76 ;
      RECT 169 0.84 169.28 2321.76 ;
      RECT 171.24 0.84 171.52 2321.76 ;
      RECT 173.48 0.84 173.76 2321.76 ;
      RECT 175.72 0.84 176 2321.76 ;
      RECT 177.96 0.84 178.24 2321.76 ;
      RECT 180.2 0.84 180.48 2321.76 ;
      RECT 182.44 0.84 182.72 2321.76 ;
      RECT 184.68 0.84 184.96 2321.76 ;
      RECT 186.92 0.84 187.2 2321.76 ;
      RECT 189.16 0.84 189.44 2321.76 ;
      RECT 191.4 0.84 191.68 2321.76 ;
      RECT 193.64 0.84 193.92 2321.76 ;
      RECT 195.88 0.84 196.16 2321.76 ;
      RECT 198.12 0.84 198.4 2321.76 ;
      RECT 200.36 0.84 200.64 2321.76 ;
      RECT 202.6 0.84 202.88 2321.76 ;
      RECT 204.84 0.84 205.12 2321.76 ;
      RECT 207.08 0.84 207.36 2321.76 ;
      RECT 209.32 0.84 209.6 2321.76 ;
      RECT 211.56 0.84 211.84 2321.76 ;
      RECT 213.8 0.84 214.08 2321.76 ;
      RECT 216.04 0.84 216.32 2321.76 ;
      RECT 218.28 0.84 218.56 2321.76 ;
      RECT 220.52 0.84 220.8 2321.76 ;
      RECT 222.76 0.84 223.04 2321.76 ;
      RECT 225 0.84 225.28 2321.76 ;
      RECT 227.24 0.84 227.52 2321.76 ;
      RECT 229.48 0.84 229.76 2321.76 ;
      RECT 231.72 0.84 232 2321.76 ;
      RECT 233.96 0.84 234.24 2321.76 ;
      RECT 236.2 0.84 236.48 2321.76 ;
      RECT 238.44 0.84 238.72 2321.76 ;
      RECT 240.68 0.84 240.96 2321.76 ;
      RECT 242.92 0.84 243.2 2321.76 ;
      RECT 245.16 0.84 245.44 2321.76 ;
      RECT 247.4 0.84 247.68 2321.76 ;
      RECT 249.64 0.84 249.92 2321.76 ;
      RECT 251.88 0.84 252.16 2321.76 ;
      RECT 254.12 0.84 254.4 2321.76 ;
      RECT 256.36 0.84 256.64 2321.76 ;
      RECT 258.6 0.84 258.88 2321.76 ;
      RECT 260.84 0.84 261.12 2321.76 ;
      RECT 263.08 0.84 263.36 2321.76 ;
      RECT 265.32 0.84 265.6 2321.76 ;
      RECT 267.56 0.84 267.84 2321.76 ;
      RECT 269.8 0.84 270.08 2321.76 ;
      RECT 272.04 0.84 272.32 2321.76 ;
      RECT 274.28 0.84 274.56 2321.76 ;
      RECT 276.52 0.84 276.8 2321.76 ;
      RECT 278.76 0.84 279.04 2321.76 ;
      RECT 281 0.84 281.28 2321.76 ;
      RECT 283.24 0.84 283.52 2321.76 ;
      RECT 285.48 0.84 285.76 2321.76 ;
      RECT 287.72 0.84 288 2321.76 ;
      RECT 289.96 0.84 290.24 2321.76 ;
      RECT 292.2 0.84 292.48 2321.76 ;
      RECT 294.44 0.84 294.72 2321.76 ;
      RECT 296.68 0.84 296.96 2321.76 ;
      RECT 298.92 0.84 299.2 2321.76 ;
      RECT 301.16 0.84 301.44 2321.76 ;
      RECT 303.4 0.84 303.68 2321.76 ;
      RECT 305.64 0.84 305.92 2321.76 ;
      RECT 307.88 0.84 308.16 2321.76 ;
      RECT 310.12 0.84 310.4 2321.76 ;
      RECT 312.36 0.84 312.64 2321.76 ;
      RECT 314.6 0.84 314.88 2321.76 ;
      RECT 316.84 0.84 317.12 2321.76 ;
      RECT 319.08 0.84 319.36 2321.76 ;
      RECT 321.32 0.84 321.6 2321.76 ;
      RECT 323.56 0.84 323.84 2321.76 ;
      RECT 325.8 0.84 326.08 2321.76 ;
      RECT 328.04 0.84 328.32 2321.76 ;
      RECT 330.28 0.84 330.56 2321.76 ;
      RECT 332.52 0.84 332.8 2321.76 ;
      RECT 334.76 0.84 335.04 2321.76 ;
      RECT 337 0.84 337.28 2321.76 ;
      RECT 339.24 0.84 339.52 2321.76 ;
      RECT 341.48 0.84 341.76 2321.76 ;
      RECT 343.72 0.84 344 2321.76 ;
      RECT 345.96 0.84 346.24 2321.76 ;
      RECT 348.2 0.84 348.48 2321.76 ;
      RECT 350.44 0.84 350.72 2321.76 ;
      RECT 352.68 0.84 352.96 2321.76 ;
      RECT 354.92 0.84 355.2 2321.76 ;
      RECT 357.16 0.84 357.44 2321.76 ;
      RECT 359.4 0.84 359.68 2321.76 ;
      RECT 361.64 0.84 361.92 2321.76 ;
      RECT 363.88 0.84 364.16 2321.76 ;
      RECT 366.12 0.84 366.4 2321.76 ;
      RECT 368.36 0.84 368.64 2321.76 ;
      RECT 370.6 0.84 370.88 2321.76 ;
      RECT 372.84 0.84 373.12 2321.76 ;
      RECT 375.08 0.84 375.36 2321.76 ;
      RECT 377.32 0.84 377.6 2321.76 ;
      RECT 379.56 0.84 379.84 2321.76 ;
      RECT 381.8 0.84 382.08 2321.76 ;
      RECT 384.04 0.84 384.32 2321.76 ;
      RECT 386.28 0.84 386.56 2321.76 ;
      RECT 388.52 0.84 388.8 2321.76 ;
      RECT 390.76 0.84 391.04 2321.76 ;
      RECT 393 0.84 393.28 2321.76 ;
      RECT 395.24 0.84 395.52 2321.76 ;
      RECT 397.48 0.84 397.76 2321.76 ;
      RECT 399.72 0.84 400 2321.76 ;
      RECT 401.96 0.84 402.24 2321.76 ;
      RECT 404.2 0.84 404.48 2321.76 ;
      RECT 406.44 0.84 406.72 2321.76 ;
      RECT 408.68 0.84 408.96 2321.76 ;
      RECT 410.92 0.84 411.2 2321.76 ;
      RECT 413.16 0.84 413.44 2321.76 ;
      RECT 415.4 0.84 415.68 2321.76 ;
      RECT 417.64 0.84 417.92 2321.76 ;
      RECT 419.88 0.84 420.16 2321.76 ;
      RECT 422.12 0.84 422.4 2321.76 ;
      RECT 424.36 0.84 424.64 2321.76 ;
      RECT 426.6 0.84 426.88 2321.76 ;
      RECT 428.84 0.84 429.12 2321.76 ;
      RECT 431.08 0.84 431.36 2321.76 ;
      RECT 433.32 0.84 433.6 2321.76 ;
      RECT 435.56 0.84 435.84 2321.76 ;
      RECT 437.8 0.84 438.08 2321.76 ;
      RECT 440.04 0.84 440.32 2321.76 ;
      RECT 442.28 0.84 442.56 2321.76 ;
      RECT 444.52 0.84 444.8 2321.76 ;
      RECT 446.76 0.84 447.04 2321.76 ;
      RECT 449 0.84 449.28 2321.76 ;
      RECT 451.24 0.84 451.52 2321.76 ;
      RECT 453.48 0.84 453.76 2321.76 ;
      RECT 455.72 0.84 456 2321.76 ;
      RECT 457.96 0.84 458.24 2321.76 ;
      RECT 460.2 0.84 460.48 2321.76 ;
      RECT 462.44 0.84 462.72 2321.76 ;
      RECT 464.68 0.84 464.96 2321.76 ;
      RECT 466.92 0.84 467.2 2321.76 ;
      RECT 469.16 0.84 469.44 2321.76 ;
      RECT 471.4 0.84 471.68 2321.76 ;
      RECT 473.64 0.84 473.92 2321.76 ;
      RECT 475.88 0.84 476.16 2321.76 ;
      RECT 478.12 0.84 478.4 2321.76 ;
      RECT 480.36 0.84 480.64 2321.76 ;
      RECT 482.6 0.84 482.88 2321.76 ;
      RECT 484.84 0.84 485.12 2321.76 ;
      RECT 487.08 0.84 487.36 2321.76 ;
      RECT 489.32 0.84 489.6 2321.76 ;
      RECT 491.56 0.84 491.84 2321.76 ;
      RECT 493.8 0.84 494.08 2321.76 ;
      RECT 496.04 0.84 496.32 2321.76 ;
      RECT 498.28 0.84 498.56 2321.76 ;
      RECT 500.52 0.84 500.8 2321.76 ;
      RECT 502.76 0.84 503.04 2321.76 ;
      RECT 505 0.84 505.28 2321.76 ;
      RECT 507.24 0.84 507.52 2321.76 ;
      RECT 509.48 0.84 509.76 2321.76 ;
      RECT 511.72 0.84 512 2321.76 ;
      RECT 513.96 0.84 514.24 2321.76 ;
      RECT 516.2 0.84 516.48 2321.76 ;
      RECT 518.44 0.84 518.72 2321.76 ;
      RECT 520.68 0.84 520.96 2321.76 ;
      RECT 522.92 0.84 523.2 2321.76 ;
      RECT 525.16 0.84 525.44 2321.76 ;
      RECT 527.4 0.84 527.68 2321.76 ;
      RECT 529.64 0.84 529.92 2321.76 ;
      RECT 531.88 0.84 532.16 2321.76 ;
      RECT 534.12 0.84 534.4 2321.76 ;
      RECT 536.36 0.84 536.64 2321.76 ;
      RECT 538.6 0.84 538.88 2321.76 ;
      RECT 540.84 0.84 541.12 2321.76 ;
      RECT 543.08 0.84 543.36 2321.76 ;
      RECT 545.32 0.84 545.6 2321.76 ;
      RECT 547.56 0.84 547.84 2321.76 ;
      RECT 549.8 0.84 550.08 2321.76 ;
      RECT 552.04 0.84 552.32 2321.76 ;
      RECT 554.28 0.84 554.56 2321.76 ;
      RECT 556.52 0.84 556.8 2321.76 ;
      RECT 558.76 0.84 559.04 2321.76 ;
      RECT 561 0.84 561.28 2321.76 ;
      RECT 563.24 0.84 563.52 2321.76 ;
      RECT 565.48 0.84 565.76 2321.76 ;
      RECT 567.72 0.84 568 2321.76 ;
      RECT 569.96 0.84 570.24 2321.76 ;
      RECT 572.2 0.84 572.48 2321.76 ;
      RECT 574.44 0.84 574.72 2321.76 ;
      RECT 576.68 0.84 576.96 2321.76 ;
      RECT 578.92 0.84 579.2 2321.76 ;
      RECT 581.16 0.84 581.44 2321.76 ;
      RECT 583.4 0.84 583.68 2321.76 ;
      RECT 585.64 0.84 585.92 2321.76 ;
      RECT 587.88 0.84 588.16 2321.76 ;
      RECT 590.12 0.84 590.4 2321.76 ;
      RECT 592.36 0.84 592.64 2321.76 ;
      RECT 594.6 0.84 594.88 2321.76 ;
      RECT 596.84 0.84 597.12 2321.76 ;
      RECT 599.08 0.84 599.36 2321.76 ;
      RECT 601.32 0.84 601.6 2321.76 ;
      RECT 603.56 0.84 603.84 2321.76 ;
      RECT 605.8 0.84 606.08 2321.76 ;
      RECT 608.04 0.84 608.32 2321.76 ;
      RECT 610.28 0.84 610.56 2321.76 ;
      RECT 612.52 0.84 612.8 2321.76 ;
      RECT 614.76 0.84 615.04 2321.76 ;
      RECT 617 0.84 617.28 2321.76 ;
      RECT 619.24 0.84 619.52 2321.76 ;
      RECT 621.48 0.84 621.76 2321.76 ;
      RECT 623.72 0.84 624 2321.76 ;
      RECT 625.96 0.84 626.24 2321.76 ;
      RECT 628.2 0.84 628.48 2321.76 ;
      RECT 630.44 0.84 630.72 2321.76 ;
      RECT 632.68 0.84 632.96 2321.76 ;
      RECT 634.92 0.84 635.2 2321.76 ;
      RECT 637.16 0.84 637.44 2321.76 ;
      RECT 639.4 0.84 639.68 2321.76 ;
      RECT 641.64 0.84 641.92 2321.76 ;
      RECT 643.88 0.84 644.16 2321.76 ;
      RECT 646.12 0.84 646.4 2321.76 ;
      RECT 648.36 0.84 648.64 2321.76 ;
      RECT 650.6 0.84 650.88 2321.76 ;
      RECT 652.84 0.84 653.12 2321.76 ;
      RECT 655.08 0.84 655.36 2321.76 ;
      RECT 657.32 0.84 657.6 2321.76 ;
      RECT 659.56 0.84 659.84 2321.76 ;
      RECT 661.8 0.84 662.08 2321.76 ;
      RECT 664.04 0.84 664.32 2321.76 ;
      RECT 666.28 0.84 666.56 2321.76 ;
      RECT 668.52 0.84 668.8 2321.76 ;
      RECT 670.76 0.84 671.04 2321.76 ;
      RECT 673 0.84 673.28 2321.76 ;
      RECT 675.24 0.84 675.52 2321.76 ;
      RECT 677.48 0.84 677.76 2321.76 ;
      RECT 679.72 0.84 680 2321.76 ;
      RECT 681.96 0.84 682.24 2321.76 ;
      RECT 684.2 0.84 684.48 2321.76 ;
      RECT 686.44 0.84 686.72 2321.76 ;
      RECT 688.68 0.84 688.96 2321.76 ;
      RECT 690.92 0.84 691.2 2321.76 ;
      RECT 693.16 0.84 693.44 2321.76 ;
      RECT 695.4 0.84 695.68 2321.76 ;
      RECT 697.64 0.84 697.92 2321.76 ;
      RECT 699.88 0.84 700.16 2321.76 ;
      RECT 702.12 0.84 702.4 2321.76 ;
      RECT 704.36 0.84 704.64 2321.76 ;
      RECT 706.6 0.84 706.88 2321.76 ;
      RECT 708.84 0.84 709.12 2321.76 ;
      RECT 711.08 0.84 711.36 2321.76 ;
      RECT 713.32 0.84 713.6 2321.76 ;
      RECT 715.56 0.84 715.84 2321.76 ;
      RECT 717.8 0.84 718.08 2321.76 ;
      RECT 720.04 0.84 720.32 2321.76 ;
      RECT 722.28 0.84 722.56 2321.76 ;
      RECT 724.52 0.84 724.8 2321.76 ;
      RECT 726.76 0.84 727.04 2321.76 ;
      RECT 729 0.84 729.28 2321.76 ;
      RECT 731.24 0.84 731.52 2321.76 ;
      RECT 733.48 0.84 733.76 2321.76 ;
      RECT 735.72 0.84 736 2321.76 ;
      RECT 737.96 0.84 738.24 2321.76 ;
      RECT 740.2 0.84 740.48 2321.76 ;
      RECT 742.44 0.84 742.72 2321.76 ;
      RECT 744.68 0.84 744.96 2321.76 ;
      RECT 746.92 0.84 747.2 2321.76 ;
      RECT 749.16 0.84 749.44 2321.76 ;
      RECT 751.4 0.84 751.68 2321.76 ;
      RECT 753.64 0.84 753.92 2321.76 ;
      RECT 755.88 0.84 756.16 2321.76 ;
      RECT 758.12 0.84 758.4 2321.76 ;
      RECT 760.36 0.84 760.64 2321.76 ;
      RECT 762.6 0.84 762.88 2321.76 ;
      RECT 764.84 0.84 765.12 2321.76 ;
      RECT 767.08 0.84 767.36 2321.76 ;
      RECT 769.32 0.84 769.6 2321.76 ;
      RECT 771.56 0.84 771.84 2321.76 ;
      RECT 773.8 0.84 774.08 2321.76 ;
      RECT 776.04 0.84 776.32 2321.76 ;
      RECT 778.28 0.84 778.56 2321.76 ;
      RECT 780.52 0.84 780.8 2321.76 ;
      RECT 782.76 0.84 783.04 2321.76 ;
      RECT 785 0.84 785.28 2321.76 ;
      RECT 787.24 0.84 787.52 2321.76 ;
      RECT 789.48 0.84 789.76 2321.76 ;
      RECT 791.72 0.84 792 2321.76 ;
      RECT 793.96 0.84 794.24 2321.76 ;
      RECT 796.2 0.84 796.48 2321.76 ;
      RECT 798.44 0.84 798.72 2321.76 ;
      RECT 800.68 0.84 800.96 2321.76 ;
      RECT 802.92 0.84 803.2 2321.76 ;
      RECT 805.16 0.84 805.44 2321.76 ;
      RECT 807.4 0.84 807.68 2321.76 ;
      RECT 809.64 0.84 809.92 2321.76 ;
      RECT 811.88 0.84 812.16 2321.76 ;
      RECT 814.12 0.84 814.4 2321.76 ;
      RECT 816.36 0.84 816.64 2321.76 ;
      RECT 818.6 0.84 818.88 2321.76 ;
      RECT 820.84 0.84 821.12 2321.76 ;
      RECT 823.08 0.84 823.36 2321.76 ;
      RECT 825.32 0.84 825.6 2321.76 ;
      RECT 827.56 0.84 827.84 2321.76 ;
      RECT 829.8 0.84 830.08 2321.76 ;
      RECT 832.04 0.84 832.32 2321.76 ;
      RECT 834.28 0.84 834.56 2321.76 ;
      RECT 836.52 0.84 836.8 2321.76 ;
      RECT 838.76 0.84 839.04 2321.76 ;
      RECT 841 0.84 841.28 2321.76 ;
      RECT 843.24 0.84 843.52 2321.76 ;
      RECT 845.48 0.84 845.76 2321.76 ;
      RECT 847.72 0.84 848 2321.76 ;
      RECT 849.96 0.84 850.24 2321.76 ;
      RECT 852.2 0.84 852.48 2321.76 ;
      RECT 854.44 0.84 854.72 2321.76 ;
      RECT 856.68 0.84 856.96 2321.76 ;
      RECT 858.92 0.84 859.2 2321.76 ;
      RECT 861.16 0.84 861.44 2321.76 ;
      RECT 863.4 0.84 863.68 2321.76 ;
      RECT 865.64 0.84 865.92 2321.76 ;
      RECT 867.88 0.84 868.16 2321.76 ;
      RECT 870.12 0.84 870.4 2321.76 ;
      RECT 872.36 0.84 872.64 2321.76 ;
      RECT 874.6 0.84 874.88 2321.76 ;
      RECT 876.84 0.84 877.12 2321.76 ;
      RECT 879.08 0.84 879.36 2321.76 ;
      RECT 881.32 0.84 881.6 2321.76 ;
      RECT 883.56 0.84 883.84 2321.76 ;
      RECT 885.8 0.84 886.08 2321.76 ;
      RECT 888.04 0.84 888.32 2321.76 ;
      RECT 890.28 0.84 890.56 2321.76 ;
      RECT 892.52 0.84 892.8 2321.76 ;
      RECT 894.76 0.84 895.04 2321.76 ;
      RECT 897 0.84 897.28 2321.76 ;
      RECT 899.24 0.84 899.52 2321.76 ;
      RECT 901.48 0.84 901.76 2321.76 ;
      RECT 903.72 0.84 904 2321.76 ;
      RECT 905.96 0.84 906.24 2321.76 ;
      RECT 908.2 0.84 908.48 2321.76 ;
      RECT 910.44 0.84 910.72 2321.76 ;
      RECT 912.68 0.84 912.96 2321.76 ;
      RECT 914.92 0.84 915.2 2321.76 ;
      RECT 917.16 0.84 917.44 2321.76 ;
      RECT 919.4 0.84 919.68 2321.76 ;
      RECT 921.64 0.84 921.92 2321.76 ;
      RECT 923.88 0.84 924.16 2321.76 ;
      RECT 926.12 0.84 926.4 2321.76 ;
      RECT 928.36 0.84 928.64 2321.76 ;
      RECT 930.6 0.84 930.88 2321.76 ;
      RECT 932.84 0.84 933.12 2321.76 ;
      RECT 935.08 0.84 935.36 2321.76 ;
      RECT 937.32 0.84 937.6 2321.76 ;
      RECT 939.56 0.84 939.84 2321.76 ;
      RECT 941.8 0.84 942.08 2321.76 ;
      RECT 944.04 0.84 944.32 2321.76 ;
      RECT 946.28 0.84 946.56 2321.76 ;
      RECT 948.52 0.84 948.8 2321.76 ;
      RECT 950.76 0.84 951.04 2321.76 ;
      RECT 953 0.84 953.28 2321.76 ;
      RECT 955.24 0.84 955.52 2321.76 ;
      RECT 957.48 0.84 957.76 2321.76 ;
      RECT 959.72 0.84 960 2321.76 ;
      RECT 961.96 0.84 962.24 2321.76 ;
      RECT 964.2 0.84 964.48 2321.76 ;
      RECT 966.44 0.84 966.72 2321.76 ;
      RECT 968.68 0.84 968.96 2321.76 ;
      RECT 970.92 0.84 971.2 2321.76 ;
      RECT 973.16 0.84 973.44 2321.76 ;
      RECT 975.4 0.84 975.68 2321.76 ;
      RECT 977.64 0.84 977.92 2321.76 ;
      RECT 979.88 0.84 980.16 2321.76 ;
      RECT 982.12 0.84 982.4 2321.76 ;
      RECT 984.36 0.84 984.64 2321.76 ;
      RECT 986.6 0.84 986.88 2321.76 ;
      RECT 988.84 0.84 989.12 2321.76 ;
      RECT 991.08 0.84 991.36 2321.76 ;
      RECT 993.32 0.84 993.6 2321.76 ;
      RECT 995.56 0.84 995.84 2321.76 ;
      RECT 997.8 0.84 998.08 2321.76 ;
      RECT 1000.04 0.84 1000.32 2321.76 ;
      RECT 1002.28 0.84 1002.56 2321.76 ;
      RECT 1004.52 0.84 1004.8 2321.76 ;
      RECT 1006.76 0.84 1007.04 2321.76 ;
      RECT 1009 0.84 1009.28 2321.76 ;
      RECT 1011.24 0.84 1011.52 2321.76 ;
      RECT 1013.48 0.84 1013.76 2321.76 ;
      RECT 1015.72 0.84 1016 2321.76 ;
      RECT 1017.96 0.84 1018.24 2321.76 ;
      RECT 1020.2 0.84 1020.48 2321.76 ;
      RECT 1022.44 0.84 1022.72 2321.76 ;
      RECT 1024.68 0.84 1024.96 2321.76 ;
      RECT 1026.92 0.84 1027.2 2321.76 ;
      RECT 1029.16 0.84 1029.44 2321.76 ;
      RECT 1031.4 0.84 1031.68 2321.76 ;
      RECT 1033.64 0.84 1033.92 2321.76 ;
      RECT 1035.88 0.84 1036.16 2321.76 ;
      RECT 1038.12 0.84 1038.4 2321.76 ;
      RECT 1040.36 0.84 1040.64 2321.76 ;
      RECT 1042.6 0.84 1042.88 2321.76 ;
      RECT 1044.84 0.84 1045.12 2321.76 ;
      RECT 1047.08 0.84 1047.36 2321.76 ;
      RECT 1049.32 0.84 1049.6 2321.76 ;
      RECT 1051.56 0.84 1051.84 2321.76 ;
      RECT 1053.8 0.84 1054.08 2321.76 ;
      RECT 1056.04 0.84 1056.32 2321.76 ;
      RECT 1058.28 0.84 1058.56 2321.76 ;
      RECT 1060.52 0.84 1060.8 2321.76 ;
      RECT 1062.76 0.84 1063.04 2321.76 ;
      RECT 1065 0.84 1065.28 2321.76 ;
      RECT 1067.24 0.84 1067.52 2321.76 ;
      RECT 1069.48 0.84 1069.76 2321.76 ;
      RECT 1071.72 0.84 1072 2321.76 ;
      RECT 1073.96 0.84 1074.24 2321.76 ;
      RECT 1076.2 0.84 1076.48 2321.76 ;
      RECT 1078.44 0.84 1078.72 2321.76 ;
      RECT 1080.68 0.84 1080.96 2321.76 ;
      RECT 1082.92 0.84 1083.2 2321.76 ;
      RECT 1085.16 0.84 1085.44 2321.76 ;
      RECT 1087.4 0.84 1087.68 2321.76 ;
      RECT 1089.64 0.84 1089.92 2321.76 ;
      RECT 1091.88 0.84 1092.16 2321.76 ;
      RECT 1094.12 0.84 1094.4 2321.76 ;
      RECT 1096.36 0.84 1096.64 2321.76 ;
      RECT 1098.6 0.84 1098.88 2321.76 ;
      RECT 1100.84 0.84 1101.12 2321.76 ;
      RECT 1103.08 0.84 1103.36 2321.76 ;
      RECT 1105.32 0.84 1105.6 2321.76 ;
      RECT 1107.56 0.84 1107.84 2321.76 ;
      RECT 1109.8 0.84 1110.08 2321.76 ;
      RECT 1112.04 0.84 1112.32 2321.76 ;
      RECT 1114.28 0.84 1114.56 2321.76 ;
      RECT 1116.52 0.84 1116.8 2321.76 ;
      RECT 1118.76 0.84 1119.04 2321.76 ;
      RECT 1121 0.84 1121.28 2321.76 ;
      RECT 1123.24 0.84 1123.52 2321.76 ;
      RECT 1125.48 0.84 1125.76 2321.76 ;
      RECT 1127.72 0.84 1128 2321.76 ;
      RECT 1129.96 0.84 1130.24 2321.76 ;
      RECT 1132.2 0.84 1132.48 2321.76 ;
      RECT 1134.44 0.84 1134.72 2321.76 ;
      RECT 1136.68 0.84 1136.96 2321.76 ;
      RECT 1138.92 0.84 1139.2 2321.76 ;
      RECT 1141.16 0.84 1141.44 2321.76 ;
      RECT 1143.4 0.84 1143.68 2321.76 ;
      RECT 1145.64 0.84 1145.92 2321.76 ;
      RECT 1147.88 0.84 1148.16 2321.76 ;
      RECT 1150.12 0.84 1150.4 2321.76 ;
      RECT 1152.36 0.84 1152.64 2321.76 ;
      RECT 1154.6 0.84 1154.88 2321.76 ;
      RECT 1156.84 0.84 1157.12 2321.76 ;
      RECT 1159.08 0.84 1159.36 2321.76 ;
      RECT 1161.32 0.84 1161.6 2321.76 ;
      RECT 1163.56 0.84 1163.84 2321.76 ;
      RECT 1165.8 0.84 1166.08 2321.76 ;
      RECT 1168.04 0.84 1168.32 2321.76 ;
      RECT 1170.28 0.84 1170.56 2321.76 ;
      RECT 1172.52 0.84 1172.8 2321.76 ;
      RECT 1174.76 0.84 1175.04 2321.76 ;
      RECT 1177 0.84 1177.28 2321.76 ;
      RECT 1179.24 0.84 1179.52 2321.76 ;
      RECT 1181.48 0.84 1181.76 2321.76 ;
      RECT 1183.72 0.84 1184 2321.76 ;
      RECT 1185.96 0.84 1186.24 2321.76 ;
      RECT 1188.2 0.84 1188.48 2321.76 ;
      RECT 1190.44 0.84 1190.72 2321.76 ;
      RECT 1192.68 0.84 1192.96 2321.76 ;
      RECT 1194.92 0.84 1195.2 2321.76 ;
      RECT 1197.16 0.84 1197.44 2321.76 ;
      RECT 1199.4 0.84 1199.68 2321.76 ;
      RECT 1201.64 0.84 1201.92 2321.76 ;
      RECT 1203.88 0.84 1204.16 2321.76 ;
      RECT 1206.12 0.84 1206.4 2321.76 ;
      RECT 1208.36 0.84 1208.64 2321.76 ;
      RECT 1210.6 0.84 1210.88 2321.76 ;
      RECT 1212.84 0.84 1213.12 2321.76 ;
      RECT 1215.08 0.84 1215.36 2321.76 ;
      RECT 1217.32 0.84 1217.6 2321.76 ;
      RECT 1219.56 0.84 1219.84 2321.76 ;
      RECT 1221.8 0.84 1222.08 2321.76 ;
      RECT 1224.04 0.84 1224.32 2321.76 ;
      RECT 1226.28 0.84 1226.56 2321.76 ;
      RECT 1228.52 0.84 1228.8 2321.76 ;
      RECT 1230.76 0.84 1231.04 2321.76 ;
      RECT 1233 0.84 1233.28 2321.76 ;
      RECT 1235.24 0.84 1235.52 2321.76 ;
      RECT 1237.48 0.84 1237.76 2321.76 ;
      RECT 1239.72 0.84 1240 2321.76 ;
      RECT 1241.96 0.84 1242.24 2321.76 ;
      RECT 1244.2 0.84 1244.48 2321.76 ;
      RECT 1246.44 0.84 1246.72 2321.76 ;
      RECT 1248.68 0.84 1248.96 2321.76 ;
      RECT 1250.92 0.84 1251.2 2321.76 ;
      RECT 1253.16 0.84 1253.44 2321.76 ;
      RECT 1255.4 0.84 1255.68 2321.76 ;
      RECT 1257.64 0.84 1257.92 2321.76 ;
      RECT 1259.88 0.84 1260.16 2321.76 ;
      RECT 1262.12 0.84 1262.4 2321.76 ;
      RECT 1264.36 0.84 1264.64 2321.76 ;
      RECT 1266.6 0.84 1266.88 2321.76 ;
      RECT 1268.84 0.84 1269.12 2321.76 ;
      RECT 1271.08 0.84 1271.36 2321.76 ;
      RECT 1273.32 0.84 1273.6 2321.76 ;
      RECT 1275.56 0.84 1275.84 2321.76 ;
      RECT 1277.8 0.84 1278.08 2321.76 ;
      RECT 1280.04 0.84 1280.32 2321.76 ;
      RECT 1282.28 0.84 1282.56 2321.76 ;
      RECT 1284.52 0.84 1284.8 2321.76 ;
      RECT 1286.76 0.84 1287.04 2321.76 ;
      RECT 1289 0.84 1289.28 2321.76 ;
      RECT 1291.24 0.84 1291.52 2321.76 ;
      RECT 1293.48 0.84 1293.76 2321.76 ;
      RECT 1295.72 0.84 1296 2321.76 ;
      RECT 1297.96 0.84 1298.24 2321.76 ;
      RECT 1300.2 0.84 1300.48 2321.76 ;
      RECT 1302.44 0.84 1302.72 2321.76 ;
      RECT 1304.68 0.84 1304.96 2321.76 ;
      RECT 1306.92 0.84 1307.2 2321.76 ;
      RECT 1309.16 0.84 1309.44 2321.76 ;
      RECT 1311.4 0.84 1311.68 2321.76 ;
      RECT 1313.64 0.84 1313.92 2321.76 ;
      RECT 1315.88 0.84 1316.16 2321.76 ;
      RECT 1318.12 0.84 1318.4 2321.76 ;
      RECT 1320.36 0.84 1320.64 2321.76 ;
      RECT 1322.6 0.84 1322.88 2321.76 ;
      RECT 1324.84 0.84 1325.12 2321.76 ;
      RECT 1327.08 0.84 1327.36 2321.76 ;
      RECT 1329.32 0.84 1329.6 2321.76 ;
      RECT 1331.56 0.84 1331.84 2321.76 ;
      RECT 1333.8 0.84 1334.08 2321.76 ;
      RECT 1336.04 0.84 1336.32 2321.76 ;
      RECT 1338.28 0.84 1338.56 2321.76 ;
      RECT 1340.52 0.84 1340.8 2321.76 ;
      RECT 1342.76 0.84 1343.04 2321.76 ;
      RECT 1345 0.84 1345.28 2321.76 ;
      RECT 1347.24 0.84 1347.52 2321.76 ;
      RECT 1349.48 0.84 1349.76 2321.76 ;
      RECT 1351.72 0.84 1352 2321.76 ;
      RECT 1353.96 0.84 1354.24 2321.76 ;
      RECT 1356.2 0.84 1356.48 2321.76 ;
      RECT 1358.44 0.84 1358.72 2321.76 ;
      RECT 1360.68 0.84 1360.96 2321.76 ;
      RECT 1362.92 0.84 1363.2 2321.76 ;
      RECT 1365.16 0.84 1365.44 2321.76 ;
      RECT 1367.4 0.84 1367.68 2321.76 ;
      RECT 1369.64 0.84 1369.92 2321.76 ;
      RECT 1371.88 0.84 1372.16 2321.76 ;
      RECT 1374.12 0.84 1374.4 2321.76 ;
      RECT 1376.36 0.84 1376.64 2321.76 ;
      RECT 1378.6 0.84 1378.88 2321.76 ;
      RECT 1380.84 0.84 1381.12 2321.76 ;
      RECT 1383.08 0.84 1383.36 2321.76 ;
      RECT 1385.32 0.84 1385.6 2321.76 ;
      RECT 1387.56 0.84 1387.84 2321.76 ;
      RECT 1389.8 0.84 1390.08 2321.76 ;
      RECT 1392.04 0.84 1392.32 2321.76 ;
      RECT 1394.28 0.84 1394.56 2321.76 ;
      RECT 1396.52 0.84 1396.8 2321.76 ;
      RECT 1398.76 0.84 1399.04 2321.76 ;
      RECT 1401 0.84 1401.28 2321.76 ;
      RECT 1403.24 0.84 1403.52 2321.76 ;
      RECT 1405.48 0.84 1405.76 2321.76 ;
      RECT 1407.72 0.84 1408 2321.76 ;
      RECT 1409.96 0.84 1410.24 2321.76 ;
      RECT 1412.2 0.84 1412.48 2321.76 ;
      RECT 1414.44 0.84 1414.72 2321.76 ;
      RECT 1416.68 0.84 1416.96 2321.76 ;
      RECT 1418.92 0.84 1419.2 2321.76 ;
      RECT 1421.16 0.84 1421.44 2321.76 ;
      RECT 1423.4 0.84 1423.68 2321.76 ;
      RECT 1425.64 0.84 1425.92 2321.76 ;
      RECT 1427.88 0.84 1428.16 2321.76 ;
      RECT 1430.12 0.84 1430.4 2321.76 ;
      RECT 1432.36 0.84 1432.64 2321.76 ;
      RECT 1434.6 0.84 1434.88 2321.76 ;
      RECT 1436.84 0.84 1437.12 2321.76 ;
      RECT 1439.08 0.84 1439.36 2321.76 ;
      RECT 1441.32 0.84 1441.6 2321.76 ;
      RECT 1443.56 0.84 1443.84 2321.76 ;
      RECT 1445.8 0.84 1446.08 2321.76 ;
      RECT 1448.04 0.84 1448.32 2321.76 ;
      RECT 1450.28 0.84 1450.56 2321.76 ;
      RECT 1452.52 0.84 1452.8 2321.76 ;
      RECT 1454.76 0.84 1455.04 2321.76 ;
      RECT 1457 0.84 1457.28 2321.76 ;
      RECT 1459.24 0.84 1459.52 2321.76 ;
      RECT 1461.48 0.84 1461.76 2321.76 ;
      RECT 1463.72 0.84 1464 2321.76 ;
      RECT 1465.96 0.84 1466.24 2321.76 ;
      RECT 1468.2 0.84 1468.48 2321.76 ;
      RECT 1470.44 0.84 1470.72 2321.76 ;
      RECT 1472.68 0.84 1472.96 2321.76 ;
      RECT 1474.92 0.84 1475.2 2321.76 ;
      RECT 1477.16 0.84 1477.44 2321.76 ;
      RECT 1479.4 0.84 1479.68 2321.76 ;
      RECT 1481.64 0.84 1481.92 2321.76 ;
      RECT 1483.88 0.84 1484.16 2321.76 ;
      RECT 1486.12 0.84 1486.4 2321.76 ;
      RECT 1488.36 0.84 1488.64 2321.76 ;
      RECT 1490.6 0.84 1490.88 2321.76 ;
      RECT 1492.84 0.84 1493.12 2321.76 ;
      RECT 1495.08 0.84 1495.36 2321.76 ;
      RECT 1497.32 0.84 1497.6 2321.76 ;
      RECT 1499.56 0.84 1499.84 2321.76 ;
      RECT 1501.8 0.84 1502.08 2321.76 ;
      RECT 1504.04 0.84 1504.32 2321.76 ;
      RECT 1506.28 0.84 1506.56 2321.76 ;
      RECT 1508.52 0.84 1508.8 2321.76 ;
      RECT 1510.76 0.84 1511.04 2321.76 ;
      RECT 1513 0.84 1513.28 2321.76 ;
      RECT 1515.24 0.84 1515.52 2321.76 ;
      RECT 1517.48 0.84 1517.76 2321.76 ;
      RECT 1519.72 0.84 1520 2321.76 ;
      RECT 1521.96 0.84 1522.24 2321.76 ;
      RECT 1524.2 0.84 1524.48 2321.76 ;
      RECT 1526.44 0.84 1526.72 2321.76 ;
      RECT 1528.68 0.84 1528.96 2321.76 ;
      RECT 1530.92 0.84 1531.2 2321.76 ;
      RECT 1533.16 0.84 1533.44 2321.76 ;
      RECT 1535.4 0.84 1535.68 2321.76 ;
      RECT 1537.64 0.84 1537.92 2321.76 ;
      RECT 1539.88 0.84 1540.16 2321.76 ;
      RECT 1542.12 0.84 1542.4 2321.76 ;
      RECT 1544.36 0.84 1544.64 2321.76 ;
      RECT 1546.6 0.84 1546.88 2321.76 ;
      RECT 1548.84 0.84 1549.12 2321.76 ;
      RECT 1551.08 0.84 1551.36 2321.76 ;
      RECT 1553.32 0.84 1553.6 2321.76 ;
      RECT 1555.56 0.84 1555.84 2321.76 ;
      RECT 1557.8 0.84 1558.08 2321.76 ;
      RECT 1560.04 0.84 1560.32 2321.76 ;
      RECT 1562.28 0.84 1562.56 2321.76 ;
      RECT 1564.52 0.84 1564.8 2321.76 ;
      RECT 1566.76 0.84 1567.04 2321.76 ;
      RECT 1569 0.84 1569.28 2321.76 ;
      RECT 1571.24 0.84 1571.52 2321.76 ;
      RECT 1573.48 0.84 1573.76 2321.76 ;
      RECT 1575.72 0.84 1576 2321.76 ;
      RECT 1577.96 0.84 1578.24 2321.76 ;
      RECT 1580.2 0.84 1580.48 2321.76 ;
      RECT 1582.44 0.84 1582.72 2321.76 ;
      RECT 1584.68 0.84 1584.96 2321.76 ;
      RECT 1586.92 0.84 1587.2 2321.76 ;
      RECT 1589.16 0.84 1589.44 2321.76 ;
      RECT 1591.4 0.84 1591.68 2321.76 ;
      RECT 1593.64 0.84 1593.92 2321.76 ;
      RECT 1595.88 0.84 1596.16 2321.76 ;
      RECT 1598.12 0.84 1598.4 2321.76 ;
      RECT 1600.36 0.84 1600.64 2321.76 ;
      RECT 1602.6 0.84 1602.88 2321.76 ;
      RECT 1604.84 0.84 1605.12 2321.76 ;
      RECT 1607.08 0.84 1607.36 2321.76 ;
      RECT 1609.32 0.84 1609.6 2321.76 ;
      RECT 1611.56 0.84 1611.84 2321.76 ;
      RECT 1613.8 0.84 1614.08 2321.76 ;
      RECT 1616.04 0.84 1616.32 2321.76 ;
      RECT 1618.28 0.84 1618.56 2321.76 ;
      RECT 1620.52 0.84 1620.8 2321.76 ;
      RECT 1622.76 0.84 1623.04 2321.76 ;
      RECT 1625 0.84 1625.28 2321.76 ;
      RECT 1627.24 0.84 1627.52 2321.76 ;
      RECT 1629.48 0.84 1629.76 2321.76 ;
      RECT 1631.72 0.84 1632 2321.76 ;
      RECT 1633.96 0.84 1634.24 2321.76 ;
      RECT 1636.2 0.84 1636.48 2321.76 ;
      RECT 1638.44 0.84 1638.72 2321.76 ;
      RECT 1640.68 0.84 1640.96 2321.76 ;
      RECT 1642.92 0.84 1643.2 2321.76 ;
      RECT 1645.16 0.84 1645.44 2321.76 ;
      RECT 1647.4 0.84 1647.68 2321.76 ;
      RECT 1649.64 0.84 1649.92 2321.76 ;
      RECT 1651.88 0.84 1652.16 2321.76 ;
      RECT 1654.12 0.84 1654.4 2321.76 ;
      RECT 1656.36 0.84 1656.64 2321.76 ;
      RECT 1658.6 0.84 1658.88 2321.76 ;
      RECT 1660.84 0.84 1661.12 2321.76 ;
      RECT 1663.08 0.84 1663.36 2321.76 ;
      RECT 1665.32 0.84 1665.6 2321.76 ;
      RECT 1667.56 0.84 1667.84 2321.76 ;
      RECT 1669.8 0.84 1670.08 2321.76 ;
      RECT 1672.04 0.84 1672.32 2321.76 ;
      RECT 1674.28 0.84 1674.56 2321.76 ;
      RECT 1676.52 0.84 1676.8 2321.76 ;
      RECT 1678.76 0.84 1679.04 2321.76 ;
      RECT 1681 0.84 1681.28 2321.76 ;
      RECT 1683.24 0.84 1683.52 2321.76 ;
      RECT 1685.48 0.84 1685.76 2321.76 ;
      RECT 1687.72 0.84 1688 2321.76 ;
      RECT 1689.96 0.84 1690.24 2321.76 ;
      RECT 1692.2 0.84 1692.48 2321.76 ;
      RECT 1694.44 0.84 1694.72 2321.76 ;
      RECT 1696.68 0.84 1696.96 2321.76 ;
      RECT 1698.92 0.84 1699.2 2321.76 ;
      RECT 1701.16 0.84 1701.44 2321.76 ;
      RECT 1703.4 0.84 1703.68 2321.76 ;
      RECT 1705.64 0.84 1705.92 2321.76 ;
      RECT 1707.88 0.84 1708.16 2321.76 ;
      RECT 1710.12 0.84 1710.4 2321.76 ;
      RECT 1712.36 0.84 1712.64 2321.76 ;
      RECT 1714.6 0.84 1714.88 2321.76 ;
      RECT 1716.84 0.84 1717.12 2321.76 ;
      RECT 1719.08 0.84 1719.36 2321.76 ;
      RECT 1721.32 0.84 1721.6 2321.76 ;
      RECT 1723.56 0.84 1723.84 2321.76 ;
      RECT 1725.8 0.84 1726.08 2321.76 ;
      RECT 1728.04 0.84 1728.32 2321.76 ;
      RECT 1730.28 0.84 1730.56 2321.76 ;
      RECT 1732.52 0.84 1732.8 2321.76 ;
      RECT 1734.76 0.84 1735.04 2321.76 ;
      RECT 1737 0.84 1737.28 2321.76 ;
      RECT 1739.24 0.84 1739.52 2321.76 ;
      RECT 1741.48 0.84 1741.76 2321.76 ;
      RECT 1743.72 0.84 1744 2321.76 ;
      RECT 1745.96 0.84 1746.24 2321.76 ;
      RECT 1748.2 0.84 1748.48 2321.76 ;
      RECT 1750.44 0.84 1750.72 2321.76 ;
      RECT 1752.68 0.84 1752.96 2321.76 ;
      RECT 1754.92 0.84 1755.2 2321.76 ;
      RECT 1757.16 0.84 1757.44 2321.76 ;
      RECT 1759.4 0.84 1759.68 2321.76 ;
      RECT 1761.64 0.84 1761.92 2321.76 ;
      RECT 1763.88 0.84 1764.16 2321.76 ;
      RECT 1766.12 0.84 1766.4 2321.76 ;
      RECT 1768.36 0.84 1768.64 2321.76 ;
      RECT 1770.6 0.84 1770.88 2321.76 ;
      RECT 1772.84 0.84 1773.12 2321.76 ;
      RECT 1775.08 0.84 1775.36 2321.76 ;
      RECT 1777.32 0.84 1777.6 2321.76 ;
      RECT 1779.56 0.84 1779.84 2321.76 ;
      RECT 1781.8 0.84 1782.08 2321.76 ;
      RECT 1784.04 0.84 1784.32 2321.76 ;
      RECT 1786.28 0.84 1786.56 2321.76 ;
      RECT 1788.52 0.84 1788.8 2321.76 ;
      RECT 1790.76 0.84 1791.04 2321.76 ;
      RECT 1793 0.84 1793.28 2321.76 ;
      RECT 1795.24 0.84 1795.52 2321.76 ;
      RECT 1797.48 0.84 1797.76 2321.76 ;
      RECT 1799.72 0.84 1800 2321.76 ;
      RECT 1801.96 0.84 1802.24 2321.76 ;
      RECT 1804.2 0.84 1804.48 2321.76 ;
      RECT 1806.44 0.84 1806.72 2321.76 ;
      RECT 1808.68 0.84 1808.96 2321.76 ;
      RECT 1810.92 0.84 1811.2 2321.76 ;
      RECT 1813.16 0.84 1813.44 2321.76 ;
      RECT 1815.4 0.84 1815.68 2321.76 ;
      RECT 1817.64 0.84 1817.92 2321.76 ;
      RECT 1819.88 0.84 1820.16 2321.76 ;
      RECT 1822.12 0.84 1822.4 2321.76 ;
      RECT 1824.36 0.84 1824.64 2321.76 ;
      RECT 1826.6 0.84 1826.88 2321.76 ;
      RECT 1828.84 0.84 1829.12 2321.76 ;
      RECT 1831.08 0.84 1831.36 2321.76 ;
      RECT 1833.32 0.84 1833.6 2321.76 ;
      RECT 1835.56 0.84 1835.84 2321.76 ;
      RECT 1837.8 0.84 1838.08 2321.76 ;
      RECT 1840.04 0.84 1840.32 2321.76 ;
      RECT 1842.28 0.84 1842.56 2321.76 ;
      RECT 1844.52 0.84 1844.8 2321.76 ;
      RECT 1846.76 0.84 1847.04 2321.76 ;
      RECT 1849 0.84 1849.28 2321.76 ;
      RECT 1851.24 0.84 1851.52 2321.76 ;
      RECT 1853.48 0.84 1853.76 2321.76 ;
      RECT 1855.72 0.84 1856 2321.76 ;
      RECT 1857.96 0.84 1858.24 2321.76 ;
      RECT 1860.2 0.84 1860.48 2321.76 ;
      RECT 1862.44 0.84 1862.72 2321.76 ;
      RECT 1864.68 0.84 1864.96 2321.76 ;
      RECT 1866.92 0.84 1867.2 2321.76 ;
      RECT 1869.16 0.84 1869.44 2321.76 ;
      RECT 1871.4 0.84 1871.68 2321.76 ;
      RECT 1873.64 0.84 1873.92 2321.76 ;
      RECT 1875.88 0.84 1876.16 2321.76 ;
      RECT 1878.12 0.84 1878.4 2321.76 ;
      RECT 1880.36 0.84 1880.64 2321.76 ;
      RECT 1882.6 0.84 1882.88 2321.76 ;
      RECT 1884.84 0.84 1885.12 2321.76 ;
      RECT 1887.08 0.84 1887.36 2321.76 ;
      RECT 1889.32 0.84 1889.6 2321.76 ;
      RECT 1891.56 0.84 1891.84 2321.76 ;
      RECT 1893.8 0.84 1894.08 2321.76 ;
      RECT 1896.04 0.84 1896.32 2321.76 ;
      RECT 1898.28 0.84 1898.56 2321.76 ;
      RECT 1900.52 0.84 1900.8 2321.76 ;
      RECT 1902.76 0.84 1903.04 2321.76 ;
      RECT 1905 0.84 1905.28 2321.76 ;
      RECT 1907.24 0.84 1907.52 2321.76 ;
      RECT 1909.48 0.84 1909.76 2321.76 ;
      RECT 1911.72 0.84 1912 2321.76 ;
      RECT 1913.96 0.84 1914.24 2321.76 ;
      RECT 1916.2 0.84 1916.48 2321.76 ;
      RECT 1918.44 0.84 1918.72 2321.76 ;
      RECT 1920.68 0.84 1920.96 2321.76 ;
      RECT 1922.92 0.84 1923.2 2321.76 ;
      RECT 1925.16 0.84 1925.44 2321.76 ;
      RECT 1927.4 0.84 1927.68 2321.76 ;
      RECT 1929.64 0.84 1929.92 2321.76 ;
      RECT 1931.88 0.84 1932.16 2321.76 ;
      RECT 1934.12 0.84 1934.4 2321.76 ;
      RECT 1936.36 0.84 1936.64 2321.76 ;
      RECT 1938.6 0.84 1938.88 2321.76 ;
      RECT 1940.84 0.84 1941.12 2321.76 ;
      RECT 1943.08 0.84 1943.36 2321.76 ;
      RECT 1945.32 0.84 1945.6 2321.76 ;
      RECT 1947.56 0.84 1947.84 2321.76 ;
      RECT 1949.8 0.84 1950.08 2321.76 ;
      RECT 1952.04 0.84 1952.32 2321.76 ;
      RECT 1954.28 0.84 1954.56 2321.76 ;
      RECT 1956.52 0.84 1956.8 2321.76 ;
      RECT 1958.76 0.84 1959.04 2321.76 ;
      RECT 1961 0.84 1961.28 2321.76 ;
      RECT 1963.24 0.84 1963.52 2321.76 ;
      RECT 1965.48 0.84 1965.76 2321.76 ;
      RECT 1967.72 0.84 1968 2321.76 ;
      RECT 1969.96 0.84 1970.24 2321.76 ;
      RECT 1972.2 0.84 1972.48 2321.76 ;
      RECT 1974.44 0.84 1974.72 2321.76 ;
      RECT 1976.68 0.84 1976.96 2321.76 ;
      RECT 1978.92 0.84 1979.2 2321.76 ;
      RECT 1981.16 0.84 1981.44 2321.76 ;
      RECT 1983.4 0.84 1983.68 2321.76 ;
      RECT 1985.64 0.84 1985.92 2321.76 ;
      RECT 1987.88 0.84 1988.16 2321.76 ;
      RECT 1990.12 0.84 1990.4 2321.76 ;
      RECT 1992.36 0.84 1992.64 2321.76 ;
      RECT 1994.6 0.84 1994.88 2321.76 ;
      RECT 1996.84 0.84 1997.12 2321.76 ;
      RECT 1999.08 0.84 1999.36 2321.76 ;
      RECT 2001.32 0.84 2001.6 2321.76 ;
      RECT 2003.56 0.84 2003.84 2321.76 ;
      RECT 2005.8 0.84 2006.08 2321.76 ;
      RECT 2008.04 0.84 2008.32 2321.76 ;
      RECT 2010.28 0.84 2010.56 2321.76 ;
      RECT 2012.52 0.84 2012.8 2321.76 ;
      RECT 2014.76 0.84 2015.04 2321.76 ;
      RECT 2017 0.84 2017.28 2321.76 ;
      RECT 2019.24 0.84 2019.52 2321.76 ;
      RECT 2021.48 0.84 2021.76 2321.76 ;
      RECT 2023.72 0.84 2024 2321.76 ;
      RECT 2025.96 0.84 2026.24 2321.76 ;
      RECT 2028.2 0.84 2028.48 2321.76 ;
      RECT 2030.44 0.84 2030.72 2321.76 ;
      RECT 2032.68 0.84 2032.96 2321.76 ;
      RECT 2034.92 0.84 2035.2 2321.76 ;
      RECT 2037.16 0.84 2037.44 2321.76 ;
      RECT 2039.4 0.84 2039.68 2321.76 ;
      RECT 2041.64 0.84 2041.92 2321.76 ;
      RECT 2043.88 0.84 2044.16 2321.76 ;
      RECT 2046.12 0.84 2046.4 2321.76 ;
      RECT 2048.36 0.84 2048.64 2321.76 ;
      RECT 2050.6 0.84 2050.88 2321.76 ;
      RECT 2052.84 0.84 2053.12 2321.76 ;
      RECT 2055.08 0.84 2055.36 2321.76 ;
      RECT 2057.32 0.84 2057.6 2321.76 ;
      RECT 2059.56 0.84 2059.84 2321.76 ;
      RECT 2061.8 0.84 2062.08 2321.76 ;
      RECT 2064.04 0.84 2064.32 2321.76 ;
      RECT 2066.28 0.84 2066.56 2321.76 ;
      RECT 2068.52 0.84 2068.8 2321.76 ;
      RECT 2070.76 0.84 2071.04 2321.76 ;
      RECT 2073 0.84 2073.28 2321.76 ;
      RECT 2075.24 0.84 2075.52 2321.76 ;
      RECT 2077.48 0.84 2077.76 2321.76 ;
      RECT 2079.72 0.84 2080 2321.76 ;
      RECT 2081.96 0.84 2082.24 2321.76 ;
      RECT 2084.2 0.84 2084.48 2321.76 ;
      RECT 2086.44 0.84 2086.72 2321.76 ;
      RECT 2088.68 0.84 2088.96 2321.76 ;
      RECT 2090.92 0.84 2091.2 2321.76 ;
      RECT 2093.16 0.84 2093.44 2321.76 ;
      RECT 2095.4 0.84 2095.68 2321.76 ;
      RECT 2097.64 0.84 2097.92 2321.76 ;
      RECT 2099.88 0.84 2100.16 2321.76 ;
      RECT 2102.12 0.84 2102.4 2321.76 ;
      RECT 2104.36 0.84 2104.64 2321.76 ;
      RECT 2106.6 0.84 2106.88 2321.76 ;
      RECT 2108.84 0.84 2109.12 2321.76 ;
      RECT 2111.08 0.84 2111.36 2321.76 ;
      RECT 2113.32 0.84 2113.6 2321.76 ;
      RECT 2115.56 0.84 2115.84 2321.76 ;
      RECT 2117.8 0.84 2118.08 2321.76 ;
      RECT 2120.04 0.84 2120.32 2321.76 ;
      RECT 2122.28 0.84 2122.56 2321.76 ;
      RECT 2124.52 0.84 2124.8 2321.76 ;
      RECT 2126.76 0.84 2127.04 2321.76 ;
      RECT 2129 0.84 2129.28 2321.76 ;
      RECT 2131.24 0.84 2131.52 2321.76 ;
      RECT 2133.48 0.84 2133.76 2321.76 ;
      RECT 2135.72 0.84 2136 2321.76 ;
      RECT 2137.96 0.84 2138.24 2321.76 ;
      RECT 2140.2 0.84 2140.48 2321.76 ;
      RECT 2142.44 0.84 2142.72 2321.76 ;
      RECT 2144.68 0.84 2144.96 2321.76 ;
      RECT 2146.92 0.84 2147.2 2321.76 ;
      RECT 2149.16 0.84 2149.44 2321.76 ;
      RECT 2151.4 0.84 2151.68 2321.76 ;
      RECT 2153.64 0.84 2153.92 2321.76 ;
      RECT 2155.88 0.84 2156.16 2321.76 ;
      RECT 2158.12 0.84 2158.4 2321.76 ;
      RECT 2160.36 0.84 2160.64 2321.76 ;
      RECT 2162.6 0.84 2162.88 2321.76 ;
      RECT 2164.84 0.84 2165.12 2321.76 ;
      RECT 2167.08 0.84 2167.36 2321.76 ;
      RECT 2169.32 0.84 2169.6 2321.76 ;
      RECT 2171.56 0.84 2171.84 2321.76 ;
      RECT 2173.8 0.84 2174.08 2321.76 ;
      RECT 2176.04 0.84 2176.32 2321.76 ;
      RECT 2178.28 0.84 2178.56 2321.76 ;
      RECT 2180.52 0.84 2180.8 2321.76 ;
      RECT 2182.76 0.84 2183.04 2321.76 ;
      RECT 2185 0.84 2185.28 2321.76 ;
      RECT 2187.24 0.84 2187.52 2321.76 ;
      RECT 2189.48 0.84 2189.76 2321.76 ;
      RECT 2191.72 0.84 2192 2321.76 ;
      RECT 2193.96 0.84 2194.24 2321.76 ;
      RECT 2196.2 0.84 2196.48 2321.76 ;
      RECT 2198.44 0.84 2198.72 2321.76 ;
      RECT 2200.68 0.84 2200.96 2321.76 ;
      RECT 2202.92 0.84 2203.2 2321.76 ;
      RECT 2205.16 0.84 2205.44 2321.76 ;
      RECT 2207.4 0.84 2207.68 2321.76 ;
      RECT 2209.64 0.84 2209.92 2321.76 ;
      RECT 2211.88 0.84 2212.16 2321.76 ;
      RECT 2214.12 0.84 2214.4 2321.76 ;
      RECT 2216.36 0.84 2216.64 2321.76 ;
      RECT 2218.6 0.84 2218.88 2321.76 ;
      RECT 2220.84 0.84 2221.12 2321.76 ;
      RECT 2223.08 0.84 2223.36 2321.76 ;
      RECT 2225.32 0.84 2225.6 2321.76 ;
      RECT 2227.56 0.84 2227.84 2321.76 ;
      RECT 2229.8 0.84 2230.08 2321.76 ;
      RECT 2232.04 0.84 2232.32 2321.76 ;
      RECT 2234.28 0.84 2234.56 2321.76 ;
      RECT 2236.52 0.84 2236.8 2321.76 ;
      RECT 2238.76 0.84 2239.04 2321.76 ;
      RECT 2241 0.84 2241.28 2321.76 ;
      RECT 2243.24 0.84 2243.52 2321.76 ;
      RECT 2245.48 0.84 2245.76 2321.76 ;
      RECT 2247.72 0.84 2248 2321.76 ;
      RECT 2249.96 0.84 2250.24 2321.76 ;
      RECT 2252.2 0.84 2252.48 2321.76 ;
      RECT 2254.44 0.84 2254.72 2321.76 ;
      RECT 2256.68 0.84 2256.96 2321.76 ;
      RECT 2258.92 0.84 2259.2 2321.76 ;
      RECT 2261.16 0.84 2261.44 2321.76 ;
      RECT 2263.4 0.84 2263.68 2321.76 ;
      RECT 2265.64 0.84 2265.92 2321.76 ;
      RECT 2267.88 0.84 2268.16 2321.76 ;
      RECT 2270.12 0.84 2270.4 2321.76 ;
      RECT 2272.36 0.84 2272.64 2321.76 ;
      RECT 2274.6 0.84 2274.88 2321.76 ;
      RECT 2276.84 0.84 2277.12 2321.76 ;
      RECT 2279.08 0.84 2279.36 2321.76 ;
      RECT 2281.32 0.84 2281.6 2321.76 ;
      RECT 2283.56 0.84 2283.84 2321.76 ;
      RECT 2285.8 0.84 2286.08 2321.76 ;
      RECT 2288.04 0.84 2288.32 2321.76 ;
      RECT 2290.28 0.84 2290.56 2321.76 ;
      RECT 2292.52 0.84 2292.8 2321.76 ;
      RECT 2294.76 0.84 2295.04 2321.76 ;
      RECT 2297 0.84 2297.28 2321.76 ;
      RECT 2299.24 0.84 2299.52 2321.76 ;
      RECT 2301.48 0.84 2301.76 2321.76 ;
      RECT 2303.72 0.84 2304 2321.76 ;
      RECT 2305.96 0.84 2306.24 2321.76 ;
      RECT 2308.2 0.84 2308.48 2321.76 ;
      RECT 2310.44 0.84 2310.72 2321.76 ;
      RECT 2312.68 0.84 2312.96 2321.76 ;
      RECT 2314.92 0.84 2315.2 2321.76 ;
      RECT 2317.16 0.84 2317.44 2321.76 ;
      RECT 2319.4 0.84 2319.68 2321.76 ;
      RECT 2321.64 0.84 2321.92 2321.76 ;
      RECT 2323.88 0.84 2324.16 2321.76 ;
      RECT 2326.12 0.84 2326.4 2321.76 ;
      RECT 2328.36 0.84 2328.64 2321.76 ;
      RECT 2330.6 0.84 2330.88 2321.76 ;
      RECT 2332.84 0.84 2333.12 2321.76 ;
      RECT 2335.08 0.84 2335.36 2321.76 ;
      RECT 2337.32 0.84 2337.6 2321.76 ;
      RECT 2339.56 0.84 2339.84 2321.76 ;
      RECT 2341.8 0.84 2342.08 2321.76 ;
      RECT 2344.04 0.84 2344.32 2321.76 ;
      RECT 2346.28 0.84 2346.56 2321.76 ;
      RECT 2348.52 0.84 2348.8 2321.76 ;
      RECT 2350.76 0.84 2351.04 2321.76 ;
      RECT 2353 0.84 2353.28 2321.76 ;
      RECT 2355.24 0.84 2355.52 2321.76 ;
      RECT 2357.48 0.84 2357.76 2321.76 ;
      RECT 2359.72 0.84 2360 2321.76 ;
      RECT 2361.96 0.84 2362.24 2321.76 ;
      RECT 2364.2 0.84 2364.48 2321.76 ;
      RECT 2366.44 0.84 2366.72 2321.76 ;
      RECT 2368.68 0.84 2368.96 2321.76 ;
      RECT 2370.92 0.84 2371.2 2321.76 ;
      RECT 2373.16 0.84 2373.44 2321.76 ;
      RECT 2375.4 0.84 2375.68 2321.76 ;
      RECT 2377.64 0.84 2377.92 2321.76 ;
      RECT 2379.88 0.84 2380.16 2321.76 ;
      RECT 2382.12 0.84 2382.4 2321.76 ;
      RECT 2384.36 0.84 2384.64 2321.76 ;
      RECT 2386.6 0.84 2386.88 2321.76 ;
      RECT 2388.84 0.84 2389.12 2321.76 ;
      RECT 2391.08 0.84 2391.36 2321.76 ;
      RECT 2393.32 0.84 2393.6 2321.76 ;
      RECT 2395.56 0.84 2395.84 2321.76 ;
      RECT 2397.8 0.84 2398.08 2321.76 ;
      RECT 2400.04 0.84 2400.32 2321.76 ;
      RECT 2402.28 0.84 2402.56 2321.76 ;
      RECT 2404.52 0.84 2404.8 2321.76 ;
      RECT 2406.76 0.84 2407.04 2321.76 ;
      RECT 2409 0.84 2409.28 2321.76 ;
      RECT 2411.24 0.84 2411.52 2321.76 ;
      RECT 2413.48 0.84 2413.76 2321.76 ;
      RECT 2415.72 0.84 2416 2321.76 ;
      RECT 2417.96 0.84 2418.24 2321.76 ;
      RECT 2420.2 0.84 2420.48 2321.76 ;
      RECT 2422.44 0.84 2422.72 2321.76 ;
      RECT 2424.68 0.84 2424.96 2321.76 ;
      RECT 2426.92 0.84 2427.2 2321.76 ;
      RECT 2429.16 0.84 2429.44 2321.76 ;
      RECT 2431.4 0.84 2431.68 2321.76 ;
      RECT 2433.64 0.84 2433.92 2321.76 ;
      RECT 2435.88 0.84 2436.16 2321.76 ;
      RECT 2438.12 0.84 2438.4 2321.76 ;
      RECT 2440.36 0.84 2440.64 2321.76 ;
      RECT 2442.6 0.84 2442.88 2321.76 ;
      RECT 2444.84 0.84 2445.12 2321.76 ;
      RECT 2447.08 0.84 2447.36 2321.76 ;
      RECT 2449.32 0.84 2449.6 2321.76 ;
      RECT 2451.56 0.84 2451.84 2321.76 ;
      RECT 2453.8 0.84 2454.08 2321.76 ;
      RECT 2456.04 0.84 2456.32 2321.76 ;
      RECT 2458.28 0.84 2458.56 2321.76 ;
      RECT 2460.52 0.84 2460.8 2321.76 ;
      RECT 2462.76 0.84 2463.04 2321.76 ;
      RECT 2465 0.84 2465.28 2321.76 ;
      RECT 2467.24 0.84 2467.52 2321.76 ;
      RECT 2469.48 0.84 2469.76 2321.76 ;
      RECT 2471.72 0.84 2472 2321.76 ;
      RECT 2473.96 0.84 2474.24 2321.76 ;
      RECT 2476.2 0.84 2476.48 2321.76 ;
      RECT 2478.44 0.84 2478.72 2321.76 ;
      RECT 2480.68 0.84 2480.96 2321.76 ;
      RECT 2482.92 0.84 2483.2 2321.76 ;
      RECT 2485.16 0.84 2485.44 2321.76 ;
      RECT 2487.4 0.84 2487.68 2321.76 ;
      RECT 2489.64 0.84 2489.92 2321.76 ;
      RECT 2491.88 0.84 2492.16 2321.76 ;
      RECT 2494.12 0.84 2494.4 2321.76 ;
      RECT 2496.36 0.84 2496.64 2321.76 ;
      RECT 2498.6 0.84 2498.88 2321.76 ;
      RECT 2500.84 0.84 2501.12 2321.76 ;
      RECT 2503.08 0.84 2503.36 2321.76 ;
      RECT 2505.32 0.84 2505.6 2321.76 ;
      RECT 2507.56 0.84 2507.84 2321.76 ;
      RECT 2509.8 0.84 2510.08 2321.76 ;
      RECT 2512.04 0.84 2512.32 2321.76 ;
      RECT 2514.28 0.84 2514.56 2321.76 ;
      RECT 2516.52 0.84 2516.8 2321.76 ;
      RECT 2518.76 0.84 2519.04 2321.76 ;
      RECT 2521 0.84 2521.28 2321.76 ;
      RECT 2523.24 0.84 2523.52 2321.76 ;
      RECT 2525.48 0.84 2525.76 2321.76 ;
      RECT 2527.72 0.84 2528 2321.76 ;
      RECT 2529.96 0.84 2530.24 2321.76 ;
      RECT 2532.2 0.84 2532.48 2321.76 ;
      RECT 2534.44 0.84 2534.72 2321.76 ;
      RECT 2536.68 0.84 2536.96 2321.76 ;
      RECT 2538.92 0.84 2539.2 2321.76 ;
      RECT 2541.16 0.84 2541.44 2321.76 ;
      RECT 2543.4 0.84 2543.68 2321.76 ;
      RECT 2545.64 0.84 2545.92 2321.76 ;
      RECT 2547.88 0.84 2548.16 2321.76 ;
      RECT 2550.12 0.84 2550.4 2321.76 ;
      RECT 2552.36 0.84 2552.64 2321.76 ;
      RECT 2554.6 0.84 2554.88 2321.76 ;
      RECT 2556.84 0.84 2557.12 2321.76 ;
      RECT 2559.08 0.84 2559.36 2321.76 ;
      RECT 2561.32 0.84 2561.6 2321.76 ;
      RECT 2563.56 0.84 2563.84 2321.76 ;
      RECT 2565.8 0.84 2566.08 2321.76 ;
      RECT 2568.04 0.84 2568.32 2321.76 ;
      RECT 2570.28 0.84 2570.56 2321.76 ;
      RECT 2572.52 0.84 2572.8 2321.76 ;
      RECT 2574.76 0.84 2575.04 2321.76 ;
      RECT 2577 0.84 2577.28 2321.76 ;
      RECT 2579.24 0.84 2579.52 2321.76 ;
      RECT 2581.48 0.84 2581.76 2321.76 ;
      RECT 2583.72 0.84 2584 2321.76 ;
      RECT 2585.96 0.84 2586.24 2321.76 ;
      RECT 2588.2 0.84 2588.48 2321.76 ;
      RECT 2590.44 0.84 2590.72 2321.76 ;
      RECT 2592.68 0.84 2592.96 2321.76 ;
      RECT 2594.92 0.84 2595.2 2321.76 ;
      RECT 2597.16 0.84 2597.44 2321.76 ;
      RECT 2599.4 0.84 2599.68 2321.76 ;
      RECT 2601.64 0.84 2601.92 2321.76 ;
      RECT 2603.88 0.84 2604.16 2321.76 ;
      RECT 2606.12 0.84 2606.4 2321.76 ;
      RECT 2608.36 0.84 2608.64 2321.76 ;
      RECT 2610.6 0.84 2610.88 2321.76 ;
      RECT 2612.84 0.84 2613.12 2321.76 ;
      RECT 2615.08 0.84 2615.36 2321.76 ;
      RECT 2617.32 0.84 2617.6 2321.76 ;
      RECT 2619.56 0.84 2619.84 2321.76 ;
      RECT 2621.8 0.84 2622.08 2321.76 ;
      RECT 2624.04 0.84 2624.32 2321.76 ;
      RECT 2626.28 0.84 2626.56 2321.76 ;
      RECT 2628.52 0.84 2628.8 2321.76 ;
      RECT 2630.76 0.84 2631.04 2321.76 ;
      RECT 2633 0.84 2633.28 2321.76 ;
      RECT 2635.24 0.84 2635.52 2321.76 ;
      RECT 2637.48 0.84 2637.76 2321.76 ;
      RECT 2639.72 0.84 2640 2321.76 ;
      RECT 2641.96 0.84 2642.24 2321.76 ;
      RECT 2644.2 0.84 2644.48 2321.76 ;
      RECT 2646.44 0.84 2646.72 2321.76 ;
      RECT 2648.68 0.84 2648.96 2321.76 ;
      RECT 2650.92 0.84 2651.2 2321.76 ;
      RECT 2653.16 0.84 2653.44 2321.76 ;
      RECT 2655.4 0.84 2655.68 2321.76 ;
      RECT 2657.64 0.84 2657.92 2321.76 ;
      RECT 2659.88 0.84 2660.16 2321.76 ;
      RECT 2662.12 0.84 2662.4 2321.76 ;
      RECT 2664.36 0.84 2664.64 2321.76 ;
      RECT 2666.6 0.84 2666.88 2321.76 ;
      RECT 2668.84 0.84 2669.12 2321.76 ;
      RECT 2671.08 0.84 2671.36 2321.76 ;
      RECT 2673.32 0.84 2673.6 2321.76 ;
      RECT 2675.56 0.84 2675.84 2321.76 ;
      RECT 2677.8 0.84 2678.08 2321.76 ;
      RECT 2680.04 0.84 2680.32 2321.76 ;
      RECT 2682.28 0.84 2682.56 2321.76 ;
      RECT 2684.52 0.84 2684.8 2321.76 ;
      RECT 2686.76 0.84 2687.04 2321.76 ;
      RECT 2689 0.84 2689.28 2321.76 ;
      RECT 2691.24 0.84 2691.52 2321.76 ;
      RECT 2693.48 0.84 2693.76 2321.76 ;
      RECT 2695.72 0.84 2696 2321.76 ;
      RECT 2697.96 0.84 2698.24 2321.76 ;
      RECT 2700.2 0.84 2700.48 2321.76 ;
      RECT 2702.44 0.84 2702.72 2321.76 ;
      RECT 2704.68 0.84 2704.96 2321.76 ;
      RECT 2706.92 0.84 2707.2 2321.76 ;
      RECT 2709.16 0.84 2709.44 2321.76 ;
      RECT 2711.4 0.84 2711.68 2321.76 ;
      RECT 2713.64 0.84 2713.92 2321.76 ;
      RECT 2715.88 0.84 2716.16 2321.76 ;
      RECT 2718.12 0.84 2718.4 2321.76 ;
      RECT 2720.36 0.84 2720.64 2321.76 ;
      RECT 2722.6 0.84 2722.88 2321.76 ;
      RECT 2724.84 0.84 2725.12 2321.76 ;
      RECT 2727.08 0.84 2727.36 2321.76 ;
      RECT 2729.32 0.84 2729.6 2321.76 ;
      RECT 2731.56 0.84 2731.84 2321.76 ;
      RECT 2733.8 0.84 2734.08 2321.76 ;
      RECT 2736.04 0.84 2736.32 2321.76 ;
      RECT 2738.28 0.84 2738.56 2321.76 ;
      RECT 2740.52 0.84 2740.8 2321.76 ;
      RECT 2742.76 0.84 2743.04 2321.76 ;
      RECT 2745 0.84 2745.28 2321.76 ;
      RECT 2747.24 0.84 2747.52 2321.76 ;
      RECT 2749.48 0.84 2749.76 2321.76 ;
      RECT 2751.72 0.84 2752 2321.76 ;
      RECT 2753.96 0.84 2754.24 2321.76 ;
      RECT 2756.2 0.84 2756.48 2321.76 ;
      RECT 2758.44 0.84 2758.72 2321.76 ;
      RECT 2760.68 0.84 2760.96 2321.76 ;
      RECT 2762.92 0.84 2763.2 2321.76 ;
      RECT 2765.16 0.84 2765.44 2321.76 ;
      RECT 2767.4 0.84 2767.68 2321.76 ;
      RECT 2769.64 0.84 2769.92 2321.76 ;
      RECT 2771.88 0.84 2772.16 2321.76 ;
      RECT 2774.12 0.84 2774.4 2321.76 ;
      RECT 2776.36 0.84 2776.64 2321.76 ;
      RECT 2778.6 0.84 2778.88 2321.76 ;
      RECT 2780.84 0.84 2781.12 2321.76 ;
      RECT 2783.08 0.84 2783.36 2321.76 ;
      RECT 2785.32 0.84 2785.6 2321.76 ;
      RECT 2787.56 0.84 2787.84 2321.76 ;
      RECT 2789.8 0.84 2790.08 2321.76 ;
      RECT 2792.04 0.84 2792.32 2321.76 ;
      RECT 2794.28 0.84 2794.56 2321.76 ;
      RECT 2796.52 0.84 2796.8 2321.76 ;
      RECT 2798.76 0.84 2799.04 2321.76 ;
      RECT 2801 0.84 2801.28 2321.76 ;
      RECT 2803.24 0.84 2803.52 2321.76 ;
      RECT 2805.48 0.84 2805.76 2321.76 ;
      RECT 2807.72 0.84 2808 2321.76 ;
      RECT 2809.96 0.84 2810.24 2321.76 ;
      RECT 2812.2 0.84 2812.48 2321.76 ;
      RECT 2814.44 0.84 2814.72 2321.76 ;
      RECT 2816.68 0.84 2816.96 2321.76 ;
      RECT 2818.92 0.84 2819.2 2321.76 ;
      RECT 2821.16 0.84 2821.44 2321.76 ;
      RECT 2823.4 0.84 2823.68 2321.76 ;
      RECT 2825.64 0.84 2825.92 2321.76 ;
      RECT 2827.88 0.84 2828.16 2321.76 ;
      RECT 2830.12 0.84 2830.4 2321.76 ;
      RECT 2832.36 0.84 2832.64 2321.76 ;
      RECT 2834.6 0.84 2834.88 2321.76 ;
      RECT 2836.84 0.84 2837.12 2321.76 ;
      RECT 2839.08 0.84 2839.36 2321.76 ;
      RECT 2841.32 0.84 2841.6 2321.76 ;
      RECT 2843.56 0.84 2843.84 2321.76 ;
      RECT 2845.8 0.84 2846.08 2321.76 ;
      RECT 2848.04 0.84 2848.32 2321.76 ;
      RECT 2850.28 0.84 2850.56 2321.76 ;
      RECT 2852.52 0.84 2852.8 2321.76 ;
      RECT 2854.76 0.84 2855.04 2321.76 ;
      RECT 2857 0.84 2857.28 2321.76 ;
      RECT 2859.24 0.84 2859.52 2321.76 ;
      RECT 2861.48 0.84 2861.76 2321.76 ;
      RECT 2863.72 0.84 2864 2321.76 ;
      RECT 2865.96 0.84 2866.24 2321.76 ;
      RECT 2868.2 0.84 2868.48 2321.76 ;
      RECT 2870.44 0.84 2870.72 2321.76 ;
      RECT 2872.68 0.84 2872.96 2321.76 ;
      RECT 2874.92 0.84 2875.2 2321.76 ;
      RECT 2877.16 0.84 2877.44 2321.76 ;
      RECT 2879.4 0.84 2879.68 2321.76 ;
      RECT 2881.64 0.84 2881.92 2321.76 ;
      RECT 2883.88 0.84 2884.16 2321.76 ;
      RECT 2886.12 0.84 2886.4 2321.76 ;
      RECT 2888.36 0.84 2888.64 2321.76 ;
      RECT 2890.6 0.84 2890.88 2321.76 ;
      RECT 2892.84 0.84 2893.12 2321.76 ;
      RECT 2895.08 0.84 2895.36 2321.76 ;
      RECT 2897.32 0.84 2897.6 2321.76 ;
      RECT 2899.56 0.84 2899.84 2321.76 ;
      RECT 2901.8 0.84 2902.08 2321.76 ;
      RECT 2904.04 0.84 2904.32 2321.76 ;
      RECT 2906.28 0.84 2906.56 2321.76 ;
      RECT 2908.52 0.84 2908.8 2321.76 ;
      RECT 2910.76 0.84 2911.04 2321.76 ;
      RECT 2913 0.84 2913.28 2321.76 ;
      RECT 2915.24 0.84 2915.52 2321.76 ;
      RECT 2917.48 0.84 2917.76 2321.76 ;
      RECT 2919.72 0.84 2920 2321.76 ;
      RECT 2921.96 0.84 2922.24 2321.76 ;
      RECT 2924.2 0.84 2924.48 2321.76 ;
      RECT 2926.44 0.84 2926.72 2321.76 ;
      RECT 2928.68 0.84 2928.96 2321.76 ;
      RECT 2930.92 0.84 2931.2 2321.76 ;
      RECT 2933.16 0.84 2933.44 2321.76 ;
      RECT 2935.4 0.84 2935.68 2321.76 ;
      RECT 2937.64 0.84 2937.92 2321.76 ;
      RECT 2939.88 0.84 2940.16 2321.76 ;
      RECT 2942.12 0.84 2942.4 2321.76 ;
      RECT 2944.36 0.84 2944.64 2321.76 ;
      RECT 2946.6 0.84 2946.88 2321.76 ;
      RECT 2948.84 0.84 2949.12 2321.76 ;
      RECT 2951.08 0.84 2951.36 2321.76 ;
      RECT 2953.32 0.84 2953.6 2321.76 ;
      RECT 2955.56 0.84 2955.84 2321.76 ;
      RECT 2957.8 0.84 2958.08 2321.76 ;
      RECT 2960.04 0.84 2960.32 2321.76 ;
      RECT 2962.28 0.84 2962.56 2321.76 ;
      RECT 2964.52 0.84 2964.8 2321.76 ;
      RECT 2966.76 0.84 2967.04 2321.76 ;
      RECT 2969 0.84 2969.28 2321.76 ;
      RECT 2971.24 0.84 2971.52 2321.76 ;
      RECT 2973.48 0.84 2973.76 2321.76 ;
      RECT 2975.72 0.84 2976 2321.76 ;
      RECT 2977.96 0.84 2978.24 2321.76 ;
      RECT 2980.2 0.84 2980.48 2321.76 ;
      RECT 2982.44 0.84 2982.72 2321.76 ;
      RECT 2984.68 0.84 2984.96 2321.76 ;
      RECT 2986.92 0.84 2987.2 2321.76 ;
      RECT 2989.16 0.84 2989.44 2321.76 ;
      RECT 2991.4 0.84 2991.68 2321.76 ;
      RECT 2993.64 0.84 2993.92 2321.76 ;
      RECT 2995.88 0.84 2996.16 2321.76 ;
      RECT 2998.12 0.84 2998.4 2321.76 ;
      RECT 3000.36 0.84 3000.64 2321.76 ;
      RECT 3002.6 0.84 3002.88 2321.76 ;
      RECT 3004.84 0.84 3005.12 2321.76 ;
      RECT 3007.08 0.84 3007.36 2321.76 ;
      RECT 3009.32 0.84 3009.6 2321.76 ;
      RECT 3011.56 0.84 3011.84 2321.76 ;
      RECT 3013.8 0.84 3014.08 2321.76 ;
      RECT 3016.04 0.84 3016.32 2321.76 ;
      RECT 3018.28 0.84 3018.56 2321.76 ;
      RECT 3020.52 0.84 3020.8 2321.76 ;
      RECT 3022.76 0.84 3023.04 2321.76 ;
      RECT 3025 0.84 3025.28 2321.76 ;
      RECT 3027.24 0.84 3027.52 2321.76 ;
      RECT 3029.48 0.84 3029.76 2321.76 ;
      RECT 3031.72 0.84 3032 2321.76 ;
      RECT 3033.96 0.84 3034.24 2321.76 ;
      RECT 3036.2 0.84 3036.48 2321.76 ;
      RECT 3038.44 0.84 3038.72 2321.76 ;
      RECT 3040.68 0.84 3040.96 2321.76 ;
      RECT 3042.92 0.84 3043.2 2321.76 ;
      RECT 3045.16 0.84 3045.44 2321.76 ;
      RECT 3047.4 0.84 3047.68 2321.76 ;
      RECT 3049.64 0.84 3049.92 2321.76 ;
      RECT 3051.88 0.84 3052.16 2321.76 ;
      RECT 3054.12 0.84 3054.4 2321.76 ;
      RECT 3056.36 0.84 3056.64 2321.76 ;
      RECT 3058.6 0.84 3058.88 2321.76 ;
      RECT 3060.84 0.84 3061.12 2321.76 ;
      RECT 3063.08 0.84 3063.36 2321.76 ;
      RECT 3065.32 0.84 3065.6 2321.76 ;
      RECT 3067.56 0.84 3067.84 2321.76 ;
      RECT 3069.8 0.84 3070.08 2321.76 ;
      RECT 3072.04 0.84 3072.32 2321.76 ;
      RECT 3074.28 0.84 3074.56 2321.76 ;
      RECT 3076.52 0.84 3076.8 2321.76 ;
      RECT 3078.76 0.84 3079.04 2321.76 ;
      RECT 3081 0.84 3081.28 2321.76 ;
      RECT 3083.24 0.84 3083.52 2321.76 ;
      RECT 3085.48 0.84 3085.76 2321.76 ;
      RECT 3087.72 0.84 3088 2321.76 ;
      RECT 3089.96 0.84 3090.24 2321.76 ;
      RECT 3092.2 0.84 3092.48 2321.76 ;
      RECT 3094.44 0.84 3094.72 2321.76 ;
      RECT 3096.68 0.84 3096.96 2321.76 ;
      RECT 3098.92 0.84 3099.2 2321.76 ;
      RECT 3101.16 0.84 3101.44 2321.76 ;
      RECT 3103.4 0.84 3103.68 2321.76 ;
      RECT 3105.64 0.84 3105.92 2321.76 ;
      RECT 3107.88 0.84 3108.16 2321.76 ;
      RECT 3110.12 0.84 3110.4 2321.76 ;
      RECT 3112.36 0.84 3112.64 2321.76 ;
      RECT 3114.6 0.84 3114.88 2321.76 ;
      RECT 3116.84 0.84 3117.12 2321.76 ;
      RECT 3119.08 0.84 3119.36 2321.76 ;
      RECT 3121.32 0.84 3121.6 2321.76 ;
      RECT 3123.56 0.84 3123.84 2321.76 ;
      RECT 3125.8 0.84 3126.08 2321.76 ;
      RECT 3128.04 0.84 3128.32 2321.76 ;
      RECT 3130.28 0.84 3130.56 2321.76 ;
      RECT 3132.52 0.84 3132.8 2321.76 ;
      RECT 3134.76 0.84 3135.04 2321.76 ;
      RECT 3137 0.84 3137.28 2321.76 ;
      RECT 3139.24 0.84 3139.52 2321.76 ;
      RECT 3141.48 0.84 3141.76 2321.76 ;
      RECT 3143.72 0.84 3144 2321.76 ;
      RECT 3145.96 0.84 3146.24 2321.76 ;
      RECT 3148.2 0.84 3148.48 2321.76 ;
      RECT 3150.44 0.84 3150.72 2321.76 ;
      RECT 3152.68 0.84 3152.96 2321.76 ;
      RECT 3154.92 0.84 3155.2 2321.76 ;
      RECT 3157.16 0.84 3157.44 2321.76 ;
      RECT 3159.4 0.84 3159.68 2321.76 ;
      RECT 3161.64 0.84 3161.92 2321.76 ;
      RECT 3163.88 0.84 3164.16 2321.76 ;
      RECT 3166.12 0.84 3166.4 2321.76 ;
      RECT 3168.36 0.84 3168.64 2321.76 ;
      RECT 3170.6 0.84 3170.88 2321.76 ;
      RECT 3172.84 0.84 3173.12 2321.76 ;
      RECT 3175.08 0.84 3175.36 2321.76 ;
      RECT 3177.32 0.84 3177.6 2321.76 ;
      RECT 3179.56 0.84 3179.84 2321.76 ;
      RECT 3181.8 0.84 3182.08 2321.76 ;
      RECT 3184.04 0.84 3184.32 2321.76 ;
      RECT 3186.28 0.84 3186.56 2321.76 ;
      RECT 3188.52 0.84 3188.8 2321.76 ;
      RECT 3190.76 0.84 3191.04 2321.76 ;
      RECT 3193 0.84 3193.28 2321.76 ;
      RECT 3195.24 0.84 3195.52 2321.76 ;
      RECT 3197.48 0.84 3197.76 2321.76 ;
      RECT 3199.72 0.84 3200 2321.76 ;
      RECT 3201.96 0.84 3202.24 2321.76 ;
      RECT 3204.2 0.84 3204.48 2321.76 ;
      RECT 3206.44 0.84 3206.72 2321.76 ;
      RECT 3208.68 0.84 3208.96 2321.76 ;
      RECT 3210.92 0.84 3211.2 2321.76 ;
      RECT 3213.16 0.84 3213.44 2321.76 ;
      RECT 3215.4 0.84 3215.68 2321.76 ;
      RECT 3217.64 0.84 3217.92 2321.76 ;
      RECT 3219.88 0.84 3220.16 2321.76 ;
      RECT 3222.12 0.84 3222.4 2321.76 ;
      RECT 3224.36 0.84 3224.64 2321.76 ;
      RECT 3226.6 0.84 3226.88 2321.76 ;
      RECT 3228.84 0.84 3229.12 2321.76 ;
      RECT 3231.08 0.84 3231.36 2321.76 ;
      RECT 3233.32 0.84 3233.6 2321.76 ;
      RECT 3235.56 0.84 3235.84 2321.76 ;
      RECT 3237.8 0.84 3238.08 2321.76 ;
      RECT 3240.04 0.84 3240.32 2321.76 ;
      RECT 3242.28 0.84 3242.56 2321.76 ;
      RECT 3244.52 0.84 3244.8 2321.76 ;
      RECT 3246.76 0.84 3247.04 2321.76 ;
      RECT 3249 0.84 3249.28 2321.76 ;
      RECT 3251.24 0.84 3251.52 2321.76 ;
      RECT 3253.48 0.84 3253.76 2321.76 ;
      RECT 3255.72 0.84 3256 2321.76 ;
      RECT 3257.96 0.84 3258.24 2321.76 ;
      RECT 3260.2 0.84 3260.48 2321.76 ;
      RECT 3262.44 0.84 3262.72 2321.76 ;
      RECT 3264.68 0.84 3264.96 2321.76 ;
      RECT 3266.92 0.84 3267.2 2321.76 ;
      RECT 3269.16 0.84 3269.44 2321.76 ;
      RECT 3271.4 0.84 3271.68 2321.76 ;
      RECT 3273.64 0.84 3273.92 2321.76 ;
      RECT 3275.88 0.84 3276.16 2321.76 ;
      RECT 3278.12 0.84 3278.4 2321.76 ;
      RECT 3280.36 0.84 3280.64 2321.76 ;
      RECT 3282.6 0.84 3282.88 2321.76 ;
      RECT 3284.84 0.84 3285.12 2321.76 ;
      RECT 3287.08 0.84 3287.36 2321.76 ;
      RECT 3289.32 0.84 3289.6 2321.76 ;
      RECT 3291.56 0.84 3291.84 2321.76 ;
      RECT 3293.8 0.84 3294.08 2321.76 ;
      RECT 3296.04 0.84 3296.32 2321.76 ;
      RECT 3298.28 0.84 3298.56 2321.76 ;
      RECT 3300.52 0.84 3300.8 2321.76 ;
      RECT 3302.76 0.84 3303.04 2321.76 ;
      RECT 3305 0.84 3305.28 2321.76 ;
      RECT 3307.24 0.84 3307.52 2321.76 ;
      RECT 3309.48 0.84 3309.76 2321.76 ;
      RECT 3311.72 0.84 3312 2321.76 ;
      RECT 3313.96 0.84 3314.24 2321.76 ;
      RECT 3316.2 0.84 3316.48 2321.76 ;
      RECT 3318.44 0.84 3318.72 2321.76 ;
      RECT 3320.68 0.84 3320.96 2321.76 ;
      RECT 3322.92 0.84 3323.2 2321.76 ;
      RECT 3325.16 0.84 3325.44 2321.76 ;
      RECT 3327.4 0.84 3327.68 2321.76 ;
      RECT 3329.64 0.84 3329.92 2321.76 ;
      RECT 3331.88 0.84 3332.16 2321.76 ;
      RECT 3334.12 0.84 3334.4 2321.76 ;
      RECT 3336.36 0.84 3336.64 2321.76 ;
      RECT 3338.6 0.84 3338.88 2321.76 ;
      RECT 3340.84 0.84 3341.12 2321.76 ;
      RECT 3343.08 0.84 3343.36 2321.76 ;
      RECT 3345.32 0.84 3345.6 2321.76 ;
      RECT 3347.56 0.84 3347.84 2321.76 ;
      RECT 3349.8 0.84 3350.08 2321.76 ;
      RECT 3352.04 0.84 3352.32 2321.76 ;
      RECT 3354.28 0.84 3354.56 2321.76 ;
      RECT 3356.52 0.84 3356.8 2321.76 ;
      RECT 3358.76 0.84 3359.04 2321.76 ;
      RECT 3361 0.84 3361.28 2321.76 ;
      RECT 3363.24 0.84 3363.52 2321.76 ;
      RECT 3365.48 0.84 3365.76 2321.76 ;
      RECT 3367.72 0.84 3368 2321.76 ;
      RECT 3369.96 0.84 3370.24 2321.76 ;
      RECT 3372.2 0.84 3372.48 2321.76 ;
      RECT 3374.44 0.84 3374.72 2321.76 ;
      RECT 3376.68 0.84 3376.96 2321.76 ;
      RECT 3378.92 0.84 3379.2 2321.76 ;
      RECT 3381.16 0.84 3381.44 2321.76 ;
      RECT 3383.4 0.84 3383.68 2321.76 ;
      RECT 3385.64 0.84 3385.92 2321.76 ;
      RECT 3387.88 0.84 3388.16 2321.76 ;
      RECT 3390.12 0.84 3390.4 2321.76 ;
      RECT 3392.36 0.84 3392.64 2321.76 ;
      RECT 3394.6 0.84 3394.88 2321.76 ;
      RECT 3396.84 0.84 3397.12 2321.76 ;
      RECT 3399.08 0.84 3399.36 2321.76 ;
      RECT 3401.32 0.84 3401.6 2321.76 ;
      RECT 3403.56 0.84 3403.84 2321.76 ;
      RECT 3405.8 0.84 3406.08 2321.76 ;
      RECT 3408.04 0.84 3408.32 2321.76 ;
      RECT 3410.28 0.84 3410.56 2321.76 ;
      RECT 3412.52 0.84 3412.8 2321.76 ;
      RECT 3414.76 0.84 3415.04 2321.76 ;
      RECT 3417 0.84 3417.28 2321.76 ;
      RECT 3419.24 0.84 3419.52 2321.76 ;
      RECT 3421.48 0.84 3421.76 2321.76 ;
      RECT 3423.72 0.84 3424 2321.76 ;
      RECT 3425.96 0.84 3426.24 2321.76 ;
      RECT 3428.2 0.84 3428.48 2321.76 ;
      RECT 3430.44 0.84 3430.72 2321.76 ;
      RECT 3432.68 0.84 3432.96 2321.76 ;
      RECT 3434.92 0.84 3435.2 2321.76 ;
      RECT 3437.16 0.84 3437.44 2321.76 ;
      RECT 3439.4 0.84 3439.68 2321.76 ;
      RECT 3441.64 0.84 3441.92 2321.76 ;
      RECT 3443.88 0.84 3444.16 2321.76 ;
      RECT 3446.12 0.84 3446.4 2321.76 ;
      RECT 3448.36 0.84 3448.64 2321.76 ;
      RECT 3450.6 0.84 3450.88 2321.76 ;
      RECT 3452.84 0.84 3453.12 2321.76 ;
      RECT 3455.08 0.84 3455.36 2321.76 ;
      RECT 3457.32 0.84 3457.6 2321.76 ;
      RECT 3459.56 0.84 3459.84 2321.76 ;
      RECT 3461.8 0.84 3462.08 2321.76 ;
      RECT 3464.04 0.84 3464.32 2321.76 ;
      RECT 3466.28 0.84 3466.56 2321.76 ;
      RECT 3468.52 0.84 3468.8 2321.76 ;
      RECT 3470.76 0.84 3471.04 2321.76 ;
      RECT 3473 0.84 3473.28 2321.76 ;
      RECT 3475.24 0.84 3475.52 2321.76 ;
      RECT 3477.48 0.84 3477.76 2321.76 ;
      RECT 3479.72 0.84 3480 2321.76 ;
      RECT 3481.96 0.84 3482.24 2321.76 ;
      RECT 3484.2 0.84 3484.48 2321.76 ;
      RECT 3486.44 0.84 3486.72 2321.76 ;
      RECT 3488.68 0.84 3488.96 2321.76 ;
      RECT 3490.92 0.84 3491.2 2321.76 ;
      RECT 3493.16 0.84 3493.44 2321.76 ;
      RECT 3495.4 0.84 3495.68 2321.76 ;
      RECT 3497.64 0.84 3497.92 2321.76 ;
      RECT 3499.88 0.84 3500.16 2321.76 ;
      RECT 3502.12 0.84 3502.4 2321.76 ;
      RECT 3504.36 0.84 3504.64 2321.76 ;
      RECT 3506.6 0.84 3506.88 2321.76 ;
      RECT 3508.84 0.84 3509.12 2321.76 ;
      RECT 3511.08 0.84 3511.36 2321.76 ;
      RECT 3513.32 0.84 3513.6 2321.76 ;
      RECT 3515.56 0.84 3515.84 2321.76 ;
      RECT 3517.8 0.84 3518.08 2321.76 ;
      RECT 3520.04 0.84 3520.32 2321.76 ;
      RECT 3522.28 0.84 3522.56 2321.76 ;
      RECT 3524.52 0.84 3524.8 2321.76 ;
      RECT 3526.76 0.84 3527.04 2321.76 ;
      RECT 3529 0.84 3529.28 2321.76 ;
      RECT 3531.24 0.84 3531.52 2321.76 ;
      RECT 3533.48 0.84 3533.76 2321.76 ;
      RECT 3535.72 0.84 3536 2321.76 ;
      RECT 3537.96 0.84 3538.24 2321.76 ;
      RECT 3540.2 0.84 3540.48 2321.76 ;
      RECT 3542.44 0.84 3542.72 2321.76 ;
      RECT 3544.68 0.84 3544.96 2321.76 ;
      RECT 3546.92 0.84 3547.2 2321.76 ;
      RECT 3549.16 0.84 3549.44 2321.76 ;
      RECT 3551.4 0.84 3551.68 2321.76 ;
      RECT 3553.64 0.84 3553.92 2321.76 ;
      RECT 3555.88 0.84 3556.16 2321.76 ;
      RECT 3558.12 0.84 3558.4 2321.76 ;
      RECT 3560.36 0.84 3560.64 2321.76 ;
      RECT 3562.6 0.84 3562.88 2321.76 ;
      RECT 3564.84 0.84 3565.12 2321.76 ;
      RECT 3567.08 0.84 3567.36 2321.76 ;
      RECT 3569.32 0.84 3569.6 2321.76 ;
      RECT 3571.56 0.84 3571.84 2321.76 ;
      RECT 3573.8 0.84 3574.08 2321.76 ;
      RECT 3576.04 0.84 3576.32 2321.76 ;
      RECT 3578.28 0.84 3578.56 2321.76 ;
      RECT 3580.52 0.84 3580.8 2321.76 ;
      RECT 3582.76 0.84 3583.04 2321.76 ;
      RECT 3585 0.84 3585.28 2321.76 ;
      RECT 3587.24 0.84 3587.52 2321.76 ;
      RECT 3589.48 0.84 3589.76 2321.76 ;
      RECT 3591.72 0.84 3592 2321.76 ;
      RECT 3593.96 0.84 3594.24 2321.76 ;
      RECT 3596.2 0.84 3596.48 2321.76 ;
      RECT 3598.44 0.84 3598.72 2321.76 ;
      RECT 3600.68 0.84 3600.96 2321.76 ;
      RECT 3602.92 0.84 3603.2 2321.76 ;
      RECT 3605.16 0.84 3605.44 2321.76 ;
      RECT 3607.4 0.84 3607.68 2321.76 ;
      RECT 3609.64 0.84 3609.92 2321.76 ;
      RECT 3611.88 0.84 3612.16 2321.76 ;
      RECT 3614.12 0.84 3614.4 2321.76 ;
      RECT 3616.36 0.84 3616.64 2321.76 ;
      RECT 3618.6 0.84 3618.88 2321.76 ;
      RECT 3620.84 0.84 3621.12 2321.76 ;
      RECT 3623.08 0.84 3623.36 2321.76 ;
      RECT 3625.32 0.84 3625.6 2321.76 ;
      RECT 3627.56 0.84 3627.84 2321.76 ;
      RECT 3629.8 0.84 3630.08 2321.76 ;
      RECT 3632.04 0.84 3632.32 2321.76 ;
      RECT 3634.28 0.84 3634.56 2321.76 ;
      RECT 3636.52 0.84 3636.8 2321.76 ;
      RECT 3638.76 0.84 3639.04 2321.76 ;
      RECT 3641 0.84 3641.28 2321.76 ;
      RECT 3643.24 0.84 3643.52 2321.76 ;
      RECT 3645.48 0.84 3645.76 2321.76 ;
      RECT 3647.72 0.84 3648 2321.76 ;
      RECT 3649.96 0.84 3650.24 2321.76 ;
      RECT 3652.2 0.84 3652.48 2321.76 ;
      RECT 3654.44 0.84 3654.72 2321.76 ;
      RECT 3656.68 0.84 3656.96 2321.76 ;
      RECT 3658.92 0.84 3659.2 2321.76 ;
    END
  END VSS
  PIN VDD
    DIRECTION INOUT ;
    USE POWER ;
    PORT
      LAYER M4_m ;
      RECT 2.12 0.84 2.4 2321.76 ;
      RECT 4.36 0.84 4.64 2321.76 ;
      RECT 6.6 0.84 6.88 2321.76 ;
      RECT 8.84 0.84 9.12 2321.76 ;
      RECT 11.08 0.84 11.36 2321.76 ;
      RECT 13.32 0.84 13.6 2321.76 ;
      RECT 15.56 0.84 15.84 2321.76 ;
      RECT 17.8 0.84 18.08 2321.76 ;
      RECT 20.04 0.84 20.32 2321.76 ;
      RECT 22.28 0.84 22.56 2321.76 ;
      RECT 24.52 0.84 24.8 2321.76 ;
      RECT 26.76 0.84 27.04 2321.76 ;
      RECT 29 0.84 29.28 2321.76 ;
      RECT 31.24 0.84 31.52 2321.76 ;
      RECT 33.48 0.84 33.76 2321.76 ;
      RECT 35.72 0.84 36 2321.76 ;
      RECT 37.96 0.84 38.24 2321.76 ;
      RECT 40.2 0.84 40.48 2321.76 ;
      RECT 42.44 0.84 42.72 2321.76 ;
      RECT 44.68 0.84 44.96 2321.76 ;
      RECT 46.92 0.84 47.2 2321.76 ;
      RECT 49.16 0.84 49.44 2321.76 ;
      RECT 51.4 0.84 51.68 2321.76 ;
      RECT 53.64 0.84 53.92 2321.76 ;
      RECT 55.88 0.84 56.16 2321.76 ;
      RECT 58.12 0.84 58.4 2321.76 ;
      RECT 60.36 0.84 60.64 2321.76 ;
      RECT 62.6 0.84 62.88 2321.76 ;
      RECT 64.84 0.84 65.12 2321.76 ;
      RECT 67.08 0.84 67.36 2321.76 ;
      RECT 69.32 0.84 69.6 2321.76 ;
      RECT 71.56 0.84 71.84 2321.76 ;
      RECT 73.8 0.84 74.08 2321.76 ;
      RECT 76.04 0.84 76.32 2321.76 ;
      RECT 78.28 0.84 78.56 2321.76 ;
      RECT 80.52 0.84 80.8 2321.76 ;
      RECT 82.76 0.84 83.04 2321.76 ;
      RECT 85 0.84 85.28 2321.76 ;
      RECT 87.24 0.84 87.52 2321.76 ;
      RECT 89.48 0.84 89.76 2321.76 ;
      RECT 91.72 0.84 92 2321.76 ;
      RECT 93.96 0.84 94.24 2321.76 ;
      RECT 96.2 0.84 96.48 2321.76 ;
      RECT 98.44 0.84 98.72 2321.76 ;
      RECT 100.68 0.84 100.96 2321.76 ;
      RECT 102.92 0.84 103.2 2321.76 ;
      RECT 105.16 0.84 105.44 2321.76 ;
      RECT 107.4 0.84 107.68 2321.76 ;
      RECT 109.64 0.84 109.92 2321.76 ;
      RECT 111.88 0.84 112.16 2321.76 ;
      RECT 114.12 0.84 114.4 2321.76 ;
      RECT 116.36 0.84 116.64 2321.76 ;
      RECT 118.6 0.84 118.88 2321.76 ;
      RECT 120.84 0.84 121.12 2321.76 ;
      RECT 123.08 0.84 123.36 2321.76 ;
      RECT 125.32 0.84 125.6 2321.76 ;
      RECT 127.56 0.84 127.84 2321.76 ;
      RECT 129.8 0.84 130.08 2321.76 ;
      RECT 132.04 0.84 132.32 2321.76 ;
      RECT 134.28 0.84 134.56 2321.76 ;
      RECT 136.52 0.84 136.8 2321.76 ;
      RECT 138.76 0.84 139.04 2321.76 ;
      RECT 141 0.84 141.28 2321.76 ;
      RECT 143.24 0.84 143.52 2321.76 ;
      RECT 145.48 0.84 145.76 2321.76 ;
      RECT 147.72 0.84 148 2321.76 ;
      RECT 149.96 0.84 150.24 2321.76 ;
      RECT 152.2 0.84 152.48 2321.76 ;
      RECT 154.44 0.84 154.72 2321.76 ;
      RECT 156.68 0.84 156.96 2321.76 ;
      RECT 158.92 0.84 159.2 2321.76 ;
      RECT 161.16 0.84 161.44 2321.76 ;
      RECT 163.4 0.84 163.68 2321.76 ;
      RECT 165.64 0.84 165.92 2321.76 ;
      RECT 167.88 0.84 168.16 2321.76 ;
      RECT 170.12 0.84 170.4 2321.76 ;
      RECT 172.36 0.84 172.64 2321.76 ;
      RECT 174.6 0.84 174.88 2321.76 ;
      RECT 176.84 0.84 177.12 2321.76 ;
      RECT 179.08 0.84 179.36 2321.76 ;
      RECT 181.32 0.84 181.6 2321.76 ;
      RECT 183.56 0.84 183.84 2321.76 ;
      RECT 185.8 0.84 186.08 2321.76 ;
      RECT 188.04 0.84 188.32 2321.76 ;
      RECT 190.28 0.84 190.56 2321.76 ;
      RECT 192.52 0.84 192.8 2321.76 ;
      RECT 194.76 0.84 195.04 2321.76 ;
      RECT 197 0.84 197.28 2321.76 ;
      RECT 199.24 0.84 199.52 2321.76 ;
      RECT 201.48 0.84 201.76 2321.76 ;
      RECT 203.72 0.84 204 2321.76 ;
      RECT 205.96 0.84 206.24 2321.76 ;
      RECT 208.2 0.84 208.48 2321.76 ;
      RECT 210.44 0.84 210.72 2321.76 ;
      RECT 212.68 0.84 212.96 2321.76 ;
      RECT 214.92 0.84 215.2 2321.76 ;
      RECT 217.16 0.84 217.44 2321.76 ;
      RECT 219.4 0.84 219.68 2321.76 ;
      RECT 221.64 0.84 221.92 2321.76 ;
      RECT 223.88 0.84 224.16 2321.76 ;
      RECT 226.12 0.84 226.4 2321.76 ;
      RECT 228.36 0.84 228.64 2321.76 ;
      RECT 230.6 0.84 230.88 2321.76 ;
      RECT 232.84 0.84 233.12 2321.76 ;
      RECT 235.08 0.84 235.36 2321.76 ;
      RECT 237.32 0.84 237.6 2321.76 ;
      RECT 239.56 0.84 239.84 2321.76 ;
      RECT 241.8 0.84 242.08 2321.76 ;
      RECT 244.04 0.84 244.32 2321.76 ;
      RECT 246.28 0.84 246.56 2321.76 ;
      RECT 248.52 0.84 248.8 2321.76 ;
      RECT 250.76 0.84 251.04 2321.76 ;
      RECT 253 0.84 253.28 2321.76 ;
      RECT 255.24 0.84 255.52 2321.76 ;
      RECT 257.48 0.84 257.76 2321.76 ;
      RECT 259.72 0.84 260 2321.76 ;
      RECT 261.96 0.84 262.24 2321.76 ;
      RECT 264.2 0.84 264.48 2321.76 ;
      RECT 266.44 0.84 266.72 2321.76 ;
      RECT 268.68 0.84 268.96 2321.76 ;
      RECT 270.92 0.84 271.2 2321.76 ;
      RECT 273.16 0.84 273.44 2321.76 ;
      RECT 275.4 0.84 275.68 2321.76 ;
      RECT 277.64 0.84 277.92 2321.76 ;
      RECT 279.88 0.84 280.16 2321.76 ;
      RECT 282.12 0.84 282.4 2321.76 ;
      RECT 284.36 0.84 284.64 2321.76 ;
      RECT 286.6 0.84 286.88 2321.76 ;
      RECT 288.84 0.84 289.12 2321.76 ;
      RECT 291.08 0.84 291.36 2321.76 ;
      RECT 293.32 0.84 293.6 2321.76 ;
      RECT 295.56 0.84 295.84 2321.76 ;
      RECT 297.8 0.84 298.08 2321.76 ;
      RECT 300.04 0.84 300.32 2321.76 ;
      RECT 302.28 0.84 302.56 2321.76 ;
      RECT 304.52 0.84 304.8 2321.76 ;
      RECT 306.76 0.84 307.04 2321.76 ;
      RECT 309 0.84 309.28 2321.76 ;
      RECT 311.24 0.84 311.52 2321.76 ;
      RECT 313.48 0.84 313.76 2321.76 ;
      RECT 315.72 0.84 316 2321.76 ;
      RECT 317.96 0.84 318.24 2321.76 ;
      RECT 320.2 0.84 320.48 2321.76 ;
      RECT 322.44 0.84 322.72 2321.76 ;
      RECT 324.68 0.84 324.96 2321.76 ;
      RECT 326.92 0.84 327.2 2321.76 ;
      RECT 329.16 0.84 329.44 2321.76 ;
      RECT 331.4 0.84 331.68 2321.76 ;
      RECT 333.64 0.84 333.92 2321.76 ;
      RECT 335.88 0.84 336.16 2321.76 ;
      RECT 338.12 0.84 338.4 2321.76 ;
      RECT 340.36 0.84 340.64 2321.76 ;
      RECT 342.6 0.84 342.88 2321.76 ;
      RECT 344.84 0.84 345.12 2321.76 ;
      RECT 347.08 0.84 347.36 2321.76 ;
      RECT 349.32 0.84 349.6 2321.76 ;
      RECT 351.56 0.84 351.84 2321.76 ;
      RECT 353.8 0.84 354.08 2321.76 ;
      RECT 356.04 0.84 356.32 2321.76 ;
      RECT 358.28 0.84 358.56 2321.76 ;
      RECT 360.52 0.84 360.8 2321.76 ;
      RECT 362.76 0.84 363.04 2321.76 ;
      RECT 365 0.84 365.28 2321.76 ;
      RECT 367.24 0.84 367.52 2321.76 ;
      RECT 369.48 0.84 369.76 2321.76 ;
      RECT 371.72 0.84 372 2321.76 ;
      RECT 373.96 0.84 374.24 2321.76 ;
      RECT 376.2 0.84 376.48 2321.76 ;
      RECT 378.44 0.84 378.72 2321.76 ;
      RECT 380.68 0.84 380.96 2321.76 ;
      RECT 382.92 0.84 383.2 2321.76 ;
      RECT 385.16 0.84 385.44 2321.76 ;
      RECT 387.4 0.84 387.68 2321.76 ;
      RECT 389.64 0.84 389.92 2321.76 ;
      RECT 391.88 0.84 392.16 2321.76 ;
      RECT 394.12 0.84 394.4 2321.76 ;
      RECT 396.36 0.84 396.64 2321.76 ;
      RECT 398.6 0.84 398.88 2321.76 ;
      RECT 400.84 0.84 401.12 2321.76 ;
      RECT 403.08 0.84 403.36 2321.76 ;
      RECT 405.32 0.84 405.6 2321.76 ;
      RECT 407.56 0.84 407.84 2321.76 ;
      RECT 409.8 0.84 410.08 2321.76 ;
      RECT 412.04 0.84 412.32 2321.76 ;
      RECT 414.28 0.84 414.56 2321.76 ;
      RECT 416.52 0.84 416.8 2321.76 ;
      RECT 418.76 0.84 419.04 2321.76 ;
      RECT 421 0.84 421.28 2321.76 ;
      RECT 423.24 0.84 423.52 2321.76 ;
      RECT 425.48 0.84 425.76 2321.76 ;
      RECT 427.72 0.84 428 2321.76 ;
      RECT 429.96 0.84 430.24 2321.76 ;
      RECT 432.2 0.84 432.48 2321.76 ;
      RECT 434.44 0.84 434.72 2321.76 ;
      RECT 436.68 0.84 436.96 2321.76 ;
      RECT 438.92 0.84 439.2 2321.76 ;
      RECT 441.16 0.84 441.44 2321.76 ;
      RECT 443.4 0.84 443.68 2321.76 ;
      RECT 445.64 0.84 445.92 2321.76 ;
      RECT 447.88 0.84 448.16 2321.76 ;
      RECT 450.12 0.84 450.4 2321.76 ;
      RECT 452.36 0.84 452.64 2321.76 ;
      RECT 454.6 0.84 454.88 2321.76 ;
      RECT 456.84 0.84 457.12 2321.76 ;
      RECT 459.08 0.84 459.36 2321.76 ;
      RECT 461.32 0.84 461.6 2321.76 ;
      RECT 463.56 0.84 463.84 2321.76 ;
      RECT 465.8 0.84 466.08 2321.76 ;
      RECT 468.04 0.84 468.32 2321.76 ;
      RECT 470.28 0.84 470.56 2321.76 ;
      RECT 472.52 0.84 472.8 2321.76 ;
      RECT 474.76 0.84 475.04 2321.76 ;
      RECT 477 0.84 477.28 2321.76 ;
      RECT 479.24 0.84 479.52 2321.76 ;
      RECT 481.48 0.84 481.76 2321.76 ;
      RECT 483.72 0.84 484 2321.76 ;
      RECT 485.96 0.84 486.24 2321.76 ;
      RECT 488.2 0.84 488.48 2321.76 ;
      RECT 490.44 0.84 490.72 2321.76 ;
      RECT 492.68 0.84 492.96 2321.76 ;
      RECT 494.92 0.84 495.2 2321.76 ;
      RECT 497.16 0.84 497.44 2321.76 ;
      RECT 499.4 0.84 499.68 2321.76 ;
      RECT 501.64 0.84 501.92 2321.76 ;
      RECT 503.88 0.84 504.16 2321.76 ;
      RECT 506.12 0.84 506.4 2321.76 ;
      RECT 508.36 0.84 508.64 2321.76 ;
      RECT 510.6 0.84 510.88 2321.76 ;
      RECT 512.84 0.84 513.12 2321.76 ;
      RECT 515.08 0.84 515.36 2321.76 ;
      RECT 517.32 0.84 517.6 2321.76 ;
      RECT 519.56 0.84 519.84 2321.76 ;
      RECT 521.8 0.84 522.08 2321.76 ;
      RECT 524.04 0.84 524.32 2321.76 ;
      RECT 526.28 0.84 526.56 2321.76 ;
      RECT 528.52 0.84 528.8 2321.76 ;
      RECT 530.76 0.84 531.04 2321.76 ;
      RECT 533 0.84 533.28 2321.76 ;
      RECT 535.24 0.84 535.52 2321.76 ;
      RECT 537.48 0.84 537.76 2321.76 ;
      RECT 539.72 0.84 540 2321.76 ;
      RECT 541.96 0.84 542.24 2321.76 ;
      RECT 544.2 0.84 544.48 2321.76 ;
      RECT 546.44 0.84 546.72 2321.76 ;
      RECT 548.68 0.84 548.96 2321.76 ;
      RECT 550.92 0.84 551.2 2321.76 ;
      RECT 553.16 0.84 553.44 2321.76 ;
      RECT 555.4 0.84 555.68 2321.76 ;
      RECT 557.64 0.84 557.92 2321.76 ;
      RECT 559.88 0.84 560.16 2321.76 ;
      RECT 562.12 0.84 562.4 2321.76 ;
      RECT 564.36 0.84 564.64 2321.76 ;
      RECT 566.6 0.84 566.88 2321.76 ;
      RECT 568.84 0.84 569.12 2321.76 ;
      RECT 571.08 0.84 571.36 2321.76 ;
      RECT 573.32 0.84 573.6 2321.76 ;
      RECT 575.56 0.84 575.84 2321.76 ;
      RECT 577.8 0.84 578.08 2321.76 ;
      RECT 580.04 0.84 580.32 2321.76 ;
      RECT 582.28 0.84 582.56 2321.76 ;
      RECT 584.52 0.84 584.8 2321.76 ;
      RECT 586.76 0.84 587.04 2321.76 ;
      RECT 589 0.84 589.28 2321.76 ;
      RECT 591.24 0.84 591.52 2321.76 ;
      RECT 593.48 0.84 593.76 2321.76 ;
      RECT 595.72 0.84 596 2321.76 ;
      RECT 597.96 0.84 598.24 2321.76 ;
      RECT 600.2 0.84 600.48 2321.76 ;
      RECT 602.44 0.84 602.72 2321.76 ;
      RECT 604.68 0.84 604.96 2321.76 ;
      RECT 606.92 0.84 607.2 2321.76 ;
      RECT 609.16 0.84 609.44 2321.76 ;
      RECT 611.4 0.84 611.68 2321.76 ;
      RECT 613.64 0.84 613.92 2321.76 ;
      RECT 615.88 0.84 616.16 2321.76 ;
      RECT 618.12 0.84 618.4 2321.76 ;
      RECT 620.36 0.84 620.64 2321.76 ;
      RECT 622.6 0.84 622.88 2321.76 ;
      RECT 624.84 0.84 625.12 2321.76 ;
      RECT 627.08 0.84 627.36 2321.76 ;
      RECT 629.32 0.84 629.6 2321.76 ;
      RECT 631.56 0.84 631.84 2321.76 ;
      RECT 633.8 0.84 634.08 2321.76 ;
      RECT 636.04 0.84 636.32 2321.76 ;
      RECT 638.28 0.84 638.56 2321.76 ;
      RECT 640.52 0.84 640.8 2321.76 ;
      RECT 642.76 0.84 643.04 2321.76 ;
      RECT 645 0.84 645.28 2321.76 ;
      RECT 647.24 0.84 647.52 2321.76 ;
      RECT 649.48 0.84 649.76 2321.76 ;
      RECT 651.72 0.84 652 2321.76 ;
      RECT 653.96 0.84 654.24 2321.76 ;
      RECT 656.2 0.84 656.48 2321.76 ;
      RECT 658.44 0.84 658.72 2321.76 ;
      RECT 660.68 0.84 660.96 2321.76 ;
      RECT 662.92 0.84 663.2 2321.76 ;
      RECT 665.16 0.84 665.44 2321.76 ;
      RECT 667.4 0.84 667.68 2321.76 ;
      RECT 669.64 0.84 669.92 2321.76 ;
      RECT 671.88 0.84 672.16 2321.76 ;
      RECT 674.12 0.84 674.4 2321.76 ;
      RECT 676.36 0.84 676.64 2321.76 ;
      RECT 678.6 0.84 678.88 2321.76 ;
      RECT 680.84 0.84 681.12 2321.76 ;
      RECT 683.08 0.84 683.36 2321.76 ;
      RECT 685.32 0.84 685.6 2321.76 ;
      RECT 687.56 0.84 687.84 2321.76 ;
      RECT 689.8 0.84 690.08 2321.76 ;
      RECT 692.04 0.84 692.32 2321.76 ;
      RECT 694.28 0.84 694.56 2321.76 ;
      RECT 696.52 0.84 696.8 2321.76 ;
      RECT 698.76 0.84 699.04 2321.76 ;
      RECT 701 0.84 701.28 2321.76 ;
      RECT 703.24 0.84 703.52 2321.76 ;
      RECT 705.48 0.84 705.76 2321.76 ;
      RECT 707.72 0.84 708 2321.76 ;
      RECT 709.96 0.84 710.24 2321.76 ;
      RECT 712.2 0.84 712.48 2321.76 ;
      RECT 714.44 0.84 714.72 2321.76 ;
      RECT 716.68 0.84 716.96 2321.76 ;
      RECT 718.92 0.84 719.2 2321.76 ;
      RECT 721.16 0.84 721.44 2321.76 ;
      RECT 723.4 0.84 723.68 2321.76 ;
      RECT 725.64 0.84 725.92 2321.76 ;
      RECT 727.88 0.84 728.16 2321.76 ;
      RECT 730.12 0.84 730.4 2321.76 ;
      RECT 732.36 0.84 732.64 2321.76 ;
      RECT 734.6 0.84 734.88 2321.76 ;
      RECT 736.84 0.84 737.12 2321.76 ;
      RECT 739.08 0.84 739.36 2321.76 ;
      RECT 741.32 0.84 741.6 2321.76 ;
      RECT 743.56 0.84 743.84 2321.76 ;
      RECT 745.8 0.84 746.08 2321.76 ;
      RECT 748.04 0.84 748.32 2321.76 ;
      RECT 750.28 0.84 750.56 2321.76 ;
      RECT 752.52 0.84 752.8 2321.76 ;
      RECT 754.76 0.84 755.04 2321.76 ;
      RECT 757 0.84 757.28 2321.76 ;
      RECT 759.24 0.84 759.52 2321.76 ;
      RECT 761.48 0.84 761.76 2321.76 ;
      RECT 763.72 0.84 764 2321.76 ;
      RECT 765.96 0.84 766.24 2321.76 ;
      RECT 768.2 0.84 768.48 2321.76 ;
      RECT 770.44 0.84 770.72 2321.76 ;
      RECT 772.68 0.84 772.96 2321.76 ;
      RECT 774.92 0.84 775.2 2321.76 ;
      RECT 777.16 0.84 777.44 2321.76 ;
      RECT 779.4 0.84 779.68 2321.76 ;
      RECT 781.64 0.84 781.92 2321.76 ;
      RECT 783.88 0.84 784.16 2321.76 ;
      RECT 786.12 0.84 786.4 2321.76 ;
      RECT 788.36 0.84 788.64 2321.76 ;
      RECT 790.6 0.84 790.88 2321.76 ;
      RECT 792.84 0.84 793.12 2321.76 ;
      RECT 795.08 0.84 795.36 2321.76 ;
      RECT 797.32 0.84 797.6 2321.76 ;
      RECT 799.56 0.84 799.84 2321.76 ;
      RECT 801.8 0.84 802.08 2321.76 ;
      RECT 804.04 0.84 804.32 2321.76 ;
      RECT 806.28 0.84 806.56 2321.76 ;
      RECT 808.52 0.84 808.8 2321.76 ;
      RECT 810.76 0.84 811.04 2321.76 ;
      RECT 813 0.84 813.28 2321.76 ;
      RECT 815.24 0.84 815.52 2321.76 ;
      RECT 817.48 0.84 817.76 2321.76 ;
      RECT 819.72 0.84 820 2321.76 ;
      RECT 821.96 0.84 822.24 2321.76 ;
      RECT 824.2 0.84 824.48 2321.76 ;
      RECT 826.44 0.84 826.72 2321.76 ;
      RECT 828.68 0.84 828.96 2321.76 ;
      RECT 830.92 0.84 831.2 2321.76 ;
      RECT 833.16 0.84 833.44 2321.76 ;
      RECT 835.4 0.84 835.68 2321.76 ;
      RECT 837.64 0.84 837.92 2321.76 ;
      RECT 839.88 0.84 840.16 2321.76 ;
      RECT 842.12 0.84 842.4 2321.76 ;
      RECT 844.36 0.84 844.64 2321.76 ;
      RECT 846.6 0.84 846.88 2321.76 ;
      RECT 848.84 0.84 849.12 2321.76 ;
      RECT 851.08 0.84 851.36 2321.76 ;
      RECT 853.32 0.84 853.6 2321.76 ;
      RECT 855.56 0.84 855.84 2321.76 ;
      RECT 857.8 0.84 858.08 2321.76 ;
      RECT 860.04 0.84 860.32 2321.76 ;
      RECT 862.28 0.84 862.56 2321.76 ;
      RECT 864.52 0.84 864.8 2321.76 ;
      RECT 866.76 0.84 867.04 2321.76 ;
      RECT 869 0.84 869.28 2321.76 ;
      RECT 871.24 0.84 871.52 2321.76 ;
      RECT 873.48 0.84 873.76 2321.76 ;
      RECT 875.72 0.84 876 2321.76 ;
      RECT 877.96 0.84 878.24 2321.76 ;
      RECT 880.2 0.84 880.48 2321.76 ;
      RECT 882.44 0.84 882.72 2321.76 ;
      RECT 884.68 0.84 884.96 2321.76 ;
      RECT 886.92 0.84 887.2 2321.76 ;
      RECT 889.16 0.84 889.44 2321.76 ;
      RECT 891.4 0.84 891.68 2321.76 ;
      RECT 893.64 0.84 893.92 2321.76 ;
      RECT 895.88 0.84 896.16 2321.76 ;
      RECT 898.12 0.84 898.4 2321.76 ;
      RECT 900.36 0.84 900.64 2321.76 ;
      RECT 902.6 0.84 902.88 2321.76 ;
      RECT 904.84 0.84 905.12 2321.76 ;
      RECT 907.08 0.84 907.36 2321.76 ;
      RECT 909.32 0.84 909.6 2321.76 ;
      RECT 911.56 0.84 911.84 2321.76 ;
      RECT 913.8 0.84 914.08 2321.76 ;
      RECT 916.04 0.84 916.32 2321.76 ;
      RECT 918.28 0.84 918.56 2321.76 ;
      RECT 920.52 0.84 920.8 2321.76 ;
      RECT 922.76 0.84 923.04 2321.76 ;
      RECT 925 0.84 925.28 2321.76 ;
      RECT 927.24 0.84 927.52 2321.76 ;
      RECT 929.48 0.84 929.76 2321.76 ;
      RECT 931.72 0.84 932 2321.76 ;
      RECT 933.96 0.84 934.24 2321.76 ;
      RECT 936.2 0.84 936.48 2321.76 ;
      RECT 938.44 0.84 938.72 2321.76 ;
      RECT 940.68 0.84 940.96 2321.76 ;
      RECT 942.92 0.84 943.2 2321.76 ;
      RECT 945.16 0.84 945.44 2321.76 ;
      RECT 947.4 0.84 947.68 2321.76 ;
      RECT 949.64 0.84 949.92 2321.76 ;
      RECT 951.88 0.84 952.16 2321.76 ;
      RECT 954.12 0.84 954.4 2321.76 ;
      RECT 956.36 0.84 956.64 2321.76 ;
      RECT 958.6 0.84 958.88 2321.76 ;
      RECT 960.84 0.84 961.12 2321.76 ;
      RECT 963.08 0.84 963.36 2321.76 ;
      RECT 965.32 0.84 965.6 2321.76 ;
      RECT 967.56 0.84 967.84 2321.76 ;
      RECT 969.8 0.84 970.08 2321.76 ;
      RECT 972.04 0.84 972.32 2321.76 ;
      RECT 974.28 0.84 974.56 2321.76 ;
      RECT 976.52 0.84 976.8 2321.76 ;
      RECT 978.76 0.84 979.04 2321.76 ;
      RECT 981 0.84 981.28 2321.76 ;
      RECT 983.24 0.84 983.52 2321.76 ;
      RECT 985.48 0.84 985.76 2321.76 ;
      RECT 987.72 0.84 988 2321.76 ;
      RECT 989.96 0.84 990.24 2321.76 ;
      RECT 992.2 0.84 992.48 2321.76 ;
      RECT 994.44 0.84 994.72 2321.76 ;
      RECT 996.68 0.84 996.96 2321.76 ;
      RECT 998.92 0.84 999.2 2321.76 ;
      RECT 1001.16 0.84 1001.44 2321.76 ;
      RECT 1003.4 0.84 1003.68 2321.76 ;
      RECT 1005.64 0.84 1005.92 2321.76 ;
      RECT 1007.88 0.84 1008.16 2321.76 ;
      RECT 1010.12 0.84 1010.4 2321.76 ;
      RECT 1012.36 0.84 1012.64 2321.76 ;
      RECT 1014.6 0.84 1014.88 2321.76 ;
      RECT 1016.84 0.84 1017.12 2321.76 ;
      RECT 1019.08 0.84 1019.36 2321.76 ;
      RECT 1021.32 0.84 1021.6 2321.76 ;
      RECT 1023.56 0.84 1023.84 2321.76 ;
      RECT 1025.8 0.84 1026.08 2321.76 ;
      RECT 1028.04 0.84 1028.32 2321.76 ;
      RECT 1030.28 0.84 1030.56 2321.76 ;
      RECT 1032.52 0.84 1032.8 2321.76 ;
      RECT 1034.76 0.84 1035.04 2321.76 ;
      RECT 1037 0.84 1037.28 2321.76 ;
      RECT 1039.24 0.84 1039.52 2321.76 ;
      RECT 1041.48 0.84 1041.76 2321.76 ;
      RECT 1043.72 0.84 1044 2321.76 ;
      RECT 1045.96 0.84 1046.24 2321.76 ;
      RECT 1048.2 0.84 1048.48 2321.76 ;
      RECT 1050.44 0.84 1050.72 2321.76 ;
      RECT 1052.68 0.84 1052.96 2321.76 ;
      RECT 1054.92 0.84 1055.2 2321.76 ;
      RECT 1057.16 0.84 1057.44 2321.76 ;
      RECT 1059.4 0.84 1059.68 2321.76 ;
      RECT 1061.64 0.84 1061.92 2321.76 ;
      RECT 1063.88 0.84 1064.16 2321.76 ;
      RECT 1066.12 0.84 1066.4 2321.76 ;
      RECT 1068.36 0.84 1068.64 2321.76 ;
      RECT 1070.6 0.84 1070.88 2321.76 ;
      RECT 1072.84 0.84 1073.12 2321.76 ;
      RECT 1075.08 0.84 1075.36 2321.76 ;
      RECT 1077.32 0.84 1077.6 2321.76 ;
      RECT 1079.56 0.84 1079.84 2321.76 ;
      RECT 1081.8 0.84 1082.08 2321.76 ;
      RECT 1084.04 0.84 1084.32 2321.76 ;
      RECT 1086.28 0.84 1086.56 2321.76 ;
      RECT 1088.52 0.84 1088.8 2321.76 ;
      RECT 1090.76 0.84 1091.04 2321.76 ;
      RECT 1093 0.84 1093.28 2321.76 ;
      RECT 1095.24 0.84 1095.52 2321.76 ;
      RECT 1097.48 0.84 1097.76 2321.76 ;
      RECT 1099.72 0.84 1100 2321.76 ;
      RECT 1101.96 0.84 1102.24 2321.76 ;
      RECT 1104.2 0.84 1104.48 2321.76 ;
      RECT 1106.44 0.84 1106.72 2321.76 ;
      RECT 1108.68 0.84 1108.96 2321.76 ;
      RECT 1110.92 0.84 1111.2 2321.76 ;
      RECT 1113.16 0.84 1113.44 2321.76 ;
      RECT 1115.4 0.84 1115.68 2321.76 ;
      RECT 1117.64 0.84 1117.92 2321.76 ;
      RECT 1119.88 0.84 1120.16 2321.76 ;
      RECT 1122.12 0.84 1122.4 2321.76 ;
      RECT 1124.36 0.84 1124.64 2321.76 ;
      RECT 1126.6 0.84 1126.88 2321.76 ;
      RECT 1128.84 0.84 1129.12 2321.76 ;
      RECT 1131.08 0.84 1131.36 2321.76 ;
      RECT 1133.32 0.84 1133.6 2321.76 ;
      RECT 1135.56 0.84 1135.84 2321.76 ;
      RECT 1137.8 0.84 1138.08 2321.76 ;
      RECT 1140.04 0.84 1140.32 2321.76 ;
      RECT 1142.28 0.84 1142.56 2321.76 ;
      RECT 1144.52 0.84 1144.8 2321.76 ;
      RECT 1146.76 0.84 1147.04 2321.76 ;
      RECT 1149 0.84 1149.28 2321.76 ;
      RECT 1151.24 0.84 1151.52 2321.76 ;
      RECT 1153.48 0.84 1153.76 2321.76 ;
      RECT 1155.72 0.84 1156 2321.76 ;
      RECT 1157.96 0.84 1158.24 2321.76 ;
      RECT 1160.2 0.84 1160.48 2321.76 ;
      RECT 1162.44 0.84 1162.72 2321.76 ;
      RECT 1164.68 0.84 1164.96 2321.76 ;
      RECT 1166.92 0.84 1167.2 2321.76 ;
      RECT 1169.16 0.84 1169.44 2321.76 ;
      RECT 1171.4 0.84 1171.68 2321.76 ;
      RECT 1173.64 0.84 1173.92 2321.76 ;
      RECT 1175.88 0.84 1176.16 2321.76 ;
      RECT 1178.12 0.84 1178.4 2321.76 ;
      RECT 1180.36 0.84 1180.64 2321.76 ;
      RECT 1182.6 0.84 1182.88 2321.76 ;
      RECT 1184.84 0.84 1185.12 2321.76 ;
      RECT 1187.08 0.84 1187.36 2321.76 ;
      RECT 1189.32 0.84 1189.6 2321.76 ;
      RECT 1191.56 0.84 1191.84 2321.76 ;
      RECT 1193.8 0.84 1194.08 2321.76 ;
      RECT 1196.04 0.84 1196.32 2321.76 ;
      RECT 1198.28 0.84 1198.56 2321.76 ;
      RECT 1200.52 0.84 1200.8 2321.76 ;
      RECT 1202.76 0.84 1203.04 2321.76 ;
      RECT 1205 0.84 1205.28 2321.76 ;
      RECT 1207.24 0.84 1207.52 2321.76 ;
      RECT 1209.48 0.84 1209.76 2321.76 ;
      RECT 1211.72 0.84 1212 2321.76 ;
      RECT 1213.96 0.84 1214.24 2321.76 ;
      RECT 1216.2 0.84 1216.48 2321.76 ;
      RECT 1218.44 0.84 1218.72 2321.76 ;
      RECT 1220.68 0.84 1220.96 2321.76 ;
      RECT 1222.92 0.84 1223.2 2321.76 ;
      RECT 1225.16 0.84 1225.44 2321.76 ;
      RECT 1227.4 0.84 1227.68 2321.76 ;
      RECT 1229.64 0.84 1229.92 2321.76 ;
      RECT 1231.88 0.84 1232.16 2321.76 ;
      RECT 1234.12 0.84 1234.4 2321.76 ;
      RECT 1236.36 0.84 1236.64 2321.76 ;
      RECT 1238.6 0.84 1238.88 2321.76 ;
      RECT 1240.84 0.84 1241.12 2321.76 ;
      RECT 1243.08 0.84 1243.36 2321.76 ;
      RECT 1245.32 0.84 1245.6 2321.76 ;
      RECT 1247.56 0.84 1247.84 2321.76 ;
      RECT 1249.8 0.84 1250.08 2321.76 ;
      RECT 1252.04 0.84 1252.32 2321.76 ;
      RECT 1254.28 0.84 1254.56 2321.76 ;
      RECT 1256.52 0.84 1256.8 2321.76 ;
      RECT 1258.76 0.84 1259.04 2321.76 ;
      RECT 1261 0.84 1261.28 2321.76 ;
      RECT 1263.24 0.84 1263.52 2321.76 ;
      RECT 1265.48 0.84 1265.76 2321.76 ;
      RECT 1267.72 0.84 1268 2321.76 ;
      RECT 1269.96 0.84 1270.24 2321.76 ;
      RECT 1272.2 0.84 1272.48 2321.76 ;
      RECT 1274.44 0.84 1274.72 2321.76 ;
      RECT 1276.68 0.84 1276.96 2321.76 ;
      RECT 1278.92 0.84 1279.2 2321.76 ;
      RECT 1281.16 0.84 1281.44 2321.76 ;
      RECT 1283.4 0.84 1283.68 2321.76 ;
      RECT 1285.64 0.84 1285.92 2321.76 ;
      RECT 1287.88 0.84 1288.16 2321.76 ;
      RECT 1290.12 0.84 1290.4 2321.76 ;
      RECT 1292.36 0.84 1292.64 2321.76 ;
      RECT 1294.6 0.84 1294.88 2321.76 ;
      RECT 1296.84 0.84 1297.12 2321.76 ;
      RECT 1299.08 0.84 1299.36 2321.76 ;
      RECT 1301.32 0.84 1301.6 2321.76 ;
      RECT 1303.56 0.84 1303.84 2321.76 ;
      RECT 1305.8 0.84 1306.08 2321.76 ;
      RECT 1308.04 0.84 1308.32 2321.76 ;
      RECT 1310.28 0.84 1310.56 2321.76 ;
      RECT 1312.52 0.84 1312.8 2321.76 ;
      RECT 1314.76 0.84 1315.04 2321.76 ;
      RECT 1317 0.84 1317.28 2321.76 ;
      RECT 1319.24 0.84 1319.52 2321.76 ;
      RECT 1321.48 0.84 1321.76 2321.76 ;
      RECT 1323.72 0.84 1324 2321.76 ;
      RECT 1325.96 0.84 1326.24 2321.76 ;
      RECT 1328.2 0.84 1328.48 2321.76 ;
      RECT 1330.44 0.84 1330.72 2321.76 ;
      RECT 1332.68 0.84 1332.96 2321.76 ;
      RECT 1334.92 0.84 1335.2 2321.76 ;
      RECT 1337.16 0.84 1337.44 2321.76 ;
      RECT 1339.4 0.84 1339.68 2321.76 ;
      RECT 1341.64 0.84 1341.92 2321.76 ;
      RECT 1343.88 0.84 1344.16 2321.76 ;
      RECT 1346.12 0.84 1346.4 2321.76 ;
      RECT 1348.36 0.84 1348.64 2321.76 ;
      RECT 1350.6 0.84 1350.88 2321.76 ;
      RECT 1352.84 0.84 1353.12 2321.76 ;
      RECT 1355.08 0.84 1355.36 2321.76 ;
      RECT 1357.32 0.84 1357.6 2321.76 ;
      RECT 1359.56 0.84 1359.84 2321.76 ;
      RECT 1361.8 0.84 1362.08 2321.76 ;
      RECT 1364.04 0.84 1364.32 2321.76 ;
      RECT 1366.28 0.84 1366.56 2321.76 ;
      RECT 1368.52 0.84 1368.8 2321.76 ;
      RECT 1370.76 0.84 1371.04 2321.76 ;
      RECT 1373 0.84 1373.28 2321.76 ;
      RECT 1375.24 0.84 1375.52 2321.76 ;
      RECT 1377.48 0.84 1377.76 2321.76 ;
      RECT 1379.72 0.84 1380 2321.76 ;
      RECT 1381.96 0.84 1382.24 2321.76 ;
      RECT 1384.2 0.84 1384.48 2321.76 ;
      RECT 1386.44 0.84 1386.72 2321.76 ;
      RECT 1388.68 0.84 1388.96 2321.76 ;
      RECT 1390.92 0.84 1391.2 2321.76 ;
      RECT 1393.16 0.84 1393.44 2321.76 ;
      RECT 1395.4 0.84 1395.68 2321.76 ;
      RECT 1397.64 0.84 1397.92 2321.76 ;
      RECT 1399.88 0.84 1400.16 2321.76 ;
      RECT 1402.12 0.84 1402.4 2321.76 ;
      RECT 1404.36 0.84 1404.64 2321.76 ;
      RECT 1406.6 0.84 1406.88 2321.76 ;
      RECT 1408.84 0.84 1409.12 2321.76 ;
      RECT 1411.08 0.84 1411.36 2321.76 ;
      RECT 1413.32 0.84 1413.6 2321.76 ;
      RECT 1415.56 0.84 1415.84 2321.76 ;
      RECT 1417.8 0.84 1418.08 2321.76 ;
      RECT 1420.04 0.84 1420.32 2321.76 ;
      RECT 1422.28 0.84 1422.56 2321.76 ;
      RECT 1424.52 0.84 1424.8 2321.76 ;
      RECT 1426.76 0.84 1427.04 2321.76 ;
      RECT 1429 0.84 1429.28 2321.76 ;
      RECT 1431.24 0.84 1431.52 2321.76 ;
      RECT 1433.48 0.84 1433.76 2321.76 ;
      RECT 1435.72 0.84 1436 2321.76 ;
      RECT 1437.96 0.84 1438.24 2321.76 ;
      RECT 1440.2 0.84 1440.48 2321.76 ;
      RECT 1442.44 0.84 1442.72 2321.76 ;
      RECT 1444.68 0.84 1444.96 2321.76 ;
      RECT 1446.92 0.84 1447.2 2321.76 ;
      RECT 1449.16 0.84 1449.44 2321.76 ;
      RECT 1451.4 0.84 1451.68 2321.76 ;
      RECT 1453.64 0.84 1453.92 2321.76 ;
      RECT 1455.88 0.84 1456.16 2321.76 ;
      RECT 1458.12 0.84 1458.4 2321.76 ;
      RECT 1460.36 0.84 1460.64 2321.76 ;
      RECT 1462.6 0.84 1462.88 2321.76 ;
      RECT 1464.84 0.84 1465.12 2321.76 ;
      RECT 1467.08 0.84 1467.36 2321.76 ;
      RECT 1469.32 0.84 1469.6 2321.76 ;
      RECT 1471.56 0.84 1471.84 2321.76 ;
      RECT 1473.8 0.84 1474.08 2321.76 ;
      RECT 1476.04 0.84 1476.32 2321.76 ;
      RECT 1478.28 0.84 1478.56 2321.76 ;
      RECT 1480.52 0.84 1480.8 2321.76 ;
      RECT 1482.76 0.84 1483.04 2321.76 ;
      RECT 1485 0.84 1485.28 2321.76 ;
      RECT 1487.24 0.84 1487.52 2321.76 ;
      RECT 1489.48 0.84 1489.76 2321.76 ;
      RECT 1491.72 0.84 1492 2321.76 ;
      RECT 1493.96 0.84 1494.24 2321.76 ;
      RECT 1496.2 0.84 1496.48 2321.76 ;
      RECT 1498.44 0.84 1498.72 2321.76 ;
      RECT 1500.68 0.84 1500.96 2321.76 ;
      RECT 1502.92 0.84 1503.2 2321.76 ;
      RECT 1505.16 0.84 1505.44 2321.76 ;
      RECT 1507.4 0.84 1507.68 2321.76 ;
      RECT 1509.64 0.84 1509.92 2321.76 ;
      RECT 1511.88 0.84 1512.16 2321.76 ;
      RECT 1514.12 0.84 1514.4 2321.76 ;
      RECT 1516.36 0.84 1516.64 2321.76 ;
      RECT 1518.6 0.84 1518.88 2321.76 ;
      RECT 1520.84 0.84 1521.12 2321.76 ;
      RECT 1523.08 0.84 1523.36 2321.76 ;
      RECT 1525.32 0.84 1525.6 2321.76 ;
      RECT 1527.56 0.84 1527.84 2321.76 ;
      RECT 1529.8 0.84 1530.08 2321.76 ;
      RECT 1532.04 0.84 1532.32 2321.76 ;
      RECT 1534.28 0.84 1534.56 2321.76 ;
      RECT 1536.52 0.84 1536.8 2321.76 ;
      RECT 1538.76 0.84 1539.04 2321.76 ;
      RECT 1541 0.84 1541.28 2321.76 ;
      RECT 1543.24 0.84 1543.52 2321.76 ;
      RECT 1545.48 0.84 1545.76 2321.76 ;
      RECT 1547.72 0.84 1548 2321.76 ;
      RECT 1549.96 0.84 1550.24 2321.76 ;
      RECT 1552.2 0.84 1552.48 2321.76 ;
      RECT 1554.44 0.84 1554.72 2321.76 ;
      RECT 1556.68 0.84 1556.96 2321.76 ;
      RECT 1558.92 0.84 1559.2 2321.76 ;
      RECT 1561.16 0.84 1561.44 2321.76 ;
      RECT 1563.4 0.84 1563.68 2321.76 ;
      RECT 1565.64 0.84 1565.92 2321.76 ;
      RECT 1567.88 0.84 1568.16 2321.76 ;
      RECT 1570.12 0.84 1570.4 2321.76 ;
      RECT 1572.36 0.84 1572.64 2321.76 ;
      RECT 1574.6 0.84 1574.88 2321.76 ;
      RECT 1576.84 0.84 1577.12 2321.76 ;
      RECT 1579.08 0.84 1579.36 2321.76 ;
      RECT 1581.32 0.84 1581.6 2321.76 ;
      RECT 1583.56 0.84 1583.84 2321.76 ;
      RECT 1585.8 0.84 1586.08 2321.76 ;
      RECT 1588.04 0.84 1588.32 2321.76 ;
      RECT 1590.28 0.84 1590.56 2321.76 ;
      RECT 1592.52 0.84 1592.8 2321.76 ;
      RECT 1594.76 0.84 1595.04 2321.76 ;
      RECT 1597 0.84 1597.28 2321.76 ;
      RECT 1599.24 0.84 1599.52 2321.76 ;
      RECT 1601.48 0.84 1601.76 2321.76 ;
      RECT 1603.72 0.84 1604 2321.76 ;
      RECT 1605.96 0.84 1606.24 2321.76 ;
      RECT 1608.2 0.84 1608.48 2321.76 ;
      RECT 1610.44 0.84 1610.72 2321.76 ;
      RECT 1612.68 0.84 1612.96 2321.76 ;
      RECT 1614.92 0.84 1615.2 2321.76 ;
      RECT 1617.16 0.84 1617.44 2321.76 ;
      RECT 1619.4 0.84 1619.68 2321.76 ;
      RECT 1621.64 0.84 1621.92 2321.76 ;
      RECT 1623.88 0.84 1624.16 2321.76 ;
      RECT 1626.12 0.84 1626.4 2321.76 ;
      RECT 1628.36 0.84 1628.64 2321.76 ;
      RECT 1630.6 0.84 1630.88 2321.76 ;
      RECT 1632.84 0.84 1633.12 2321.76 ;
      RECT 1635.08 0.84 1635.36 2321.76 ;
      RECT 1637.32 0.84 1637.6 2321.76 ;
      RECT 1639.56 0.84 1639.84 2321.76 ;
      RECT 1641.8 0.84 1642.08 2321.76 ;
      RECT 1644.04 0.84 1644.32 2321.76 ;
      RECT 1646.28 0.84 1646.56 2321.76 ;
      RECT 1648.52 0.84 1648.8 2321.76 ;
      RECT 1650.76 0.84 1651.04 2321.76 ;
      RECT 1653 0.84 1653.28 2321.76 ;
      RECT 1655.24 0.84 1655.52 2321.76 ;
      RECT 1657.48 0.84 1657.76 2321.76 ;
      RECT 1659.72 0.84 1660 2321.76 ;
      RECT 1661.96 0.84 1662.24 2321.76 ;
      RECT 1664.2 0.84 1664.48 2321.76 ;
      RECT 1666.44 0.84 1666.72 2321.76 ;
      RECT 1668.68 0.84 1668.96 2321.76 ;
      RECT 1670.92 0.84 1671.2 2321.76 ;
      RECT 1673.16 0.84 1673.44 2321.76 ;
      RECT 1675.4 0.84 1675.68 2321.76 ;
      RECT 1677.64 0.84 1677.92 2321.76 ;
      RECT 1679.88 0.84 1680.16 2321.76 ;
      RECT 1682.12 0.84 1682.4 2321.76 ;
      RECT 1684.36 0.84 1684.64 2321.76 ;
      RECT 1686.6 0.84 1686.88 2321.76 ;
      RECT 1688.84 0.84 1689.12 2321.76 ;
      RECT 1691.08 0.84 1691.36 2321.76 ;
      RECT 1693.32 0.84 1693.6 2321.76 ;
      RECT 1695.56 0.84 1695.84 2321.76 ;
      RECT 1697.8 0.84 1698.08 2321.76 ;
      RECT 1700.04 0.84 1700.32 2321.76 ;
      RECT 1702.28 0.84 1702.56 2321.76 ;
      RECT 1704.52 0.84 1704.8 2321.76 ;
      RECT 1706.76 0.84 1707.04 2321.76 ;
      RECT 1709 0.84 1709.28 2321.76 ;
      RECT 1711.24 0.84 1711.52 2321.76 ;
      RECT 1713.48 0.84 1713.76 2321.76 ;
      RECT 1715.72 0.84 1716 2321.76 ;
      RECT 1717.96 0.84 1718.24 2321.76 ;
      RECT 1720.2 0.84 1720.48 2321.76 ;
      RECT 1722.44 0.84 1722.72 2321.76 ;
      RECT 1724.68 0.84 1724.96 2321.76 ;
      RECT 1726.92 0.84 1727.2 2321.76 ;
      RECT 1729.16 0.84 1729.44 2321.76 ;
      RECT 1731.4 0.84 1731.68 2321.76 ;
      RECT 1733.64 0.84 1733.92 2321.76 ;
      RECT 1735.88 0.84 1736.16 2321.76 ;
      RECT 1738.12 0.84 1738.4 2321.76 ;
      RECT 1740.36 0.84 1740.64 2321.76 ;
      RECT 1742.6 0.84 1742.88 2321.76 ;
      RECT 1744.84 0.84 1745.12 2321.76 ;
      RECT 1747.08 0.84 1747.36 2321.76 ;
      RECT 1749.32 0.84 1749.6 2321.76 ;
      RECT 1751.56 0.84 1751.84 2321.76 ;
      RECT 1753.8 0.84 1754.08 2321.76 ;
      RECT 1756.04 0.84 1756.32 2321.76 ;
      RECT 1758.28 0.84 1758.56 2321.76 ;
      RECT 1760.52 0.84 1760.8 2321.76 ;
      RECT 1762.76 0.84 1763.04 2321.76 ;
      RECT 1765 0.84 1765.28 2321.76 ;
      RECT 1767.24 0.84 1767.52 2321.76 ;
      RECT 1769.48 0.84 1769.76 2321.76 ;
      RECT 1771.72 0.84 1772 2321.76 ;
      RECT 1773.96 0.84 1774.24 2321.76 ;
      RECT 1776.2 0.84 1776.48 2321.76 ;
      RECT 1778.44 0.84 1778.72 2321.76 ;
      RECT 1780.68 0.84 1780.96 2321.76 ;
      RECT 1782.92 0.84 1783.2 2321.76 ;
      RECT 1785.16 0.84 1785.44 2321.76 ;
      RECT 1787.4 0.84 1787.68 2321.76 ;
      RECT 1789.64 0.84 1789.92 2321.76 ;
      RECT 1791.88 0.84 1792.16 2321.76 ;
      RECT 1794.12 0.84 1794.4 2321.76 ;
      RECT 1796.36 0.84 1796.64 2321.76 ;
      RECT 1798.6 0.84 1798.88 2321.76 ;
      RECT 1800.84 0.84 1801.12 2321.76 ;
      RECT 1803.08 0.84 1803.36 2321.76 ;
      RECT 1805.32 0.84 1805.6 2321.76 ;
      RECT 1807.56 0.84 1807.84 2321.76 ;
      RECT 1809.8 0.84 1810.08 2321.76 ;
      RECT 1812.04 0.84 1812.32 2321.76 ;
      RECT 1814.28 0.84 1814.56 2321.76 ;
      RECT 1816.52 0.84 1816.8 2321.76 ;
      RECT 1818.76 0.84 1819.04 2321.76 ;
      RECT 1821 0.84 1821.28 2321.76 ;
      RECT 1823.24 0.84 1823.52 2321.76 ;
      RECT 1825.48 0.84 1825.76 2321.76 ;
      RECT 1827.72 0.84 1828 2321.76 ;
      RECT 1829.96 0.84 1830.24 2321.76 ;
      RECT 1832.2 0.84 1832.48 2321.76 ;
      RECT 1834.44 0.84 1834.72 2321.76 ;
      RECT 1836.68 0.84 1836.96 2321.76 ;
      RECT 1838.92 0.84 1839.2 2321.76 ;
      RECT 1841.16 0.84 1841.44 2321.76 ;
      RECT 1843.4 0.84 1843.68 2321.76 ;
      RECT 1845.64 0.84 1845.92 2321.76 ;
      RECT 1847.88 0.84 1848.16 2321.76 ;
      RECT 1850.12 0.84 1850.4 2321.76 ;
      RECT 1852.36 0.84 1852.64 2321.76 ;
      RECT 1854.6 0.84 1854.88 2321.76 ;
      RECT 1856.84 0.84 1857.12 2321.76 ;
      RECT 1859.08 0.84 1859.36 2321.76 ;
      RECT 1861.32 0.84 1861.6 2321.76 ;
      RECT 1863.56 0.84 1863.84 2321.76 ;
      RECT 1865.8 0.84 1866.08 2321.76 ;
      RECT 1868.04 0.84 1868.32 2321.76 ;
      RECT 1870.28 0.84 1870.56 2321.76 ;
      RECT 1872.52 0.84 1872.8 2321.76 ;
      RECT 1874.76 0.84 1875.04 2321.76 ;
      RECT 1877 0.84 1877.28 2321.76 ;
      RECT 1879.24 0.84 1879.52 2321.76 ;
      RECT 1881.48 0.84 1881.76 2321.76 ;
      RECT 1883.72 0.84 1884 2321.76 ;
      RECT 1885.96 0.84 1886.24 2321.76 ;
      RECT 1888.2 0.84 1888.48 2321.76 ;
      RECT 1890.44 0.84 1890.72 2321.76 ;
      RECT 1892.68 0.84 1892.96 2321.76 ;
      RECT 1894.92 0.84 1895.2 2321.76 ;
      RECT 1897.16 0.84 1897.44 2321.76 ;
      RECT 1899.4 0.84 1899.68 2321.76 ;
      RECT 1901.64 0.84 1901.92 2321.76 ;
      RECT 1903.88 0.84 1904.16 2321.76 ;
      RECT 1906.12 0.84 1906.4 2321.76 ;
      RECT 1908.36 0.84 1908.64 2321.76 ;
      RECT 1910.6 0.84 1910.88 2321.76 ;
      RECT 1912.84 0.84 1913.12 2321.76 ;
      RECT 1915.08 0.84 1915.36 2321.76 ;
      RECT 1917.32 0.84 1917.6 2321.76 ;
      RECT 1919.56 0.84 1919.84 2321.76 ;
      RECT 1921.8 0.84 1922.08 2321.76 ;
      RECT 1924.04 0.84 1924.32 2321.76 ;
      RECT 1926.28 0.84 1926.56 2321.76 ;
      RECT 1928.52 0.84 1928.8 2321.76 ;
      RECT 1930.76 0.84 1931.04 2321.76 ;
      RECT 1933 0.84 1933.28 2321.76 ;
      RECT 1935.24 0.84 1935.52 2321.76 ;
      RECT 1937.48 0.84 1937.76 2321.76 ;
      RECT 1939.72 0.84 1940 2321.76 ;
      RECT 1941.96 0.84 1942.24 2321.76 ;
      RECT 1944.2 0.84 1944.48 2321.76 ;
      RECT 1946.44 0.84 1946.72 2321.76 ;
      RECT 1948.68 0.84 1948.96 2321.76 ;
      RECT 1950.92 0.84 1951.2 2321.76 ;
      RECT 1953.16 0.84 1953.44 2321.76 ;
      RECT 1955.4 0.84 1955.68 2321.76 ;
      RECT 1957.64 0.84 1957.92 2321.76 ;
      RECT 1959.88 0.84 1960.16 2321.76 ;
      RECT 1962.12 0.84 1962.4 2321.76 ;
      RECT 1964.36 0.84 1964.64 2321.76 ;
      RECT 1966.6 0.84 1966.88 2321.76 ;
      RECT 1968.84 0.84 1969.12 2321.76 ;
      RECT 1971.08 0.84 1971.36 2321.76 ;
      RECT 1973.32 0.84 1973.6 2321.76 ;
      RECT 1975.56 0.84 1975.84 2321.76 ;
      RECT 1977.8 0.84 1978.08 2321.76 ;
      RECT 1980.04 0.84 1980.32 2321.76 ;
      RECT 1982.28 0.84 1982.56 2321.76 ;
      RECT 1984.52 0.84 1984.8 2321.76 ;
      RECT 1986.76 0.84 1987.04 2321.76 ;
      RECT 1989 0.84 1989.28 2321.76 ;
      RECT 1991.24 0.84 1991.52 2321.76 ;
      RECT 1993.48 0.84 1993.76 2321.76 ;
      RECT 1995.72 0.84 1996 2321.76 ;
      RECT 1997.96 0.84 1998.24 2321.76 ;
      RECT 2000.2 0.84 2000.48 2321.76 ;
      RECT 2002.44 0.84 2002.72 2321.76 ;
      RECT 2004.68 0.84 2004.96 2321.76 ;
      RECT 2006.92 0.84 2007.2 2321.76 ;
      RECT 2009.16 0.84 2009.44 2321.76 ;
      RECT 2011.4 0.84 2011.68 2321.76 ;
      RECT 2013.64 0.84 2013.92 2321.76 ;
      RECT 2015.88 0.84 2016.16 2321.76 ;
      RECT 2018.12 0.84 2018.4 2321.76 ;
      RECT 2020.36 0.84 2020.64 2321.76 ;
      RECT 2022.6 0.84 2022.88 2321.76 ;
      RECT 2024.84 0.84 2025.12 2321.76 ;
      RECT 2027.08 0.84 2027.36 2321.76 ;
      RECT 2029.32 0.84 2029.6 2321.76 ;
      RECT 2031.56 0.84 2031.84 2321.76 ;
      RECT 2033.8 0.84 2034.08 2321.76 ;
      RECT 2036.04 0.84 2036.32 2321.76 ;
      RECT 2038.28 0.84 2038.56 2321.76 ;
      RECT 2040.52 0.84 2040.8 2321.76 ;
      RECT 2042.76 0.84 2043.04 2321.76 ;
      RECT 2045 0.84 2045.28 2321.76 ;
      RECT 2047.24 0.84 2047.52 2321.76 ;
      RECT 2049.48 0.84 2049.76 2321.76 ;
      RECT 2051.72 0.84 2052 2321.76 ;
      RECT 2053.96 0.84 2054.24 2321.76 ;
      RECT 2056.2 0.84 2056.48 2321.76 ;
      RECT 2058.44 0.84 2058.72 2321.76 ;
      RECT 2060.68 0.84 2060.96 2321.76 ;
      RECT 2062.92 0.84 2063.2 2321.76 ;
      RECT 2065.16 0.84 2065.44 2321.76 ;
      RECT 2067.4 0.84 2067.68 2321.76 ;
      RECT 2069.64 0.84 2069.92 2321.76 ;
      RECT 2071.88 0.84 2072.16 2321.76 ;
      RECT 2074.12 0.84 2074.4 2321.76 ;
      RECT 2076.36 0.84 2076.64 2321.76 ;
      RECT 2078.6 0.84 2078.88 2321.76 ;
      RECT 2080.84 0.84 2081.12 2321.76 ;
      RECT 2083.08 0.84 2083.36 2321.76 ;
      RECT 2085.32 0.84 2085.6 2321.76 ;
      RECT 2087.56 0.84 2087.84 2321.76 ;
      RECT 2089.8 0.84 2090.08 2321.76 ;
      RECT 2092.04 0.84 2092.32 2321.76 ;
      RECT 2094.28 0.84 2094.56 2321.76 ;
      RECT 2096.52 0.84 2096.8 2321.76 ;
      RECT 2098.76 0.84 2099.04 2321.76 ;
      RECT 2101 0.84 2101.28 2321.76 ;
      RECT 2103.24 0.84 2103.52 2321.76 ;
      RECT 2105.48 0.84 2105.76 2321.76 ;
      RECT 2107.72 0.84 2108 2321.76 ;
      RECT 2109.96 0.84 2110.24 2321.76 ;
      RECT 2112.2 0.84 2112.48 2321.76 ;
      RECT 2114.44 0.84 2114.72 2321.76 ;
      RECT 2116.68 0.84 2116.96 2321.76 ;
      RECT 2118.92 0.84 2119.2 2321.76 ;
      RECT 2121.16 0.84 2121.44 2321.76 ;
      RECT 2123.4 0.84 2123.68 2321.76 ;
      RECT 2125.64 0.84 2125.92 2321.76 ;
      RECT 2127.88 0.84 2128.16 2321.76 ;
      RECT 2130.12 0.84 2130.4 2321.76 ;
      RECT 2132.36 0.84 2132.64 2321.76 ;
      RECT 2134.6 0.84 2134.88 2321.76 ;
      RECT 2136.84 0.84 2137.12 2321.76 ;
      RECT 2139.08 0.84 2139.36 2321.76 ;
      RECT 2141.32 0.84 2141.6 2321.76 ;
      RECT 2143.56 0.84 2143.84 2321.76 ;
      RECT 2145.8 0.84 2146.08 2321.76 ;
      RECT 2148.04 0.84 2148.32 2321.76 ;
      RECT 2150.28 0.84 2150.56 2321.76 ;
      RECT 2152.52 0.84 2152.8 2321.76 ;
      RECT 2154.76 0.84 2155.04 2321.76 ;
      RECT 2157 0.84 2157.28 2321.76 ;
      RECT 2159.24 0.84 2159.52 2321.76 ;
      RECT 2161.48 0.84 2161.76 2321.76 ;
      RECT 2163.72 0.84 2164 2321.76 ;
      RECT 2165.96 0.84 2166.24 2321.76 ;
      RECT 2168.2 0.84 2168.48 2321.76 ;
      RECT 2170.44 0.84 2170.72 2321.76 ;
      RECT 2172.68 0.84 2172.96 2321.76 ;
      RECT 2174.92 0.84 2175.2 2321.76 ;
      RECT 2177.16 0.84 2177.44 2321.76 ;
      RECT 2179.4 0.84 2179.68 2321.76 ;
      RECT 2181.64 0.84 2181.92 2321.76 ;
      RECT 2183.88 0.84 2184.16 2321.76 ;
      RECT 2186.12 0.84 2186.4 2321.76 ;
      RECT 2188.36 0.84 2188.64 2321.76 ;
      RECT 2190.6 0.84 2190.88 2321.76 ;
      RECT 2192.84 0.84 2193.12 2321.76 ;
      RECT 2195.08 0.84 2195.36 2321.76 ;
      RECT 2197.32 0.84 2197.6 2321.76 ;
      RECT 2199.56 0.84 2199.84 2321.76 ;
      RECT 2201.8 0.84 2202.08 2321.76 ;
      RECT 2204.04 0.84 2204.32 2321.76 ;
      RECT 2206.28 0.84 2206.56 2321.76 ;
      RECT 2208.52 0.84 2208.8 2321.76 ;
      RECT 2210.76 0.84 2211.04 2321.76 ;
      RECT 2213 0.84 2213.28 2321.76 ;
      RECT 2215.24 0.84 2215.52 2321.76 ;
      RECT 2217.48 0.84 2217.76 2321.76 ;
      RECT 2219.72 0.84 2220 2321.76 ;
      RECT 2221.96 0.84 2222.24 2321.76 ;
      RECT 2224.2 0.84 2224.48 2321.76 ;
      RECT 2226.44 0.84 2226.72 2321.76 ;
      RECT 2228.68 0.84 2228.96 2321.76 ;
      RECT 2230.92 0.84 2231.2 2321.76 ;
      RECT 2233.16 0.84 2233.44 2321.76 ;
      RECT 2235.4 0.84 2235.68 2321.76 ;
      RECT 2237.64 0.84 2237.92 2321.76 ;
      RECT 2239.88 0.84 2240.16 2321.76 ;
      RECT 2242.12 0.84 2242.4 2321.76 ;
      RECT 2244.36 0.84 2244.64 2321.76 ;
      RECT 2246.6 0.84 2246.88 2321.76 ;
      RECT 2248.84 0.84 2249.12 2321.76 ;
      RECT 2251.08 0.84 2251.36 2321.76 ;
      RECT 2253.32 0.84 2253.6 2321.76 ;
      RECT 2255.56 0.84 2255.84 2321.76 ;
      RECT 2257.8 0.84 2258.08 2321.76 ;
      RECT 2260.04 0.84 2260.32 2321.76 ;
      RECT 2262.28 0.84 2262.56 2321.76 ;
      RECT 2264.52 0.84 2264.8 2321.76 ;
      RECT 2266.76 0.84 2267.04 2321.76 ;
      RECT 2269 0.84 2269.28 2321.76 ;
      RECT 2271.24 0.84 2271.52 2321.76 ;
      RECT 2273.48 0.84 2273.76 2321.76 ;
      RECT 2275.72 0.84 2276 2321.76 ;
      RECT 2277.96 0.84 2278.24 2321.76 ;
      RECT 2280.2 0.84 2280.48 2321.76 ;
      RECT 2282.44 0.84 2282.72 2321.76 ;
      RECT 2284.68 0.84 2284.96 2321.76 ;
      RECT 2286.92 0.84 2287.2 2321.76 ;
      RECT 2289.16 0.84 2289.44 2321.76 ;
      RECT 2291.4 0.84 2291.68 2321.76 ;
      RECT 2293.64 0.84 2293.92 2321.76 ;
      RECT 2295.88 0.84 2296.16 2321.76 ;
      RECT 2298.12 0.84 2298.4 2321.76 ;
      RECT 2300.36 0.84 2300.64 2321.76 ;
      RECT 2302.6 0.84 2302.88 2321.76 ;
      RECT 2304.84 0.84 2305.12 2321.76 ;
      RECT 2307.08 0.84 2307.36 2321.76 ;
      RECT 2309.32 0.84 2309.6 2321.76 ;
      RECT 2311.56 0.84 2311.84 2321.76 ;
      RECT 2313.8 0.84 2314.08 2321.76 ;
      RECT 2316.04 0.84 2316.32 2321.76 ;
      RECT 2318.28 0.84 2318.56 2321.76 ;
      RECT 2320.52 0.84 2320.8 2321.76 ;
      RECT 2322.76 0.84 2323.04 2321.76 ;
      RECT 2325 0.84 2325.28 2321.76 ;
      RECT 2327.24 0.84 2327.52 2321.76 ;
      RECT 2329.48 0.84 2329.76 2321.76 ;
      RECT 2331.72 0.84 2332 2321.76 ;
      RECT 2333.96 0.84 2334.24 2321.76 ;
      RECT 2336.2 0.84 2336.48 2321.76 ;
      RECT 2338.44 0.84 2338.72 2321.76 ;
      RECT 2340.68 0.84 2340.96 2321.76 ;
      RECT 2342.92 0.84 2343.2 2321.76 ;
      RECT 2345.16 0.84 2345.44 2321.76 ;
      RECT 2347.4 0.84 2347.68 2321.76 ;
      RECT 2349.64 0.84 2349.92 2321.76 ;
      RECT 2351.88 0.84 2352.16 2321.76 ;
      RECT 2354.12 0.84 2354.4 2321.76 ;
      RECT 2356.36 0.84 2356.64 2321.76 ;
      RECT 2358.6 0.84 2358.88 2321.76 ;
      RECT 2360.84 0.84 2361.12 2321.76 ;
      RECT 2363.08 0.84 2363.36 2321.76 ;
      RECT 2365.32 0.84 2365.6 2321.76 ;
      RECT 2367.56 0.84 2367.84 2321.76 ;
      RECT 2369.8 0.84 2370.08 2321.76 ;
      RECT 2372.04 0.84 2372.32 2321.76 ;
      RECT 2374.28 0.84 2374.56 2321.76 ;
      RECT 2376.52 0.84 2376.8 2321.76 ;
      RECT 2378.76 0.84 2379.04 2321.76 ;
      RECT 2381 0.84 2381.28 2321.76 ;
      RECT 2383.24 0.84 2383.52 2321.76 ;
      RECT 2385.48 0.84 2385.76 2321.76 ;
      RECT 2387.72 0.84 2388 2321.76 ;
      RECT 2389.96 0.84 2390.24 2321.76 ;
      RECT 2392.2 0.84 2392.48 2321.76 ;
      RECT 2394.44 0.84 2394.72 2321.76 ;
      RECT 2396.68 0.84 2396.96 2321.76 ;
      RECT 2398.92 0.84 2399.2 2321.76 ;
      RECT 2401.16 0.84 2401.44 2321.76 ;
      RECT 2403.4 0.84 2403.68 2321.76 ;
      RECT 2405.64 0.84 2405.92 2321.76 ;
      RECT 2407.88 0.84 2408.16 2321.76 ;
      RECT 2410.12 0.84 2410.4 2321.76 ;
      RECT 2412.36 0.84 2412.64 2321.76 ;
      RECT 2414.6 0.84 2414.88 2321.76 ;
      RECT 2416.84 0.84 2417.12 2321.76 ;
      RECT 2419.08 0.84 2419.36 2321.76 ;
      RECT 2421.32 0.84 2421.6 2321.76 ;
      RECT 2423.56 0.84 2423.84 2321.76 ;
      RECT 2425.8 0.84 2426.08 2321.76 ;
      RECT 2428.04 0.84 2428.32 2321.76 ;
      RECT 2430.28 0.84 2430.56 2321.76 ;
      RECT 2432.52 0.84 2432.8 2321.76 ;
      RECT 2434.76 0.84 2435.04 2321.76 ;
      RECT 2437 0.84 2437.28 2321.76 ;
      RECT 2439.24 0.84 2439.52 2321.76 ;
      RECT 2441.48 0.84 2441.76 2321.76 ;
      RECT 2443.72 0.84 2444 2321.76 ;
      RECT 2445.96 0.84 2446.24 2321.76 ;
      RECT 2448.2 0.84 2448.48 2321.76 ;
      RECT 2450.44 0.84 2450.72 2321.76 ;
      RECT 2452.68 0.84 2452.96 2321.76 ;
      RECT 2454.92 0.84 2455.2 2321.76 ;
      RECT 2457.16 0.84 2457.44 2321.76 ;
      RECT 2459.4 0.84 2459.68 2321.76 ;
      RECT 2461.64 0.84 2461.92 2321.76 ;
      RECT 2463.88 0.84 2464.16 2321.76 ;
      RECT 2466.12 0.84 2466.4 2321.76 ;
      RECT 2468.36 0.84 2468.64 2321.76 ;
      RECT 2470.6 0.84 2470.88 2321.76 ;
      RECT 2472.84 0.84 2473.12 2321.76 ;
      RECT 2475.08 0.84 2475.36 2321.76 ;
      RECT 2477.32 0.84 2477.6 2321.76 ;
      RECT 2479.56 0.84 2479.84 2321.76 ;
      RECT 2481.8 0.84 2482.08 2321.76 ;
      RECT 2484.04 0.84 2484.32 2321.76 ;
      RECT 2486.28 0.84 2486.56 2321.76 ;
      RECT 2488.52 0.84 2488.8 2321.76 ;
      RECT 2490.76 0.84 2491.04 2321.76 ;
      RECT 2493 0.84 2493.28 2321.76 ;
      RECT 2495.24 0.84 2495.52 2321.76 ;
      RECT 2497.48 0.84 2497.76 2321.76 ;
      RECT 2499.72 0.84 2500 2321.76 ;
      RECT 2501.96 0.84 2502.24 2321.76 ;
      RECT 2504.2 0.84 2504.48 2321.76 ;
      RECT 2506.44 0.84 2506.72 2321.76 ;
      RECT 2508.68 0.84 2508.96 2321.76 ;
      RECT 2510.92 0.84 2511.2 2321.76 ;
      RECT 2513.16 0.84 2513.44 2321.76 ;
      RECT 2515.4 0.84 2515.68 2321.76 ;
      RECT 2517.64 0.84 2517.92 2321.76 ;
      RECT 2519.88 0.84 2520.16 2321.76 ;
      RECT 2522.12 0.84 2522.4 2321.76 ;
      RECT 2524.36 0.84 2524.64 2321.76 ;
      RECT 2526.6 0.84 2526.88 2321.76 ;
      RECT 2528.84 0.84 2529.12 2321.76 ;
      RECT 2531.08 0.84 2531.36 2321.76 ;
      RECT 2533.32 0.84 2533.6 2321.76 ;
      RECT 2535.56 0.84 2535.84 2321.76 ;
      RECT 2537.8 0.84 2538.08 2321.76 ;
      RECT 2540.04 0.84 2540.32 2321.76 ;
      RECT 2542.28 0.84 2542.56 2321.76 ;
      RECT 2544.52 0.84 2544.8 2321.76 ;
      RECT 2546.76 0.84 2547.04 2321.76 ;
      RECT 2549 0.84 2549.28 2321.76 ;
      RECT 2551.24 0.84 2551.52 2321.76 ;
      RECT 2553.48 0.84 2553.76 2321.76 ;
      RECT 2555.72 0.84 2556 2321.76 ;
      RECT 2557.96 0.84 2558.24 2321.76 ;
      RECT 2560.2 0.84 2560.48 2321.76 ;
      RECT 2562.44 0.84 2562.72 2321.76 ;
      RECT 2564.68 0.84 2564.96 2321.76 ;
      RECT 2566.92 0.84 2567.2 2321.76 ;
      RECT 2569.16 0.84 2569.44 2321.76 ;
      RECT 2571.4 0.84 2571.68 2321.76 ;
      RECT 2573.64 0.84 2573.92 2321.76 ;
      RECT 2575.88 0.84 2576.16 2321.76 ;
      RECT 2578.12 0.84 2578.4 2321.76 ;
      RECT 2580.36 0.84 2580.64 2321.76 ;
      RECT 2582.6 0.84 2582.88 2321.76 ;
      RECT 2584.84 0.84 2585.12 2321.76 ;
      RECT 2587.08 0.84 2587.36 2321.76 ;
      RECT 2589.32 0.84 2589.6 2321.76 ;
      RECT 2591.56 0.84 2591.84 2321.76 ;
      RECT 2593.8 0.84 2594.08 2321.76 ;
      RECT 2596.04 0.84 2596.32 2321.76 ;
      RECT 2598.28 0.84 2598.56 2321.76 ;
      RECT 2600.52 0.84 2600.8 2321.76 ;
      RECT 2602.76 0.84 2603.04 2321.76 ;
      RECT 2605 0.84 2605.28 2321.76 ;
      RECT 2607.24 0.84 2607.52 2321.76 ;
      RECT 2609.48 0.84 2609.76 2321.76 ;
      RECT 2611.72 0.84 2612 2321.76 ;
      RECT 2613.96 0.84 2614.24 2321.76 ;
      RECT 2616.2 0.84 2616.48 2321.76 ;
      RECT 2618.44 0.84 2618.72 2321.76 ;
      RECT 2620.68 0.84 2620.96 2321.76 ;
      RECT 2622.92 0.84 2623.2 2321.76 ;
      RECT 2625.16 0.84 2625.44 2321.76 ;
      RECT 2627.4 0.84 2627.68 2321.76 ;
      RECT 2629.64 0.84 2629.92 2321.76 ;
      RECT 2631.88 0.84 2632.16 2321.76 ;
      RECT 2634.12 0.84 2634.4 2321.76 ;
      RECT 2636.36 0.84 2636.64 2321.76 ;
      RECT 2638.6 0.84 2638.88 2321.76 ;
      RECT 2640.84 0.84 2641.12 2321.76 ;
      RECT 2643.08 0.84 2643.36 2321.76 ;
      RECT 2645.32 0.84 2645.6 2321.76 ;
      RECT 2647.56 0.84 2647.84 2321.76 ;
      RECT 2649.8 0.84 2650.08 2321.76 ;
      RECT 2652.04 0.84 2652.32 2321.76 ;
      RECT 2654.28 0.84 2654.56 2321.76 ;
      RECT 2656.52 0.84 2656.8 2321.76 ;
      RECT 2658.76 0.84 2659.04 2321.76 ;
      RECT 2661 0.84 2661.28 2321.76 ;
      RECT 2663.24 0.84 2663.52 2321.76 ;
      RECT 2665.48 0.84 2665.76 2321.76 ;
      RECT 2667.72 0.84 2668 2321.76 ;
      RECT 2669.96 0.84 2670.24 2321.76 ;
      RECT 2672.2 0.84 2672.48 2321.76 ;
      RECT 2674.44 0.84 2674.72 2321.76 ;
      RECT 2676.68 0.84 2676.96 2321.76 ;
      RECT 2678.92 0.84 2679.2 2321.76 ;
      RECT 2681.16 0.84 2681.44 2321.76 ;
      RECT 2683.4 0.84 2683.68 2321.76 ;
      RECT 2685.64 0.84 2685.92 2321.76 ;
      RECT 2687.88 0.84 2688.16 2321.76 ;
      RECT 2690.12 0.84 2690.4 2321.76 ;
      RECT 2692.36 0.84 2692.64 2321.76 ;
      RECT 2694.6 0.84 2694.88 2321.76 ;
      RECT 2696.84 0.84 2697.12 2321.76 ;
      RECT 2699.08 0.84 2699.36 2321.76 ;
      RECT 2701.32 0.84 2701.6 2321.76 ;
      RECT 2703.56 0.84 2703.84 2321.76 ;
      RECT 2705.8 0.84 2706.08 2321.76 ;
      RECT 2708.04 0.84 2708.32 2321.76 ;
      RECT 2710.28 0.84 2710.56 2321.76 ;
      RECT 2712.52 0.84 2712.8 2321.76 ;
      RECT 2714.76 0.84 2715.04 2321.76 ;
      RECT 2717 0.84 2717.28 2321.76 ;
      RECT 2719.24 0.84 2719.52 2321.76 ;
      RECT 2721.48 0.84 2721.76 2321.76 ;
      RECT 2723.72 0.84 2724 2321.76 ;
      RECT 2725.96 0.84 2726.24 2321.76 ;
      RECT 2728.2 0.84 2728.48 2321.76 ;
      RECT 2730.44 0.84 2730.72 2321.76 ;
      RECT 2732.68 0.84 2732.96 2321.76 ;
      RECT 2734.92 0.84 2735.2 2321.76 ;
      RECT 2737.16 0.84 2737.44 2321.76 ;
      RECT 2739.4 0.84 2739.68 2321.76 ;
      RECT 2741.64 0.84 2741.92 2321.76 ;
      RECT 2743.88 0.84 2744.16 2321.76 ;
      RECT 2746.12 0.84 2746.4 2321.76 ;
      RECT 2748.36 0.84 2748.64 2321.76 ;
      RECT 2750.6 0.84 2750.88 2321.76 ;
      RECT 2752.84 0.84 2753.12 2321.76 ;
      RECT 2755.08 0.84 2755.36 2321.76 ;
      RECT 2757.32 0.84 2757.6 2321.76 ;
      RECT 2759.56 0.84 2759.84 2321.76 ;
      RECT 2761.8 0.84 2762.08 2321.76 ;
      RECT 2764.04 0.84 2764.32 2321.76 ;
      RECT 2766.28 0.84 2766.56 2321.76 ;
      RECT 2768.52 0.84 2768.8 2321.76 ;
      RECT 2770.76 0.84 2771.04 2321.76 ;
      RECT 2773 0.84 2773.28 2321.76 ;
      RECT 2775.24 0.84 2775.52 2321.76 ;
      RECT 2777.48 0.84 2777.76 2321.76 ;
      RECT 2779.72 0.84 2780 2321.76 ;
      RECT 2781.96 0.84 2782.24 2321.76 ;
      RECT 2784.2 0.84 2784.48 2321.76 ;
      RECT 2786.44 0.84 2786.72 2321.76 ;
      RECT 2788.68 0.84 2788.96 2321.76 ;
      RECT 2790.92 0.84 2791.2 2321.76 ;
      RECT 2793.16 0.84 2793.44 2321.76 ;
      RECT 2795.4 0.84 2795.68 2321.76 ;
      RECT 2797.64 0.84 2797.92 2321.76 ;
      RECT 2799.88 0.84 2800.16 2321.76 ;
      RECT 2802.12 0.84 2802.4 2321.76 ;
      RECT 2804.36 0.84 2804.64 2321.76 ;
      RECT 2806.6 0.84 2806.88 2321.76 ;
      RECT 2808.84 0.84 2809.12 2321.76 ;
      RECT 2811.08 0.84 2811.36 2321.76 ;
      RECT 2813.32 0.84 2813.6 2321.76 ;
      RECT 2815.56 0.84 2815.84 2321.76 ;
      RECT 2817.8 0.84 2818.08 2321.76 ;
      RECT 2820.04 0.84 2820.32 2321.76 ;
      RECT 2822.28 0.84 2822.56 2321.76 ;
      RECT 2824.52 0.84 2824.8 2321.76 ;
      RECT 2826.76 0.84 2827.04 2321.76 ;
      RECT 2829 0.84 2829.28 2321.76 ;
      RECT 2831.24 0.84 2831.52 2321.76 ;
      RECT 2833.48 0.84 2833.76 2321.76 ;
      RECT 2835.72 0.84 2836 2321.76 ;
      RECT 2837.96 0.84 2838.24 2321.76 ;
      RECT 2840.2 0.84 2840.48 2321.76 ;
      RECT 2842.44 0.84 2842.72 2321.76 ;
      RECT 2844.68 0.84 2844.96 2321.76 ;
      RECT 2846.92 0.84 2847.2 2321.76 ;
      RECT 2849.16 0.84 2849.44 2321.76 ;
      RECT 2851.4 0.84 2851.68 2321.76 ;
      RECT 2853.64 0.84 2853.92 2321.76 ;
      RECT 2855.88 0.84 2856.16 2321.76 ;
      RECT 2858.12 0.84 2858.4 2321.76 ;
      RECT 2860.36 0.84 2860.64 2321.76 ;
      RECT 2862.6 0.84 2862.88 2321.76 ;
      RECT 2864.84 0.84 2865.12 2321.76 ;
      RECT 2867.08 0.84 2867.36 2321.76 ;
      RECT 2869.32 0.84 2869.6 2321.76 ;
      RECT 2871.56 0.84 2871.84 2321.76 ;
      RECT 2873.8 0.84 2874.08 2321.76 ;
      RECT 2876.04 0.84 2876.32 2321.76 ;
      RECT 2878.28 0.84 2878.56 2321.76 ;
      RECT 2880.52 0.84 2880.8 2321.76 ;
      RECT 2882.76 0.84 2883.04 2321.76 ;
      RECT 2885 0.84 2885.28 2321.76 ;
      RECT 2887.24 0.84 2887.52 2321.76 ;
      RECT 2889.48 0.84 2889.76 2321.76 ;
      RECT 2891.72 0.84 2892 2321.76 ;
      RECT 2893.96 0.84 2894.24 2321.76 ;
      RECT 2896.2 0.84 2896.48 2321.76 ;
      RECT 2898.44 0.84 2898.72 2321.76 ;
      RECT 2900.68 0.84 2900.96 2321.76 ;
      RECT 2902.92 0.84 2903.2 2321.76 ;
      RECT 2905.16 0.84 2905.44 2321.76 ;
      RECT 2907.4 0.84 2907.68 2321.76 ;
      RECT 2909.64 0.84 2909.92 2321.76 ;
      RECT 2911.88 0.84 2912.16 2321.76 ;
      RECT 2914.12 0.84 2914.4 2321.76 ;
      RECT 2916.36 0.84 2916.64 2321.76 ;
      RECT 2918.6 0.84 2918.88 2321.76 ;
      RECT 2920.84 0.84 2921.12 2321.76 ;
      RECT 2923.08 0.84 2923.36 2321.76 ;
      RECT 2925.32 0.84 2925.6 2321.76 ;
      RECT 2927.56 0.84 2927.84 2321.76 ;
      RECT 2929.8 0.84 2930.08 2321.76 ;
      RECT 2932.04 0.84 2932.32 2321.76 ;
      RECT 2934.28 0.84 2934.56 2321.76 ;
      RECT 2936.52 0.84 2936.8 2321.76 ;
      RECT 2938.76 0.84 2939.04 2321.76 ;
      RECT 2941 0.84 2941.28 2321.76 ;
      RECT 2943.24 0.84 2943.52 2321.76 ;
      RECT 2945.48 0.84 2945.76 2321.76 ;
      RECT 2947.72 0.84 2948 2321.76 ;
      RECT 2949.96 0.84 2950.24 2321.76 ;
      RECT 2952.2 0.84 2952.48 2321.76 ;
      RECT 2954.44 0.84 2954.72 2321.76 ;
      RECT 2956.68 0.84 2956.96 2321.76 ;
      RECT 2958.92 0.84 2959.2 2321.76 ;
      RECT 2961.16 0.84 2961.44 2321.76 ;
      RECT 2963.4 0.84 2963.68 2321.76 ;
      RECT 2965.64 0.84 2965.92 2321.76 ;
      RECT 2967.88 0.84 2968.16 2321.76 ;
      RECT 2970.12 0.84 2970.4 2321.76 ;
      RECT 2972.36 0.84 2972.64 2321.76 ;
      RECT 2974.6 0.84 2974.88 2321.76 ;
      RECT 2976.84 0.84 2977.12 2321.76 ;
      RECT 2979.08 0.84 2979.36 2321.76 ;
      RECT 2981.32 0.84 2981.6 2321.76 ;
      RECT 2983.56 0.84 2983.84 2321.76 ;
      RECT 2985.8 0.84 2986.08 2321.76 ;
      RECT 2988.04 0.84 2988.32 2321.76 ;
      RECT 2990.28 0.84 2990.56 2321.76 ;
      RECT 2992.52 0.84 2992.8 2321.76 ;
      RECT 2994.76 0.84 2995.04 2321.76 ;
      RECT 2997 0.84 2997.28 2321.76 ;
      RECT 2999.24 0.84 2999.52 2321.76 ;
      RECT 3001.48 0.84 3001.76 2321.76 ;
      RECT 3003.72 0.84 3004 2321.76 ;
      RECT 3005.96 0.84 3006.24 2321.76 ;
      RECT 3008.2 0.84 3008.48 2321.76 ;
      RECT 3010.44 0.84 3010.72 2321.76 ;
      RECT 3012.68 0.84 3012.96 2321.76 ;
      RECT 3014.92 0.84 3015.2 2321.76 ;
      RECT 3017.16 0.84 3017.44 2321.76 ;
      RECT 3019.4 0.84 3019.68 2321.76 ;
      RECT 3021.64 0.84 3021.92 2321.76 ;
      RECT 3023.88 0.84 3024.16 2321.76 ;
      RECT 3026.12 0.84 3026.4 2321.76 ;
      RECT 3028.36 0.84 3028.64 2321.76 ;
      RECT 3030.6 0.84 3030.88 2321.76 ;
      RECT 3032.84 0.84 3033.12 2321.76 ;
      RECT 3035.08 0.84 3035.36 2321.76 ;
      RECT 3037.32 0.84 3037.6 2321.76 ;
      RECT 3039.56 0.84 3039.84 2321.76 ;
      RECT 3041.8 0.84 3042.08 2321.76 ;
      RECT 3044.04 0.84 3044.32 2321.76 ;
      RECT 3046.28 0.84 3046.56 2321.76 ;
      RECT 3048.52 0.84 3048.8 2321.76 ;
      RECT 3050.76 0.84 3051.04 2321.76 ;
      RECT 3053 0.84 3053.28 2321.76 ;
      RECT 3055.24 0.84 3055.52 2321.76 ;
      RECT 3057.48 0.84 3057.76 2321.76 ;
      RECT 3059.72 0.84 3060 2321.76 ;
      RECT 3061.96 0.84 3062.24 2321.76 ;
      RECT 3064.2 0.84 3064.48 2321.76 ;
      RECT 3066.44 0.84 3066.72 2321.76 ;
      RECT 3068.68 0.84 3068.96 2321.76 ;
      RECT 3070.92 0.84 3071.2 2321.76 ;
      RECT 3073.16 0.84 3073.44 2321.76 ;
      RECT 3075.4 0.84 3075.68 2321.76 ;
      RECT 3077.64 0.84 3077.92 2321.76 ;
      RECT 3079.88 0.84 3080.16 2321.76 ;
      RECT 3082.12 0.84 3082.4 2321.76 ;
      RECT 3084.36 0.84 3084.64 2321.76 ;
      RECT 3086.6 0.84 3086.88 2321.76 ;
      RECT 3088.84 0.84 3089.12 2321.76 ;
      RECT 3091.08 0.84 3091.36 2321.76 ;
      RECT 3093.32 0.84 3093.6 2321.76 ;
      RECT 3095.56 0.84 3095.84 2321.76 ;
      RECT 3097.8 0.84 3098.08 2321.76 ;
      RECT 3100.04 0.84 3100.32 2321.76 ;
      RECT 3102.28 0.84 3102.56 2321.76 ;
      RECT 3104.52 0.84 3104.8 2321.76 ;
      RECT 3106.76 0.84 3107.04 2321.76 ;
      RECT 3109 0.84 3109.28 2321.76 ;
      RECT 3111.24 0.84 3111.52 2321.76 ;
      RECT 3113.48 0.84 3113.76 2321.76 ;
      RECT 3115.72 0.84 3116 2321.76 ;
      RECT 3117.96 0.84 3118.24 2321.76 ;
      RECT 3120.2 0.84 3120.48 2321.76 ;
      RECT 3122.44 0.84 3122.72 2321.76 ;
      RECT 3124.68 0.84 3124.96 2321.76 ;
      RECT 3126.92 0.84 3127.2 2321.76 ;
      RECT 3129.16 0.84 3129.44 2321.76 ;
      RECT 3131.4 0.84 3131.68 2321.76 ;
      RECT 3133.64 0.84 3133.92 2321.76 ;
      RECT 3135.88 0.84 3136.16 2321.76 ;
      RECT 3138.12 0.84 3138.4 2321.76 ;
      RECT 3140.36 0.84 3140.64 2321.76 ;
      RECT 3142.6 0.84 3142.88 2321.76 ;
      RECT 3144.84 0.84 3145.12 2321.76 ;
      RECT 3147.08 0.84 3147.36 2321.76 ;
      RECT 3149.32 0.84 3149.6 2321.76 ;
      RECT 3151.56 0.84 3151.84 2321.76 ;
      RECT 3153.8 0.84 3154.08 2321.76 ;
      RECT 3156.04 0.84 3156.32 2321.76 ;
      RECT 3158.28 0.84 3158.56 2321.76 ;
      RECT 3160.52 0.84 3160.8 2321.76 ;
      RECT 3162.76 0.84 3163.04 2321.76 ;
      RECT 3165 0.84 3165.28 2321.76 ;
      RECT 3167.24 0.84 3167.52 2321.76 ;
      RECT 3169.48 0.84 3169.76 2321.76 ;
      RECT 3171.72 0.84 3172 2321.76 ;
      RECT 3173.96 0.84 3174.24 2321.76 ;
      RECT 3176.2 0.84 3176.48 2321.76 ;
      RECT 3178.44 0.84 3178.72 2321.76 ;
      RECT 3180.68 0.84 3180.96 2321.76 ;
      RECT 3182.92 0.84 3183.2 2321.76 ;
      RECT 3185.16 0.84 3185.44 2321.76 ;
      RECT 3187.4 0.84 3187.68 2321.76 ;
      RECT 3189.64 0.84 3189.92 2321.76 ;
      RECT 3191.88 0.84 3192.16 2321.76 ;
      RECT 3194.12 0.84 3194.4 2321.76 ;
      RECT 3196.36 0.84 3196.64 2321.76 ;
      RECT 3198.6 0.84 3198.88 2321.76 ;
      RECT 3200.84 0.84 3201.12 2321.76 ;
      RECT 3203.08 0.84 3203.36 2321.76 ;
      RECT 3205.32 0.84 3205.6 2321.76 ;
      RECT 3207.56 0.84 3207.84 2321.76 ;
      RECT 3209.8 0.84 3210.08 2321.76 ;
      RECT 3212.04 0.84 3212.32 2321.76 ;
      RECT 3214.28 0.84 3214.56 2321.76 ;
      RECT 3216.52 0.84 3216.8 2321.76 ;
      RECT 3218.76 0.84 3219.04 2321.76 ;
      RECT 3221 0.84 3221.28 2321.76 ;
      RECT 3223.24 0.84 3223.52 2321.76 ;
      RECT 3225.48 0.84 3225.76 2321.76 ;
      RECT 3227.72 0.84 3228 2321.76 ;
      RECT 3229.96 0.84 3230.24 2321.76 ;
      RECT 3232.2 0.84 3232.48 2321.76 ;
      RECT 3234.44 0.84 3234.72 2321.76 ;
      RECT 3236.68 0.84 3236.96 2321.76 ;
      RECT 3238.92 0.84 3239.2 2321.76 ;
      RECT 3241.16 0.84 3241.44 2321.76 ;
      RECT 3243.4 0.84 3243.68 2321.76 ;
      RECT 3245.64 0.84 3245.92 2321.76 ;
      RECT 3247.88 0.84 3248.16 2321.76 ;
      RECT 3250.12 0.84 3250.4 2321.76 ;
      RECT 3252.36 0.84 3252.64 2321.76 ;
      RECT 3254.6 0.84 3254.88 2321.76 ;
      RECT 3256.84 0.84 3257.12 2321.76 ;
      RECT 3259.08 0.84 3259.36 2321.76 ;
      RECT 3261.32 0.84 3261.6 2321.76 ;
      RECT 3263.56 0.84 3263.84 2321.76 ;
      RECT 3265.8 0.84 3266.08 2321.76 ;
      RECT 3268.04 0.84 3268.32 2321.76 ;
      RECT 3270.28 0.84 3270.56 2321.76 ;
      RECT 3272.52 0.84 3272.8 2321.76 ;
      RECT 3274.76 0.84 3275.04 2321.76 ;
      RECT 3277 0.84 3277.28 2321.76 ;
      RECT 3279.24 0.84 3279.52 2321.76 ;
      RECT 3281.48 0.84 3281.76 2321.76 ;
      RECT 3283.72 0.84 3284 2321.76 ;
      RECT 3285.96 0.84 3286.24 2321.76 ;
      RECT 3288.2 0.84 3288.48 2321.76 ;
      RECT 3290.44 0.84 3290.72 2321.76 ;
      RECT 3292.68 0.84 3292.96 2321.76 ;
      RECT 3294.92 0.84 3295.2 2321.76 ;
      RECT 3297.16 0.84 3297.44 2321.76 ;
      RECT 3299.4 0.84 3299.68 2321.76 ;
      RECT 3301.64 0.84 3301.92 2321.76 ;
      RECT 3303.88 0.84 3304.16 2321.76 ;
      RECT 3306.12 0.84 3306.4 2321.76 ;
      RECT 3308.36 0.84 3308.64 2321.76 ;
      RECT 3310.6 0.84 3310.88 2321.76 ;
      RECT 3312.84 0.84 3313.12 2321.76 ;
      RECT 3315.08 0.84 3315.36 2321.76 ;
      RECT 3317.32 0.84 3317.6 2321.76 ;
      RECT 3319.56 0.84 3319.84 2321.76 ;
      RECT 3321.8 0.84 3322.08 2321.76 ;
      RECT 3324.04 0.84 3324.32 2321.76 ;
      RECT 3326.28 0.84 3326.56 2321.76 ;
      RECT 3328.52 0.84 3328.8 2321.76 ;
      RECT 3330.76 0.84 3331.04 2321.76 ;
      RECT 3333 0.84 3333.28 2321.76 ;
      RECT 3335.24 0.84 3335.52 2321.76 ;
      RECT 3337.48 0.84 3337.76 2321.76 ;
      RECT 3339.72 0.84 3340 2321.76 ;
      RECT 3341.96 0.84 3342.24 2321.76 ;
      RECT 3344.2 0.84 3344.48 2321.76 ;
      RECT 3346.44 0.84 3346.72 2321.76 ;
      RECT 3348.68 0.84 3348.96 2321.76 ;
      RECT 3350.92 0.84 3351.2 2321.76 ;
      RECT 3353.16 0.84 3353.44 2321.76 ;
      RECT 3355.4 0.84 3355.68 2321.76 ;
      RECT 3357.64 0.84 3357.92 2321.76 ;
      RECT 3359.88 0.84 3360.16 2321.76 ;
      RECT 3362.12 0.84 3362.4 2321.76 ;
      RECT 3364.36 0.84 3364.64 2321.76 ;
      RECT 3366.6 0.84 3366.88 2321.76 ;
      RECT 3368.84 0.84 3369.12 2321.76 ;
      RECT 3371.08 0.84 3371.36 2321.76 ;
      RECT 3373.32 0.84 3373.6 2321.76 ;
      RECT 3375.56 0.84 3375.84 2321.76 ;
      RECT 3377.8 0.84 3378.08 2321.76 ;
      RECT 3380.04 0.84 3380.32 2321.76 ;
      RECT 3382.28 0.84 3382.56 2321.76 ;
      RECT 3384.52 0.84 3384.8 2321.76 ;
      RECT 3386.76 0.84 3387.04 2321.76 ;
      RECT 3389 0.84 3389.28 2321.76 ;
      RECT 3391.24 0.84 3391.52 2321.76 ;
      RECT 3393.48 0.84 3393.76 2321.76 ;
      RECT 3395.72 0.84 3396 2321.76 ;
      RECT 3397.96 0.84 3398.24 2321.76 ;
      RECT 3400.2 0.84 3400.48 2321.76 ;
      RECT 3402.44 0.84 3402.72 2321.76 ;
      RECT 3404.68 0.84 3404.96 2321.76 ;
      RECT 3406.92 0.84 3407.2 2321.76 ;
      RECT 3409.16 0.84 3409.44 2321.76 ;
      RECT 3411.4 0.84 3411.68 2321.76 ;
      RECT 3413.64 0.84 3413.92 2321.76 ;
      RECT 3415.88 0.84 3416.16 2321.76 ;
      RECT 3418.12 0.84 3418.4 2321.76 ;
      RECT 3420.36 0.84 3420.64 2321.76 ;
      RECT 3422.6 0.84 3422.88 2321.76 ;
      RECT 3424.84 0.84 3425.12 2321.76 ;
      RECT 3427.08 0.84 3427.36 2321.76 ;
      RECT 3429.32 0.84 3429.6 2321.76 ;
      RECT 3431.56 0.84 3431.84 2321.76 ;
      RECT 3433.8 0.84 3434.08 2321.76 ;
      RECT 3436.04 0.84 3436.32 2321.76 ;
      RECT 3438.28 0.84 3438.56 2321.76 ;
      RECT 3440.52 0.84 3440.8 2321.76 ;
      RECT 3442.76 0.84 3443.04 2321.76 ;
      RECT 3445 0.84 3445.28 2321.76 ;
      RECT 3447.24 0.84 3447.52 2321.76 ;
      RECT 3449.48 0.84 3449.76 2321.76 ;
      RECT 3451.72 0.84 3452 2321.76 ;
      RECT 3453.96 0.84 3454.24 2321.76 ;
      RECT 3456.2 0.84 3456.48 2321.76 ;
      RECT 3458.44 0.84 3458.72 2321.76 ;
      RECT 3460.68 0.84 3460.96 2321.76 ;
      RECT 3462.92 0.84 3463.2 2321.76 ;
      RECT 3465.16 0.84 3465.44 2321.76 ;
      RECT 3467.4 0.84 3467.68 2321.76 ;
      RECT 3469.64 0.84 3469.92 2321.76 ;
      RECT 3471.88 0.84 3472.16 2321.76 ;
      RECT 3474.12 0.84 3474.4 2321.76 ;
      RECT 3476.36 0.84 3476.64 2321.76 ;
      RECT 3478.6 0.84 3478.88 2321.76 ;
      RECT 3480.84 0.84 3481.12 2321.76 ;
      RECT 3483.08 0.84 3483.36 2321.76 ;
      RECT 3485.32 0.84 3485.6 2321.76 ;
      RECT 3487.56 0.84 3487.84 2321.76 ;
      RECT 3489.8 0.84 3490.08 2321.76 ;
      RECT 3492.04 0.84 3492.32 2321.76 ;
      RECT 3494.28 0.84 3494.56 2321.76 ;
      RECT 3496.52 0.84 3496.8 2321.76 ;
      RECT 3498.76 0.84 3499.04 2321.76 ;
      RECT 3501 0.84 3501.28 2321.76 ;
      RECT 3503.24 0.84 3503.52 2321.76 ;
      RECT 3505.48 0.84 3505.76 2321.76 ;
      RECT 3507.72 0.84 3508 2321.76 ;
      RECT 3509.96 0.84 3510.24 2321.76 ;
      RECT 3512.2 0.84 3512.48 2321.76 ;
      RECT 3514.44 0.84 3514.72 2321.76 ;
      RECT 3516.68 0.84 3516.96 2321.76 ;
      RECT 3518.92 0.84 3519.2 2321.76 ;
      RECT 3521.16 0.84 3521.44 2321.76 ;
      RECT 3523.4 0.84 3523.68 2321.76 ;
      RECT 3525.64 0.84 3525.92 2321.76 ;
      RECT 3527.88 0.84 3528.16 2321.76 ;
      RECT 3530.12 0.84 3530.4 2321.76 ;
      RECT 3532.36 0.84 3532.64 2321.76 ;
      RECT 3534.6 0.84 3534.88 2321.76 ;
      RECT 3536.84 0.84 3537.12 2321.76 ;
      RECT 3539.08 0.84 3539.36 2321.76 ;
      RECT 3541.32 0.84 3541.6 2321.76 ;
      RECT 3543.56 0.84 3543.84 2321.76 ;
      RECT 3545.8 0.84 3546.08 2321.76 ;
      RECT 3548.04 0.84 3548.32 2321.76 ;
      RECT 3550.28 0.84 3550.56 2321.76 ;
      RECT 3552.52 0.84 3552.8 2321.76 ;
      RECT 3554.76 0.84 3555.04 2321.76 ;
      RECT 3557 0.84 3557.28 2321.76 ;
      RECT 3559.24 0.84 3559.52 2321.76 ;
      RECT 3561.48 0.84 3561.76 2321.76 ;
      RECT 3563.72 0.84 3564 2321.76 ;
      RECT 3565.96 0.84 3566.24 2321.76 ;
      RECT 3568.2 0.84 3568.48 2321.76 ;
      RECT 3570.44 0.84 3570.72 2321.76 ;
      RECT 3572.68 0.84 3572.96 2321.76 ;
      RECT 3574.92 0.84 3575.2 2321.76 ;
      RECT 3577.16 0.84 3577.44 2321.76 ;
      RECT 3579.4 0.84 3579.68 2321.76 ;
      RECT 3581.64 0.84 3581.92 2321.76 ;
      RECT 3583.88 0.84 3584.16 2321.76 ;
      RECT 3586.12 0.84 3586.4 2321.76 ;
      RECT 3588.36 0.84 3588.64 2321.76 ;
      RECT 3590.6 0.84 3590.88 2321.76 ;
      RECT 3592.84 0.84 3593.12 2321.76 ;
      RECT 3595.08 0.84 3595.36 2321.76 ;
      RECT 3597.32 0.84 3597.6 2321.76 ;
      RECT 3599.56 0.84 3599.84 2321.76 ;
      RECT 3601.8 0.84 3602.08 2321.76 ;
      RECT 3604.04 0.84 3604.32 2321.76 ;
      RECT 3606.28 0.84 3606.56 2321.76 ;
      RECT 3608.52 0.84 3608.8 2321.76 ;
      RECT 3610.76 0.84 3611.04 2321.76 ;
      RECT 3613 0.84 3613.28 2321.76 ;
      RECT 3615.24 0.84 3615.52 2321.76 ;
      RECT 3617.48 0.84 3617.76 2321.76 ;
      RECT 3619.72 0.84 3620 2321.76 ;
      RECT 3621.96 0.84 3622.24 2321.76 ;
      RECT 3624.2 0.84 3624.48 2321.76 ;
      RECT 3626.44 0.84 3626.72 2321.76 ;
      RECT 3628.68 0.84 3628.96 2321.76 ;
      RECT 3630.92 0.84 3631.2 2321.76 ;
      RECT 3633.16 0.84 3633.44 2321.76 ;
      RECT 3635.4 0.84 3635.68 2321.76 ;
      RECT 3637.64 0.84 3637.92 2321.76 ;
      RECT 3639.88 0.84 3640.16 2321.76 ;
      RECT 3642.12 0.84 3642.4 2321.76 ;
      RECT 3644.36 0.84 3644.64 2321.76 ;
      RECT 3646.6 0.84 3646.88 2321.76 ;
      RECT 3648.84 0.84 3649.12 2321.76 ;
      RECT 3651.08 0.84 3651.36 2321.76 ;
      RECT 3653.32 0.84 3653.6 2321.76 ;
      RECT 3655.56 0.84 3655.84 2321.76 ;
      RECT 3657.8 0.84 3658.08 2321.76 ;
    END
  END VDD
  OBS
    LAYER M1_m ;
    RECT 0 0 3659.59 2322.6 ;
    LAYER M2_m ;
    RECT 0 0 3659.59 2322.6 ;
  END
END ht45_mempoolgroup_512x16384_upper

END LIBRARY
